<?xml version="1.0" encoding="utf-8" standalone="no"?>
<device schemaVersion="1.1" xmlns:xs="http://www.w3.org/2001/XMLSchema-instance" noNamespaceSchemaLocation="CMSIS-SVD.xsd">
  <vendor>Puya</vendor>
  <vendorID>Puya</vendorID>
  <name>PY32T090xx</name>
  <series>PY32T0</series>
  <version>1.0.0</version>
  <description>Arm 32-bit Cortex-M0+ Microcontroller based device, CPU clock up to 48 MHz.</description>
  <cpu>
    <name>CM0+</name>
    <revision>r0p1</revision>
    <endian>little</endian>
    <mpuPresent>false</mpuPresent>
    <fpuPresent>false</fpuPresent>
    <nvicPrioBits>4</nvicPrioBits>
    <vendorSystickConfig>false</vendorSystickConfig>
  </cpu>
  <addressUnitBits>8</addressUnitBits>
  <width>32</width>
  <size>32</size>
  <access>read-write</access>
  <resetValue>0x0</resetValue>
  <resetMask>0xFFFFFFFF</resetMask>
  <peripherals>
    <peripheral>
      <name>ADC</name>
      <description>Analog to Digital Converter</description>
      <baseAddress>0x40012400</baseAddress>
      <addressBlock>
        <offset>0x0</offset>
        <size>0x400</size>
        <usage>registers</usage>
      </addressBlock>
      <interrupt>
        <name>ADC_COMP</name>
        <description>ADC and COMP Interrupt through EXTI Lines 17 and 18</description>
        <value>12</value>
      </interrupt>
      <registers>
        <register>
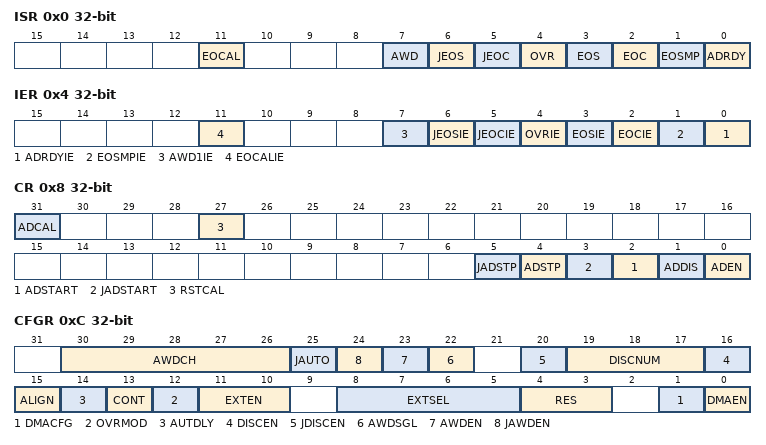
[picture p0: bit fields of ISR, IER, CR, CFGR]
          <name>ISR</name>
          <addressOffset>0x0</addressOffset>
          <fields>
            <field>
              <name>ADRDY</name>
              <bitRange>[0:0]</bitRange>
            </field>
            <field>
              <name>EOSMP</name>
              <bitRange>[1:1]</bitRange>
            </field>
            <field>
              <name>EOC</name>
              <bitRange>[2:2]</bitRange>
            </field>
            <field>
              <name>EOS</name>
              <bitRange>[3:3]</bitRange>
            </field>
            <field>
              <name>OVR</name>
              <bitRange>[4:4]</bitRange>
            </field>
            <field>
              <name>JEOC</name>
              <bitRange>[5:5]</bitRange>
            </field>
            <field>
              <name>JEOS</name>
              <bitRange>[6:6]</bitRange>
            </field>
            <field>
              <name>AWD</name>
              <bitRange>[7:7]</bitRange>
            </field>
             <field>
              <name>EOCAL</name>
              <bitRange>[11:11]</bitRange>
            </field>           
          </fields>
        </register>
        <register>
          <name>IER</name>
          <addressOffset>0x4</addressOffset>
          <fields>
            <field>
              <name>ADRDYIE</name>
              <bitRange>[0:0]</bitRange>
            </field>
            <field>
              <name>EOSMPIE</name>
              <bitRange>[1:1]</bitRange>
            </field>
            <field>
              <name>EOCIE</name>
              <bitRange>[2:2]</bitRange>
            </field>
            <field>
              <name>EOSIE</name>
              <bitRange>[3:3]</bitRange>
            </field>
            <field>
              <name>OVRIE</name>
              <bitRange>[4:4]</bitRange>
            </field>
            <field>
              <name>JEOCIE</name>
              <bitRange>[5:5]</bitRange>
            </field>
            <field>
              <name>JEOSIE</name>
              <bitRange>[6:6]</bitRange>
            </field>
            <field>
              <name>AWD1IE</name>
              <bitRange>[7:7]</bitRange>
            </field>
            <field>
              <name>EOCALIE</name>
              <bitRange>[11:11]</bitRange>
            </field>
          </fields>
        </register>
        <register>
          <name>CR</name>
          <addressOffset>0x8</addressOffset>
          <fields>
            <field>
              <name>ADEN</name>
              <bitRange>[0:0]</bitRange>
            </field>
            <field>
              <name>ADDIS</name>
              <bitRange>[1:1]</bitRange>
            </field>
            <field>
              <name>ADSTART</name>
              <bitRange>[2:2]</bitRange>
            </field>
            <field>
              <name>JADSTART</name>
              <bitRange>[3:3]</bitRange>
            </field>
            <field>
              <name>ADSTP</name>
              <bitRange>[4:4]</bitRange>
            </field>
            <field>
              <name>JADSTP</name>
              <bitRange>[5:5]</bitRange>
            </field>
            <field>
              <name>RSTCAL</name>
              <bitRange>[27:27]</bitRange>
            </field>
            <field>
              <name>ADCAL</name>
              <bitRange>[31:31]</bitRange>
            </field>
          </fields>
        </register>
        <register>
          <name>CFGR</name>
          <addressOffset>0xC</addressOffset>
          <fields>
            <field>
              <name>DMAEN</name>
              <bitRange>[0:0]</bitRange>
            </field>
            <field>
              <name>DMACFG</name>
              <bitRange>[1:1]</bitRange>
            </field>
            <field>
              <name>RES</name>
              <bitRange>[4:3]</bitRange>
              <enumeratedValues>
                <enumeratedValue>
                  <name>0</name>
                  <value>1</value>
                </enumeratedValue>
                <enumeratedValue>
                  <name>1</name>
                  <value>2</value>
                </enumeratedValue>
              </enumeratedValues>
            </field>
            <field>
              <name>EXTSEL</name>
              <bitRange>[8:5]</bitRange>
              <enumeratedValues>
                <enumeratedValue>
                  <name>0</name>
                  <value>1</value>
                </enumeratedValue>
                <enumeratedValue>
                  <name>1</name>
                  <value>2</value>
                </enumeratedValue>
                <enumeratedValue>
                  <name>2</name>
                  <value>4</value>
                </enumeratedValue>
                <enumeratedValue>
                  <name>3</name>
                  <value>8</value>
                </enumeratedValue>
              </enumeratedValues>
            </field>
            <field>
              <name>EXTEN</name>
              <bitRange>[11:10]</bitRange>
              <enumeratedValues>
                <enumeratedValue>
                  <name>0</name>
                  <value>1</value>
                </enumeratedValue>
                <enumeratedValue>
                  <name>1</name>
                  <value>2</value>
                </enumeratedValue>
              </enumeratedValues>
            </field>
            <field>
              <name>OVRMOD</name>
              <bitRange>[12:12]</bitRange>
            </field>
            <field>
              <name>CONT</name>
              <bitRange>[13:13]</bitRange>
            </field>
            <field>
              <name>AUTDLY</name>
              <bitRange>[14:14]</bitRange>
            </field>
            <field>
              <name>ALIGN</name>
              <bitRange>[15:15]</bitRange>
            </field>
            <field>
              <name>DISCEN</name>
              <bitRange>[16:16]</bitRange>
            </field>
            <field>
              <name>DISCNUM</name>
              <bitRange>[19:17]</bitRange>
              <enumeratedValues>
                <enumeratedValue>
                  <name>0</name>
                  <value>1</value>
                </enumeratedValue>
                <enumeratedValue>
                  <name>1</name>
                  <value>2</value>
                </enumeratedValue>
                <enumeratedValue>
                  <name>2</name>
                  <value>4</value>
                </enumeratedValue>
              </enumeratedValues>
            </field>
            <field>
              <name>JDISCEN</name>
              <bitRange>[20:20]</bitRange>
            </field>
            <field>
              <name>AWDSGL</name>
              <bitRange>[22:22]</bitRange>
            </field>
            <field>
              <name>AWDEN</name>
              <bitRange>[23:23]</bitRange>
            </field>
            <field>
              <name>JAWDEN</name>
              <bitRange>[24:24]</bitRange>
            </field>
            <field>
              <name>JAUTO</name>
              <bitRange>[25:25]</bitRange>
            </field>
            <field>
              <name>AWDCH</name>
              <bitRange>[30:26]</bitRange>
            </field>
          </fields>
        </register>
        <register>
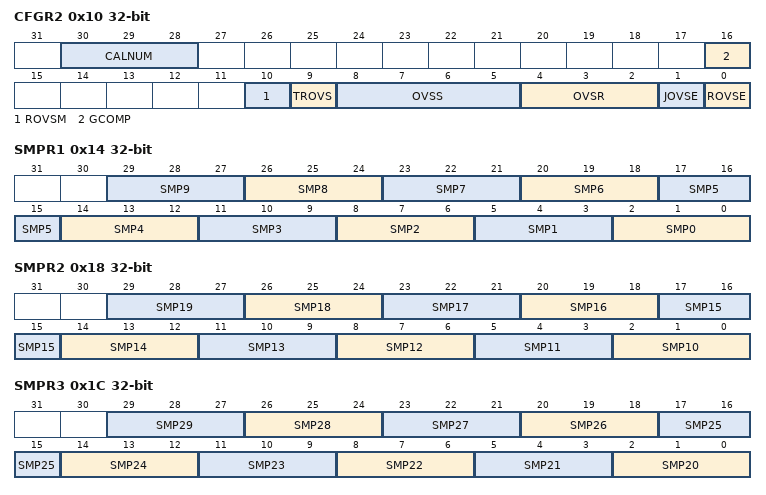
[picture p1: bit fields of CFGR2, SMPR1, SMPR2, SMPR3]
          <name>CFGR2</name>
          <addressOffset>0x10</addressOffset>
          <fields>
            <field>
              <name>ROVSE</name>
              <bitRange>[0:0]</bitRange>
            </field>
            <field>
              <name>JOVSE</name>
              <bitRange>[1:1]</bitRange>
            </field>
            <field>
              <name>OVSR</name>
              <bitRange>[4:2]</bitRange>
              <enumeratedValues>
                <enumeratedValue>
                  <name>0</name>
                  <value>1</value>
                </enumeratedValue>
                <enumeratedValue>
                  <name>1</name>
                  <value>2</value>
                </enumeratedValue>
                <enumeratedValue>
                  <name>2</name>
                  <value>4</value>
                </enumeratedValue>
              </enumeratedValues>
            </field>
            <field>
              <name>OVSS</name>
              <bitRange>[8:5]</bitRange>
              <enumeratedValues>
                <enumeratedValue>
                  <name>0</name>
                  <value>1</value>
                </enumeratedValue>
                <enumeratedValue>
                  <name>1</name>
                  <value>2</value>
                </enumeratedValue>
                <enumeratedValue>
                  <name>2</name>
                  <value>4</value>
                </enumeratedValue>
                <enumeratedValue>
                  <name>3</name>
                  <value>8</value>
                </enumeratedValue>
              </enumeratedValues>
            </field>
            <field>
              <name>TROVS</name>
              <bitRange>[9:9]</bitRange>
            </field>
            <field>
              <name>ROVSM</name>
              <bitRange>[10:10]</bitRange>
            </field>
            <field>
              <name>GCOMP</name>
              <bitRange>[16:16]</bitRange>
            </field>
            <field>
              <name>CALNUM</name>
              <bitRange>[30:28]</bitRange>
              <enumeratedValues>
                <enumeratedValue>
                  <name>0</name>
                  <value>1</value>
                </enumeratedValue>
                <enumeratedValue>
                  <name>1</name>
                  <value>2</value>
                </enumeratedValue>
                <enumeratedValue>
                  <name>2</name>
                  <value>4</value>
                </enumeratedValue>
              </enumeratedValues>
            </field>
          </fields>
        </register>
        <register>
          <name>SMPR1</name>
          <description>desc SMPR1</description>
          <addressOffset>0x14</addressOffset>
          <fields>
            <field>
              <name>SMP0</name>
              <bitRange>[2:0]</bitRange>
              <enumeratedValues>
                <enumeratedValue>
                  <name>0</name>
                  <value>1</value>
                </enumeratedValue>
                <enumeratedValue>
                  <name>1</name>
                  <value>2</value>
                </enumeratedValue>
                <enumeratedValue>
                  <name>2</name>
                  <value>4</value>
                </enumeratedValue>
              </enumeratedValues>
            </field>
            <field>
              <name>SMP1</name>
              <bitRange>[5:3]</bitRange>
              <enumeratedValues>
                <enumeratedValue>
                  <name>0</name>
                  <value>1</value>
                </enumeratedValue>
                <enumeratedValue>
                  <name>1</name>
                  <value>2</value>
                </enumeratedValue>
                <enumeratedValue>
                  <name>2</name>
                  <value>4</value>
                </enumeratedValue>
              </enumeratedValues>
            </field>
            <field>
              <name>SMP2</name>
              <bitRange>[8:6]</bitRange>
              <enumeratedValues>
                <enumeratedValue>
                  <name>0</name>
                  <value>1</value>
                </enumeratedValue>
                <enumeratedValue>
                  <name>1</name>
                  <value>2</value>
                </enumeratedValue>
                <enumeratedValue>
                  <name>2</name>
                  <value>4</value>
                </enumeratedValue>
              </enumeratedValues>
            </field>
            <field>
              <name>SMP3</name>
              <bitRange>[11:9]</bitRange>
              <enumeratedValues>
                <enumeratedValue>
                  <name>0</name>
                  <value>1</value>
                </enumeratedValue>
                <enumeratedValue>
                  <name>1</name>
                  <value>2</value>
                </enumeratedValue>
                <enumeratedValue>
                  <name>2</name>
                  <value>4</value>
                </enumeratedValue>
              </enumeratedValues>
            </field>
            <field>
              <name>SMP4</name>
              <bitRange>[14:12]</bitRange>
              <enumeratedValues>
                <enumeratedValue>
                  <name>0</name>
                  <value>1</value>
                </enumeratedValue>
                <enumeratedValue>
                  <name>1</name>
                  <value>2</value>
                </enumeratedValue>
                <enumeratedValue>
                  <name>2</name>
                  <value>4</value>
                </enumeratedValue>
              </enumeratedValues>
            </field>
            <field>
              <name>SMP5</name>
              <bitRange>[17:15]</bitRange>
              <enumeratedValues>
                <enumeratedValue>
                  <name>0</name>
                  <value>1</value>
                </enumeratedValue>
                <enumeratedValue>
                  <name>1</name>
                  <value>2</value>
                </enumeratedValue>
                <enumeratedValue>
                  <name>2</name>
                  <value>4</value>
                </enumeratedValue>
              </enumeratedValues>
            </field>
            <field>
              <name>SMP6</name>
              <bitRange>[20:18]</bitRange>
              <enumeratedValues>
                <enumeratedValue>
                  <name>0</name>
                  <value>1</value>
                </enumeratedValue>
                <enumeratedValue>
                  <name>1</name>
                  <value>2</value>
                </enumeratedValue>
                <enumeratedValue>
                  <name>2</name>
                  <value>4</value>
                </enumeratedValue>
              </enumeratedValues>
            </field>
            <field>
              <name>SMP7</name>
              <bitRange>[23:21]</bitRange>
              <enumeratedValues>
                <enumeratedValue>
                  <name>0</name>
                  <value>1</value>
                </enumeratedValue>
                <enumeratedValue>
                  <name>1</name>
                  <value>2</value>
                </enumeratedValue>
                <enumeratedValue>
                  <name>2</name>
                  <value>4</value>
                </enumeratedValue>
              </enumeratedValues>
            </field>
            <field>
              <name>SMP8</name>
              <bitRange>[26:24]</bitRange>
              <enumeratedValues>
                <enumeratedValue>
                  <name>0</name>
                  <value>1</value>
                </enumeratedValue>
                <enumeratedValue>
                  <name>1</name>
                  <value>2</value>
                </enumeratedValue>
                <enumeratedValue>
                  <name>2</name>
                  <value>4</value>
                </enumeratedValue>
              </enumeratedValues>
            </field>
            <field>
              <name>SMP9</name>
              <bitRange>[29:27]</bitRange>
              <enumeratedValues>
                <enumeratedValue>
                  <name>0</name>
                  <value>1</value>
                </enumeratedValue>
                <enumeratedValue>
                  <name>1</name>
                  <value>2</value>
                </enumeratedValue>
                <enumeratedValue>
                  <name>2</name>
                  <value>4</value>
                </enumeratedValue>
              </enumeratedValues>
            </field>
          </fields>
        </register>
        <register>
          <name>SMPR2</name>
          <description>desc SMPR2</description>
          <addressOffset>0x18</addressOffset>
          <fields>
            <field>
              <name>SMP10</name>
              <bitRange>[2:0]</bitRange>
              <enumeratedValues>
                <enumeratedValue>
                  <name>0</name>
                  <value>1</value>
                </enumeratedValue>
                <enumeratedValue>
                  <name>1</name>
                  <value>2</value>
                </enumeratedValue>
                <enumeratedValue>
                  <name>2</name>
                  <value>4</value>
                </enumeratedValue>
              </enumeratedValues>
            </field>
            <field>
              <name>SMP11</name>
              <bitRange>[5:3]</bitRange>
              <enumeratedValues>
                <enumeratedValue>
                  <name>0</name>
                  <value>1</value>
                </enumeratedValue>
                <enumeratedValue>
                  <name>1</name>
                  <value>2</value>
                </enumeratedValue>
                <enumeratedValue>
                  <name>2</name>
                  <value>4</value>
                </enumeratedValue>
              </enumeratedValues>
            </field>
            <field>
              <name>SMP12</name>
              <bitRange>[8:6]</bitRange>
              <enumeratedValues>
                <enumeratedValue>
                  <name>0</name>
                  <value>1</value>
                </enumeratedValue>
                <enumeratedValue>
                  <name>1</name>
                  <value>2</value>
                </enumeratedValue>
                <enumeratedValue>
                  <name>2</name>
                  <value>4</value>
                </enumeratedValue>
              </enumeratedValues>
            </field>
            <field>
              <name>SMP13</name>
              <bitRange>[11:9]</bitRange>
              <enumeratedValues>
                <enumeratedValue>
                  <name>0</name>
                  <value>1</value>
                </enumeratedValue>
                <enumeratedValue>
                  <name>1</name>
                  <value>2</value>
                </enumeratedValue>
                <enumeratedValue>
                  <name>2</name>
                  <value>4</value>
                </enumeratedValue>
              </enumeratedValues>
            </field>
            <field>
              <name>SMP14</name>
              <bitRange>[14:12]</bitRange>
              <enumeratedValues>
                <enumeratedValue>
                  <name>0</name>
                  <value>1</value>
                </enumeratedValue>
                <enumeratedValue>
                  <name>1</name>
                  <value>2</value>
                </enumeratedValue>
                <enumeratedValue>
                  <name>2</name>
                  <value>4</value>
                </enumeratedValue>
              </enumeratedValues>
            </field>
            <field>
              <name>SMP15</name>
              <bitRange>[17:15]</bitRange>
              <enumeratedValues>
                <enumeratedValue>
                  <name>0</name>
                  <value>1</value>
                </enumeratedValue>
                <enumeratedValue>
                  <name>1</name>
                  <value>2</value>
                </enumeratedValue>
                <enumeratedValue>
                  <name>2</name>
                  <value>4</value>
                </enumeratedValue>
              </enumeratedValues>
            </field>
            <field>
              <name>SMP16</name>
              <bitRange>[20:18]</bitRange>
              <enumeratedValues>
                <enumeratedValue>
                  <name>0</name>
                  <value>1</value>
                </enumeratedValue>
                <enumeratedValue>
                  <name>1</name>
                  <value>2</value>
                </enumeratedValue>
                <enumeratedValue>
                  <name>2</name>
                  <value>4</value>
                </enumeratedValue>
              </enumeratedValues>
            </field>
            <field>
              <name>SMP17</name>
              <bitRange>[23:21]</bitRange>
              <enumeratedValues>
                <enumeratedValue>
                  <name>0</name>
                  <value>1</value>
                </enumeratedValue>
                <enumeratedValue>
                  <name>1</name>
                  <value>2</value>
                </enumeratedValue>
                <enumeratedValue>
                  <name>2</name>
                  <value>4</value>
                </enumeratedValue>
              </enumeratedValues>
            </field>
            <field>
              <name>SMP18</name>
              <bitRange>[26:24]</bitRange>
              <enumeratedValues>
                <enumeratedValue>
                  <name>0</name>
                  <value>1</value>
                </enumeratedValue>
                <enumeratedValue>
                  <name>1</name>
                  <value>2</value>
                </enumeratedValue>
                <enumeratedValue>
                  <name>2</name>
                  <value>4</value>
                </enumeratedValue>
              </enumeratedValues>
            </field>
            <field>
              <name>SMP19</name>
              <bitRange>[29:27]</bitRange>
              <enumeratedValues>
                <enumeratedValue>
                  <name>0</name>
                  <value>1</value>
                </enumeratedValue>
                <enumeratedValue>
                  <name>1</name>
                  <value>2</value>
                </enumeratedValue>
                <enumeratedValue>
                  <name>2</name>
                  <value>4</value>
                </enumeratedValue>
              </enumeratedValues>
            </field>
          </fields>
        </register>
        <register>
          <name>SMPR3</name>
          <description>desc SMPR2</description>
          <addressOffset>0x1C</addressOffset>
          <fields>
            <field>
              <name>SMP20</name>
              <bitRange>[2:0]</bitRange>
              <enumeratedValues>
                <enumeratedValue>
                  <name>0</name>
                  <value>1</value>
                </enumeratedValue>
                <enumeratedValue>
                  <name>1</name>
                  <value>2</value>
                </enumeratedValue>
                <enumeratedValue>
                  <name>2</name>
                  <value>4</value>
                </enumeratedValue>
              </enumeratedValues>
            </field>
            <field>
              <name>SMP21</name>
              <bitRange>[5:3]</bitRange>
              <enumeratedValues>
                <enumeratedValue>
                  <name>0</name>
                  <value>1</value>
                </enumeratedValue>
                <enumeratedValue>
                  <name>1</name>
                  <value>2</value>
                </enumeratedValue>
                <enumeratedValue>
                  <name>2</name>
                  <value>4</value>
                </enumeratedValue>
              </enumeratedValues>
            </field>
            <field>
              <name>SMP22</name>
              <bitRange>[8:6]</bitRange>
              <enumeratedValues>
                <enumeratedValue>
                  <name>0</name>
                  <value>1</value>
                </enumeratedValue>
                <enumeratedValue>
                  <name>1</name>
                  <value>2</value>
                </enumeratedValue>
                <enumeratedValue>
                  <name>2</name>
                  <value>4</value>
                </enumeratedValue>
              </enumeratedValues>
            </field>
            <field>
              <name>SMP23</name>
              <bitRange>[11:9]</bitRange>
              <enumeratedValues>
                <enumeratedValue>
                  <name>0</name>
                  <value>1</value>
                </enumeratedValue>
                <enumeratedValue>
                  <name>1</name>
                  <value>2</value>
                </enumeratedValue>
                <enumeratedValue>
                  <name>2</name>
                  <value>4</value>
                </enumeratedValue>
              </enumeratedValues>
            </field>
            <field>
              <name>SMP24</name>
              <bitRange>[14:12]</bitRange>
              <enumeratedValues>
                <enumeratedValue>
                  <name>0</name>
                  <value>1</value>
                </enumeratedValue>
                <enumeratedValue>
                  <name>1</name>
                  <value>2</value>
                </enumeratedValue>
                <enumeratedValue>
                  <name>2</name>
                  <value>4</value>
                </enumeratedValue>
              </enumeratedValues>
            </field>
            <field>
              <name>SMP25</name>
              <bitRange>[17:15]</bitRange>
              <enumeratedValues>
                <enumeratedValue>
                  <name>0</name>
                  <value>1</value>
                </enumeratedValue>
                <enumeratedValue>
                  <name>1</name>
                  <value>2</value>
                </enumeratedValue>
                <enumeratedValue>
                  <name>2</name>
                  <value>4</value>
                </enumeratedValue>
              </enumeratedValues>
            </field>
            <field>
              <name>SMP26</name>
              <bitRange>[20:18]</bitRange>
              <enumeratedValues>
                <enumeratedValue>
                  <name>0</name>
                  <value>1</value>
                </enumeratedValue>
                <enumeratedValue>
                  <name>1</name>
                  <value>2</value>
                </enumeratedValue>
                <enumeratedValue>
                  <name>2</name>
                  <value>4</value>
                </enumeratedValue>
              </enumeratedValues>
            </field>
            <field>
              <name>SMP27</name>
              <bitRange>[23:21]</bitRange>
              <enumeratedValues>
                <enumeratedValue>
                  <name>0</name>
                  <value>1</value>
                </enumeratedValue>
                <enumeratedValue>
                  <name>1</name>
                  <value>2</value>
                </enumeratedValue>
                <enumeratedValue>
                  <name>2</name>
                  <value>4</value>
                </enumeratedValue>
              </enumeratedValues>
            </field>
            <field>
              <name>SMP28</name>
              <bitRange>[26:24]</bitRange>
              <enumeratedValues>
                <enumeratedValue>
                  <name>0</name>
                  <value>1</value>
                </enumeratedValue>
                <enumeratedValue>
                  <name>1</name>
                  <value>2</value>
                </enumeratedValue>
                <enumeratedValue>
                  <name>2</name>
                  <value>4</value>
                </enumeratedValue>
              </enumeratedValues>
            </field>
            <field>
              <name>SMP29</name>
              <bitRange>[29:27]</bitRange>
              <enumeratedValues>
                <enumeratedValue>
                  <name>0</name>
                  <value>1</value>
                </enumeratedValue>
                <enumeratedValue>
                  <name>1</name>
                  <value>2</value>
                </enumeratedValue>
                <enumeratedValue>
                  <name>2</name>
                  <value>4</value>
                </enumeratedValue>
              </enumeratedValues>
            </field>
          </fields>
        </register>
        <register>
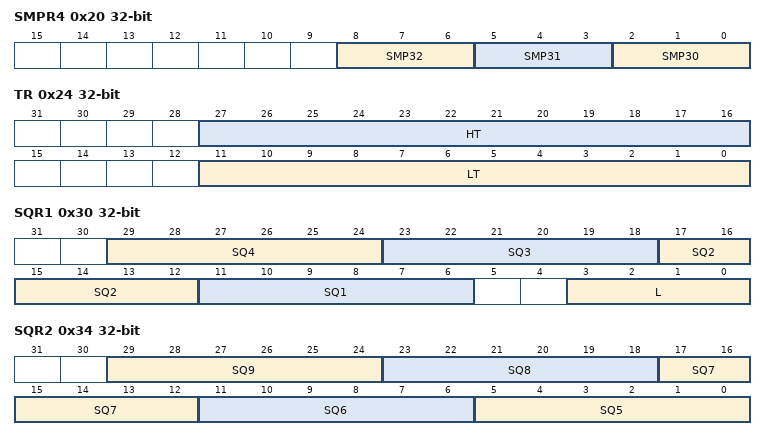
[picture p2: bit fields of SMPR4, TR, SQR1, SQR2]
          <name>SMPR4</name>
          <addressOffset>0x20</addressOffset>
          <fields>
            <field>
              <name>SMP30</name>
              <bitRange>[2:0]</bitRange>
              <enumeratedValues>
                <enumeratedValue>
                  <name>0</name>
                  <value>1</value>
                </enumeratedValue>
                <enumeratedValue>
                  <name>1</name>
                  <value>2</value>
                </enumeratedValue>
                <enumeratedValue>
                  <name>2</name>
                  <value>4</value>
                </enumeratedValue>
              </enumeratedValues>
            </field>
            <field>
              <name>SMP31</name>
              <bitRange>[5:3]</bitRange>
              <enumeratedValues>
                <enumeratedValue>
                  <name>0</name>
                  <value>1</value>
                </enumeratedValue>
                <enumeratedValue>
                  <name>1</name>
                  <value>2</value>
                </enumeratedValue>
                <enumeratedValue>
                  <name>2</name>
                  <value>4</value>
                </enumeratedValue>
              </enumeratedValues>
            </field>
            <field>
              <name>SMP32</name>
              <bitRange>[8:6]</bitRange>
            </field>
          </fields>
        </register>
        <register>
          <name>TR</name>
          <addressOffset>0x24</addressOffset>
          <fields>
            <field>
              <name>LT</name>
              <bitRange>[11:0]</bitRange>
            </field>
            <field>
              <name>HT</name>
              <bitRange>[27:16]</bitRange>
            </field>
          </fields>
        </register>
        <register>
          <name>SQR1</name>
          <description>desc SQR1</description>
          <addressOffset>0x30</addressOffset>
          <fields>
            <field>
              <name>L</name>
              <bitRange>[3:0]</bitRange>
              <enumeratedValues>
                <enumeratedValue>
                  <name>0</name>
                  <value>1</value>
                </enumeratedValue>
                <enumeratedValue>
                  <name>1</name>
                  <value>2</value>
                </enumeratedValue>
                <enumeratedValue>
                  <name>2</name>
                  <value>4</value>
                </enumeratedValue>
                <enumeratedValue>
                  <name>3</name>
                  <value>8</value>
                </enumeratedValue>
              </enumeratedValues>
            </field>
            <field>
              <name>SQ1</name>
              <bitRange>[11:6]</bitRange>
              <enumeratedValues>
                <enumeratedValue>
                  <name>0</name>
                  <value>1</value>
                </enumeratedValue>
                <enumeratedValue>
                  <name>1</name>
                  <value>2</value>
                </enumeratedValue>
                <enumeratedValue>
                  <name>2</name>
                  <value>4</value>
                </enumeratedValue>
                <enumeratedValue>
                  <name>3</name>
                  <value>8</value>
                </enumeratedValue>
                <enumeratedValue>
                  <name>4</name>
                  <value>16</value>
                </enumeratedValue>
                <enumeratedValue>
                  <name>5</name>
                  <value>32</value>
                </enumeratedValue>
              </enumeratedValues>
            </field>
            <field>
              <name>SQ2</name>
              <bitRange>[17:12]</bitRange>
              <enumeratedValues>
                <enumeratedValue>
                  <name>0</name>
                  <value>1</value>
                </enumeratedValue>
                <enumeratedValue>
                  <name>1</name>
                  <value>2</value>
                </enumeratedValue>
                <enumeratedValue>
                  <name>2</name>
                  <value>4</value>
                </enumeratedValue>
                <enumeratedValue>
                  <name>3</name>
                  <value>8</value>
                </enumeratedValue>
                <enumeratedValue>
                  <name>4</name>
                  <value>16</value>
                </enumeratedValue>
                <enumeratedValue>
                  <name>5</name>
                  <value>32</value>
                </enumeratedValue>
              </enumeratedValues>
            </field>
            <field>
              <name>SQ3</name>
              <bitRange>[23:18]</bitRange>
              <enumeratedValues>
                <enumeratedValue>
                  <name>0</name>
                  <value>1</value>
                </enumeratedValue>
                <enumeratedValue>
                  <name>1</name>
                  <value>2</value>
                </enumeratedValue>
                <enumeratedValue>
                  <name>2</name>
                  <value>4</value>
                </enumeratedValue>
                <enumeratedValue>
                  <name>3</name>
                  <value>8</value>
                </enumeratedValue>
                <enumeratedValue>
                  <name>4</name>
                  <value>16</value>
                </enumeratedValue>
                <enumeratedValue>
                  <name>5</name>
                  <value>32</value>
                </enumeratedValue>
              </enumeratedValues>
            </field>
            <field>
              <name>SQ4</name>
              <bitRange>[29:24]</bitRange>
              <enumeratedValues>
                <enumeratedValue>
                  <name>0</name>
                  <value>1</value>
                </enumeratedValue>
                <enumeratedValue>
                  <name>1</name>
                  <value>2</value>
                </enumeratedValue>
                <enumeratedValue>
                  <name>2</name>
                  <value>4</value>
                </enumeratedValue>
                <enumeratedValue>
                  <name>3</name>
                  <value>8</value>
                </enumeratedValue>
                <enumeratedValue>
                  <name>4</name>
                  <value>16</value>
                </enumeratedValue>
                <enumeratedValue>
                  <name>5</name>
                  <value>32</value>
                </enumeratedValue>
              </enumeratedValues>
            </field>
          </fields>
        </register>
        <register>
          <name>SQR2</name>
          <description>desc SQR2</description>
          <addressOffset>0x34</addressOffset>
          <fields>
            <field>
              <name>SQ5</name>
              <bitRange>[5:0]</bitRange>
              <enumeratedValues>
                <enumeratedValue>
                  <name>0</name>
                  <value>1</value>
                </enumeratedValue>
                <enumeratedValue>
                  <name>1</name>
                  <value>2</value>
                </enumeratedValue>
                <enumeratedValue>
                  <name>2</name>
                  <value>4</value>
                </enumeratedValue>
                <enumeratedValue>
                  <name>3</name>
                  <value>8</value>
                </enumeratedValue>
                <enumeratedValue>
                  <name>4</name>
                  <value>16</value>
                </enumeratedValue>
                <enumeratedValue>
                  <name>5</name>
                  <value>32</value>
                </enumeratedValue>
              </enumeratedValues>
            </field>
            <field>
              <name>SQ6</name>
              <bitRange>[11:6]</bitRange>
              <enumeratedValues>
                <enumeratedValue>
                  <name>0</name>
                  <value>1</value>
                </enumeratedValue>
                <enumeratedValue>
                  <name>1</name>
                  <value>2</value>
                </enumeratedValue>
                <enumeratedValue>
                  <name>2</name>
                  <value>4</value>
                </enumeratedValue>
                <enumeratedValue>
                  <name>3</name>
                  <value>8</value>
                </enumeratedValue>
                <enumeratedValue>
                  <name>4</name>
                  <value>16</value>
                </enumeratedValue>
                <enumeratedValue>
                  <name>5</name>
                  <value>32</value>
                </enumeratedValue>
              </enumeratedValues>
            </field>
            <field>
              <name>SQ7</name>
              <bitRange>[17:12]</bitRange>
              <enumeratedValues>
                <enumeratedValue>
                  <name>0</name>
                  <value>1</value>
                </enumeratedValue>
                <enumeratedValue>
                  <name>1</name>
                  <value>2</value>
                </enumeratedValue>
                <enumeratedValue>
                  <name>2</name>
                  <value>4</value>
                </enumeratedValue>
                <enumeratedValue>
                  <name>3</name>
                  <value>8</value>
                </enumeratedValue>
                <enumeratedValue>
                  <name>4</name>
                  <value>16</value>
                </enumeratedValue>
                <enumeratedValue>
                  <name>5</name>
                  <value>32</value>
                </enumeratedValue>
              </enumeratedValues>
            </field>
            <field>
              <name>SQ8</name>
              <bitRange>[23:18]</bitRange>
              <enumeratedValues>
                <enumeratedValue>
                  <name>0</name>
                  <value>1</value>
                </enumeratedValue>
                <enumeratedValue>
                  <name>1</name>
                  <value>2</value>
                </enumeratedValue>
                <enumeratedValue>
                  <name>2</name>
                  <value>4</value>
                </enumeratedValue>
                <enumeratedValue>
                  <name>3</name>
                  <value>8</value>
                </enumeratedValue>
                <enumeratedValue>
                  <name>4</name>
                  <value>16</value>
                </enumeratedValue>
                <enumeratedValue>
                  <name>5</name>
                  <value>32</value>
                </enumeratedValue>
              </enumeratedValues>
            </field>
            <field>
              <name>SQ9</name>
              <bitRange>[29:24]</bitRange>
              <enumeratedValues>
                <enumeratedValue>
                  <name>0</name>
                  <value>1</value>
                </enumeratedValue>
                <enumeratedValue>
                  <name>1</name>
                  <value>2</value>
                </enumeratedValue>
                <enumeratedValue>
                  <name>2</name>
                  <value>4</value>
                </enumeratedValue>
                <enumeratedValue>
                  <name>3</name>
                  <value>8</value>
                </enumeratedValue>
                <enumeratedValue>
                  <name>4</name>
                  <value>16</value>
                </enumeratedValue>
                <enumeratedValue>
                  <name>5</name>
                  <value>32</value>
                </enumeratedValue>
              </enumeratedValues>
            </field>
          </fields>
        </register>
        <register>
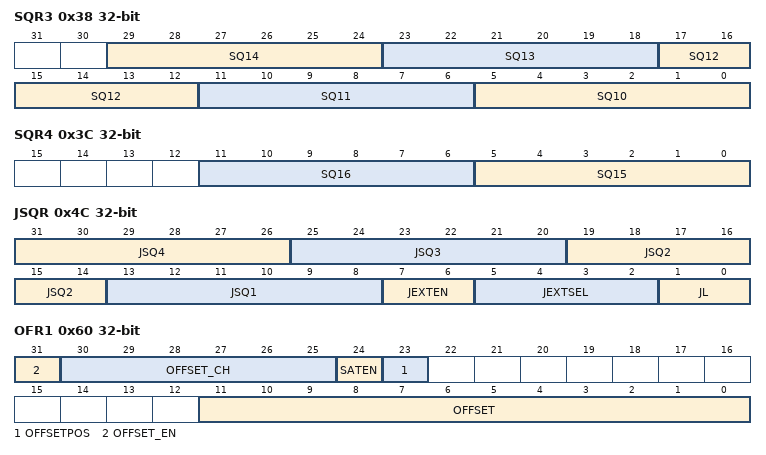
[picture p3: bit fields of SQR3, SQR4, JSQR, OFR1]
          <name>SQR3</name>
          <description>desc SQR3</description>
          <addressOffset>0x38</addressOffset>
          <fields>
            <field>
              <name>SQ10</name>
              <bitRange>[5:0]</bitRange>
              <enumeratedValues>
                <enumeratedValue>
                  <name>0</name>
                  <value>1</value>
                </enumeratedValue>
                <enumeratedValue>
                  <name>1</name>
                  <value>2</value>
                </enumeratedValue>
                <enumeratedValue>
                  <name>2</name>
                  <value>4</value>
                </enumeratedValue>
                <enumeratedValue>
                  <name>3</name>
                  <value>8</value>
                </enumeratedValue>
                <enumeratedValue>
                  <name>4</name>
                  <value>16</value>
                </enumeratedValue>
                <enumeratedValue>
                  <name>5</name>
                  <value>32</value>
                </enumeratedValue>
              </enumeratedValues>
            </field>
            <field>
              <name>SQ11</name>
              <bitRange>[11:6]</bitRange>
              <enumeratedValues>
                <enumeratedValue>
                  <name>0</name>
                  <value>1</value>
                </enumeratedValue>
                <enumeratedValue>
                  <name>1</name>
                  <value>2</value>
                </enumeratedValue>
                <enumeratedValue>
                  <name>2</name>
                  <value>4</value>
                </enumeratedValue>
                <enumeratedValue>
                  <name>3</name>
                  <value>8</value>
                </enumeratedValue>
                <enumeratedValue>
                  <name>4</name>
                  <value>16</value>
                </enumeratedValue>
                <enumeratedValue>
                  <name>5</name>
                  <value>32</value>
                </enumeratedValue>
              </enumeratedValues>
            </field>
            <field>
              <name>SQ12</name>
              <bitRange>[17:12]</bitRange>
              <enumeratedValues>
                <enumeratedValue>
                  <name>0</name>
                  <value>1</value>
                </enumeratedValue>
                <enumeratedValue>
                  <name>1</name>
                  <value>2</value>
                </enumeratedValue>
                <enumeratedValue>
                  <name>2</name>
                  <value>4</value>
                </enumeratedValue>
                <enumeratedValue>
                  <name>3</name>
                  <value>8</value>
                </enumeratedValue>
                <enumeratedValue>
                  <name>4</name>
                  <value>16</value>
                </enumeratedValue>
                <enumeratedValue>
                  <name>5</name>
                  <value>32</value>
                </enumeratedValue>
              </enumeratedValues>
            </field>
            <field>
              <name>SQ13</name>
              <bitRange>[23:18]</bitRange>
              <enumeratedValues>
                <enumeratedValue>
                  <name>0</name>
                  <value>1</value>
                </enumeratedValue>
                <enumeratedValue>
                  <name>1</name>
                  <value>2</value>
                </enumeratedValue>
                <enumeratedValue>
                  <name>2</name>
                  <value>4</value>
                </enumeratedValue>
                <enumeratedValue>
                  <name>3</name>
                  <value>8</value>
                </enumeratedValue>
                <enumeratedValue>
                  <name>4</name>
                  <value>16</value>
                </enumeratedValue>
                <enumeratedValue>
                  <name>5</name>
                  <value>32</value>
                </enumeratedValue>
              </enumeratedValues>
            </field>
            <field>
              <name>SQ14</name>
              <bitRange>[29:24]</bitRange>
              <enumeratedValues>
                <enumeratedValue>
                  <name>0</name>
                  <value>1</value>
                </enumeratedValue>
                <enumeratedValue>
                  <name>1</name>
                  <value>2</value>
                </enumeratedValue>
                <enumeratedValue>
                  <name>2</name>
                  <value>4</value>
                </enumeratedValue>
                <enumeratedValue>
                  <name>3</name>
                  <value>8</value>
                </enumeratedValue>
                <enumeratedValue>
                  <name>4</name>
                  <value>16</value>
                </enumeratedValue>
                <enumeratedValue>
                  <name>5</name>
                  <value>32</value>
                </enumeratedValue>
              </enumeratedValues>
            </field>
          </fields>
        </register>
        <register>
          <name>SQR4</name>
          <addressOffset>0x3C</addressOffset>
          <fields>
            <field>
              <name>SQ15</name>
              <bitRange>[5:0]</bitRange>
              <enumeratedValues>
                <enumeratedValue>
                  <name>0</name>
                  <value>1</value>
                </enumeratedValue>
                <enumeratedValue>
                  <name>1</name>
                  <value>2</value>
                </enumeratedValue>
                <enumeratedValue>
                  <name>2</name>
                  <value>4</value>
                </enumeratedValue>
                <enumeratedValue>
                  <name>3</name>
                  <value>8</value>
                </enumeratedValue>
                <enumeratedValue>
                  <name>4</name>
                  <value>16</value>
                </enumeratedValue>
                <enumeratedValue>
                  <name>5</name>
                  <value>32</value>
                </enumeratedValue>
              </enumeratedValues>
            </field>
            <field>
              <name>SQ16</name>
              <bitRange>[11:6]</bitRange>
              <enumeratedValues>
                <enumeratedValue>
                  <name>0</name>
                  <value>1</value>
                </enumeratedValue>
                <enumeratedValue>
                  <name>1</name>
                  <value>2</value>
                </enumeratedValue>
                <enumeratedValue>
                  <name>2</name>
                  <value>4</value>
                </enumeratedValue>
                <enumeratedValue>
                  <name>3</name>
                  <value>8</value>
                </enumeratedValue>
                <enumeratedValue>
                  <name>4</name>
                  <value>16</value>
                </enumeratedValue>
                <enumeratedValue>
                  <name>5</name>
                  <value>32</value>
                </enumeratedValue>
              </enumeratedValues>
            </field>
          </fields>
        </register>
        <register>
          <name>DR</name>
          <description>desc DR</description>
          <addressOffset>0x40</addressOffset>
          <fields>
            <field>
              <name>RDATA</name>
              <bitRange>[15:0]</bitRange>
              <access>read-only</access>
            </field>
          </fields>
        </register>
        <register>
          <name>JSQR</name>
          <description>desc JSQR</description>
          <addressOffset>0x4C</addressOffset>
          <fields>
            <field>
              <name>JL</name>
              <bitRange>[1:0]</bitRange>
              <enumeratedValues>
                <enumeratedValue>
                  <name>0</name>
                  <value>1</value>
                </enumeratedValue>
                <enumeratedValue>
                  <name>1</name>
                  <value>2</value>
                </enumeratedValue>
              </enumeratedValues>
            </field>
            <field>
              <name>JEXTSEL</name>
              <bitRange>[5:2]</bitRange>
              <enumeratedValues>
                <enumeratedValue>
                  <name>0</name>
                  <value>1</value>
                </enumeratedValue>
                <enumeratedValue>
                  <name>1</name>
                  <value>2</value>
                </enumeratedValue>
                <enumeratedValue>
                  <name>2</name>
                  <value>4</value>
                </enumeratedValue>
                <enumeratedValue>
                  <name>3</name>
                  <value>8</value>
                </enumeratedValue>
              </enumeratedValues>
            </field>
            <field>
              <name>JEXTEN</name>
              <bitRange>[7:6]</bitRange>
              <enumeratedValues>
                <enumeratedValue>
                  <name>0</name>
                  <value>1</value>
                </enumeratedValue>
                <enumeratedValue>
                  <name>1</name>
                  <value>2</value>
                </enumeratedValue>
              </enumeratedValues>
            </field>
            <field>
              <name>JSQ1</name>
              <bitRange>[13:8]</bitRange>
              <enumeratedValues>
                <enumeratedValue>
                  <name>0</name>
                  <value>1</value>
                </enumeratedValue>
                <enumeratedValue>
                  <name>1</name>
                  <value>2</value>
                </enumeratedValue>
                <enumeratedValue>
                  <name>2</name>
                  <value>4</value>
                </enumeratedValue>
                <enumeratedValue>
                  <name>3</name>
                  <value>8</value>
                </enumeratedValue>
                <enumeratedValue>
                  <name>4</name>
                  <value>16</value>
                </enumeratedValue>
                <enumeratedValue>
                  <name>5</name>
                  <value>32</value>
                </enumeratedValue>
              </enumeratedValues>
            </field>
            <field>
              <name>JSQ2</name>
              <bitRange>[19:14]</bitRange>
              <enumeratedValues>
                <enumeratedValue>
                  <name>0</name>
                  <value>1</value>
                </enumeratedValue>
                <enumeratedValue>
                  <name>1</name>
                  <value>2</value>
                </enumeratedValue>
                <enumeratedValue>
                  <name>2</name>
                  <value>4</value>
                </enumeratedValue>
                <enumeratedValue>
                  <name>3</name>
                  <value>8</value>
                </enumeratedValue>
                <enumeratedValue>
                  <name>4</name>
                  <value>16</value>
                </enumeratedValue>
                <enumeratedValue>
                  <name>5</name>
                  <value>32</value>
                </enumeratedValue>
              </enumeratedValues>
            </field>
            <field>
              <name>JSQ3</name>
              <bitRange>[25:20]</bitRange>
              <enumeratedValues>
                <enumeratedValue>
                  <name>0</name>
                  <value>1</value>
                </enumeratedValue>
                <enumeratedValue>
                  <name>1</name>
                  <value>2</value>
                </enumeratedValue>
                <enumeratedValue>
                  <name>2</name>
                  <value>4</value>
                </enumeratedValue>
                <enumeratedValue>
                  <name>3</name>
                  <value>8</value>
                </enumeratedValue>
                <enumeratedValue>
                  <name>4</name>
                  <value>16</value>
                </enumeratedValue>
                <enumeratedValue>
                  <name>5</name>
                  <value>32</value>
                </enumeratedValue>
              </enumeratedValues>
            </field>
            <field>
              <name>JSQ4</name>
              <bitRange>[31:26]</bitRange>
              <enumeratedValues>
                <enumeratedValue>
                  <name>0</name>
                  <value>1</value>
                </enumeratedValue>
                <enumeratedValue>
                  <name>1</name>
                  <value>2</value>
                </enumeratedValue>
                <enumeratedValue>
                  <name>2</name>
                  <value>4</value>
                </enumeratedValue>
                <enumeratedValue>
                  <name>3</name>
                  <value>8</value>
                </enumeratedValue>
                <enumeratedValue>
                  <name>4</name>
                  <value>16</value>
                </enumeratedValue>
                <enumeratedValue>
                  <name>5</name>
                  <value>32</value>
                </enumeratedValue>
              </enumeratedValues>
            </field>
          </fields>
        </register>
        <register>
          <name>OFR1</name>
          <addressOffset>0x60</addressOffset>
          <fields>
            <field>
              <name>OFFSET</name>
              <bitRange>[11:0]</bitRange>
            </field>
            <field>
              <name>OFFSETPOS</name>
              <bitRange>[23:23]</bitRange>
            </field>
            <field>
              <name>SATEN</name>
              <bitRange>[24:24]</bitRange>
            </field>
            <field>
              <name>OFFSET_CH</name>
              <bitRange>[30:25]</bitRange>
            </field>
            <field>
              <name>OFFSET_EN</name>
              <bitRange>[31:31]</bitRange>
            </field>
          </fields>
        </register>
        <register>
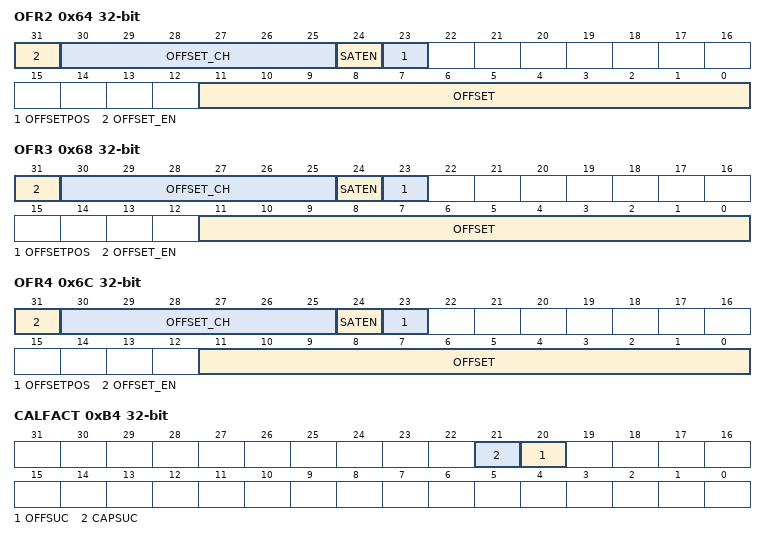
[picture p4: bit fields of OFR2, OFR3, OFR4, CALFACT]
          <name>OFR2</name>
          <addressOffset>0x64</addressOffset>
          <fields>
            <field>
              <name>OFFSET</name>
              <bitRange>[11:0]</bitRange>
            </field>
            <field>
              <name>OFFSETPOS</name>
              <bitRange>[23:23]</bitRange>
            </field>
            <field>
              <name>SATEN</name>
              <bitRange>[24:24]</bitRange>
            </field>
            <field>
              <name>OFFSET_CH</name>
              <bitRange>[30:25]</bitRange>
            </field>
            <field>
              <name>OFFSET_EN</name>
              <bitRange>[31:31]</bitRange>
            </field>
          </fields>
        </register>
        <register>
          <name>OFR3</name>
          <addressOffset>0x68</addressOffset>
          <fields>
            <field>
              <name>OFFSET</name>
              <bitRange>[11:0]</bitRange>
            </field>
            <field>
              <name>OFFSETPOS</name>
              <bitRange>[23:23]</bitRange>
            </field>
            <field>
              <name>SATEN</name>
              <bitRange>[24:24]</bitRange>
            </field>
            <field>
              <name>OFFSET_CH</name>
              <bitRange>[30:25]</bitRange>
            </field>
            <field>
              <name>OFFSET_EN</name>
              <bitRange>[31:31]</bitRange>
            </field>
          </fields>
        </register>
        <register>
          <name>OFR4</name>
          <addressOffset>0x6C</addressOffset>
          <fields>
            <field>
              <name>OFFSET</name>
              <bitRange>[11:0]</bitRange>
            </field>
            <field>
              <name>OFFSETPOS</name>
              <bitRange>[23:23]</bitRange>
            </field>
            <field>
              <name>SATEN</name>
              <bitRange>[24:24]</bitRange>
            </field>
            <field>
              <name>OFFSET_CH</name>
              <bitRange>[30:25]</bitRange>
            </field>
            <field>
              <name>OFFSET_EN</name>
              <bitRange>[31:31]</bitRange>
            </field>
          </fields>
        </register>
        <register>
          <name>JDR1</name>
          <description>desc JDR1</description>
          <addressOffset>0x80</addressOffset>
          <fields>
            <field>
              <name>JDATA</name>
              <bitRange>[15:0]</bitRange>
              <access>read-only</access>
            </field>
          </fields>
        </register>
        <register>
          <name>JDR2</name>
          <description>desc JDR2</description>
          <addressOffset>0x84</addressOffset>
          <fields>
            <field>
              <name>JDATA</name>
              <bitRange>[15:0]</bitRange>
              <access>read-only</access>
            </field>
          </fields>
        </register>
        <register>
          <name>JDR3</name>
          <description>desc JDR3</description>
          <addressOffset>0x88</addressOffset>
          <fields>
            <field>
              <name>JDATA</name>
              <bitRange>[15:0]</bitRange>
              <access>read-only</access>
            </field>
          </fields>
        </register>
        <register>
          <name>JDR4</name>
          <description>desc JDR4</description>
          <addressOffset>0x8C</addressOffset>
          <fields>
            <field>
              <name>JDATA</name>
              <bitRange>[15:0]</bitRange>
              <access>read-only</access>
            </field>
          </fields>
        </register>
        <register>
          <name>CALFACT</name>
          <addressOffset>0xB4</addressOffset>
          <fields>
            <field>
              <name>OFFSUC</name>
              <bitRange>[20:20]</bitRange>
            </field>
            <field>
              <name>CAPSUC</name>
              <bitRange>[21:21]</bitRange>
            </field>
          </fields>
        </register>
        <register>
          <name>GCOMP</name>
          <addressOffset>0xC0</addressOffset>
          <fields>
            <field>
              <name>GCOMPCOEFF</name>
              <bitRange>[13:0]</bitRange>
            </field>
          </fields>
        </register>
        <register>
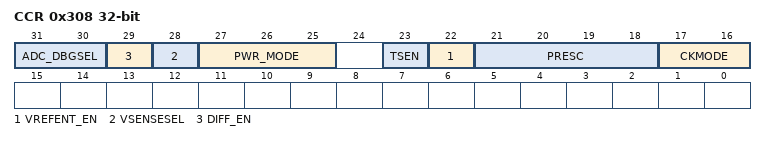
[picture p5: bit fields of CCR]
          <name>CCR</name>
          <addressOffset>0x308</addressOffset>
          <fields>
            <field>
              <name>CKMODE</name>
              <bitRange>[17:16]</bitRange>
              <enumeratedValues>
                <enumeratedValue>
                  <name>0</name>
                  <value>1</value>
                </enumeratedValue>
                <enumeratedValue>
                  <name>1</name>
                  <value>2</value>
                </enumeratedValue>
              </enumeratedValues>
            </field>
            <field>
              <name>PRESC</name>
              <bitRange>[21:18]</bitRange>
              <enumeratedValues>
                <enumeratedValue>
                  <name>0</name>
                  <value>1</value>
                </enumeratedValue>
                <enumeratedValue>
                  <name>1</name>
                  <value>2</value>
                </enumeratedValue>
                <enumeratedValue>
                  <name>2</name>
                  <value>4</value>
                </enumeratedValue>
                <enumeratedValue>
                  <name>3</name>
                  <value>8</value>
                </enumeratedValue>
              </enumeratedValues>
            </field>
            <field>
              <name>VREFENT_EN</name>
              <bitRange>[22:22]</bitRange>
            </field>
            <field>
              <name>TSEN</name>
              <bitRange>[23:23]</bitRange>
            </field>
            <field>
              <name>PWR_MODE</name>
              <bitRange>[27:25]</bitRange>
              <enumeratedValues>
                <enumeratedValue>
                  <name>0</name>
                  <value>1</value>
                </enumeratedValue>
                <enumeratedValue>
                  <name>1</name>
                  <value>2</value>
                </enumeratedValue>
                <enumeratedValue>
                  <name>2</name>
                  <value>4</value>
                </enumeratedValue>
              </enumeratedValues>
            </field>
            <field>
              <name>VSENSESEL</name>
              <bitRange>[28:28]</bitRange>
            </field>
            <field>
              <name>DIFF_EN</name>
              <bitRange>[29:29]</bitRange>
            </field>
            <field>
              <name>ADC_DBGSEL</name>
              <bitRange>[31:30]</bitRange>
            </field>
          </fields>
        </register>
      </registers>
    </peripheral>
    <peripheral>
      <name>BKP_TAMP</name>
      <baseAddress>0x4000B000</baseAddress>
      <addressBlock>
        <offset>0x0</offset>
        <size>0x180</size>
        <usage>registers</usage>
      </addressBlock>
      <registers>
        <register>
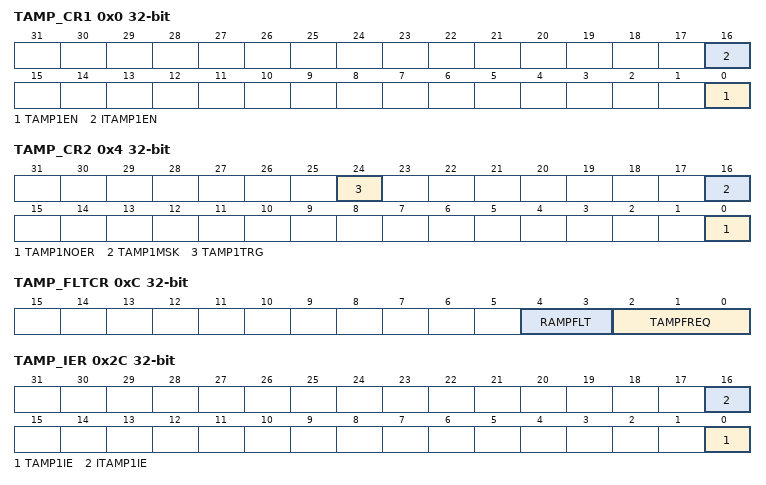
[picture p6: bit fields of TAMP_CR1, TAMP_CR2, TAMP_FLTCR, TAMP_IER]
          <name>TAMP_CR1</name>
          <addressOffset>0x0</addressOffset>
          <fields>
            <field>
              <name>TAMP1EN</name>
              <description>TAMP enable</description>
              <bitRange>[0:0]</bitRange>
            </field>
            <field>
              <name>ITAMP1EN</name>
              <description>TAMPER pin interrupt enable</description>
              <bitRange>[16:16]</bitRange>
            </field>
          </fields>
        </register>
        <register>
          <name>TAMP_CR2</name>
          <addressOffset>0x4</addressOffset>
          <fields>
            <field>
              <name>TAMP1NOER</name>
              <description>TAMP not erase enable</description>
              <bitRange>[0:0]</bitRange>
            </field>
            <field>
              <name>TAMP1MSK</name>
              <description>TAMP enable</description>
              <bitRange>[16:16]</bitRange>
            </field>
            <field>
              <name>TAMP1TRG</name>
              <description>TAMPER pin interrupt enable</description>
              <bitRange>[24:24]</bitRange>
            </field>
          </fields>
        </register>
        <register>
          <name>TAMP_FLTCR</name>
          <addressOffset>0xC</addressOffset>
          <fields>
            <field>
              <name>TAMPFREQ</name>
              <bitRange>[2:0]</bitRange>
            </field>
            <field>
              <name>RAMPFLT</name>
              <bitRange>[4:3]</bitRange>
            </field>
          </fields>
        </register>
        <register>
          <name>TAMP_IER</name>
          <addressOffset>0x2C</addressOffset>
          <fields>
            <field>
              <name>TAMP1IE</name>
              <bitRange>[0:0]</bitRange>
            </field>
            <field>
              <name>ITAMP1IE</name>
              <bitRange>[16:16]</bitRange>
            </field>
          </fields>
        </register>
        <register>
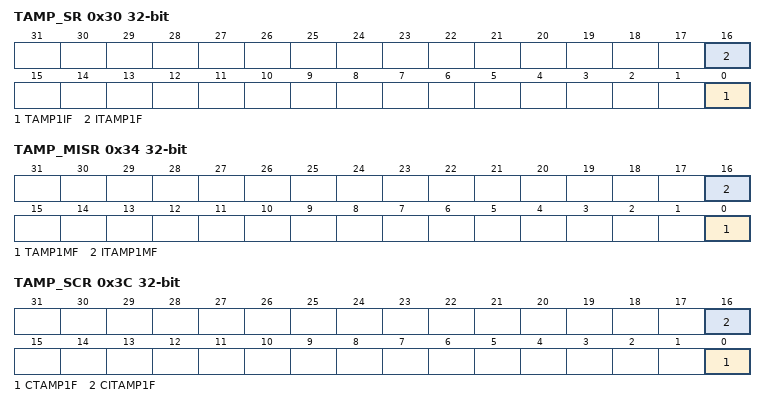
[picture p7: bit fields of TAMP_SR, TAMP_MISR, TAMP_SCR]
          <name>TAMP_SR</name>
          <addressOffset>0x30</addressOffset>
          <fields>
            <field>
              <name>TAMP1IF</name>
              <bitRange>[0:0]</bitRange>
              <access>read-only</access>
            </field>
            <field>
              <name>ITAMP1F</name>
              <bitRange>[16:16]</bitRange>
              <access>read-only</access>
            </field>
          </fields>
        </register>
        <register>
          <name>TAMP_MISR</name>
          <addressOffset>0x34</addressOffset>
          <fields>
            <field>
              <name>TAMP1MF</name>
              <bitRange>[0:0]</bitRange>
              <access>read-only</access>
            </field>
            <field>
              <name>ITAMP1MF</name>
              <bitRange>[16:16]</bitRange>
              <access>read-only</access>
            </field>
          </fields>
        </register>
        <register>
          <name>TAMP_SCR</name>
          <addressOffset>0x3C</addressOffset>
          <fields>
            <field>
              <name>CTAMP1F</name>
              <bitRange>[0:0]</bitRange>
              <access>write-only</access>
            </field>
            <field>
              <name>CITAMP1F</name>
              <bitRange>[16:16]</bitRange>
              <access>write-only</access>
            </field>
          </fields>
        </register>
        <register>
          <name>TAMP_BKP0R</name>
          <addressOffset>0x100</addressOffset>
          <fields>
            <field>
              <name>BKP</name>
              <description>bakeup data word0</description>
              <bitRange>[31:0]</bitRange>
            </field>
          </fields>
        </register>
        <register>
          <name>TAMP_BKP1R</name>
          <addressOffset>0x104</addressOffset>
          <fields>
            <field>
              <name>BKP</name>
              <description>bakeup data word1</description>
              <bitRange>[31:0]</bitRange>
            </field>
          </fields>
        </register>
        <register>
          <name>TAMP_BKP2R</name>
          <addressOffset>0x108</addressOffset>
          <fields>
            <field>
              <name>BKP</name>
              <description>bakeup data word2</description>
              <bitRange>[31:0]</bitRange>
            </field>
          </fields>
        </register>
        <register>
          <name>TAMP_BKP3R</name>
          <addressOffset>0x10C</addressOffset>
          <fields>
            <field>
              <name>BKP</name>
              <description>bakeup data word3</description>
              <bitRange>[31:0]</bitRange>
            </field>
          </fields>
        </register>
        <register>
          <name>TAMP_BKP4R</name>
          <addressOffset>0x110</addressOffset>
          <fields>
            <field>
              <name>BKP</name>
              <description>bakeup data word4</description>
              <bitRange>[31:0]</bitRange>
            </field>
          </fields>
        </register>
        <register>
          <name>TAMP_BKP5R</name>
          <addressOffset>0x114</addressOffset>
          <fields>
            <field>
              <name>BKP</name>
              <description>bakeup data word5</description>
              <bitRange>[31:0]</bitRange>
            </field>
          </fields>
        </register>
        <register>
          <name>TAMP_BKP6R</name>
          <addressOffset>0x118</addressOffset>
          <fields>
            <field>
              <name>BKP</name>
              <description>bakeup data word6</description>
              <bitRange>[31:0]</bitRange>
            </field>
          </fields>
        </register>
        <register>
          <name>TAMP_BKP7R</name>
          <addressOffset>0x11C</addressOffset>
          <fields>
            <field>
              <name>BKP</name>
              <description>bakeup data word7</description>
              <bitRange>[31:0]</bitRange>
            </field>
          </fields>
        </register>
      </registers>
    </peripheral>
    <peripheral>
      <name>COMP1</name>
      <description>Comparator 1</description>
      <groupName>COMP</groupName>
      <baseAddress>0x40010200</baseAddress>
      <addressBlock>
        <offset>0x0</offset>
        <size>0x08</size>
        <usage>registers</usage>
      </addressBlock>
      <interrupt>
        <name>ADC_COMP</name>
        <description>ADC and COMP Interrupt through EXTI Lines 17 and 18</description>
        <value>12</value>
      </interrupt>
      <registers>
        <register>
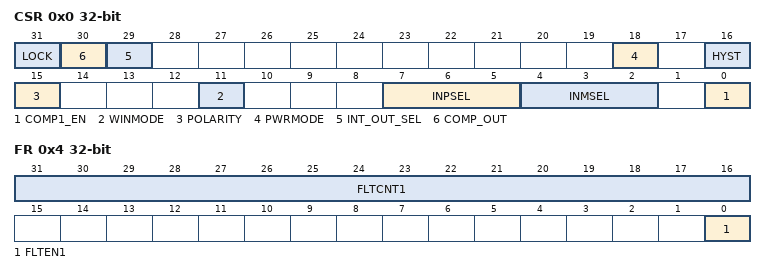
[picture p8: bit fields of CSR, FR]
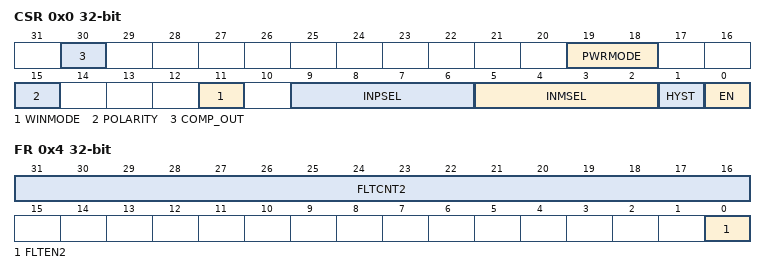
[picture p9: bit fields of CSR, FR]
          <name>CSR</name>
          <displayName>CSR</displayName>
          <description>COMP control and status register</description>
          <addressOffset>0x0</addressOffset>
          <fields>
            <field>
              <name>COMP1_EN</name>
              <description>COMP enable bit</description>
              <bitRange>[0:0]</bitRange>
            </field>
            <field>
              <name>INMSEL</name>
              <description>Comparator signal selector for inverting input INM</description>
              <bitRange>[4:2]</bitRange>
              <enumeratedValues>
                <enumeratedValue>
                  <name>0</name>
                  <value>1</value>
                </enumeratedValue>
                <enumeratedValue>
                  <name>1</name>
                  <value>2</value>
                </enumeratedValue>
                <enumeratedValue>
                  <name>2</name>
                  <value>4</value>
                </enumeratedValue>
              </enumeratedValues>
            </field>
            <field>
              <name>INPSEL</name>
              <description>Comparator signal selector for non-inverting input</description>
              <bitRange>[7:5]</bitRange>
              <enumeratedValues>
                <enumeratedValue>
                  <name>0</name>
                  <value>1</value>
                </enumeratedValue>
                <enumeratedValue>
                  <name>1</name>
                  <value>2</value>
                </enumeratedValue>
                <enumeratedValue>
                  <name>2</name>
                  <value>4</value>
                </enumeratedValue>
              </enumeratedValues>
            </field>
            <field>
              <name>WINMODE</name>
              <description>Comparator non-inverting input selector for window mode</description>
              <bitRange>[11:11]</bitRange>
            </field>
            <field>
              <name>POLARITY</name>
              <description>Comparator polarity selector</description>
              <bitRange>[15:15]</bitRange>
            </field>
            <field>
              <name>HYST</name>
              <description>Comparator hysteresis enable selector</description>
              <bitRange>[16:16]</bitRange>
            </field>
            <field>
              <name>PWRMODE</name>
              <description>Comparator power mode selector</description>
              <bitRange>[18:18]</bitRange>
            </field>
            <field>
              <name>INT_OUT_SEL</name>
              <description>Comparator internal digital output control</description>
              <bitRange>[29:29]</bitRange>
            </field>
            <field>
              <name>COMP_OUT</name>
              <description>Comparator output status</description>
              <bitRange>[30:30]</bitRange>
            </field>
            <field>
              <name>LOCK</name>
              <description>Comparator CSR register lock</description>
              <bitRange>[31:31]</bitRange>
            </field>
          </fields>
        </register>
        <register>
          <name>FR</name>
          <displayName>FR</displayName>
          <description>Comparator Filter register</description>
          <addressOffset>0x4</addressOffset>
          <fields>
            <field>
              <name>FLTEN1</name>
              <description>Filter enable bit</description>
              <bitRange>[0:0]</bitRange>
            </field>
            <field>
              <name>FLTCNT1</name>
              <description>Comparator filter and counter</description>
              <bitRange>[31:16]</bitRange>
            </field>
          </fields>
        </register>
      </registers>
    </peripheral>
    <peripheral>
      <name>COMP2</name>
      <description>Comparator2</description>
      <groupName>COMP</groupName>
      <baseAddress>0x40010210</baseAddress>
      <addressBlock>
        <offset>0x0</offset>
        <size>0x10</size>
        <usage>registers</usage>
      </addressBlock>
      <interrupt>
        <name>ADC_COMP</name>
        <description>ADC and COMP Interrupt through EXTI Lines 17 and 18</description>
        <value>12</value>
      </interrupt>
      <registers>
        <register>
          <name>CSR</name>
          <displayName>CSR</displayName>
          <description>COMP control and status register</description>
          <addressOffset>0x0</addressOffset>
          <fields>
            <field>
              <name>EN</name>
              <description>COMP enable bit</description>
              <bitRange>[0:0]</bitRange>
            </field>
            <field>
              <name>HYST</name>
              <description>Comparator hysteresis enable selector</description>
              <bitRange>[1:1]</bitRange>
            </field>
            <field>
              <name>INMSEL</name>
              <description>Comparator signal selector for inverting input INM</description>
              <bitRange>[5:2]</bitRange>
            </field>
            <field>
              <name>INPSEL</name>
              <description>Comparator signal selector for non-inverting input</description>
              <bitRange>[9:6]</bitRange>
            </field>
            <field>
              <name>WINMODE</name>
              <description>Comparator non-inverting input selector for window mode</description>
              <bitRange>[11:11]</bitRange>
            </field>
            <field>
              <name>POLARITY</name>
              <description>Comparator polarity selector</description>
              <bitRange>[15:15]</bitRange>
            </field>
            <field>
              <name>PWRMODE</name>
              <description>Comparator power mode selector</description>
              <bitRange>[19:18]</bitRange>
            </field>
            <field>
              <name>COMP_OUT</name>
              <description>Comparator output status</description>
              <bitRange>[30:30]</bitRange>
            </field>
          </fields>
        </register>
        <register>
          <name>FR</name>
          <displayName>FR</displayName>
          <description>Comparator Filter register</description>
          <addressOffset>0x4</addressOffset>
          <fields>
            <field>
              <name>FLTEN2</name>
              <description>Filter enable bit</description>
              <bitRange>[0:0]</bitRange>
            </field>
            <field>
              <name>FLTCNT2</name>
              <description>Comparator filter and counter</description>
              <bitRange>[31:16]</bitRange>
            </field>
          </fields>
        </register>
      </registers>
    </peripheral>
    <peripheral>
      <name>COMP_COMMON</name>
      <description>Comparator</description>
      <groupName>COMP</groupName>
      <baseAddress>0x40010208</baseAddress>
      <addressBlock>
        <offset>0x00</offset>
        <size>0x04</size>
        <usage>registers</usage>
      </addressBlock>
      <interrupt>
        <name>ADC_COMP</name>
        <description>ADC and COMP Interrupt through EXTI Lines 17 and 18</description>
        <value>12</value>
      </interrupt>
      <registers>
        <register>
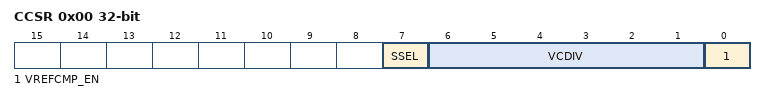
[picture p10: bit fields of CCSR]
          <name>CCSR</name>
          <displayName>CCSR</displayName>
          <description>COMP control and status register</description>
          <addressOffset>0x00</addressOffset>
          <fields>
            <field>
              <name>VREFCMP_EN</name>
              <description>VREFCMP enable bit</description>
              <bitRange>[0:0]</bitRange>
            </field>
            <field>
              <name>VCDIV</name>
              <description>COMP1,COMP2 voltage divider selection</description>
              <bitRange>[6:1]</bitRange>
              <enumeratedValues>
                <enumeratedValue>
                  <name>0</name>
                  <value>1</value>
                </enumeratedValue>
                <enumeratedValue>
                  <name>1</name>
                  <value>2</value>
                </enumeratedValue>
                <enumeratedValue>
                  <name>2</name>
                  <value>4</value>
                </enumeratedValue>
                <enumeratedValue>
                  <name>3</name>
                  <value>8</value>
                </enumeratedValue>
                <enumeratedValue>
                  <name>4</name>
                  <value>16</value>
                </enumeratedValue>
                <enumeratedValue>
                  <name>5</name>
                  <value>32</value>
                </enumeratedValue>
              </enumeratedValues>
            </field>
            <field>
              <name>SSEL</name>
              <description>VREFCMP Voltage Source Selection</description>
              <bitRange>[7:7]</bitRange>
            </field>
          </fields>
        </register>
      </registers>
    </peripheral>
    <peripheral>
      <name>CRC</name>
      <description>CRC calculation unit</description>
      <baseAddress>0x40023000</baseAddress>
      <addressBlock>
        <offset>0x0</offset>
        <size>0x400</size>
        <usage>registers</usage>
      </addressBlock>
      <registers>
        <register>
          <name>DR</name>
          <description>Data register</description>
          <addressOffset>0x0</addressOffset>
          <fields>
            <field>
              <name>DR</name>
              <description>CRC data</description>
              <bitRange>[31:0]</bitRange>
            </field>
          </fields>
        </register>
        <register>
          <name>IDR</name>
          <description>Independent Data register</description>
          <addressOffset>0x4</addressOffset>
          <fields>
            <field>
              <name>IDR</name>
              <description>CRC independent data</description>
              <bitRange>[31:0]</bitRange>
            </field>
          </fields>
        </register>
        <register>
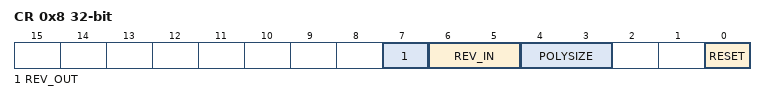
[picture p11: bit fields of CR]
          <name>CR</name>
          <description>Control register</description>
          <addressOffset>0x8</addressOffset>
          <fields>
            <field>
              <name>RESET</name>
              <description>CRC software reset</description>
              <bitRange>[0:0]</bitRange>
              <access>write-only</access>
            </field>
            <field>
              <name>POLYSIZE</name>
              <description>Polynomial size</description>
              <bitRange>[4:3]</bitRange>
              <enumeratedValues>
                <enumeratedValue>
                  <name>0</name>
                  <value>1</value>
                </enumeratedValue>
                <enumeratedValue>
                  <name>1</name>
                  <value>2</value>
                </enumeratedValue>
              </enumeratedValues>
            </field>
            <field>
              <name>REV_IN</name>
              <description>Reverse input data</description>
              <bitRange>[6:5]</bitRange>
              <enumeratedValues>
                <enumeratedValue>
                  <name>0</name>
                  <value>1</value>
                </enumeratedValue>
                <enumeratedValue>
                  <name>1</name>
                  <value>2</value>
                </enumeratedValue>
              </enumeratedValues>
            </field>
            <field>
              <name>REV_OUT</name>
              <description>Reverse output data</description>
              <bitRange>[7:7]</bitRange>
            </field>
          </fields>
        </register>
        <register>
          <name>INIT</name>
          <addressOffset>0x10</addressOffset>
          <fields>
            <field>
              <name>INIT</name>
              <description>initial value</description>
              <bitRange>[31:0]</bitRange>
            </field>
          </fields>
        </register>
        <register>
          <name>POL</name>
          <addressOffset>0x14</addressOffset>
          <fields>
            <field>
              <name>POL</name>
              <description>polynomial</description>
              <bitRange>[31:0]</bitRange>
            </field>
          </fields>
        </register>
      </registers>
    </peripheral>
    <peripheral>
      <name>DAC</name>
      <description>desc DAC</description>
      <baseAddress>0x40007400</baseAddress>
      <addressBlock>
        <offset>0x0</offset>
        <size>0x400</size>
        <usage>registers</usage>
      </addressBlock>
      <interrupt>
        <name>TIM6_LPTIM1_DAC</name>
        <description>TIM6, LPTIM1, DAC global Interrupts</description>
        <value>17</value>
      </interrupt>
      <registers>
        <register>
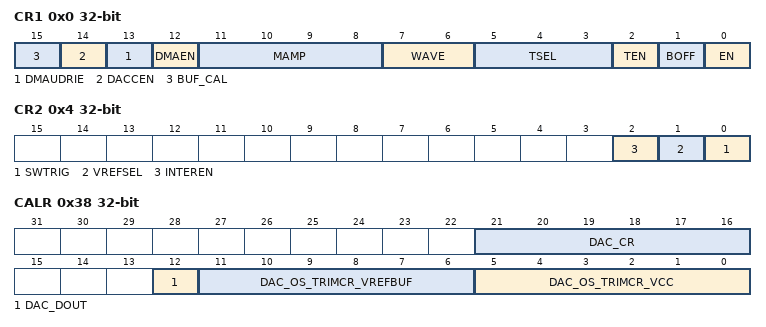
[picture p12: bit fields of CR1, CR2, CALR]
          <name>CR1</name>
          <addressOffset>0x0</addressOffset>
          <fields>
            <field>
              <name>EN</name>
              <bitRange>[0:0]</bitRange>
            </field>
            <field>
              <name>BOFF</name>
              <bitRange>[1:1]</bitRange>
            </field>
            <field>
              <name>TEN</name>
              <bitRange>[2:2]</bitRange>
            </field>
            <field>
              <name>TSEL</name>
              <bitRange>[5:3]</bitRange>
              <enumeratedValues>
                <enumeratedValue>
                  <name>0</name>
                  <value>1</value>
                </enumeratedValue>
                <enumeratedValue>
                  <name>1</name>
                  <value>2</value>
                </enumeratedValue>
                <enumeratedValue>
                  <name>2</name>
                  <value>4</value>
                </enumeratedValue>
              </enumeratedValues>
            </field>
            <field>
              <name>WAVE</name>
              <bitRange>[7:6]</bitRange>
              <enumeratedValues>
                <enumeratedValue>
                  <name>0</name>
                  <value>1</value>
                </enumeratedValue>
                <enumeratedValue>
                  <name>1</name>
                  <value>2</value>
                </enumeratedValue>
              </enumeratedValues>
            </field>
            <field>
              <name>MAMP</name>
              <bitRange>[11:8]</bitRange>
              <enumeratedValues>
                <enumeratedValue>
                  <name>0</name>
                  <value>1</value>
                </enumeratedValue>
                <enumeratedValue>
                  <name>1</name>
                  <value>2</value>
                </enumeratedValue>
                <enumeratedValue>
                  <name>2</name>
                  <value>4</value>
                </enumeratedValue>
                <enumeratedValue>
                  <name>3</name>
                  <value>8</value>
                </enumeratedValue>
              </enumeratedValues>
            </field>
            <field>
              <name>DMAEN</name>
              <bitRange>[12:12]</bitRange>
            </field>
            <field>
              <name>DMAUDRIE</name>
              <bitRange>[13:13]</bitRange>
            </field>
            <field>
              <name>DACCEN</name>
              <bitRange>[14:14]</bitRange>
            </field>
            <field>
              <name>BUF_CAL</name>
              <bitRange>[15:15]</bitRange>
            </field>
          </fields>
        </register>
        <register>
          <name>CR2</name>
          <addressOffset>0x4</addressOffset>
          <fields>
            <field>
              <name>SWTRIG</name>
              <bitRange>[0:0]</bitRange>
              <access>write-only</access>
            </field>
            <field>
              <name>VREFSEL</name>
              <bitRange>[1:1]</bitRange>
            </field>
            <field>
              <name>INTEREN</name>
              <bitRange>[2:2]</bitRange>
            </field>
          </fields>
        </register>
        <register>
          <name>DHR12R</name>
          <addressOffset>0x8</addressOffset>
          <fields>
            <field>
              <name>DACDHR</name>
              <bitRange>[11:0]</bitRange>
            </field>
          </fields>
        </register>
        <register>
          <name>DHR12L</name>
          <addressOffset>0xC</addressOffset>
          <fields>
            <field>
              <name>DACDHR</name>
              <bitRange>[15:4]</bitRange>
            </field>
          </fields>
        </register>
        <register>
          <name>DHR8R</name>
          <addressOffset>0x10</addressOffset>
          <fields>
            <field>
              <name>DACDHR</name>
              <bitRange>[7:0]</bitRange>
            </field>
          </fields>
        </register>
        <register>
          <name>DOR</name>
          <addressOffset>0x2C</addressOffset>
          <fields>
            <field>
              <name>DACDOR</name>
              <bitRange>[11:0]</bitRange>
            </field>
          </fields>
        </register>
        <register>
          <name>SR</name>
          <description>desc SR</description>
          <addressOffset>0x34</addressOffset>
          <fields>
            <field>
              <name>DMAUDR</name>
              <bitRange>[13:13]</bitRange>
            </field>
          </fields>
        </register>
        <register>
          <name>CALR</name>
          <addressOffset>0x38</addressOffset>
          <fields>
            <field>
              <name>DAC_OS_TRIMCR_VCC</name>
              <bitRange>[5:0]</bitRange>
              <enumeratedValues>
                <enumeratedValue>
                  <name>0</name>
                  <value>1</value>
                </enumeratedValue>
                <enumeratedValue>
                  <name>1</name>
                  <value>2</value>
                </enumeratedValue>
                <enumeratedValue>
                  <name>2</name>
                  <value>4</value>
                </enumeratedValue>
                <enumeratedValue>
                  <name>3</name>
                  <value>8</value>
                </enumeratedValue>
                <enumeratedValue>
                  <name>4</name>
                  <value>16</value>
                </enumeratedValue>
                <enumeratedValue>
                  <name>5</name>
                  <value>32</value>
                </enumeratedValue>
              </enumeratedValues>
            </field>
            <field>
              <name>DAC_OS_TRIMCR_VREFBUF</name>
              <bitRange>[11:6]</bitRange>
              <enumeratedValues>
                <enumeratedValue>
                  <name>0</name>
                  <value>1</value>
                </enumeratedValue>
                <enumeratedValue>
                  <name>1</name>
                  <value>2</value>
                </enumeratedValue>
                <enumeratedValue>
                  <name>2</name>
                  <value>4</value>
                </enumeratedValue>
                <enumeratedValue>
                  <name>3</name>
                  <value>8</value>
                </enumeratedValue>
                <enumeratedValue>
                  <name>4</name>
                  <value>16</value>
                </enumeratedValue>
                <enumeratedValue>
                  <name>5</name>
                  <value>32</value>
                </enumeratedValue>
              </enumeratedValues>
            </field>
            <field>
              <name>DAC_DOUT</name>
              <bitRange>[12:12]</bitRange>
              <access>read-only</access>
            </field>
            <field>
              <name>DAC_CR</name>
              <bitRange>[21:16]</bitRange>
              <access>read-only</access>
            </field>
          </fields>
        </register>
      </registers>
    </peripheral>
    <peripheral>
      <name>DBG</name>
      <baseAddress>0x40015800</baseAddress>
      <addressBlock>
        <offset>0x0</offset>
        <size>0x10</size>
        <usage>registers</usage>
      </addressBlock>
      <registers>
        <register>
          <name>IDCODE</name>
          <addressOffset>0x0</addressOffset>
          <fields>
            <field>
              <name>REV_ID</name>
              <bitRange>[31:0]</bitRange>
              <access>read-only</access>
            </field>
          </fields>
        </register>
        <register>
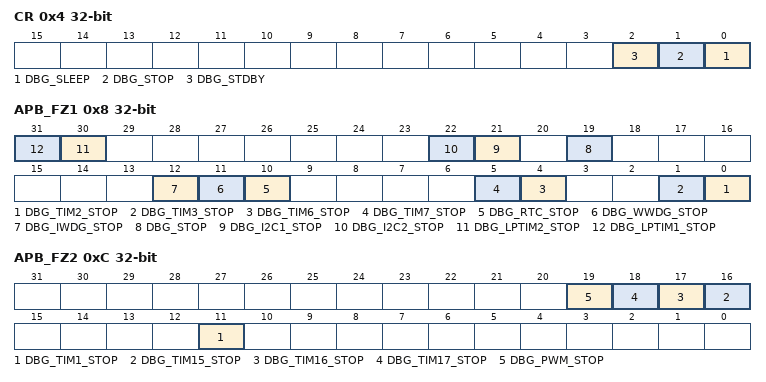
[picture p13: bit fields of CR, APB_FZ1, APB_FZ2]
          <name>CR</name>
          <addressOffset>0x4</addressOffset>
          <fields>
            <field>
              <name>DBG_SLEEP</name>
              <bitRange>[0:0]</bitRange>
            </field>
            <field>
              <name>DBG_STOP</name>
              <bitRange>[1:1]</bitRange>
            </field>
            <field>
              <name>DBG_STDBY</name>
              <bitRange>[2:2]</bitRange>
            </field>
          </fields>
        </register>
        <register>
          <name>APB_FZ1</name>
          <addressOffset>0x8</addressOffset>
          <fields>
            <field>
              <name>DBG_TIM2_STOP</name>
              <bitRange>[0:0]</bitRange>
            </field>
            <field>
              <name>DBG_TIM3_STOP</name>
              <bitRange>[1:1]</bitRange>
            </field>
            <field>
              <name>DBG_TIM6_STOP</name>
              <bitRange>[4:4]</bitRange>
            </field>
            <field>
              <name>DBG_TIM7_STOP</name>
              <bitRange>[5:5]</bitRange>
            </field>
            <field>
              <name>DBG_RTC_STOP</name>
              <bitRange>[10:10]</bitRange>
            </field>
            <field>
              <name>DBG_WWDG_STOP</name>
              <bitRange>[11:11]</bitRange>
            </field>
            <field>
              <name>DBG_IWDG_STOP</name>
              <bitRange>[12:12]</bitRange>
            </field>
            <field>
              <name>DBG_STOP</name>
              <bitRange>[19:19]</bitRange>
            </field>
            <field>
              <name>DBG_I2C1_STOP</name>
              <bitRange>[21:21]</bitRange>
            </field>
            <field>
              <name>DBG_I2C2_STOP</name>
              <bitRange>[22:22]</bitRange>
            </field>
            <field>
              <name>DBG_LPTIM2_STOP</name>
              <bitRange>[30:30]</bitRange>
            </field>
            <field>
              <name>DBG_LPTIM1_STOP</name>
              <bitRange>[31:31]</bitRange>
            </field>
          </fields>
        </register>
        <register>
          <name>APB_FZ2</name>
          <addressOffset>0xC</addressOffset>
          <fields>
            <field>
              <name>DBG_TIM1_STOP</name>
              <bitRange>[11:11]</bitRange>
            </field>
            <field>
              <name>DBG_TIM15_STOP</name>
              <bitRange>[16:16]</bitRange>
            </field>
            <field>
              <name>DBG_TIM16_STOP</name>
              <bitRange>[17:17]</bitRange>
            </field>
            <field>
              <name>DBG_TIM17_STOP</name>
              <bitRange>[18:18]</bitRange>
            </field>
            <field>
              <name>DBG_PWM_STOP</name>
              <bitRange>[19:19]</bitRange>
            </field>
          </fields>
        </register>
      </registers>
    </peripheral>
    <peripheral>
      <name>DMA</name>
      <description>Direct memory access</description>
      <baseAddress>0x40020000</baseAddress>
      <addressBlock>
        <offset>0x0</offset>
        <size>0x400</size>
        <usage>registers</usage>
      </addressBlock>
      <interrupt>
        <name>DMA1_Channel1</name>
        <description>DMA1 Channel 1 Interrupt</description>
        <value>9</value>
      </interrupt>
      <interrupt>
        <name>DMA1_Channel2_3</name>
        <description>DMA1 Channel 2 and Channel 3 Interrupt</description>
        <value>10</value>
      </interrupt>
      <interrupt>
        <name>DMA1_Channel4_5_6_7</name>
        <description>DMA1 Channel 4, 5, 6, 7 Interrupts</description>
        <value>11</value>
      </interrupt>
      <registers>
        <register>
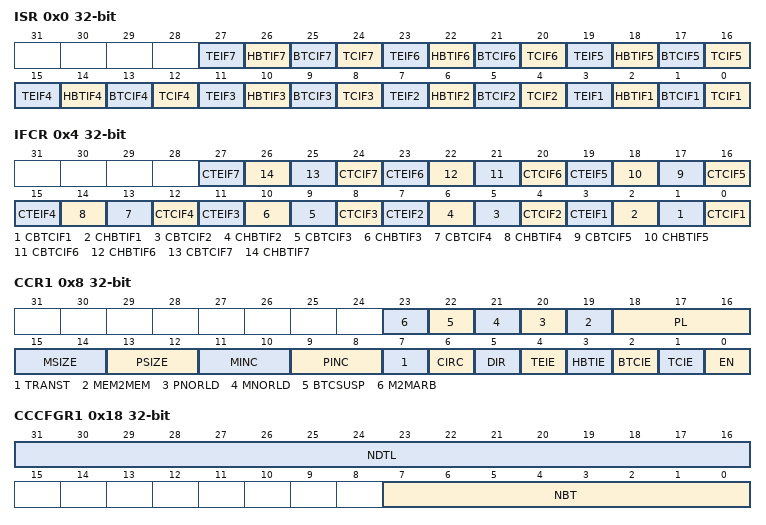
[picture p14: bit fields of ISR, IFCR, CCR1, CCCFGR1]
          <name>ISR</name>
          <description>desc ISR</description>
          <addressOffset>0x0</addressOffset>
          <fields>
            <field>
              <name>TCIF1</name>
              <description>Transfer Complete Flag for Channel 1</description>
              <bitRange>[0:0]</bitRange>
              <access>read-only</access>
            </field>
            <field>
              <name>BTCIF1</name>
              <description>Block Transfer Complete Flag for Channel 1</description>
              <bitRange>[1:1]</bitRange>
              <access>read-only</access>
            </field>
            <field>
              <name>HBTIF1</name>
              <description>Half Block Transfer Complete Flag for Channel 1</description>
              <bitRange>[2:2]</bitRange>
              <access>read-only</access>
            </field>
            <field>
              <name>TEIF1</name>
              <description>Transfer Error Flag for Channel 1</description>
              <bitRange>[3:3]</bitRange>
              <access>read-only</access>
            </field>
            <field>
              <name>TCIF2</name>
              <description>Transfer Complete Flag for Channel 2</description>
              <bitRange>[4:4]</bitRange>
              <access>read-only</access>
            </field>
            <field>
              <name>BTCIF2</name>
              <description>Block Transfer Complete Flag for Channel 2</description>
              <bitRange>[5:5]</bitRange>
              <access>read-only</access>
            </field>
            <field>
              <name>HBTIF2</name>
              <description>Half Block Transfer Complete Flag for Channel 2</description>
              <bitRange>[6:6]</bitRange>
              <access>read-only</access>
            </field>
            <field>
              <name>TEIF2</name>
              <description>Transfer Error Flag for Channel 2</description>
              <bitRange>[7:7]</bitRange>
              <access>read-only</access>
            </field>
            <field>
              <name>TCIF3</name>
              <description>Transfer Complete Flag for Channel 3</description>
              <bitRange>[8:8]</bitRange>
              <access>read-only</access>
            </field>
            <field>
              <name>BTCIF3</name>
              <description>Block Transfer Complete Flag for Channel 3</description>
              <bitRange>[9:9]</bitRange>
              <access>read-only</access>
            </field>
            <field>
              <name>HBTIF3</name>
              <description>Half Block Transfer Complete Flag for Channel 3</description>
              <bitRange>[10:10]</bitRange>
              <access>read-only</access>
            </field>
            <field>
              <name>TEIF3</name>
              <description>Transfer Error Flag for Channel 3</description>
              <bitRange>[11:11]</bitRange>
              <access>read-only</access>
            </field>
            <field>
              <name>TCIF4</name>
              <description>Transfer Complete Flag for Channel 4</description>
              <bitRange>[12:12]</bitRange>
              <access>read-only</access>
            </field>
            <field>
              <name>BTCIF4</name>
              <description>Block Transfer Complete Flag for Channel 4</description>
              <bitRange>[13:13]</bitRange>
              <access>read-only</access>
            </field>
            <field>
              <name>HBTIF4</name>
              <description>Half Block Transfer Complete Flag for Channel 4</description>
              <bitRange>[14:14]</bitRange>
              <access>read-only</access>
            </field>
            <field>
              <name>TEIF4</name>
              <description>Transfer Error Flag for Channel 4</description>
              <bitRange>[15:15]</bitRange>
              <access>read-only</access>
            </field>
            <field>
              <name>TCIF5</name>
              <description>Transfer Complete Flag for Channel 5</description>
              <bitRange>[16:16]</bitRange>
              <access>read-only</access>
            </field>
            <field>
              <name>BTCIF5</name>
              <description>Block Transfer Complete Flag for Channel 5</description>
              <bitRange>[17:17]</bitRange>
              <access>read-only</access>
            </field>
            <field>
              <name>HBTIF5</name>
              <description>Half Block Transfer Complete Flag for Channel 5</description>
              <bitRange>[18:18]</bitRange>
              <access>read-only</access>
            </field>
            <field>
              <name>TEIF5</name>
              <description>Transfer Error Flag for Channel 5</description>
              <bitRange>[19:19]</bitRange>
              <access>read-only</access>
            </field>
            <field>
              <name>TCIF6</name>
              <description>Transfer Complete Flag for Channel 6</description>
              <bitRange>[20:20]</bitRange>
              <access>read-only</access>
            </field>
            <field>
              <name>BTCIF6</name>
              <description>Block Transfer Complete Flag for Channel 6</description>
              <bitRange>[21:21]</bitRange>
              <access>read-only</access>
            </field>
            <field>
              <name>HBTIF6</name>
              <description>Half Block Transfer Complete Flag for Channel 6</description>
              <bitRange>[22:22]</bitRange>
              <access>read-only</access>
            </field>
            <field>
              <name>TEIF6</name>
              <description>Transfer Error Flag for Channel 6</description>
              <bitRange>[23:23]</bitRange>
              <access>read-only</access>
            </field>
            <field>
              <name>TCIF7</name>
              <description>Transfer Complete Flag for Channel 7</description>
              <bitRange>[24:24]</bitRange>
              <access>read-only</access>
            </field>
            <field>
              <name>BTCIF7</name>
              <description>Block Transfer Complete Flag for Channel 7</description>
              <bitRange>[25:25]</bitRange>
              <access>read-only</access>
            </field>
            <field>
              <name>HBTIF7</name>
              <description>Half Block Transfer Complete Flag for Channel 7</description>
              <bitRange>[26:26]</bitRange>
              <access>read-only</access>
            </field>
            <field>
              <name>TEIF7</name>
              <description>Transfer Error Flag for Channel 7</description>
              <bitRange>[27:27]</bitRange>
              <access>read-only</access>
            </field>
          </fields>
        </register>
        <register>
          <name>IFCR</name>
          <description>desc IFCR</description>
          <addressOffset>0x4</addressOffset>
          <fields>
            <field>
              <name>CTCIF1</name>
              <description>Transfer Complete Flag Clear for Channel 1</description>
              <bitRange>[0:0]</bitRange>
              <access>write-only</access>
            </field>
            <field>
              <name>CBTCIF1</name>
              <description>Block Transfer Complete Flag Clear for Channel 1</description>
              <bitRange>[1:1]</bitRange>
              <access>write-only</access>
            </field>
            <field>
              <name>CHBTIF1</name>
              <description>Half Block Transfer Complete Flag Clear for Channel 1</description>
              <bitRange>[2:2]</bitRange>
              <access>write-only</access>
            </field>
            <field>
              <name>CTEIF1</name>
              <description>Transfer Error Flag Clear for Channel 1</description>
              <bitRange>[3:3]</bitRange>
              <access>write-only</access>
            </field>
            <field>
              <name>CTCIF2</name>
              <description>Transfer Complete Flag Clear for Channel 2</description>
              <bitRange>[4:4]</bitRange>
              <access>write-only</access>
            </field>
            <field>
              <name>CBTCIF2</name>
              <description>Block Transfer Complete Flag Clear for Channel 2</description>
              <bitRange>[5:5]</bitRange>
              <access>write-only</access>
            </field>
            <field>
              <name>CHBTIF2</name>
              <description>Half Block Transfer Complete Flag Clear for Channel 2</description>
              <bitRange>[6:6]</bitRange>
              <access>write-only</access>
            </field>
            <field>
              <name>CTEIF2</name>
              <description>Transfer Error Flag Clear for Channel 2</description>
              <bitRange>[7:7]</bitRange>
              <access>write-only</access>
            </field>
            <field>
              <name>CTCIF3</name>
              <description>Transfer Complete Flag Clear for Channel 3</description>
              <bitRange>[8:8]</bitRange>
              <access>write-only</access>
            </field>
            <field>
              <name>CBTCIF3</name>
              <description>Block Transfer Complete Flag Clear for Channel 3</description>
              <bitRange>[9:9]</bitRange>
              <access>write-only</access>
            </field>
            <field>
              <name>CHBTIF3</name>
              <description>Half Block Transfer Complete Flag Clear for Channel 3</description>
              <bitRange>[10:10]</bitRange>
              <access>write-only</access>
            </field>
            <field>
              <name>CTEIF3</name>
              <description>Transfer Error Flag Clear for Channel 3</description>
              <bitRange>[11:11]</bitRange>
              <access>write-only</access>
            </field>
            <field>
              <name>CTCIF4</name>
              <description>Transfer Complete Flag Clear for Channel 4</description>
              <bitRange>[12:12]</bitRange>
              <access>write-only</access>
            </field>
            <field>
              <name>CBTCIF4</name>
              <description>Block Transfer Complete Flag Clear for Channel 4</description>
              <bitRange>[13:13]</bitRange>
              <access>write-only</access>
            </field>
            <field>
              <name>CHBTIF4</name>
              <description>Half Block Transfer Complete Flag Clear for Channel 4</description>
              <bitRange>[14:14]</bitRange>
              <access>write-only</access>
            </field>
            <field>
              <name>CTEIF4</name>
              <description>Transfer Error Flag Clear for Channel 4</description>
              <bitRange>[15:15]</bitRange>
              <access>write-only</access>
            </field>
            <field>
              <name>CTCIF5</name>
              <description>Transfer Complete Flag Clear for Channel 5</description>
              <bitRange>[16:16]</bitRange>
              <access>write-only</access>
            </field>
            <field>
              <name>CBTCIF5</name>
              <description>Block Transfer Complete Flag Clear for Channel 5</description>
              <bitRange>[17:17]</bitRange>
              <access>write-only</access>
            </field>
            <field>
              <name>CHBTIF5</name>
              <description>Half Block Transfer Complete Flag Clear for Channel 5</description>
              <bitRange>[18:18]</bitRange>
              <access>write-only</access>
            </field>
            <field>
              <name>CTEIF5</name>
              <description>Transfer Error Flag Clear for Channel 5</description>
              <bitRange>[19:19]</bitRange>
              <access>write-only</access>
            </field>
            <field>
              <name>CTCIF6</name>
              <description>Transfer Complete Flag Clear for Channel 6</description>
              <bitRange>[20:20]</bitRange>
              <access>write-only</access>
            </field>
            <field>
              <name>CBTCIF6</name>
              <description>Block Transfer Complete Flag Clear for Channel 6</description>
              <bitRange>[21:21]</bitRange>
              <access>write-only</access>
            </field>
            <field>
              <name>CHBTIF6</name>
              <description>Half Block Transfer Complete Flag Clear for Channel 6</description>
              <bitRange>[22:22]</bitRange>
              <access>write-only</access>
            </field>
            <field>
              <name>CTEIF6</name>
              <description>Transfer Error Flag Clear for Channel 6</description>
              <bitRange>[23:23]</bitRange>
              <access>write-only</access>
            </field>
            <field>
              <name>CTCIF7</name>
              <description>Transfer Complete Flag Clear for Channel 7</description>
              <bitRange>[24:24]</bitRange>
              <access>write-only</access>
            </field>
            <field>
              <name>CBTCIF7</name>
              <description>Block Transfer Complete Flag Clear for Channel 7</description>
              <bitRange>[25:25]</bitRange>
              <access>write-only</access>
            </field>
            <field>
              <name>CHBTIF7</name>
              <description>Half Block Transfer Complete Flag Clear for Channel 7</description>
              <bitRange>[26:26]</bitRange>
              <access>write-only</access>
            </field>
            <field>
              <name>CTEIF7</name>
              <description>Transfer Error Flag Clear for Channel 7</description>
              <bitRange>[27:27]</bitRange>
              <access>write-only</access>
            </field>
          </fields>
        </register>
        <register>
          <name>CCR1</name>
          <description>desc CCR1</description>
          <addressOffset>0x8</addressOffset>
          <fields>
            <field>
              <name>EN</name>
              <description>Channel Enable</description>
              <bitRange>[0:0]</bitRange>
            </field>
            <field>
              <name>TCIE</name>
              <description>Transfer Complete Interrupt Enable</description>
              <bitRange>[1:1]</bitRange>
            </field>
            <field>
              <name>BTCIE</name>
              <description>Block Transfer Complete Interrupt Enable</description>
              <bitRange>[2:2]</bitRange>
            </field>
            <field>
              <name>HBTIE</name>
              <description>Half Block Transfer Complete Interrupt Enable</description>
              <bitRange>[3:3]</bitRange>
            </field>
            <field>
              <name>TEIE</name>
              <description>Transfer Error Interrupt Enable</description>
              <bitRange>[4:4]</bitRange>
            </field>
            <field>
              <name>DIR</name>
              <description>Data Transfer Direction</description>
              <bitRange>[5:5]</bitRange>
            </field>
            <field>
              <name>CIRC</name>
              <description>Circular Mode</description>
              <bitRange>[6:6]</bitRange>
            </field>
            <field>
              <name>TRANST</name>
              <description>Transfer Type</description>
              <bitRange>[7:7]</bitRange>
            </field>
            <field>
              <name>PINC</name>
              <description>Peripheral Increment Mode</description>
              <bitRange>[9:8]</bitRange>
            </field>
            <field>
              <name>MINC</name>
              <description>Memory Increment Mode</description>
              <bitRange>[11:10]</bitRange>
            </field>
            <field>
              <name>PSIZE</name>
              <description>Peripheral Size</description>
              <bitRange>[13:12]</bitRange>
            </field>
            <field>
              <name>MSIZE</name>
              <description>Memory Size</description>
              <bitRange>[15:14]</bitRange>
            </field>
            <field>
              <name>PL</name>
              <description>Priority Level</description>
              <bitRange>[18:16]</bitRange>
            </field>
            <field>
              <name>MEM2MEM</name>
              <description>Memory-to-memory Mode</description>
              <bitRange>[19:19]</bitRange>
            </field>
            <field>
              <name>PNORLD</name>
              <description>Peripheral No Reload</description>
              <bitRange>[20:20]</bitRange>
            </field>
            <field>
              <name>MNORLD</name>
              <description>Memory No Reload</description>
              <bitRange>[21:21]</bitRange>
            </field>
            <field>
              <name>BTCSUSP</name>
              <description>Suspend in Block Transfer Complete Interrupt</description>
              <bitRange>[22:22]</bitRange>
            </field>
            <field>
              <name>M2MARB</name>
              <description>Memory-to-memory Mode Arbitration</description>
              <bitRange>[23:23]</bitRange>
            </field>
          </fields>
        </register>
        <register>
          <name>CNDTR1</name>
          <description>desc CNDTR1</description>
          <addressOffset>0xC</addressOffset>
          <fields>
            <field>
              <name>NDT</name>
              <description>Number of Data to Transfer</description>
              <bitRange>[15:0]</bitRange>
            </field>
          </fields>
        </register>
        <register>
          <name>CPAR1</name>
          <description>desc CPAR1</description>
          <addressOffset>0x10</addressOffset>
          <fields>
            <field>
              <name>PA</name>
              <description>Peripheral Address</description>
              <bitRange>[31:0]</bitRange>
            </field>
          </fields>
        </register>
        <register>
          <name>CMAR1</name>
          <description>desc CMAR1</description>
          <addressOffset>0x14</addressOffset>
          <fields>
            <field>
              <name>MA</name>
              <description>Memory Address</description>
              <bitRange>[31:0]</bitRange>
            </field>
          </fields>
        </register>
        <register>
          <name>CCCFGR1</name>
          <addressOffset>0x18</addressOffset>
          <fields>
            <field>
              <name>NBT</name>
              <description>Number of Block to Loop Transfer</description>
              <bitRange>[7:0]</bitRange>
            </field>
            <field>
              <name>NDTL</name>
              <description>Number of Data to Transfer Last Loop</description>
              <bitRange>[31:16]</bitRange>
            </field>
          </fields>
        </register>
        <register>
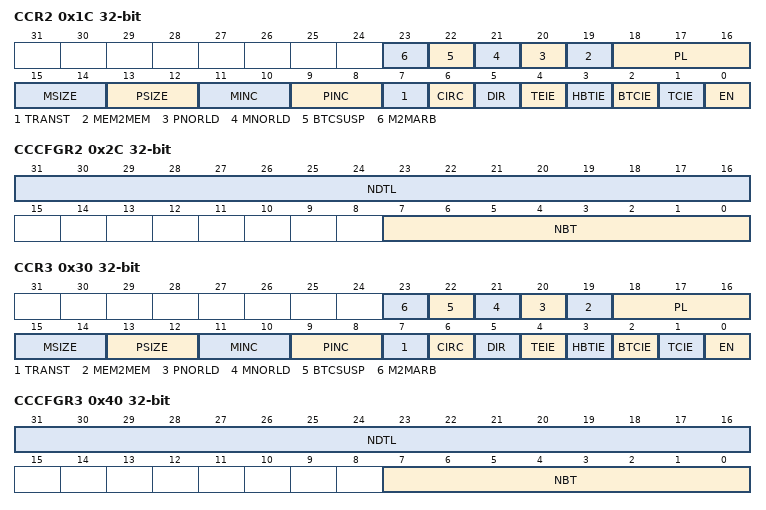
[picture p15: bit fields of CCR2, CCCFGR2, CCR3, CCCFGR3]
          <name>CCR2</name>
          <description>desc CCR2</description>
          <addressOffset>0x1C</addressOffset>
          <fields>
            <field>
              <name>EN</name>
              <description>Channel Enable</description>
              <bitRange>[0:0]</bitRange>
            </field>
            <field>
              <name>TCIE</name>
              <description>Transfer Complete Interrupt Enable</description>
              <bitRange>[1:1]</bitRange>
            </field>
            <field>
              <name>BTCIE</name>
              <description>Block Transfer Complete Interrupt Enable</description>
              <bitRange>[2:2]</bitRange>
            </field>
            <field>
              <name>HBTIE</name>
              <description>Half Block Transfer Complete Interrupt Enable</description>
              <bitRange>[3:3]</bitRange>
            </field>
            <field>
              <name>TEIE</name>
              <description>Transfer Error Interrupt Enable</description>
              <bitRange>[4:4]</bitRange>
            </field>
            <field>
              <name>DIR</name>
              <description>Data Transfer Direction</description>
              <bitRange>[5:5]</bitRange>
            </field>
            <field>
              <name>CIRC</name>
              <description>Circular Mode</description>
              <bitRange>[6:6]</bitRange>
            </field>
            <field>
              <name>TRANST</name>
              <description>Transfer Type</description>
              <bitRange>[7:7]</bitRange>
            </field>
            <field>
              <name>PINC</name>
              <description>Peripheral Increment Mode</description>
              <bitRange>[9:8]</bitRange>
            </field>
            <field>
              <name>MINC</name>
              <description>Memory Increment Mode</description>
              <bitRange>[11:10]</bitRange>
            </field>
            <field>
              <name>PSIZE</name>
              <description>Peripheral Size</description>
              <bitRange>[13:12]</bitRange>
            </field>
            <field>
              <name>MSIZE</name>
              <description>Memory Size</description>
              <bitRange>[15:14]</bitRange>
            </field>
            <field>
              <name>PL</name>
              <description>Priority Level</description>
              <bitRange>[18:16]</bitRange>
            </field>
            <field>
              <name>MEM2MEM</name>
              <description>Memory-to-memory Mode</description>
              <bitRange>[19:19]</bitRange>
            </field>
            <field>
              <name>PNORLD</name>
              <description>Peripheral No Reload</description>
              <bitRange>[20:20]</bitRange>
            </field>
            <field>
              <name>MNORLD</name>
              <description>Memory No Reload</description>
              <bitRange>[21:21]</bitRange>
            </field>
            <field>
              <name>BTCSUSP</name>
              <description>Suspend in Block Transfer Complete Interrupt</description>
              <bitRange>[22:22]</bitRange>
            </field>
            <field>
              <name>M2MARB</name>
              <description>Memory-to-memory Mode Arbitration</description>
              <bitRange>[23:23]</bitRange>
            </field>
          </fields>
        </register>
        <register>
          <name>CNDTR2</name>
          <description>desc CNDTR2</description>
          <addressOffset>0x20</addressOffset>
          <fields>
            <field>
              <name>NDT</name>
              <description>Number of Data to Transfer</description>
              <bitRange>[15:0]</bitRange>
            </field>
          </fields>
        </register>
        <register>
          <name>CPAR2</name>
          <description>desc CPAR2</description>
          <addressOffset>0x24</addressOffset>
          <fields>
            <field>
              <name>PA</name>
              <description>Peripheral Address</description>
              <bitRange>[31:0]</bitRange>
            </field>
          </fields>
        </register>
        <register>
          <name>CMAR2</name>
          <description>desc CMAR2</description>
          <addressOffset>0x28</addressOffset>
          <fields>
            <field>
              <name>MA</name>
              <description>Memory Address</description>
              <bitRange>[31:0]</bitRange>
            </field>
          </fields>
        </register>
        <register>
          <name>CCCFGR2</name>
          <addressOffset>0x2C</addressOffset>
          <fields>
            <field>
              <name>NBT</name>
              <description>Number of Block to Loop Transfer</description>
              <bitRange>[7:0]</bitRange>
            </field>
            <field>
              <name>NDTL</name>
              <description>Number of Data to Transfer Last Loop</description>
              <bitRange>[31:16]</bitRange>
            </field>
          </fields>
        </register>
        <register>
          <name>CCR3</name>
          <description>desc CCR3</description>
          <addressOffset>0x30</addressOffset>
          <fields>
            <field>
              <name>EN</name>
              <description>Channel Enable</description>
              <bitRange>[0:0]</bitRange>
            </field>
            <field>
              <name>TCIE</name>
              <description>Transfer Complete Interrupt Enable</description>
              <bitRange>[1:1]</bitRange>
            </field>
            <field>
              <name>BTCIE</name>
              <description>Block Transfer Complete Interrupt Enable</description>
              <bitRange>[2:2]</bitRange>
            </field>
            <field>
              <name>HBTIE</name>
              <description>Half Block Transfer Complete Interrupt Enable</description>
              <bitRange>[3:3]</bitRange>
            </field>
            <field>
              <name>TEIE</name>
              <description>Transfer Error Interrupt Enable</description>
              <bitRange>[4:4]</bitRange>
            </field>
            <field>
              <name>DIR</name>
              <description>Data Transfer Direction</description>
              <bitRange>[5:5]</bitRange>
            </field>
            <field>
              <name>CIRC</name>
              <description>Circular Mode</description>
              <bitRange>[6:6]</bitRange>
            </field>
            <field>
              <name>TRANST</name>
              <description>Transfer Type</description>
              <bitRange>[7:7]</bitRange>
            </field>
            <field>
              <name>PINC</name>
              <description>Peripheral Increment Mode</description>
              <bitRange>[9:8]</bitRange>
            </field>
            <field>
              <name>MINC</name>
              <description>Memory Increment Mode</description>
              <bitRange>[11:10]</bitRange>
            </field>
            <field>
              <name>PSIZE</name>
              <description>Peripheral Size</description>
              <bitRange>[13:12]</bitRange>
            </field>
            <field>
              <name>MSIZE</name>
              <description>Memory Size</description>
              <bitRange>[15:14]</bitRange>
            </field>
            <field>
              <name>PL</name>
              <description>Priority Level</description>
              <bitRange>[18:16]</bitRange>
            </field>
            <field>
              <name>MEM2MEM</name>
              <description>Memory-to-memory Mode</description>
              <bitRange>[19:19]</bitRange>
            </field>
            <field>
              <name>PNORLD</name>
              <description>Peripheral No Reload</description>
              <bitRange>[20:20]</bitRange>
            </field>
            <field>
              <name>MNORLD</name>
              <description>Memory No Reload</description>
              <bitRange>[21:21]</bitRange>
            </field>
            <field>
              <name>BTCSUSP</name>
              <description>Suspend in Block Transfer Complete Interrupt</description>
              <bitRange>[22:22]</bitRange>
            </field>
            <field>
              <name>M2MARB</name>
              <description>Memory-to-memory Mode Arbitration</description>
              <bitRange>[23:23]</bitRange>
            </field>
          </fields>
        </register>
        <register>
          <name>CNDTR3</name>
          <description>desc CNDTR3</description>
          <addressOffset>0x34</addressOffset>
          <fields>
            <field>
              <name>NDT</name>
              <description>Number of Data to Transfer</description>
              <bitRange>[15:0]</bitRange>
            </field>
          </fields>
        </register>
        <register>
          <name>CPAR3</name>
          <description>desc CPAR3</description>
          <addressOffset>0x38</addressOffset>
          <fields>
            <field>
              <name>PA</name>
              <description>Peripheral Address</description>
              <bitRange>[31:0]</bitRange>
            </field>
          </fields>
        </register>
        <register>
          <name>CMAR3</name>
          <description>desc CMAR3</description>
          <addressOffset>0x3C</addressOffset>
          <fields>
            <field>
              <name>MA</name>
              <description>Memory Address</description>
              <bitRange>[31:0]</bitRange>
            </field>
          </fields>
        </register>
        <register>
          <name>CCCFGR3</name>
          <addressOffset>0x40</addressOffset>
          <fields>
            <field>
              <name>NBT</name>
              <description>Number of Block to Loop Transfer</description>
              <bitRange>[7:0]</bitRange>
            </field>
            <field>
              <name>NDTL</name>
              <description>Number of Data to Transfer Last Loop</description>
              <bitRange>[31:16]</bitRange>
            </field>
          </fields>
        </register>
        <register>
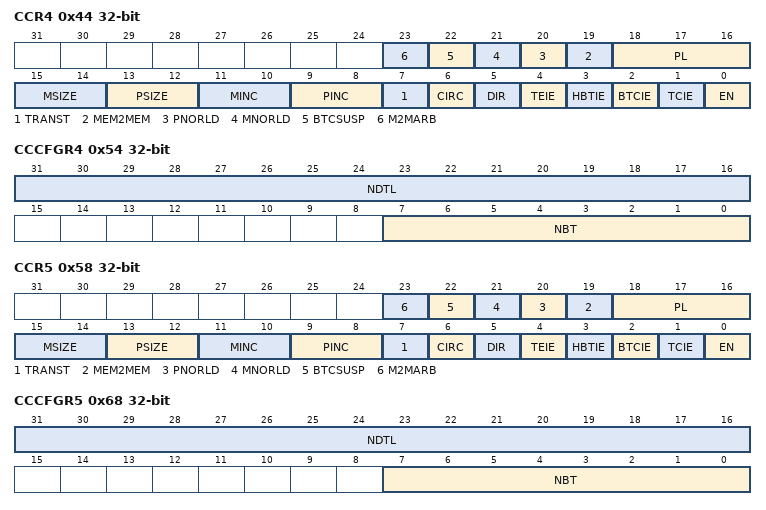
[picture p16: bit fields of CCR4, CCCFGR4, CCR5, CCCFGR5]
          <name>CCR4</name>
          <addressOffset>0x44</addressOffset>
          <fields>
            <field>
              <name>EN</name>
              <description>Channel Enable</description>
              <bitRange>[0:0]</bitRange>
            </field>
            <field>
              <name>TCIE</name>
              <description>Transfer Complete Interrupt Enable</description>
              <bitRange>[1:1]</bitRange>
            </field>
            <field>
              <name>BTCIE</name>
              <description>Block Transfer Complete Interrupt Enable</description>
              <bitRange>[2:2]</bitRange>
            </field>
            <field>
              <name>HBTIE</name>
              <description>Half Block Transfer Complete Interrupt Enable</description>
              <bitRange>[3:3]</bitRange>
            </field>
            <field>
              <name>TEIE</name>
              <description>Transfer Error Interrupt Enable</description>
              <bitRange>[4:4]</bitRange>
            </field>
            <field>
              <name>DIR</name>
              <description>Data Transfer Direction</description>
              <bitRange>[5:5]</bitRange>
            </field>
            <field>
              <name>CIRC</name>
              <description>Circular Mode</description>
              <bitRange>[6:6]</bitRange>
            </field>
            <field>
              <name>TRANST</name>
              <description>Transfer Type</description>
              <bitRange>[7:7]</bitRange>
            </field>
            <field>
              <name>PINC</name>
              <description>Peripheral Increment Mode</description>
              <bitRange>[9:8]</bitRange>
            </field>
            <field>
              <name>MINC</name>
              <description>Memory Increment Mode</description>
              <bitRange>[11:10]</bitRange>
            </field>
            <field>
              <name>PSIZE</name>
              <description>Peripheral Size</description>
              <bitRange>[13:12]</bitRange>
            </field>
            <field>
              <name>MSIZE</name>
              <description>Memory Size</description>
              <bitRange>[15:14]</bitRange>
            </field>
            <field>
              <name>PL</name>
              <description>Priority Level</description>
              <bitRange>[18:16]</bitRange>
            </field>
            <field>
              <name>MEM2MEM</name>
              <description>Memory-to-memory Mode</description>
              <bitRange>[19:19]</bitRange>
            </field>
            <field>
              <name>PNORLD</name>
              <description>Peripheral No Reload</description>
              <bitRange>[20:20]</bitRange>
            </field>
            <field>
              <name>MNORLD</name>
              <description>Memory No Reload</description>
              <bitRange>[21:21]</bitRange>
            </field>
            <field>
              <name>BTCSUSP</name>
              <description>Suspend in Block Transfer Complete Interrupt</description>
              <bitRange>[22:22]</bitRange>
            </field>
            <field>
              <name>M2MARB</name>
              <description>Memory-to-memory Mode Arbitration</description>
              <bitRange>[23:23]</bitRange>
            </field>
          </fields>
        </register>
        <register>
          <name>CNDTR4</name>
          <addressOffset>0x48</addressOffset>
          <fields>
            <field>
              <name>NDT</name>
              <description>Number of Data to Transfer</description>
              <bitRange>[15:0]</bitRange>
            </field>
          </fields>
        </register>
        <register>
          <name>CPAR4</name>
          <addressOffset>0x4C</addressOffset>
          <fields>
            <field>
              <name>PA</name>
              <description>Peripheral Address</description>
              <bitRange>[31:0]</bitRange>
            </field>
          </fields>
        </register>
        <register>
          <name>CMAR4</name>
          <addressOffset>0x50</addressOffset>
          <fields>
            <field>
              <name>MA</name>
              <description>Memory Address</description>
              <bitRange>[31:0]</bitRange>
            </field>
          </fields>
        </register>
        <register>
          <name>CCCFGR4</name>
          <addressOffset>0x54</addressOffset>
          <fields>
            <field>
              <name>NBT</name>
              <description>Number of Block to Loop Transfer</description>
              <bitRange>[7:0]</bitRange>
            </field>
            <field>
              <name>NDTL</name>
              <description>Number of Data to Transfer Last Loop</description>
              <bitRange>[31:16]</bitRange>
            </field>
          </fields>
        </register>
        <register>
          <name>CCR5</name>
          <addressOffset>0x58</addressOffset>
          <fields>
            <field>
              <name>EN</name>
              <description>Channel Enable</description>
              <bitRange>[0:0]</bitRange>
            </field>
            <field>
              <name>TCIE</name>
              <description>Transfer Complete Interrupt Enable</description>
              <bitRange>[1:1]</bitRange>
            </field>
            <field>
              <name>BTCIE</name>
              <description>Block Transfer Complete Interrupt Enable</description>
              <bitRange>[2:2]</bitRange>
            </field>
            <field>
              <name>HBTIE</name>
              <description>Half Block Transfer Complete Interrupt Enable</description>
              <bitRange>[3:3]</bitRange>
            </field>
            <field>
              <name>TEIE</name>
              <description>Transfer Error Interrupt Enable</description>
              <bitRange>[4:4]</bitRange>
            </field>
            <field>
              <name>DIR</name>
              <description>Data Transfer Direction</description>
              <bitRange>[5:5]</bitRange>
            </field>
            <field>
              <name>CIRC</name>
              <description>Circular Mode</description>
              <bitRange>[6:6]</bitRange>
            </field>
            <field>
              <name>TRANST</name>
              <description>Transfer Type</description>
              <bitRange>[7:7]</bitRange>
            </field>
            <field>
              <name>PINC</name>
              <description>Peripheral Increment Mode</description>
              <bitRange>[9:8]</bitRange>
            </field>
            <field>
              <name>MINC</name>
              <description>Memory Increment Mode</description>
              <bitRange>[11:10]</bitRange>
            </field>
            <field>
              <name>PSIZE</name>
              <description>Peripheral Size</description>
              <bitRange>[13:12]</bitRange>
            </field>
            <field>
              <name>MSIZE</name>
              <description>Memory Size</description>
              <bitRange>[15:14]</bitRange>
            </field>
            <field>
              <name>PL</name>
              <description>Priority Level</description>
              <bitRange>[18:16]</bitRange>
            </field>
            <field>
              <name>MEM2MEM</name>
              <description>Memory-to-memory Mode</description>
              <bitRange>[19:19]</bitRange>
            </field>
            <field>
              <name>PNORLD</name>
              <description>Peripheral No Reload</description>
              <bitRange>[20:20]</bitRange>
            </field>
            <field>
              <name>MNORLD</name>
              <description>Memory No Reload</description>
              <bitRange>[21:21]</bitRange>
            </field>
            <field>
              <name>BTCSUSP</name>
              <description>Suspend in Block Transfer Complete Interrupt</description>
              <bitRange>[22:22]</bitRange>
            </field>
            <field>
              <name>M2MARB</name>
              <description>Memory-to-memory Mode Arbitration</description>
              <bitRange>[23:23]</bitRange>
            </field>
          </fields>
        </register>
        <register>
          <name>CNDTR5</name>
          <addressOffset>0x5C</addressOffset>
          <fields>
            <field>
              <name>NDT</name>
              <description>Number of Data to Transfer</description>
              <bitRange>[15:0]</bitRange>
            </field>
          </fields>
        </register>
        <register>
          <name>CPAR5</name>
          <addressOffset>0x60</addressOffset>
          <fields>
            <field>
              <name>PA</name>
              <description>Peripheral Address</description>
              <bitRange>[31:0]</bitRange>
            </field>
          </fields>
        </register>
        <register>
          <name>CMAR5</name>
          <addressOffset>0x64</addressOffset>
          <fields>
            <field>
              <name>MA</name>
              <description>Memory Address</description>
              <bitRange>[31:0]</bitRange>
            </field>
          </fields>
        </register>
        <register>
          <name>CCCFGR5</name>
          <addressOffset>0x68</addressOffset>
          <fields>
            <field>
              <name>NBT</name>
              <description>Number of Block to Loop Transfer</description>
              <bitRange>[7:0]</bitRange>
            </field>
            <field>
              <name>NDTL</name>
              <description>Number of Data to Transfer Last Loop</description>
              <bitRange>[31:16]</bitRange>
            </field>
          </fields>
        </register>
        <register>
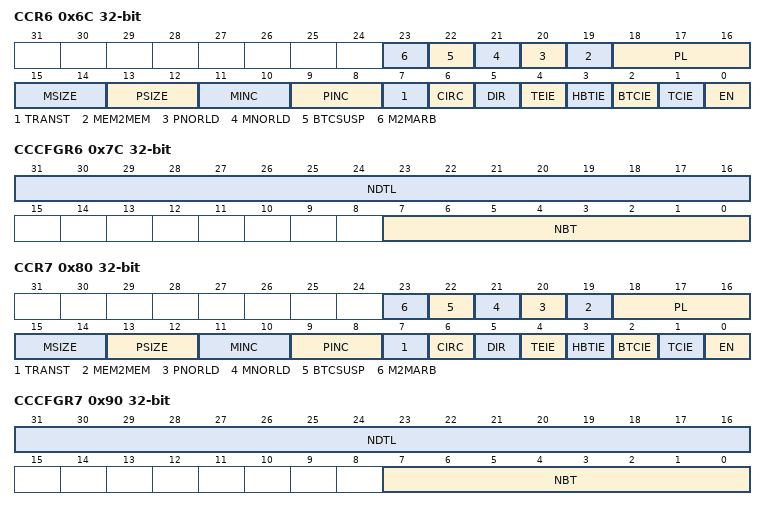
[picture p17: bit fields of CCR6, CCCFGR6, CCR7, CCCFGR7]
          <name>CCR6</name>
          <addressOffset>0x6C</addressOffset>
          <fields>
            <field>
              <name>EN</name>
              <description>Channel Enable</description>
              <bitRange>[0:0]</bitRange>
            </field>
            <field>
              <name>TCIE</name>
              <description>Transfer Complete Interrupt Enable</description>
              <bitRange>[1:1]</bitRange>
            </field>
            <field>
              <name>BTCIE</name>
              <description>Block Transfer Complete Interrupt Enable</description>
              <bitRange>[2:2]</bitRange>
            </field>
            <field>
              <name>HBTIE</name>
              <description>Half Block Transfer Complete Interrupt Enable</description>
              <bitRange>[3:3]</bitRange>
            </field>
            <field>
              <name>TEIE</name>
              <description>Transfer Error Interrupt Enable</description>
              <bitRange>[4:4]</bitRange>
            </field>
            <field>
              <name>DIR</name>
              <description>Data Transfer Direction</description>
              <bitRange>[5:5]</bitRange>
            </field>
            <field>
              <name>CIRC</name>
              <description>Circular Mode</description>
              <bitRange>[6:6]</bitRange>
            </field>
            <field>
              <name>TRANST</name>
              <description>Transfer Type</description>
              <bitRange>[7:7]</bitRange>
            </field>
            <field>
              <name>PINC</name>
              <description>Peripheral Increment Mode</description>
              <bitRange>[9:8]</bitRange>
            </field>
            <field>
              <name>MINC</name>
              <description>Memory Increment Mode</description>
              <bitRange>[11:10]</bitRange>
            </field>
            <field>
              <name>PSIZE</name>
              <description>Peripheral Size</description>
              <bitRange>[13:12]</bitRange>
            </field>
            <field>
              <name>MSIZE</name>
              <description>Memory Size</description>
              <bitRange>[15:14]</bitRange>
            </field>
            <field>
              <name>PL</name>
              <description>Priority Level</description>
              <bitRange>[18:16]</bitRange>
            </field>
            <field>
              <name>MEM2MEM</name>
              <description>Memory-to-memory Mode</description>
              <bitRange>[19:19]</bitRange>
            </field>
            <field>
              <name>PNORLD</name>
              <description>Peripheral No Reload</description>
              <bitRange>[20:20]</bitRange>
            </field>
            <field>
              <name>MNORLD</name>
              <description>Memory No Reload</description>
              <bitRange>[21:21]</bitRange>
            </field>
            <field>
              <name>BTCSUSP</name>
              <description>Suspend in Block Transfer Complete Interrupt</description>
              <bitRange>[22:22]</bitRange>
            </field>
            <field>
              <name>M2MARB</name>
              <description>Memory-to-memory Mode Arbitration</description>
              <bitRange>[23:23]</bitRange>
            </field>
          </fields>
        </register>
        <register>
          <name>CNDTR6</name>
          <addressOffset>0x70</addressOffset>
          <fields>
            <field>
              <name>NDT</name>
              <description>Number of Data to Transfer</description>
              <bitRange>[15:0]</bitRange>
            </field>
          </fields>
        </register>
        <register>
          <name>CPAR6</name>
          <addressOffset>0x74</addressOffset>
          <fields>
            <field>
              <name>PA</name>
              <description>Peripheral Address</description>
              <bitRange>[31:0]</bitRange>
            </field>
          </fields>
        </register>
        <register>
          <name>CMAR6</name>
          <addressOffset>0x78</addressOffset>
          <fields>
            <field>
              <name>MA</name>
              <description>Memory Address</description>
              <bitRange>[31:0]</bitRange>
            </field>
          </fields>
        </register>
        <register>
          <name>CCCFGR6</name>
          <addressOffset>0x7C</addressOffset>
          <fields>
            <field>
              <name>NBT</name>
              <description>Number of Block to Loop Transfer</description>
              <bitRange>[7:0]</bitRange>
            </field>
            <field>
              <name>NDTL</name>
              <description>Number of Data to Transfer Last Loop</description>
              <bitRange>[31:16]</bitRange>
            </field>
          </fields>
        </register>
        <register>
          <name>CCR7</name>
          <addressOffset>0x80</addressOffset>
          <fields>
            <field>
              <name>EN</name>
              <description>Channel Enable</description>
              <bitRange>[0:0]</bitRange>
            </field>
            <field>
              <name>TCIE</name>
              <description>Transfer Complete Interrupt Enable</description>
              <bitRange>[1:1]</bitRange>
            </field>
            <field>
              <name>BTCIE</name>
              <description>Block Transfer Complete Interrupt Enable</description>
              <bitRange>[2:2]</bitRange>
            </field>
            <field>
              <name>HBTIE</name>
              <description>Half Block Transfer Complete Interrupt Enable</description>
              <bitRange>[3:3]</bitRange>
            </field>
            <field>
              <name>TEIE</name>
              <description>Transfer Error Interrupt Enable</description>
              <bitRange>[4:4]</bitRange>
            </field>
            <field>
              <name>DIR</name>
              <description>Data Transfer Direction</description>
              <bitRange>[5:5]</bitRange>
            </field>
            <field>
              <name>CIRC</name>
              <description>Circular Mode</description>
              <bitRange>[6:6]</bitRange>
            </field>
            <field>
              <name>TRANST</name>
              <description>Transfer Type</description>
              <bitRange>[7:7]</bitRange>
            </field>
            <field>
              <name>PINC</name>
              <description>Peripheral Increment Mode</description>
              <bitRange>[9:8]</bitRange>
            </field>
            <field>
              <name>MINC</name>
              <description>Memory Increment Mode</description>
              <bitRange>[11:10]</bitRange>
            </field>
            <field>
              <name>PSIZE</name>
              <description>Peripheral Size</description>
              <bitRange>[13:12]</bitRange>
            </field>
            <field>
              <name>MSIZE</name>
              <description>Memory Size</description>
              <bitRange>[15:14]</bitRange>
            </field>
            <field>
              <name>PL</name>
              <description>Priority Level</description>
              <bitRange>[18:16]</bitRange>
            </field>
            <field>
              <name>MEM2MEM</name>
              <description>Memory-to-memory Mode</description>
              <bitRange>[19:19]</bitRange>
            </field>
            <field>
              <name>PNORLD</name>
              <description>Peripheral No Reload</description>
              <bitRange>[20:20]</bitRange>
            </field>
            <field>
              <name>MNORLD</name>
              <description>Memory No Reload</description>
              <bitRange>[21:21]</bitRange>
            </field>
            <field>
              <name>BTCSUSP</name>
              <description>Suspend in Block Transfer Complete Interrupt</description>
              <bitRange>[22:22]</bitRange>
            </field>
            <field>
              <name>M2MARB</name>
              <description>Memory-to-memory Mode Arbitration</description>
              <bitRange>[23:23]</bitRange>
            </field>
          </fields>
        </register>
        <register>
          <name>CNDTR7</name>
          <addressOffset>0x84</addressOffset>
          <fields>
            <field>
              <name>NDT</name>
              <description>Number of Data to Transfer</description>
              <bitRange>[15:0]</bitRange>
            </field>
          </fields>
        </register>
        <register>
          <name>CPAR7</name>
          <addressOffset>0x88</addressOffset>
          <fields>
            <field>
              <name>PA</name>
              <description>Peripheral Address</description>
              <bitRange>[31:0]</bitRange>
            </field>
          </fields>
        </register>
        <register>
          <name>CMAR7</name>
          <addressOffset>0x8C</addressOffset>
          <fields>
            <field>
              <name>MA</name>
              <description>Memory Address</description>
              <bitRange>[31:0]</bitRange>
            </field>
          </fields>
        </register>
        <register>
          <name>CCCFGR7</name>
          <addressOffset>0x90</addressOffset>
          <fields>
            <field>
              <name>NBT</name>
              <description>Number of Block to Loop Transfer</description>
              <bitRange>[7:0]</bitRange>
            </field>
            <field>
              <name>NDTL</name>
              <description>Number of Data to Transfer Last Loop</description>
              <bitRange>[31:16]</bitRange>
            </field>
          </fields>
        </register>
      </registers>
    </peripheral>
    <peripheral>
      <name>EXTI</name>
      <description>External interrupt/event controller</description>
      <baseAddress>0x40010400</baseAddress>
      <addressBlock>
        <offset>0x0</offset>
        <size>0x400</size>
        <usage>registers</usage>
      </addressBlock>
      <interrupt>
        <name>PVD</name>
        <description>PVD Interrupt through EXTI Lines 16</description>
        <value>1</value>
      </interrupt>
      <interrupt>
        <name>EXTI0_1</name>
        <description>EXTI Line 0 and 1 Interrupt</description>
        <value>5</value>
      </interrupt>
      <interrupt>
        <name>EXTI2_3</name>
        <description>EXTI Line 2 and 3 Interrupt</description>
        <value>6</value>
      </interrupt>
      <interrupt>
        <name>EXTI4_15</name>
        <description>EXTI Line 4 to 15 Interrupt</description>
        <value>7</value>
      </interrupt>
      <registers>
        <register>
          <name>RTSR</name>
          <description>EXTI rising trigger selection register</description>
          <addressOffset>0x0</addressOffset>
          <fields>
            <field>
              <name>RT0</name>
              <bitRange>[0:0]</bitRange>
            </field>
            <field>
              <name>RT1</name>
              <bitRange>[1:1]</bitRange>
            </field>
            <field>
              <name>RT2</name>
              <bitRange>[2:2]</bitRange>
            </field>
            <field>
              <name>RT3</name>
              <bitRange>[3:3]</bitRange>
            </field>
            <field>
              <name>RT4</name>
              <bitRange>[4:4]</bitRange>
            </field>
            <field>
              <name>RT5</name>
              <bitRange>[5:5]</bitRange>
            </field>
            <field>
              <name>RT6</name>
              <bitRange>[6:6]</bitRange>
            </field>
            <field>
              <name>RT7</name>
              <bitRange>[7:7]</bitRange>
            </field>
            <field>
              <name>RT8</name>
              <bitRange>[8:8]</bitRange>
            </field>
            <field>
              <name>RT9</name>
              <bitRange>[9:9]</bitRange>
            </field>
            <field>
              <name>RT10</name>
              <bitRange>[10:10]</bitRange>
            </field>
            <field>
              <name>RT11</name>
              <bitRange>[11:11]</bitRange>
            </field>
            <field>
              <name>RT12</name>
              <bitRange>[12:12]</bitRange>
            </field>
            <field>
              <name>RT13</name>
              <bitRange>[13:13]</bitRange>
            </field>
            <field>
              <name>RT14</name>
              <bitRange>[14:14]</bitRange>
            </field>
            <field>
              <name>RT15</name>
              <bitRange>[15:15]</bitRange>
            </field>
            <field>
              <name>RT16</name>
              <bitRange>[16:16]</bitRange>
            </field>
            <field>
              <name>RT17</name>
              <bitRange>[17:17]</bitRange>
            </field>
            <field>
              <name>RT18</name>
              <bitRange>[18:18]</bitRange>
            </field>
            <field>
              <name>RT19</name>
              <bitRange>[19:19]</bitRange>
            </field>
          </fields>
        </register>
        <register>
          <name>FTSR</name>
          <description>EXTI falling trigger selection register</description>
          <addressOffset>0x4</addressOffset>
          <fields>
            <field>
              <name>FT0</name>
              <bitRange>[0:0]</bitRange>
            </field>
            <field>
              <name>FT1</name>
              <bitRange>[1:1]</bitRange>
            </field>
            <field>
              <name>FT2</name>
              <bitRange>[2:2]</bitRange>
            </field>
            <field>
              <name>FT3</name>
              <bitRange>[3:3]</bitRange>
            </field>
            <field>
              <name>FT4</name>
              <bitRange>[4:4]</bitRange>
            </field>
            <field>
              <name>FT5</name>
              <bitRange>[5:5]</bitRange>
            </field>
            <field>
              <name>FT6</name>
              <bitRange>[6:6]</bitRange>
            </field>
            <field>
              <name>FT7</name>
              <bitRange>[7:7]</bitRange>
            </field>
            <field>
              <name>FT8</name>
              <bitRange>[8:8]</bitRange>
            </field>
            <field>
              <name>FT9</name>
              <bitRange>[9:9]</bitRange>
            </field>
            <field>
              <name>FT10</name>
              <bitRange>[10:10]</bitRange>
            </field>
            <field>
              <name>FT11</name>
              <bitRange>[11:11]</bitRange>
            </field>
            <field>
              <name>FT12</name>
              <bitRange>[12:12]</bitRange>
            </field>
            <field>
              <name>FT13</name>
              <bitRange>[13:13]</bitRange>
            </field>
            <field>
              <name>FT14</name>
              <bitRange>[14:14]</bitRange>
            </field>
            <field>
              <name>FT15</name>
              <bitRange>[15:15]</bitRange>
            </field>
            <field>
              <name>FT16</name>
              <bitRange>[16:16]</bitRange>
            </field>
            <field>
              <name>FT17</name>
              <bitRange>[17:17]</bitRange>
            </field>
            <field>
              <name>FT18</name>
              <bitRange>[18:18]</bitRange>
            </field>
            <field>
              <name>FT19</name>
              <bitRange>[19:19]</bitRange>
            </field>
          </fields>
        </register>
        <register>
          <name>SWIER</name>
          <description>EXTI software interrupt event register</description>
          <addressOffset>0x8</addressOffset>
          <fields>
            <field>
              <name>SWIE0</name>
              <bitRange>[0:0]</bitRange>
            </field>
            <field>
              <name>SWIE1</name>
              <bitRange>[1:1]</bitRange>
            </field>
            <field>
              <name>SWIE2</name>
              <bitRange>[2:2]</bitRange>
            </field>
            <field>
              <name>SWIE3</name>
              <bitRange>[3:3]</bitRange>
            </field>
            <field>
              <name>SWIE4</name>
              <bitRange>[4:4]</bitRange>
            </field>
            <field>
              <name>SWIE5</name>
              <bitRange>[5:5]</bitRange>
            </field>
            <field>
              <name>SWIE6</name>
              <bitRange>[6:6]</bitRange>
            </field>
            <field>
              <name>SWIE7</name>
              <bitRange>[7:7]</bitRange>
            </field>
            <field>
              <name>SWIE8</name>
              <bitRange>[8:8]</bitRange>
            </field>
            <field>
              <name>SWIE9</name>
              <bitRange>[9:9]</bitRange>
            </field>
            <field>
              <name>SWIE10</name>
              <bitRange>[10:10]</bitRange>
            </field>
            <field>
              <name>SWIE11</name>
              <bitRange>[11:11]</bitRange>
            </field>
            <field>
              <name>SWIE12</name>
              <bitRange>[12:12]</bitRange>
            </field>
            <field>
              <name>SWIE13</name>
              <bitRange>[13:13]</bitRange>
            </field>
            <field>
              <name>SWIE14</name>
              <bitRange>[14:14]</bitRange>
            </field>
            <field>
              <name>SWIE15</name>
              <bitRange>[15:15]</bitRange>
            </field>
            <field>
              <name>SWIE16</name>
              <bitRange>[16:16]</bitRange>
            </field>
            <field>
              <name>SWIE17</name>
              <bitRange>[17:17]</bitRange>
            </field>
            <field>
              <name>SWIE18</name>
              <bitRange>[18:18]</bitRange>
            </field>
            <field>
              <name>SWIE19</name>
              <bitRange>[19:19]</bitRange>
            </field>
          </fields>
        </register>
        <register>
          <name>PR</name>
          <description>EXTI pending register</description>
          <addressOffset>0xC</addressOffset>
          <fields>
            <field>
              <name>PR0</name>
              <bitRange>[0:0]</bitRange>
            </field>
            <field>
              <name>PR1</name>
              <bitRange>[1:1]</bitRange>
            </field>
            <field>
              <name>PR2</name>
              <bitRange>[2:2]</bitRange>
            </field>
            <field>
              <name>PR3</name>
              <bitRange>[3:3]</bitRange>
            </field>
            <field>
              <name>PR4</name>
              <bitRange>[4:4]</bitRange>
            </field>
            <field>
              <name>PR5</name>
              <bitRange>[5:5]</bitRange>
            </field>
            <field>
              <name>PR6</name>
              <bitRange>[6:6]</bitRange>
            </field>
            <field>
              <name>PR7</name>
              <bitRange>[7:7]</bitRange>
            </field>
            <field>
              <name>PR8</name>
              <bitRange>[8:8]</bitRange>
            </field>
            <field>
              <name>PR9</name>
              <bitRange>[9:9]</bitRange>
            </field>
            <field>
              <name>PR10</name>
              <bitRange>[10:10]</bitRange>
            </field>
            <field>
              <name>PR11</name>
              <bitRange>[11:11]</bitRange>
            </field>
            <field>
              <name>PR12</name>
              <bitRange>[12:12]</bitRange>
            </field>
            <field>
              <name>PR13</name>
              <bitRange>[13:13]</bitRange>
            </field>
            <field>
              <name>PR14</name>
              <bitRange>[14:14]</bitRange>
            </field>
            <field>
              <name>PR15</name>
              <bitRange>[15:15]</bitRange>
            </field>
            <field>
              <name>PR16</name>
              <bitRange>[16:16]</bitRange>
            </field>
            <field>
              <name>PR17</name>
              <bitRange>[17:17]</bitRange>
            </field>
            <field>
              <name>PR18</name>
              <bitRange>[18:18]</bitRange>
            </field>
            <field>
              <name>PR19</name>
              <bitRange>[19:19]</bitRange>
            </field>
          </fields>
        </register>
        <register>
          <name>IOSEL1</name>
          <addressOffset>0x10</addressOffset>
          <fields>
            <field>
              <name>EXTI0SEL</name>
              <bitRange>[1:0]</bitRange>
              <enumeratedValues>
                <enumeratedValue>
                  <name>0</name>
                  <value>1</value>
                </enumeratedValue>
                <enumeratedValue>
                  <name>1</name>
                  <value>2</value>
                </enumeratedValue>
              </enumeratedValues>
            </field>
            <field>
              <name>EXTI1SEL</name>
              <bitRange>[5:4]</bitRange>
              <enumeratedValues>
                <enumeratedValue>
                  <name>0</name>
                  <value>1</value>
                </enumeratedValue>
                <enumeratedValue>
                  <name>1</name>
                  <value>2</value>
                </enumeratedValue>
              </enumeratedValues>
            </field>
            <field>
              <name>EXTI2SEL</name>
              <bitRange>[9:8]</bitRange>
              <enumeratedValues>
                <enumeratedValue>
                  <name>0</name>
                  <value>1</value>
                </enumeratedValue>
                <enumeratedValue>
                  <name>1</name>
                  <value>2</value>
                </enumeratedValue>
              </enumeratedValues>
            </field>
            <field>
              <name>EXTI3SEL</name>
              <bitRange>[13:12]</bitRange>
              <enumeratedValues>
                <enumeratedValue>
                  <name>0</name>
                  <value>1</value>
                </enumeratedValue>
                <enumeratedValue>
                  <name>1</name>
                  <value>2</value>
                </enumeratedValue>
              </enumeratedValues>
            </field>
            <field>
              <name>EXTI4SEL</name>
              <bitRange>[17:16]</bitRange>
              <enumeratedValues>
                <enumeratedValue>
                  <name>0</name>
                  <value>1</value>
                </enumeratedValue>
                <enumeratedValue>
                  <name>1</name>
                  <value>2</value>
                </enumeratedValue>
              </enumeratedValues>
            </field>
            <field>
              <name>EXTI5SEL</name>
              <bitRange>[21:20]</bitRange>
              <enumeratedValues>
                <enumeratedValue>
                  <name>0</name>
                  <value>1</value>
                </enumeratedValue>
                <enumeratedValue>
                  <name>1</name>
                  <value>2</value>
                </enumeratedValue>
              </enumeratedValues>
            </field>
            <field>
              <name>EXTI6SEL</name>
              <bitRange>[25:24]</bitRange>
              <enumeratedValues>
                <enumeratedValue>
                  <name>0</name>
                  <value>1</value>
                </enumeratedValue>
                <enumeratedValue>
                  <name>1</name>
                  <value>2</value>
                </enumeratedValue>
              </enumeratedValues>
            </field>
            <field>
              <name>EXTI7SEL</name>
              <bitRange>[29:28]</bitRange>
              <enumeratedValues>
                <enumeratedValue>
                  <name>0</name>
                  <value>1</value>
                </enumeratedValue>
                <enumeratedValue>
                  <name>1</name>
                  <value>2</value>
                </enumeratedValue>
              </enumeratedValues>
            </field>
          </fields>
        </register>
        <register>
          <name>IOSEL2</name>
          <addressOffset>0x14</addressOffset>
          <fields>
            <field>
              <name>EXTI8SEL</name>
              <bitRange>[1:0]</bitRange>
              <enumeratedValues>
                <enumeratedValue>
                  <name>0</name>
                  <value>1</value>
                </enumeratedValue>
                <enumeratedValue>
                  <name>1</name>
                  <value>2</value>
                </enumeratedValue>
              </enumeratedValues>
            </field>
            <field>
              <name>EXTI9SEL</name>
              <bitRange>[5:4]</bitRange>
              <enumeratedValues>
                <enumeratedValue>
                  <name>0</name>
                  <value>1</value>
                </enumeratedValue>
                <enumeratedValue>
                  <name>1</name>
                  <value>2</value>
                </enumeratedValue>
              </enumeratedValues>
            </field>
            <field>
              <name>EXTI10SEL</name>
              <bitRange>[9:8]</bitRange>
              <enumeratedValues>
                <enumeratedValue>
                  <name>0</name>
                  <value>1</value>
                </enumeratedValue>
                <enumeratedValue>
                  <name>1</name>
                  <value>2</value>
                </enumeratedValue>
              </enumeratedValues>
            </field>
            <field>
              <name>EXTI11SEL</name>
              <bitRange>[13:12]</bitRange>
              <enumeratedValues>
                <enumeratedValue>
                  <name>0</name>
                  <value>1</value>
                </enumeratedValue>
                <enumeratedValue>
                  <name>1</name>
                  <value>2</value>
                </enumeratedValue>
              </enumeratedValues>
            </field>
            <field>
              <name>EXTI12SEL</name>
              <bitRange>[17:16]</bitRange>
              <enumeratedValues>
                <enumeratedValue>
                  <name>0</name>
                  <value>1</value>
                </enumeratedValue>
                <enumeratedValue>
                  <name>1</name>
                  <value>2</value>
                </enumeratedValue>
              </enumeratedValues>
            </field>
            <field>
              <name>EXTI13SEL</name>
              <bitRange>[21:20]</bitRange>
              <enumeratedValues>
                <enumeratedValue>
                  <name>0</name>
                  <value>1</value>
                </enumeratedValue>
                <enumeratedValue>
                  <name>1</name>
                  <value>2</value>
                </enumeratedValue>
              </enumeratedValues>
            </field>
            <field>
              <name>EXTI14SEL</name>
              <bitRange>[25:24]</bitRange>
              <enumeratedValues>
                <enumeratedValue>
                  <name>0</name>
                  <value>1</value>
                </enumeratedValue>
                <enumeratedValue>
                  <name>1</name>
                  <value>2</value>
                </enumeratedValue>
              </enumeratedValues>
            </field>
            <field>
              <name>EXTI15SEL</name>
              <bitRange>[29:28]</bitRange>
              <enumeratedValues>
                <enumeratedValue>
                  <name>0</name>
                  <value>1</value>
                </enumeratedValue>
                <enumeratedValue>
                  <name>1</name>
                  <value>2</value>
                </enumeratedValue>
              </enumeratedValues>
            </field>
          </fields>
        </register>
        <register>
          <name>IMR</name>
          <description>EXTI CPU wakeup with interrupt mask register</description>
          <addressOffset>0x18</addressOffset>
          <fields>
            <field>
              <name>IM0</name>
              <bitRange>[0:0]</bitRange>
            </field>
            <field>
              <name>IM1</name>
              <bitRange>[1:1]</bitRange>
            </field>
            <field>
              <name>IM2</name>
              <bitRange>[2:2]</bitRange>
            </field>
            <field>
              <name>IM3</name>
              <bitRange>[3:3]</bitRange>
            </field>
            <field>
              <name>IM4</name>
              <bitRange>[4:4]</bitRange>
            </field>
            <field>
              <name>IM5</name>
              <bitRange>[5:5]</bitRange>
            </field>
            <field>
              <name>IM6</name>
              <bitRange>[6:6]</bitRange>
            </field>
            <field>
              <name>IM7</name>
              <bitRange>[7:7]</bitRange>
            </field>
            <field>
              <name>IM8</name>
              <bitRange>[8:8]</bitRange>
            </field>
            <field>
              <name>IM9</name>
              <bitRange>[9:9]</bitRange>
            </field>
            <field>
              <name>IM10</name>
              <bitRange>[10:10]</bitRange>
            </field>
            <field>
              <name>IM11</name>
              <bitRange>[11:11]</bitRange>
            </field>
            <field>
              <name>IM12</name>
              <bitRange>[12:12]</bitRange>
            </field>
            <field>
              <name>IM13</name>
              <bitRange>[13:13]</bitRange>
            </field>
            <field>
              <name>IM14</name>
              <bitRange>[14:14]</bitRange>
            </field>
            <field>
              <name>IM15</name>
              <bitRange>[15:15]</bitRange>
            </field>
            <field>
              <name>IM16</name>
              <bitRange>[16:16]</bitRange>
            </field>
            <field>
              <name>IM17</name>
              <bitRange>[17:17]</bitRange>
            </field>
            <field>
              <name>IM18</name>
              <bitRange>[18:18]</bitRange>
            </field>
            <field>
              <name>IM19</name>
              <bitRange>[19:19]</bitRange>
            </field>
            <field>
              <name>IM20</name>
              <bitRange>[20:20]</bitRange>
            </field>
            <field>
              <name>IM21</name>
              <bitRange>[21:21]</bitRange>
            </field>
            <field>
              <name>IM22</name>
              <bitRange>[22:22]</bitRange>
            </field>
            <field>
              <name>IM23</name>
              <bitRange>[23:23]</bitRange>
            </field>
            <field>
              <name>IM24</name>
              <bitRange>[24:24]</bitRange>
            </field>
            <field>
              <name>IM25</name>
              <bitRange>[25:25]</bitRange>
            </field>
            <field>
              <name>IM26</name>
              <bitRange>[26:26]</bitRange>
            </field>
            <field>
              <name>IM27</name>
              <bitRange>[27:27]</bitRange>
            </field>
            <field>
              <name>IM28</name>
              <bitRange>[28:28]</bitRange>
            </field>
            <field>
              <name>IM29</name>
              <bitRange>[29:29]</bitRange>
            </field>
          </fields>
        </register>
        <register>
          <name>EMR</name>
          <description>EXTI CPU wakeup with event mask register</description>
          <addressOffset>0x1C</addressOffset>
          <fields>
            <field>
              <name>EM0</name>
              <bitRange>[0:0]</bitRange>
            </field>
            <field>
              <name>EM1</name>
              <bitRange>[1:1]</bitRange>
            </field>
            <field>
              <name>EM2</name>
              <bitRange>[2:2]</bitRange>
            </field>
            <field>
              <name>EM3</name>
              <bitRange>[3:3]</bitRange>
            </field>
            <field>
              <name>EM4</name>
              <bitRange>[4:4]</bitRange>
            </field>
            <field>
              <name>EM5</name>
              <bitRange>[5:5]</bitRange>
            </field>
            <field>
              <name>EM6</name>
              <bitRange>[6:6]</bitRange>
            </field>
            <field>
              <name>EM7</name>
              <bitRange>[7:7]</bitRange>
            </field>
            <field>
              <name>EM8</name>
              <bitRange>[8:8]</bitRange>
            </field>
            <field>
              <name>EM9</name>
              <bitRange>[9:9]</bitRange>
            </field>
            <field>
              <name>EM10</name>
              <bitRange>[10:10]</bitRange>
            </field>
            <field>
              <name>EM11</name>
              <bitRange>[11:11]</bitRange>
            </field>
            <field>
              <name>EM12</name>
              <bitRange>[12:12]</bitRange>
            </field>
            <field>
              <name>EM13</name>
              <bitRange>[13:13]</bitRange>
            </field>
            <field>
              <name>EM14</name>
              <bitRange>[14:14]</bitRange>
            </field>
            <field>
              <name>EM15</name>
              <bitRange>[15:15]</bitRange>
            </field>
            <field>
              <name>EM16</name>
              <bitRange>[16:16]</bitRange>
            </field>
            <field>
              <name>EM17</name>
              <bitRange>[17:17]</bitRange>
            </field>
            <field>
              <name>EM18</name>
              <bitRange>[18:18]</bitRange>
            </field>
            <field>
              <name>EM19</name>
              <bitRange>[19:19]</bitRange>
            </field>
            <field>
              <name>EM20</name>
              <bitRange>[20:20]</bitRange>
            </field>
            <field>
              <name>EM21</name>
              <bitRange>[21:21]</bitRange>
            </field>
            <field>
              <name>EM22</name>
              <bitRange>[22:22]</bitRange>
            </field>
            <field>
              <name>EM23</name>
              <bitRange>[23:23]</bitRange>
            </field>
            <field>
              <name>EM24</name>
              <bitRange>[24:24]</bitRange>
            </field>
            <field>
              <name>EM25</name>
              <bitRange>[25:25]</bitRange>
            </field>
            <field>
              <name>EM26</name>
              <bitRange>[26:26]</bitRange>
            </field>
            <field>
              <name>EM27</name>
              <bitRange>[27:27]</bitRange>
            </field>
            <field>
              <name>EM28</name>
              <bitRange>[28:28]</bitRange>
            </field>
            <field>
              <name>EM29</name>
              <bitRange>[29:29]</bitRange>
            </field>
          </fields>
        </register>
      </registers>
    </peripheral>
    <peripheral>
      <name>FLASH</name>
      <description>desc FLASH</description>
      <baseAddress>0x40022000</baseAddress>
      <addressBlock>
        <offset>0x0</offset>
        <size>0x400</size>
        <usage>registers</usage>
      </addressBlock>
      <interrupt>
        <name>FLASH</name>
        <description>FLASH global Interrupt</description>
        <value>3</value>
      </interrupt>
      <registers>
        <register>
          <name>ACR</name>
          <description>desc ACR</description>
          <addressOffset>0x0</addressOffset>
          <fields>
            <field>
              <name>LATENCY</name>
              <description>Latency</description>
              <bitRange>[1:0]</bitRange>
              <enumeratedValues>
                <enumeratedValue>
                  <name>0</name>
                  <value>1</value>
                </enumeratedValue>
                <enumeratedValue>
                  <name>1</name>
                  <value>2</value>
                </enumeratedValue>
              </enumeratedValues>
            </field>
            <field>
              <name>PRFTEN</name>
              <description>Prefect enable</description>
              <bitRange>[8:8]</bitRange>
            </field>
            <field>
              <name>ICEN</name>
              <description>Instruction cache enable</description>
              <bitRange>[9:9]</bitRange>
            </field>
            <field>
              <name>DCEN</name>
              <description>Data cache enable</description>
              <bitRange>[10:10]</bitRange>
            </field>
          </fields>
        </register>
        <register>
          <name>KEYR</name>
          <description>desc KEYR</description>
          <addressOffset>0x8</addressOffset>
          <fields>
            <field>
              <name>KEY</name>
              <description>Flash CR key</description>
              <bitRange>[31:0]</bitRange>
              <access>write-only</access>
            </field>
          </fields>
        </register>
        <register>
          <name>OPTKEYR</name>
          <description>desc OPTKEYR</description>
          <addressOffset>0xC</addressOffset>
          <fields>
            <field>
              <name>OPTKEY</name>
              <description>Flash Option key</description>
              <bitRange>[31:0]</bitRange>
              <access>write-only</access>
            </field>
          </fields>
        </register>
        <register>
          <name>SR</name>
          <description>desc SR</description>
          <addressOffset>0x10</addressOffset>
          <fields>
            <field>
              <name>EOP</name>
              <description>End of operation</description>
              <bitRange>[0:0]</bitRange>
            </field>
            <field>
              <name>WRPERR</name>
              <description>Write protection error</description>
              <bitRange>[4:4]</bitRange>
            </field>
            <field>
              <name>RDERR0</name>
              <description>Bank0 pcrop read error</description>
              <bitRange>[11:11]</bitRange>
            </field>
            <field>
              <name>RDERR1</name>
              <description>Bank1 pcrop read error</description>
              <bitRange>[12:12]</bitRange>
            </field>
            <field>
              <name>USRLOCK</name>
              <description>Userdata Lock</description>
              <bitRange>[13:13]</bitRange>
              <access>read-only</access>
            </field>
            <field>
              <name>OPTVERR</name>
              <description>Option and trimming bits loading validity error</description>
              <bitRange>[15:15]</bitRange>
            </field>
            <field>
              <name>BSY0</name>
              <description>Bank0 Busy</description>
              <bitRange>[16:16]</bitRange>
              <access>read-only</access>
            </field>
            <field>
              <name>BSY1</name>
              <description>Bank1 Busy</description>
              <bitRange>[17:17]</bitRange>
              <access>read-only</access>
            </field>
          </fields>
        </register>
        <register>
          <name>CR</name>
          <description>desc CR</description>
          <addressOffset>0x14</addressOffset>
          <fields>
            <field>
              <name>PG</name>
              <description>Page Program</description>
              <bitRange>[0:0]</bitRange>
            </field>
            <field>
              <name>PER</name>
              <description>Page Erase</description>
              <bitRange>[1:1]</bitRange>
            </field>
            <field>
              <name>MER0</name>
              <description>Bank 0 Mass Erase</description>
              <bitRange>[2:2]</bitRange>
            </field>
            <field>
              <name>MER1</name>
              <description>Bank 1 Mass Erase</description>
              <bitRange>[3:3]</bitRange>
            </field>
            <field>
              <name>UPG</name>
              <description>Userdata Program</description>
              <bitRange>[4:4]</bitRange>
            </field>
            <field>
              <name>UPER</name>
              <description>Userdata Page Erase</description>
              <bitRange>[5:5]</bitRange>
            </field>
            <field>
              <name>SER</name>
              <description>Sector Erase</description>
              <bitRange>[11:11]</bitRange>
            </field>
            <field>
              <name>OPTSTRT</name>
              <description>Option bytes Programming Start</description>
              <bitRange>[17:17]</bitRange>
            </field>
            <field>
              <name>UPGSTRT</name>
              <description>Userdata Programming Start</description>
              <bitRange>[18:18]</bitRange>
            </field>
            <field>
              <name>PGSTRT</name>
              <description>Programming Start</description>
              <bitRange>[19:19]</bitRange>
            </field>
            <field>
              <name>RDERR0IE</name>
              <description>Bank0 pcrop read error interrupt enable</description>
              <bitRange>[22:22]</bitRange>
            </field>
            <field>
              <name>RDERR1IE</name>
              <description>Bank1 pcrop read error interrupt enable</description>
              <bitRange>[23:23]</bitRange>
            </field>
            <field>
              <name>EOPIE</name>
              <description>End of operation interrupt enable</description>
              <bitRange>[24:24]</bitRange>
            </field>
            <field>
              <name>ERRIE</name>
              <description>Error interrupt enable</description>
              <bitRange>[25:25]</bitRange>
            </field>
            <field>
              <name>OBL_LAUNCH</name>
              <description>Force the option bytes loading</description>
              <bitRange>[27:27]</bitRange>
            </field>
            <field>
              <name>OPTLOCK</name>
              <description>Option Lock</description>
              <bitRange>[30:30]</bitRange>
            </field>
            <field>
              <name>LOCK</name>
              <description>Lock</description>
              <bitRange>[31:31]</bitRange>
            </field>
          </fields>
        </register>
        <register>
          <name>ECCR</name>
          <addressOffset>0x18</addressOffset>
          <fields>
            <field>
              <name>ADDR_ECC</name>
              <description>ECC fail address</description>
              <bitRange>[16:0]</bitRange>
              <access>read-only</access>
            </field>
            <field>
              <name>BK_ECC</name>
              <description>ECC fail bank</description>
              <bitRange>[21:21]</bitRange>
              <access>read-only</access>
            </field>
            <field>
              <name>SYSF_ECC</name>
              <description>System Flash ECC fail</description>
              <bitRange>[22:22]</bitRange>
              <access>read-only</access>
            </field>
            <field>
              <name>ECCCIE</name>
              <description>ECC correction interrupt enable</description>
              <bitRange>[24:24]</bitRange>
            </field>
            <field>
              <name>ECCC</name>
              <description>ECC correction</description>
              <bitRange>[30:30]</bitRange>
            </field>
            <field>
              <name>ECCD</name>
              <description>ECC detection</description>
              <bitRange>[31:31]</bitRange>
            </field>
          </fields>
        </register>
        <register>
          <name>OPTR</name>
          <description>desc OPTR</description>
          <addressOffset>0x20</addressOffset>
          <fields>
            <field>
              <name>RDP</name>
              <description>Read Protection</description>
              <bitRange>[7:0]</bitRange>
            </field>
            <field>
              <name>NRST_STANDBY</name>
              <description>nrst standby</description>
              <bitRange>[8:8]</bitRange>
            </field>
            <field>
              <name>NRST_STOP</name>
              <description>nrst stop</description>
              <bitRange>[9:9]</bitRange>
            </field>
            <field>
              <name>IWDG_STDBY</name>
              <description>IWDG Standy Count Control</description>
              <bitRange>[10:10]</bitRange>
            </field>
            <field>
              <name>IWDG_STOP</name>
              <description>IWDG Stop Count Control</description>
              <bitRange>[11:11]</bitRange>
            </field>
            <field>
              <name>IWDG_SW</name>
              <description>IWDG Software Enable</description>
              <bitRange>[12:12]</bitRange>
            </field>
            <field>
              <name>WWDG_SW</name>
              <description>WWDG Software Enable</description>
              <bitRange>[13:13]</bitRange>
            </field>
            <field>
              <name>NRST_MODE</name>
              <description>nrst mode</description>
              <bitRange>[14:14]</bitRange>
            </field>
            <field>
              <name>NBOOT1</name>
              <description>nboot1</description>
              <bitRange>[15:15]</bitRange>
            </field>
            <field>
              <name>BOR_EN</name>
              <description>BOR enable</description>
              <bitRange>[16:16]</bitRange>
            </field>
            <field>
              <name>BOR_LEV</name>
              <description>BOR Level</description>
              <bitRange>[19:17]</bitRange>
              <enumeratedValues>
                <enumeratedValue>
                  <name>0</name>
                  <value>1</value>
                </enumeratedValue>
                <enumeratedValue>
                  <name>1</name>
                  <value>2</value>
                </enumeratedValue>
                <enumeratedValue>
                  <name>2</name>
                  <value>4</value>
                </enumeratedValue>
              </enumeratedValues>
            </field>
            <field>
              <name>SRAM_PE</name>
              <description>sram parity enable</description>
              <bitRange>[20:20]</bitRange>
            </field>
            <field>
              <name>SWD_MODE</name>
              <description>SWD mode</description>
              <bitRange>[22:21]</bitRange>
              <enumeratedValues>
                <enumeratedValue>
                  <name>0</name>
                  <value>1</value>
                </enumeratedValue>
                <enumeratedValue>
                  <name>1</name>
                  <value>2</value>
                </enumeratedValue>
              </enumeratedValues>
            </field>
            <field>
              <name>BFB</name>
              <description>Boot Flash Bank</description>
              <bitRange>[23:23]</bitRange>
            </field>
            <field>
              <name>BOOT_LOCK</name>
              <description>Boot Lock</description>
              <bitRange>[24:24]</bitRange>
            </field>
            <field>
              <name>ECC_EN</name>
              <description>ECC enable</description>
              <bitRange>[25:25]</bitRange>
            </field>
          </fields>
        </register>
        <register>
          <name>WRPR</name>
          <description>desc WRPR</description>
          <addressOffset>0x28</addressOffset>
          <fields>
            <field>
              <name>BK0_WRPX</name>
              <description>Bank0 Sector Write Protection</description>
              <bitRange>[15:0]</bitRange>
            </field>
            <field>
              <name>BK1_WRPX</name>
              <description>Bank1 Sector Write Protection</description>
              <bitRange>[31:16]</bitRange>
            </field>
          </fields>
        </register>
        <register>
          <name>PCROPR0</name>
          <addressOffset>0x30</addressOffset>
          <fields>
            <field>
              <name>PCROP0SR</name>
              <description>Bank0 pcrop start address</description>
              <bitRange>[8:0]</bitRange>
            </field>
            <field>
              <name>PCROP0ER</name>
              <description>Bank0 pcrop end address</description>
              <bitRange>[24:16]</bitRange>
            </field>
          </fields>
        </register>
        <register>
          <name>PCROPR1</name>
          <addressOffset>0x34</addressOffset>
          <fields>
            <field>
              <name>PCROP1SR</name>
              <description>Bank1 pcrop start address</description>
              <bitRange>[8:0]</bitRange>
            </field>
            <field>
              <name>PCROP1ER</name>
              <description>Bank1 pcrop end address</description>
              <bitRange>[24:16]</bitRange>
            </field>
          </fields>
        </register>
        <register>
          <name>LPCR</name>
          <addressOffset>0x90</addressOffset>
          <fields>
            <field>
              <name>SLEEP_EN</name>
              <description>Sleep enable</description>
              <bitRange>[0:0]</bitRange>
            </field>
            <field>
              <name>SLEEP_TIME</name>
              <description>Sleep time</description>
              <bitRange>[15:8]</bitRange>
            </field>
            <field>
              <name>LPRUN_ENTERT</name>
              <description>Low power run mode enter time</description>
              <bitRange>[18:16]</bitRange>
              <enumeratedValues>
                <enumeratedValue>
                  <name>0</name>
                  <value>1</value>
                </enumeratedValue>
                <enumeratedValue>
                  <name>1</name>
                  <value>2</value>
                </enumeratedValue>
                <enumeratedValue>
                  <name>2</name>
                  <value>4</value>
                </enumeratedValue>
              </enumeratedValues>
            </field>
            <field>
              <name>LPRUN_EXITT</name>
              <description>Low power run mode exit time</description>
              <bitRange>[22:20]</bitRange>
              <enumeratedValues>
                <enumeratedValue>
                  <name>0</name>
                  <value>1</value>
                </enumeratedValue>
                <enumeratedValue>
                  <name>1</name>
                  <value>2</value>
                </enumeratedValue>
                <enumeratedValue>
                  <name>2</name>
                  <value>4</value>
                </enumeratedValue>
              </enumeratedValues>
            </field>
          </fields>
        </register>
        <register>
          <name>TS0</name>
          <description>desc TS0</description>
          <addressOffset>0x100</addressOffset>
          <fields>
            <field>
              <name>TS0</name>
              <description>TS0</description>
              <bitRange>[8:0]</bitRange>
            </field>
          </fields>
        </register>
        <register>
          <name>TS1</name>
          <description>desc TS1</description>
          <addressOffset>0x104</addressOffset>
          <fields>
            <field>
              <name>TS1</name>
              <description>TS1</description>
              <bitRange>[10:0]</bitRange>
            </field>
          </fields>
        </register>
        <register>
          <name>TS2P</name>
          <description>desc TS2P</description>
          <addressOffset>0x108</addressOffset>
          <fields>
            <field>
              <name>TS2P</name>
              <description>TS2P</description>
              <bitRange>[8:0]</bitRange>
            </field>
          </fields>
        </register>
        <register>
          <name>TPS3</name>
          <description>desc TPS3</description>
          <addressOffset>0x10C</addressOffset>
          <fields>
            <field>
              <name>TPS3</name>
              <description>TPS3</description>
              <bitRange>[12:0]</bitRange>
            </field>
          </fields>
        </register>
        <register>
          <name>TS3</name>
          <description>desc TS3</description>
          <addressOffset>0x110</addressOffset>
          <fields>
            <field>
              <name>TS3</name>
              <description>TS3</description>
              <bitRange>[8:0]</bitRange>
            </field>
          </fields>
        </register>
        <register>
          <name>PERTPE</name>
          <description>desc PERTPE</description>
          <addressOffset>0x114</addressOffset>
          <fields>
            <field>
              <name>PERTPE</name>
              <description>PERTPE</description>
              <bitRange>[17:0]</bitRange>
            </field>
          </fields>
        </register>
        <register>
          <name>SMERTPE</name>
          <description>desc SMERTPE</description>
          <addressOffset>0x118</addressOffset>
          <fields>
            <field>
              <name>SMERTPE</name>
              <description>SMERTPE</description>
              <bitRange>[17:0]</bitRange>
            </field>
          </fields>
        </register>
        <register>
          <name>PRGTPE</name>
          <description>desc PRGTPE</description>
          <addressOffset>0x11C</addressOffset>
          <fields>
            <field>
              <name>PRGTPE</name>
              <description>PRGTPE</description>
              <bitRange>[15:0]</bitRange>
            </field>
          </fields>
        </register>
        <register>
          <name>PRETPE</name>
          <description>desc PRETPE</description>
          <addressOffset>0x120</addressOffset>
          <fields>
            <field>
              <name>PRETPE</name>
              <description>PRETPE</description>
              <bitRange>[13:0]</bitRange>
            </field>
          </fields>
        </register>
        <register>
          <name>TACLK2PW</name>
          <addressOffset>0x124</addressOffset>
          <fields>
            <field>
              <name>TACLK2PW</name>
              <description>TACLK2PW</description>
              <bitRange>[7:0]</bitRange>
            </field>
          </fields>
        </register>
      </registers>
    </peripheral>
    <peripheral>
      <name>GPIOA</name>
      <groupName>GPIO</groupName>
      <description>General-purpose I/Os</description>
      <baseAddress>0x50000000</baseAddress>
      <addressBlock>
        <offset>0x0</offset>
        <size>0x400</size>
        <usage>registers</usage>
      </addressBlock>
      <registers>
        <register>
          <name>MODER</name>
          <description>GPIO port mode register</description>
          <addressOffset>0x0</addressOffset>
          <fields>
            <field>
              <name>MODER0</name>
              <description>GPIOA0 MODE</description>
              <bitRange>[1:0]</bitRange>
            </field>
            <field>
              <name>MODER1</name>
              <description>GPIOA1 MODE</description>
              <bitRange>[3:2]</bitRange>
            </field>
            <field>
              <name>MODER2</name>
              <description>GPIOA2 MODE</description>
              <bitRange>[5:4]</bitRange>
            </field>
            <field>
              <name>MODER3</name>
              <description>GPIOA3 MODE</description>
              <bitRange>[7:6]</bitRange>
            </field>
            <field>
              <name>MODER4</name>
              <description>GPIOA4 MODE</description>
              <bitRange>[9:8]</bitRange>
            </field>
            <field>
              <name>MODER5</name>
              <description>GPIOA5 MODE</description>
              <bitRange>[11:10]</bitRange>
            </field>
            <field>
              <name>MODER6</name>
              <description>GPIOA6 MODE</description>
              <bitRange>[13:12]</bitRange>
            </field>
            <field>
              <name>MODER7</name>
              <description>GPIOA7 MODE</description>
              <bitRange>[15:14]</bitRange>
            </field>
            <field>
              <name>MODER8</name>
              <description>GPIOA8 MODE</description>
              <bitRange>[17:16]</bitRange>
            </field>
            <field>
              <name>MODER9</name>
              <description>GPIOA9 MODE</description>
              <bitRange>[19:18]</bitRange>
            </field>
            <field>
              <name>MODER10</name>
              <description>GPIOA10 MODE</description>
              <bitRange>[21:20]</bitRange>
            </field>
            <field>
              <name>MODER11</name>
              <description>GPIOA11 MODE</description>
              <bitRange>[23:22]</bitRange>
            </field>
            <field>
              <name>MODER12</name>
              <description>GPIOA12 MODE</description>
              <bitRange>[25:24]</bitRange>
            </field>
            <field>
              <name>MODER13</name>
              <description>GPIOA13 MODE</description>
              <bitRange>[27:26]</bitRange>
            </field>
            <field>
              <name>MODER14</name>
              <description>GPIOA14 MODE</description>
              <bitRange>[29:28]</bitRange>
            </field>
            <field>
              <name>MODER15</name>
              <description>GPIOA15 MODE</description>
              <bitRange>[31:30]</bitRange>
            </field>
          </fields>
        </register>
        <register>
          <name>OTYPER</name>
          <description>GPIO port output type register</description>
          <addressOffset>0x4</addressOffset>
          <fields>
            <field>
              <name>OT0</name>
              <description>GPIOA0 Output type</description>
              <bitRange>[0:0]</bitRange>
            </field>
            <field>
              <name>OT1</name>
              <description>GPIOA1 Output type</description>
              <bitRange>[1:1]</bitRange>
            </field>
            <field>
              <name>OT2</name>
              <description>GPIOA2 Output type</description>
              <bitRange>[2:2]</bitRange>
            </field>
            <field>
              <name>OT3</name>
              <description>GPIOA3 Output type</description>
              <bitRange>[3:3]</bitRange>
            </field>
            <field>
              <name>OT4</name>
              <description>GPIOA4 Output type</description>
              <bitRange>[4:4]</bitRange>
            </field>
            <field>
              <name>OT5</name>
              <description>GPIOA5 Output type</description>
              <bitRange>[5:5]</bitRange>
            </field>
            <field>
              <name>OT6</name>
              <description>GPIOA6 Output type</description>
              <bitRange>[6:6]</bitRange>
            </field>
            <field>
              <name>OT7</name>
              <description>GPIOA7 Output type</description>
              <bitRange>[7:7]</bitRange>
            </field>
            <field>
              <name>OT8</name>
              <description>GPIOA8 Output type</description>
              <bitRange>[8:8]</bitRange>
            </field>
            <field>
              <name>OT9</name>
              <description>GPIOA9 Output type</description>
              <bitRange>[9:9]</bitRange>
            </field>
            <field>
              <name>OT10</name>
              <description>GPIOA10 Output type</description>
              <bitRange>[10:10]</bitRange>
            </field>
            <field>
              <name>OT11</name>
              <description>GPIOA11 Output type</description>
              <bitRange>[11:11]</bitRange>
            </field>
            <field>
              <name>OT12</name>
              <description>GPIOA12 Output type</description>
              <bitRange>[12:12]</bitRange>
            </field>
            <field>
              <name>OT13</name>
              <description>GPIOA13 Output type</description>
              <bitRange>[13:13]</bitRange>
            </field>
            <field>
              <name>OT14</name>
              <description>GPIOA14 Output type</description>
              <bitRange>[14:14]</bitRange>
            </field>
            <field>
              <name>OT15</name>
              <description>GPIOA15 Output type</description>
              <bitRange>[15:15]</bitRange>
            </field>
          </fields>
        </register>
        <register>
          <name>OSPDDER</name>
          <addressOffset>0x8</addressOffset>
          <fields>
            <field>
              <name>OSPEED0</name>
              <description>GPIOA0 output speed</description>
              <bitRange>[1:0]</bitRange>
            </field>
            <field>
              <name>OSPEED1</name>
              <description>GPIOA1 output speed</description>
              <bitRange>[3:2]</bitRange>
            </field>
            <field>
              <name>OSPEED2</name>
              <description>GPIOA2 output speed</description>
              <bitRange>[5:4]</bitRange>
            </field>
            <field>
              <name>OSPEED3</name>
              <description>GPIOA3 output speed</description>
              <bitRange>[7:6]</bitRange>
            </field>
            <field>
              <name>OSPEED4</name>
              <description>GPIOA4 output speed</description>
              <bitRange>[9:8]</bitRange>
            </field>
            <field>
              <name>OSPEED5</name>
              <description>GPIOA5 output speed</description>
              <bitRange>[11:10]</bitRange>
            </field>
            <field>
              <name>OSPEED6</name>
              <description>GPIOA6 output speed</description>
              <bitRange>[13:12]</bitRange>
            </field>
            <field>
              <name>OSPEED7</name>
              <description>GPIOA7 output speed</description>
              <bitRange>[15:14]</bitRange>
            </field>
            <field>
              <name>OSPEED8</name>
              <description>GPIOA8 output speed</description>
              <bitRange>[17:16]</bitRange>
            </field>
            <field>
              <name>OSPEED9</name>
              <description>GPIOA9 output speed</description>
              <bitRange>[19:18]</bitRange>
            </field>
            <field>
              <name>OSPEED10</name>
              <description>GPIOA10 output speed</description>
              <bitRange>[21:20]</bitRange>
            </field>
            <field>
              <name>OSPEED11</name>
              <description>GPIOA11 output speed</description>
              <bitRange>[23:22]</bitRange>
            </field>
            <field>
              <name>OSPEED12</name>
              <description>GPIOA12 output speed</description>
              <bitRange>[25:24]</bitRange>
            </field>
            <field>
              <name>OSPEED13</name>
              <description>GPIOA13 output speed</description>
              <bitRange>[27:26]</bitRange>
            </field>
            <field>
              <name>OSPEED14</name>
              <description>GPIOA14 output speed</description>
              <bitRange>[29:28]</bitRange>
            </field>
            <field>
              <name>OSPEED15</name>
              <description>GPIOA15 output speed</description>
              <bitRange>[31:30]</bitRange>
            </field>
          </fields>
        </register>
        <register>
          <name>PUPDR</name>
          <description>GPIO port pull-up/pull-down register</description>
          <addressOffset>0xC</addressOffset>
          <fields>
            <field>
              <name>PUPD0</name>
              <description>GPIOA0 pull up/pull down</description>
              <bitRange>[1:0]</bitRange>
              <enumeratedValues>
                <enumeratedValue>
                  <name>0</name>
                  <value>1</value>
                </enumeratedValue>
                <enumeratedValue>
                  <name>1</name>
                  <value>2</value>
                </enumeratedValue>
              </enumeratedValues>
            </field>
            <field>
              <name>PUPD1</name>
              <description>GPIOA1 pull up/pull down</description>
              <bitRange>[3:2]</bitRange>
              <enumeratedValues>
                <enumeratedValue>
                  <name>0</name>
                  <value>1</value>
                </enumeratedValue>
                <enumeratedValue>
                  <name>1</name>
                  <value>2</value>
                </enumeratedValue>
              </enumeratedValues>
            </field>
            <field>
              <name>PUPD2</name>
              <description>GPIOA2 pull up/pull down</description>
              <bitRange>[5:4]</bitRange>
              <enumeratedValues>
                <enumeratedValue>
                  <name>0</name>
                  <value>1</value>
                </enumeratedValue>
                <enumeratedValue>
                  <name>1</name>
                  <value>2</value>
                </enumeratedValue>
              </enumeratedValues>
            </field>
            <field>
              <name>PUPD3</name>
              <description>GPIOA3 pull up/pull down</description>
              <bitRange>[7:6]</bitRange>
              <enumeratedValues>
                <enumeratedValue>
                  <name>0</name>
                  <value>1</value>
                </enumeratedValue>
                <enumeratedValue>
                  <name>1</name>
                  <value>2</value>
                </enumeratedValue>
              </enumeratedValues>
            </field>
            <field>
              <name>PUPD4</name>
              <description>GPIOA4 pull up/pull down</description>
              <bitRange>[9:8]</bitRange>
              <enumeratedValues>
                <enumeratedValue>
                  <name>0</name>
                  <value>1</value>
                </enumeratedValue>
                <enumeratedValue>
                  <name>1</name>
                  <value>2</value>
                </enumeratedValue>
              </enumeratedValues>
            </field>
            <field>
              <name>PUPD5</name>
              <description>GPIOA5 pull up/pull down</description>
              <bitRange>[11:10]</bitRange>
              <enumeratedValues>
                <enumeratedValue>
                  <name>0</name>
                  <value>1</value>
                </enumeratedValue>
                <enumeratedValue>
                  <name>1</name>
                  <value>2</value>
                </enumeratedValue>
              </enumeratedValues>
            </field>
            <field>
              <name>PUPD6</name>
              <description>GPIOA6 pull up/pull down</description>
              <bitRange>[13:12]</bitRange>
              <enumeratedValues>
                <enumeratedValue>
                  <name>0</name>
                  <value>1</value>
                </enumeratedValue>
                <enumeratedValue>
                  <name>1</name>
                  <value>2</value>
                </enumeratedValue>
              </enumeratedValues>
            </field>
            <field>
              <name>PUPD7</name>
              <description>GPIOA7 pull up/pull down</description>
              <bitRange>[15:14]</bitRange>
              <enumeratedValues>
                <enumeratedValue>
                  <name>0</name>
                  <value>1</value>
                </enumeratedValue>
                <enumeratedValue>
                  <name>1</name>
                  <value>2</value>
                </enumeratedValue>
              </enumeratedValues>
            </field>
            <field>
              <name>PUPD8</name>
              <description>GPIOA8 pull up/pull down</description>
              <bitRange>[17:16]</bitRange>
              <enumeratedValues>
                <enumeratedValue>
                  <name>0</name>
                  <value>1</value>
                </enumeratedValue>
                <enumeratedValue>
                  <name>1</name>
                  <value>2</value>
                </enumeratedValue>
              </enumeratedValues>
            </field>
            <field>
              <name>PUPD9</name>
              <description>GPIOA9 pull up/pull down</description>
              <bitRange>[19:18]</bitRange>
              <enumeratedValues>
                <enumeratedValue>
                  <name>0</name>
                  <value>1</value>
                </enumeratedValue>
                <enumeratedValue>
                  <name>1</name>
                  <value>2</value>
                </enumeratedValue>
              </enumeratedValues>
            </field>
            <field>
              <name>PUPD10</name>
              <description>GPIOA10 pull up/pull down</description>
              <bitRange>[21:20]</bitRange>
              <enumeratedValues>
                <enumeratedValue>
                  <name>0</name>
                  <value>1</value>
                </enumeratedValue>
                <enumeratedValue>
                  <name>1</name>
                  <value>2</value>
                </enumeratedValue>
              </enumeratedValues>
            </field>
            <field>
              <name>PUPD11</name>
              <description>GPIOA11 pull up/pull down</description>
              <bitRange>[23:22]</bitRange>
              <enumeratedValues>
                <enumeratedValue>
                  <name>0</name>
                  <value>1</value>
                </enumeratedValue>
                <enumeratedValue>
                  <name>1</name>
                  <value>2</value>
                </enumeratedValue>
              </enumeratedValues>
            </field>
            <field>
              <name>PUPD12</name>
              <description>GPIOA12 pull up/pull down</description>
              <bitRange>[25:24]</bitRange>
              <enumeratedValues>
                <enumeratedValue>
                  <name>0</name>
                  <value>1</value>
                </enumeratedValue>
                <enumeratedValue>
                  <name>1</name>
                  <value>2</value>
                </enumeratedValue>
              </enumeratedValues>
            </field>
            <field>
              <name>PUPD13</name>
              <description>GPIOA13 pull up/pull down</description>
              <bitRange>[27:26]</bitRange>
              <enumeratedValues>
                <enumeratedValue>
                  <name>0</name>
                  <value>1</value>
                </enumeratedValue>
                <enumeratedValue>
                  <name>1</name>
                  <value>2</value>
                </enumeratedValue>
              </enumeratedValues>
            </field>
            <field>
              <name>PUPD14</name>
              <description>GPIOA14 pull up/pull down</description>
              <bitRange>[29:28]</bitRange>
              <enumeratedValues>
                <enumeratedValue>
                  <name>0</name>
                  <value>1</value>
                </enumeratedValue>
                <enumeratedValue>
                  <name>1</name>
                  <value>2</value>
                </enumeratedValue>
              </enumeratedValues>
            </field>
            <field>
              <name>PUPD15</name>
              <description>GPIOA15 pull up/pull down</description>
              <bitRange>[31:30]</bitRange>
              <enumeratedValues>
                <enumeratedValue>
                  <name>0</name>
                  <value>1</value>
                </enumeratedValue>
                <enumeratedValue>
                  <name>1</name>
                  <value>2</value>
                </enumeratedValue>
              </enumeratedValues>
            </field>
          </fields>
        </register>
        <register>
          <name>IDR</name>
          <description>GPIO port input data register</description>
          <addressOffset>0x10</addressOffset>
          <fields>
            <field>
              <name>ID0</name>
              <description>GPIOA0 input data</description>
              <bitRange>[0:0]</bitRange>
              <access>read-only</access>
            </field>
            <field>
              <name>ID1</name>
              <description>GPIOA1 input data</description>
              <bitRange>[1:1]</bitRange>
              <access>read-only</access>
            </field>
            <field>
              <name>ID2</name>
              <description>GPIOA2 input data</description>
              <bitRange>[2:2]</bitRange>
              <access>read-only</access>
            </field>
            <field>
              <name>ID3</name>
              <description>GPIOA3 input data</description>
              <bitRange>[3:3]</bitRange>
              <access>read-only</access>
            </field>
            <field>
              <name>ID4</name>
              <description>GPIOA4 input data</description>
              <bitRange>[4:4]</bitRange>
              <access>read-only</access>
            </field>
            <field>
              <name>ID5</name>
              <description>GPIOA5 input data</description>
              <bitRange>[5:5]</bitRange>
              <access>read-only</access>
            </field>
            <field>
              <name>ID6</name>
              <description>GPIOA6 input data</description>
              <bitRange>[6:6]</bitRange>
              <access>read-only</access>
            </field>
            <field>
              <name>ID7</name>
              <description>GPIOA7 input data</description>
              <bitRange>[7:7]</bitRange>
              <access>read-only</access>
            </field>
            <field>
              <name>ID8</name>
              <description>GPIOA8 input data</description>
              <bitRange>[8:8]</bitRange>
              <access>read-only</access>
            </field>
            <field>
              <name>ID9</name>
              <description>GPIOA9 input data</description>
              <bitRange>[9:9]</bitRange>
              <access>read-only</access>
            </field>
            <field>
              <name>ID10</name>
              <description>GPIOA10 input data</description>
              <bitRange>[10:10]</bitRange>
              <access>read-only</access>
            </field>
            <field>
              <name>ID11</name>
              <description>GPIOA11 input data</description>
              <bitRange>[11:11]</bitRange>
              <access>read-only</access>
            </field>
            <field>
              <name>ID12</name>
              <description>GPIOA12 input data</description>
              <bitRange>[12:12]</bitRange>
              <access>read-only</access>
            </field>
            <field>
              <name>ID13</name>
              <description>GPIOA13 input data</description>
              <bitRange>[13:13]</bitRange>
              <access>read-only</access>
            </field>
            <field>
              <name>ID14</name>
              <description>GPIOA14 input data</description>
              <bitRange>[14:14]</bitRange>
              <access>read-only</access>
            </field>
            <field>
              <name>ID15</name>
              <description>GPIOA15 input data</description>
              <bitRange>[15:15]</bitRange>
              <access>read-only</access>
            </field>
          </fields>
        </register>
        <register>
          <name>ODR</name>
          <description>GPIO port output data register</description>
          <addressOffset>0x14</addressOffset>
          <fields>
            <field>
              <name>OD0</name>
              <description>GPIOA0 output data</description>
              <bitRange>[0:0]</bitRange>
            </field>
            <field>
              <name>OD1</name>
              <description>GPIOA1 output data</description>
              <bitRange>[1:1]</bitRange>
            </field>
            <field>
              <name>OD2</name>
              <description>GPIOA2 output data</description>
              <bitRange>[2:2]</bitRange>
            </field>
            <field>
              <name>OD3</name>
              <description>GPIOA3 output data</description>
              <bitRange>[3:3]</bitRange>
            </field>
            <field>
              <name>OD4</name>
              <description>GPIOA4 output data</description>
              <bitRange>[4:4]</bitRange>
            </field>
            <field>
              <name>OD5</name>
              <description>GPIOA5 output data</description>
              <bitRange>[5:5]</bitRange>
            </field>
            <field>
              <name>OD6</name>
              <description>GPIOA6 output data</description>
              <bitRange>[6:6]</bitRange>
            </field>
            <field>
              <name>OD7</name>
              <description>GPIOA7 output data</description>
              <bitRange>[7:7]</bitRange>
            </field>
            <field>
              <name>OD8</name>
              <description>GPIOA8 output data</description>
              <bitRange>[8:8]</bitRange>
            </field>
            <field>
              <name>OD9</name>
              <description>GPIOA9 output data</description>
              <bitRange>[9:9]</bitRange>
            </field>
            <field>
              <name>OD10</name>
              <description>GPIOA10 output data</description>
              <bitRange>[10:10]</bitRange>
            </field>
            <field>
              <name>OD11</name>
              <description>GPIOA11 output data</description>
              <bitRange>[11:11]</bitRange>
            </field>
            <field>
              <name>OD12</name>
              <description>GPIOA12 output data</description>
              <bitRange>[12:12]</bitRange>
            </field>
            <field>
              <name>OD13</name>
              <description>GPIOA13 output data</description>
              <bitRange>[13:13]</bitRange>
            </field>
            <field>
              <name>OD14</name>
              <description>GPIOA14 output data</description>
              <bitRange>[14:14]</bitRange>
            </field>
            <field>
              <name>OD15</name>
              <description>GPIOA15 output data</description>
              <bitRange>[15:15]</bitRange>
            </field>
          </fields>
        </register>
        <register>
          <name>BSRR</name>
          <description>GPIO port bit set/reset register</description>
          <addressOffset>0x18</addressOffset>
          <fields>
            <field>
              <name>BS0</name>
              <description>GPIOA0 output set</description>
              <bitRange>[0:0]</bitRange>
              <access>write-only</access>
            </field>
            <field>
              <name>BS1</name>
              <description>GPIOA1 output set</description>
              <bitRange>[1:1]</bitRange>
              <access>write-only</access>
            </field>
            <field>
              <name>BS2</name>
              <description>GPIOA2 output set</description>
              <bitRange>[2:2]</bitRange>
              <access>write-only</access>
            </field>
            <field>
              <name>BS3</name>
              <description>GPIOA3 output set</description>
              <bitRange>[3:3]</bitRange>
              <access>write-only</access>
            </field>
            <field>
              <name>BS4</name>
              <description>GPIOA4 output set</description>
              <bitRange>[4:4]</bitRange>
              <access>write-only</access>
            </field>
            <field>
              <name>BS5</name>
              <description>GPIOA5 output set</description>
              <bitRange>[5:5]</bitRange>
              <access>write-only</access>
            </field>
            <field>
              <name>BS6</name>
              <description>GPIOA6 output set</description>
              <bitRange>[6:6]</bitRange>
              <access>write-only</access>
            </field>
            <field>
              <name>BS7</name>
              <description>GPIOA7 output set</description>
              <bitRange>[7:7]</bitRange>
              <access>write-only</access>
            </field>
            <field>
              <name>BS8</name>
              <description>GPIOA8 output set</description>
              <bitRange>[8:8]</bitRange>
              <access>write-only</access>
            </field>
            <field>
              <name>BS9</name>
              <description>GPIOA9 output set</description>
              <bitRange>[9:9]</bitRange>
              <access>write-only</access>
            </field>
            <field>
              <name>BS10</name>
              <description>GPIOA10 output set</description>
              <bitRange>[10:10]</bitRange>
              <access>write-only</access>
            </field>
            <field>
              <name>BS11</name>
              <description>GPIOA11 output set</description>
              <bitRange>[11:11]</bitRange>
              <access>write-only</access>
            </field>
            <field>
              <name>BS12</name>
              <description>GPIOA12 output set</description>
              <bitRange>[12:12]</bitRange>
              <access>write-only</access>
            </field>
            <field>
              <name>BS13</name>
              <description>GPIOA13 output set</description>
              <bitRange>[13:13]</bitRange>
              <access>write-only</access>
            </field>
            <field>
              <name>BS14</name>
              <description>GPIOA14 output set</description>
              <bitRange>[14:14]</bitRange>
              <access>write-only</access>
            </field>
            <field>
              <name>BS15</name>
              <description>GPIOA15 output set</description>
              <bitRange>[15:15]</bitRange>
              <access>write-only</access>
            </field>
            <field>
              <name>BR0</name>
              <description>GPIOA0 outut reset</description>
              <bitRange>[16:16]</bitRange>
              <access>write-only</access>
            </field>
            <field>
              <name>BR1</name>
              <description>GPIOA1 outut reset</description>
              <bitRange>[17:17]</bitRange>
              <access>write-only</access>
            </field>
            <field>
              <name>BR2</name>
              <description>GPIOA2 outut reset</description>
              <bitRange>[18:18]</bitRange>
              <access>write-only</access>
            </field>
            <field>
              <name>BR3</name>
              <description>GPIOA3 outut reset</description>
              <bitRange>[19:19]</bitRange>
              <access>write-only</access>
            </field>
            <field>
              <name>BR4</name>
              <description>GPIOA4 outut reset</description>
              <bitRange>[20:20]</bitRange>
              <access>write-only</access>
            </field>
            <field>
              <name>BR5</name>
              <description>GPIOA5 outut reset</description>
              <bitRange>[21:21]</bitRange>
              <access>write-only</access>
            </field>
            <field>
              <name>BR6</name>
              <description>GPIOA6 outut reset</description>
              <bitRange>[22:22]</bitRange>
              <access>write-only</access>
            </field>
            <field>
              <name>BR7</name>
              <description>GPIOA7 outut reset</description>
              <bitRange>[23:23]</bitRange>
              <access>write-only</access>
            </field>
            <field>
              <name>BR8</name>
              <description>GPIOA8 outut reset</description>
              <bitRange>[24:24]</bitRange>
              <access>write-only</access>
            </field>
            <field>
              <name>BR9</name>
              <description>GPIOA9 outut reset</description>
              <bitRange>[25:25]</bitRange>
              <access>write-only</access>
            </field>
            <field>
              <name>BR10</name>
              <description>GPIOA10 outut reset</description>
              <bitRange>[26:26]</bitRange>
              <access>write-only</access>
            </field>
            <field>
              <name>BR11</name>
              <description>GPIOA11 outut reset</description>
              <bitRange>[27:27]</bitRange>
              <access>write-only</access>
            </field>
            <field>
              <name>BR12</name>
              <description>GPIOA12 outut reset</description>
              <bitRange>[28:28]</bitRange>
              <access>write-only</access>
            </field>
            <field>
              <name>BR13</name>
              <description>GPIOA13 outut reset</description>
              <bitRange>[29:29]</bitRange>
              <access>write-only</access>
            </field>
            <field>
              <name>BR14</name>
              <description>GPIOA14 outut reset</description>
              <bitRange>[30:30]</bitRange>
              <access>write-only</access>
            </field>
            <field>
              <name>BR15</name>
              <description>GPIOA15 outut reset</description>
              <bitRange>[31:31]</bitRange>
              <access>write-only</access>
            </field>
          </fields>
        </register>
        <register>
          <name>LCKR</name>
          <description>GPIO port configuration lock register</description>
          <addressOffset>0x1C</addressOffset>
          <fields>
            <field>
              <name>LCK0</name>
              <description>GPIOA lock(bit0)</description>
              <bitRange>[0:0]</bitRange>
            </field>
            <field>
              <name>LCK1</name>
              <description>GPIOA lock(bit1)</description>
              <bitRange>[1:1]</bitRange>
            </field>
            <field>
              <name>LCK2</name>
              <description>GPIOA lock(bit2)</description>
              <bitRange>[2:2]</bitRange>
            </field>
            <field>
              <name>LCK3</name>
              <description>GPIOA lock(bit3)</description>
              <bitRange>[3:3]</bitRange>
            </field>
            <field>
              <name>LCK4</name>
              <description>GPIOA lock(bit4)</description>
              <bitRange>[4:4]</bitRange>
            </field>
            <field>
              <name>LCK5</name>
              <description>GPIOA lock(bit5)</description>
              <bitRange>[5:5]</bitRange>
            </field>
            <field>
              <name>LCK6</name>
              <description>GPIOA lock(bit6)</description>
              <bitRange>[6:6]</bitRange>
            </field>
            <field>
              <name>LCK7</name>
              <description>GPIOA lock(bit7)</description>
              <bitRange>[7:7]</bitRange>
            </field>
            <field>
              <name>LCK8</name>
              <description>GPIOA lock(bit8)</description>
              <bitRange>[8:8]</bitRange>
            </field>
            <field>
              <name>LCK9</name>
              <description>GPIOA lock(bit9)</description>
              <bitRange>[9:9]</bitRange>
            </field>
            <field>
              <name>LCK10</name>
              <description>GPIOA lock(bit10)</description>
              <bitRange>[10:10]</bitRange>
            </field>
            <field>
              <name>LCK11</name>
              <description>GPIOA lock(bit11)</description>
              <bitRange>[11:11]</bitRange>
            </field>
            <field>
              <name>LCK12</name>
              <description>GPIOA lock(bit12)</description>
              <bitRange>[12:12]</bitRange>
            </field>
            <field>
              <name>LCK13</name>
              <description>GPIOA lock(bit13)</description>
              <bitRange>[13:13]</bitRange>
            </field>
            <field>
              <name>LCK14</name>
              <description>GPIOA lock(bit14)</description>
              <bitRange>[14:14]</bitRange>
            </field>
            <field>
              <name>LCK15</name>
              <description>GPIOA lock(bit15)</description>
              <bitRange>[15:15]</bitRange>
            </field>
            <field>
              <name>LCKK</name>
              <description>GPIOA lock key</description>
              <bitRange>[16:16]</bitRange>
            </field>
          </fields>
        </register>
        <register>
          <name>AFRL</name>
          <description>GPIO alternate function low register</description>
          <addressOffset>0x20</addressOffset>
          <fields>
            <field>
              <name>AFSEL0</name>
              <description>GPIOA0 AF select</description>
              <bitRange>[3:0]</bitRange>
              <enumeratedValues>
                <enumeratedValue>
                  <name>0</name>
                  <value>1</value>
                </enumeratedValue>
                <enumeratedValue>
                  <name>1</name>
                  <value>2</value>
                </enumeratedValue>
                <enumeratedValue>
                  <name>2</name>
                  <value>4</value>
                </enumeratedValue>
                <enumeratedValue>
                  <name>3</name>
                  <value>8</value>
                </enumeratedValue>
              </enumeratedValues>
            </field>
            <field>
              <name>AFSEL1</name>
              <description>GPIOA1 AF select</description>
              <bitRange>[7:4]</bitRange>
              <enumeratedValues>
                <enumeratedValue>
                  <name>0</name>
                  <value>1</value>
                </enumeratedValue>
                <enumeratedValue>
                  <name>1</name>
                  <value>2</value>
                </enumeratedValue>
                <enumeratedValue>
                  <name>2</name>
                  <value>4</value>
                </enumeratedValue>
                <enumeratedValue>
                  <name>3</name>
                  <value>8</value>
                </enumeratedValue>
              </enumeratedValues>
            </field>
            <field>
              <name>AFSEL2</name>
              <description>GPIOA2 AF select</description>
              <bitRange>[11:8]</bitRange>
              <enumeratedValues>
                <enumeratedValue>
                  <name>0</name>
                  <value>1</value>
                </enumeratedValue>
                <enumeratedValue>
                  <name>1</name>
                  <value>2</value>
                </enumeratedValue>
                <enumeratedValue>
                  <name>2</name>
                  <value>4</value>
                </enumeratedValue>
                <enumeratedValue>
                  <name>3</name>
                  <value>8</value>
                </enumeratedValue>
              </enumeratedValues>
            </field>
            <field>
              <name>AFSEL3</name>
              <description>GPIOA3 AF select</description>
              <bitRange>[15:12]</bitRange>
              <enumeratedValues>
                <enumeratedValue>
                  <name>0</name>
                  <value>1</value>
                </enumeratedValue>
                <enumeratedValue>
                  <name>1</name>
                  <value>2</value>
                </enumeratedValue>
                <enumeratedValue>
                  <name>2</name>
                  <value>4</value>
                </enumeratedValue>
                <enumeratedValue>
                  <name>3</name>
                  <value>8</value>
                </enumeratedValue>
              </enumeratedValues>
            </field>
            <field>
              <name>AFSEL4</name>
              <description>GPIOA4 AF select</description>
              <bitRange>[19:16]</bitRange>
              <enumeratedValues>
                <enumeratedValue>
                  <name>0</name>
                  <value>1</value>
                </enumeratedValue>
                <enumeratedValue>
                  <name>1</name>
                  <value>2</value>
                </enumeratedValue>
                <enumeratedValue>
                  <name>2</name>
                  <value>4</value>
                </enumeratedValue>
                <enumeratedValue>
                  <name>3</name>
                  <value>8</value>
                </enumeratedValue>
              </enumeratedValues>
            </field>
            <field>
              <name>AFSEL5</name>
              <description>GPIOA5 AF select</description>
              <bitRange>[23:20]</bitRange>
              <enumeratedValues>
                <enumeratedValue>
                  <name>0</name>
                  <value>1</value>
                </enumeratedValue>
                <enumeratedValue>
                  <name>1</name>
                  <value>2</value>
                </enumeratedValue>
                <enumeratedValue>
                  <name>2</name>
                  <value>4</value>
                </enumeratedValue>
                <enumeratedValue>
                  <name>3</name>
                  <value>8</value>
                </enumeratedValue>
              </enumeratedValues>
            </field>
            <field>
              <name>AFSEL6</name>
              <description>GPIOA6 AF select</description>
              <bitRange>[27:24]</bitRange>
              <enumeratedValues>
                <enumeratedValue>
                  <name>0</name>
                  <value>1</value>
                </enumeratedValue>
                <enumeratedValue>
                  <name>1</name>
                  <value>2</value>
                </enumeratedValue>
                <enumeratedValue>
                  <name>2</name>
                  <value>4</value>
                </enumeratedValue>
                <enumeratedValue>
                  <name>3</name>
                  <value>8</value>
                </enumeratedValue>
              </enumeratedValues>
            </field>
            <field>
              <name>AFSEL7</name>
              <description>GPIOA7 AF select</description>
              <bitRange>[31:28]</bitRange>
              <enumeratedValues>
                <enumeratedValue>
                  <name>0</name>
                  <value>1</value>
                </enumeratedValue>
                <enumeratedValue>
                  <name>1</name>
                  <value>2</value>
                </enumeratedValue>
                <enumeratedValue>
                  <name>2</name>
                  <value>4</value>
                </enumeratedValue>
                <enumeratedValue>
                  <name>3</name>
                  <value>8</value>
                </enumeratedValue>
              </enumeratedValues>
            </field>
          </fields>
        </register>
        <register>
          <name>AFRH</name>
          <description>GPIO alternate function high register</description>
          <addressOffset>0x24</addressOffset>
          <fields>
            <field>
              <name>AFSEL8</name>
              <description>GPIOA8 AF select</description>
              <bitRange>[3:0]</bitRange>
              <enumeratedValues>
                <enumeratedValue>
                  <name>0</name>
                  <value>1</value>
                </enumeratedValue>
                <enumeratedValue>
                  <name>1</name>
                  <value>2</value>
                </enumeratedValue>
                <enumeratedValue>
                  <name>2</name>
                  <value>4</value>
                </enumeratedValue>
                <enumeratedValue>
                  <name>3</name>
                  <value>8</value>
                </enumeratedValue>
              </enumeratedValues>
            </field>
            <field>
              <name>AFSEL9</name>
              <description>GPIOA9 AF select</description>
              <bitRange>[7:4]</bitRange>
              <enumeratedValues>
                <enumeratedValue>
                  <name>0</name>
                  <value>1</value>
                </enumeratedValue>
                <enumeratedValue>
                  <name>1</name>
                  <value>2</value>
                </enumeratedValue>
                <enumeratedValue>
                  <name>2</name>
                  <value>4</value>
                </enumeratedValue>
                <enumeratedValue>
                  <name>3</name>
                  <value>8</value>
                </enumeratedValue>
              </enumeratedValues>
            </field>
            <field>
              <name>AFSEL10</name>
              <description>GPIOA10 AF select</description>
              <bitRange>[11:8]</bitRange>
              <enumeratedValues>
                <enumeratedValue>
                  <name>0</name>
                  <value>1</value>
                </enumeratedValue>
                <enumeratedValue>
                  <name>1</name>
                  <value>2</value>
                </enumeratedValue>
                <enumeratedValue>
                  <name>2</name>
                  <value>4</value>
                </enumeratedValue>
                <enumeratedValue>
                  <name>3</name>
                  <value>8</value>
                </enumeratedValue>
              </enumeratedValues>
            </field>
            <field>
              <name>AFSEL11</name>
              <description>GPIOA11 AF select</description>
              <bitRange>[15:12]</bitRange>
              <enumeratedValues>
                <enumeratedValue>
                  <name>0</name>
                  <value>1</value>
                </enumeratedValue>
                <enumeratedValue>
                  <name>1</name>
                  <value>2</value>
                </enumeratedValue>
                <enumeratedValue>
                  <name>2</name>
                  <value>4</value>
                </enumeratedValue>
                <enumeratedValue>
                  <name>3</name>
                  <value>8</value>
                </enumeratedValue>
              </enumeratedValues>
            </field>
            <field>
              <name>AFSEL12</name>
              <description>GPIOA12 AF select</description>
              <bitRange>[19:16]</bitRange>
              <enumeratedValues>
                <enumeratedValue>
                  <name>0</name>
                  <value>1</value>
                </enumeratedValue>
                <enumeratedValue>
                  <name>1</name>
                  <value>2</value>
                </enumeratedValue>
                <enumeratedValue>
                  <name>2</name>
                  <value>4</value>
                </enumeratedValue>
                <enumeratedValue>
                  <name>3</name>
                  <value>8</value>
                </enumeratedValue>
              </enumeratedValues>
            </field>
            <field>
              <name>AFSEL13</name>
              <description>GPIOA13 AF select</description>
              <bitRange>[23:20]</bitRange>
              <enumeratedValues>
                <enumeratedValue>
                  <name>0</name>
                  <value>1</value>
                </enumeratedValue>
                <enumeratedValue>
                  <name>1</name>
                  <value>2</value>
                </enumeratedValue>
                <enumeratedValue>
                  <name>2</name>
                  <value>4</value>
                </enumeratedValue>
                <enumeratedValue>
                  <name>3</name>
                  <value>8</value>
                </enumeratedValue>
              </enumeratedValues>
            </field>
            <field>
              <name>AFSEL14</name>
              <description>GPIOA14 AF select</description>
              <bitRange>[27:24]</bitRange>
              <enumeratedValues>
                <enumeratedValue>
                  <name>0</name>
                  <value>1</value>
                </enumeratedValue>
                <enumeratedValue>
                  <name>1</name>
                  <value>2</value>
                </enumeratedValue>
                <enumeratedValue>
                  <name>2</name>
                  <value>4</value>
                </enumeratedValue>
                <enumeratedValue>
                  <name>3</name>
                  <value>8</value>
                </enumeratedValue>
              </enumeratedValues>
            </field>
            <field>
              <name>AFSEL15</name>
              <description>GPIOA15 AF select</description>
              <bitRange>[31:28]</bitRange>
              <enumeratedValues>
                <enumeratedValue>
                  <name>0</name>
                  <value>1</value>
                </enumeratedValue>
                <enumeratedValue>
                  <name>1</name>
                  <value>2</value>
                </enumeratedValue>
                <enumeratedValue>
                  <name>2</name>
                  <value>4</value>
                </enumeratedValue>
                <enumeratedValue>
                  <name>3</name>
                  <value>8</value>
                </enumeratedValue>
              </enumeratedValues>
            </field>
          </fields>
        </register>
        <register>
          <name>BRR</name>
          <description>port bit reset register</description>
          <addressOffset>0x28</addressOffset>
          <fields>
            <field>
              <name>BR0</name>
              <description>GPIOA 0 output pin reset</description>
              <bitRange>[0:0]</bitRange>
              <access>write-only</access>
            </field>
            <field>
              <name>BR1</name>
              <description>GPIOA 1 output pin reset</description>
              <bitRange>[1:1]</bitRange>
              <access>write-only</access>
            </field>
            <field>
              <name>BR2</name>
              <description>GPIOA 2 output pin reset</description>
              <bitRange>[2:2]</bitRange>
              <access>write-only</access>
            </field>
            <field>
              <name>BR3</name>
              <description>GPIOA 3 output pin reset</description>
              <bitRange>[3:3]</bitRange>
              <access>write-only</access>
            </field>
            <field>
              <name>BR4</name>
              <description>GPIOA 4 output pin reset</description>
              <bitRange>[4:4]</bitRange>
              <access>write-only</access>
            </field>
            <field>
              <name>BR5</name>
              <description>GPIOA 5 output pin reset</description>
              <bitRange>[5:5]</bitRange>
              <access>write-only</access>
            </field>
            <field>
              <name>BR6</name>
              <description>GPIOA 6 output pin reset</description>
              <bitRange>[6:6]</bitRange>
              <access>write-only</access>
            </field>
            <field>
              <name>BR7</name>
              <description>GPIOA 7 output pin reset</description>
              <bitRange>[7:7]</bitRange>
              <access>write-only</access>
            </field>
            <field>
              <name>BR8</name>
              <description>GPIOA 8 output pin reset</description>
              <bitRange>[8:8]</bitRange>
              <access>write-only</access>
            </field>
            <field>
              <name>BR9</name>
              <description>GPIOA 9 output pin reset</description>
              <bitRange>[9:9]</bitRange>
              <access>write-only</access>
            </field>
            <field>
              <name>BR10</name>
              <description>GPIOA 10 output pin reset</description>
              <bitRange>[10:10]</bitRange>
              <access>write-only</access>
            </field>
            <field>
              <name>BR11</name>
              <description>GPIOA 11 output pin reset</description>
              <bitRange>[11:11]</bitRange>
              <access>write-only</access>
            </field>
            <field>
              <name>BR12</name>
              <description>GPIOA 12 output pin reset</description>
              <bitRange>[12:12]</bitRange>
              <access>write-only</access>
            </field>
            <field>
              <name>BR13</name>
              <description>GPIOA 13 output pin reset</description>
              <bitRange>[13:13]</bitRange>
              <access>write-only</access>
            </field>
            <field>
              <name>BR14</name>
              <description>GPIOA 14 output pin reset</description>
              <bitRange>[14:14]</bitRange>
              <access>write-only</access>
            </field>
            <field>
              <name>BR15</name>
              <description>GPIOA 15 output pin reset</description>
              <bitRange>[15:15]</bitRange>
              <access>write-only</access>
            </field>
          </fields>
        </register>
      </registers>
    </peripheral>
    <peripheral>
      <name>GPIOB</name>
      <groupName>GPIO</groupName>
      <description>General-purpose I/Os</description>
      <baseAddress>0x50000400</baseAddress>
      <addressBlock>
        <offset>0x0</offset>
        <size>0x30</size>
        <usage>registers</usage>
      </addressBlock>
      <registers>
        <register>
          <name>MODER</name>
          <addressOffset>0x0</addressOffset>
          <fields>
            <field>
              <name>MODER0</name>
              <description>GPIOB0 MODE</description>
              <bitRange>[1:0]</bitRange>
            </field>
            <field>
              <name>MODER1</name>
              <description>GPIOB1 MODE</description>
              <bitRange>[3:2]</bitRange>
            </field>
            <field>
              <name>MODER2</name>
              <description>GPIOB2 MODE</description>
              <bitRange>[5:4]</bitRange>
            </field>
            <field>
              <name>MODER3</name>
              <description>GPIOB3 MODE</description>
              <bitRange>[7:6]</bitRange>
            </field>
            <field>
              <name>MODER4</name>
              <description>GPIOB4 MODE</description>
              <bitRange>[9:8]</bitRange>
            </field>
            <field>
              <name>MODER5</name>
              <description>GPIOB5 MODE</description>
              <bitRange>[11:10]</bitRange>
            </field>
            <field>
              <name>MODER6</name>
              <description>GPIOB6 MODE</description>
              <bitRange>[13:12]</bitRange>
            </field>
            <field>
              <name>MODER7</name>
              <description>GPIOB7 MODE</description>
              <bitRange>[15:14]</bitRange>
            </field>
            <field>
              <name>MODER8</name>
              <description>GPIOB8 MODE</description>
              <bitRange>[17:16]</bitRange>
            </field>
            <field>
              <name>MODER9</name>
              <description>GPIOB9 MODE</description>
              <bitRange>[19:18]</bitRange>
            </field>
            <field>
              <name>MODER10</name>
              <description>GPIOB10 MODE</description>
              <bitRange>[21:20]</bitRange>
            </field>
            <field>
              <name>MODER11</name>
              <description>GPIOB11 MODE</description>
              <bitRange>[23:22]</bitRange>
            </field>
            <field>
              <name>MODER12</name>
              <description>GPIOB12 MODE</description>
              <bitRange>[25:24]</bitRange>
            </field>
            <field>
              <name>MODER13</name>
              <description>GPIOB13 MODE</description>
              <bitRange>[27:26]</bitRange>
            </field>
            <field>
              <name>MODER14</name>
              <description>GPIOB14 MODE</description>
              <bitRange>[29:28]</bitRange>
            </field>
            <field>
              <name>MODER15</name>
              <description>GPIOB15 MODE</description>
              <bitRange>[31:30]</bitRange>
            </field>
          </fields>
        </register>
        <register>
          <name>OTYPER</name>
          <addressOffset>0x4</addressOffset>
          <fields>
            <field>
              <name>OT0</name>
              <description>GPIOB0 Output type</description>
              <bitRange>[0:0]</bitRange>
            </field>
            <field>
              <name>OT1</name>
              <description>GPIOB1 Output type</description>
              <bitRange>[1:1]</bitRange>
            </field>
            <field>
              <name>OT2</name>
              <description>GPIOB2 Output type</description>
              <bitRange>[2:2]</bitRange>
            </field>
            <field>
              <name>OT3</name>
              <description>GPIOB3 Output type</description>
              <bitRange>[3:3]</bitRange>
            </field>
            <field>
              <name>OT4</name>
              <description>GPIOB4 Output type</description>
              <bitRange>[4:4]</bitRange>
            </field>
            <field>
              <name>OT5</name>
              <description>GPIOB5 Output type</description>
              <bitRange>[5:5]</bitRange>
            </field>
            <field>
              <name>OT6</name>
              <description>GPIOB6 Output type</description>
              <bitRange>[6:6]</bitRange>
            </field>
            <field>
              <name>OT7</name>
              <description>GPIOB7 Output type</description>
              <bitRange>[7:7]</bitRange>
            </field>
            <field>
              <name>OT8</name>
              <description>GPIOB8 Output type</description>
              <bitRange>[8:8]</bitRange>
            </field>
            <field>
              <name>OT9</name>
              <description>GPIOB9 Output type</description>
              <bitRange>[9:9]</bitRange>
            </field>
            <field>
              <name>OT10</name>
              <description>GPIOB10 Output type</description>
              <bitRange>[10:10]</bitRange>
            </field>
            <field>
              <name>OT11</name>
              <description>GPIOB11 Output type</description>
              <bitRange>[11:11]</bitRange>
            </field>
            <field>
              <name>OT12</name>
              <description>GPIOB12 Output type</description>
              <bitRange>[12:12]</bitRange>
            </field>
            <field>
              <name>OT13</name>
              <description>GPIOB13 Output type</description>
              <bitRange>[13:13]</bitRange>
            </field>
            <field>
              <name>OT14</name>
              <description>GPIOB14 Output type</description>
              <bitRange>[14:14]</bitRange>
            </field>
            <field>
              <name>OT15</name>
              <description>GPIOB15 Output type</description>
              <bitRange>[15:15]</bitRange>
            </field>
          </fields>
        </register>
        <register>
          <name>OSPDDER</name>
          <addressOffset>0x8</addressOffset>
          <fields>
            <field>
              <name>OSPEED0</name>
              <description>GPIOB0 output speed</description>
              <bitRange>[1:0]</bitRange>
            </field>
            <field>
              <name>OSPEED1</name>
              <description>GPIOB1 output speed</description>
              <bitRange>[3:2]</bitRange>
            </field>
            <field>
              <name>OSPEED2</name>
              <description>GPIOB2 output speed</description>
              <bitRange>[5:4]</bitRange>
            </field>
            <field>
              <name>OSPEED3</name>
              <description>GPIOB3 output speed</description>
              <bitRange>[7:6]</bitRange>
            </field>
            <field>
              <name>OSPEED4</name>
              <description>GPIOB4 output speed</description>
              <bitRange>[9:8]</bitRange>
            </field>
            <field>
              <name>OSPEED5</name>
              <description>GPIOB5 output speed</description>
              <bitRange>[11:10]</bitRange>
            </field>
            <field>
              <name>OSPEED6</name>
              <description>GPIOB6 output speed</description>
              <bitRange>[13:12]</bitRange>
            </field>
            <field>
              <name>OSPEED7</name>
              <description>GPIOB7 output speed</description>
              <bitRange>[15:14]</bitRange>
            </field>
            <field>
              <name>OSPEED8</name>
              <description>GPIOB8 output speed</description>
              <bitRange>[17:16]</bitRange>
            </field>
            <field>
              <name>OSPEED9</name>
              <description>GPIOB9 output speed</description>
              <bitRange>[19:18]</bitRange>
            </field>
            <field>
              <name>OSPEED10</name>
              <description>GPIOB10 output speed</description>
              <bitRange>[21:20]</bitRange>
            </field>
            <field>
              <name>OSPEED11</name>
              <description>GPIOB11 output speed</description>
              <bitRange>[23:22]</bitRange>
            </field>
            <field>
              <name>OSPEED12</name>
              <description>GPIOB12 output speed</description>
              <bitRange>[25:24]</bitRange>
            </field>
            <field>
              <name>OSPEED13</name>
              <description>GPIOB13 output speed</description>
              <bitRange>[27:26]</bitRange>
            </field>
            <field>
              <name>OSPEED14</name>
              <description>GPIOB14 output speed</description>
              <bitRange>[29:28]</bitRange>
            </field>
            <field>
              <name>OSPEED15</name>
              <description>GPIOB15 output speed</description>
              <bitRange>[31:30]</bitRange>
            </field>
          </fields>
        </register>
        <register>
          <name>PUPDR</name>
          <addressOffset>0xC</addressOffset>
          <fields>
            <field>
              <name>PUPD0</name>
              <description>GPIOB0 pull up/pull down</description>
              <bitRange>[1:0]</bitRange>
              <enumeratedValues>
                <enumeratedValue>
                  <name>0</name>
                  <value>1</value>
                </enumeratedValue>
                <enumeratedValue>
                  <name>1</name>
                  <value>2</value>
                </enumeratedValue>
              </enumeratedValues>
            </field>
            <field>
              <name>PUPD1</name>
              <description>GPIOB1 pull up/pull down</description>
              <bitRange>[3:2]</bitRange>
              <enumeratedValues>
                <enumeratedValue>
                  <name>0</name>
                  <value>1</value>
                </enumeratedValue>
                <enumeratedValue>
                  <name>1</name>
                  <value>2</value>
                </enumeratedValue>
              </enumeratedValues>
            </field>
            <field>
              <name>PUPD2</name>
              <description>GPIOB2 pull up/pull down</description>
              <bitRange>[5:4]</bitRange>
              <enumeratedValues>
                <enumeratedValue>
                  <name>0</name>
                  <value>1</value>
                </enumeratedValue>
                <enumeratedValue>
                  <name>1</name>
                  <value>2</value>
                </enumeratedValue>
              </enumeratedValues>
            </field>
            <field>
              <name>PUPD3</name>
              <description>GPIOB3 pull up/pull down</description>
              <bitRange>[7:6]</bitRange>
              <enumeratedValues>
                <enumeratedValue>
                  <name>0</name>
                  <value>1</value>
                </enumeratedValue>
                <enumeratedValue>
                  <name>1</name>
                  <value>2</value>
                </enumeratedValue>
              </enumeratedValues>
            </field>
            <field>
              <name>PUPD4</name>
              <description>GPIOB4 pull up/pull down</description>
              <bitRange>[9:8]</bitRange>
              <enumeratedValues>
                <enumeratedValue>
                  <name>0</name>
                  <value>1</value>
                </enumeratedValue>
                <enumeratedValue>
                  <name>1</name>
                  <value>2</value>
                </enumeratedValue>
              </enumeratedValues>
            </field>
            <field>
              <name>PUPD5</name>
              <description>GPIOB5 pull up/pull down</description>
              <bitRange>[11:10]</bitRange>
              <enumeratedValues>
                <enumeratedValue>
                  <name>0</name>
                  <value>1</value>
                </enumeratedValue>
                <enumeratedValue>
                  <name>1</name>
                  <value>2</value>
                </enumeratedValue>
              </enumeratedValues>
            </field>
            <field>
              <name>PUPD6</name>
              <description>GPIOB6 pull up/pull down</description>
              <bitRange>[13:12]</bitRange>
              <enumeratedValues>
                <enumeratedValue>
                  <name>0</name>
                  <value>1</value>
                </enumeratedValue>
                <enumeratedValue>
                  <name>1</name>
                  <value>2</value>
                </enumeratedValue>
              </enumeratedValues>
            </field>
            <field>
              <name>PUPD7</name>
              <description>GPIOB7 pull up/pull down</description>
              <bitRange>[15:14]</bitRange>
              <enumeratedValues>
                <enumeratedValue>
                  <name>0</name>
                  <value>1</value>
                </enumeratedValue>
                <enumeratedValue>
                  <name>1</name>
                  <value>2</value>
                </enumeratedValue>
              </enumeratedValues>
            </field>
            <field>
              <name>PUPD8</name>
              <description>GPIOB8 pull up/pull down</description>
              <bitRange>[17:16]</bitRange>
              <enumeratedValues>
                <enumeratedValue>
                  <name>0</name>
                  <value>1</value>
                </enumeratedValue>
                <enumeratedValue>
                  <name>1</name>
                  <value>2</value>
                </enumeratedValue>
              </enumeratedValues>
            </field>
            <field>
              <name>PUPD9</name>
              <description>GPIOB9 pull up/pull down</description>
              <bitRange>[19:18]</bitRange>
              <enumeratedValues>
                <enumeratedValue>
                  <name>0</name>
                  <value>1</value>
                </enumeratedValue>
                <enumeratedValue>
                  <name>1</name>
                  <value>2</value>
                </enumeratedValue>
              </enumeratedValues>
            </field>
            <field>
              <name>PUPD10</name>
              <description>GPIOB10 pull up/pull down</description>
              <bitRange>[21:20]</bitRange>
              <enumeratedValues>
                <enumeratedValue>
                  <name>0</name>
                  <value>1</value>
                </enumeratedValue>
                <enumeratedValue>
                  <name>1</name>
                  <value>2</value>
                </enumeratedValue>
              </enumeratedValues>
            </field>
            <field>
              <name>PUPD11</name>
              <description>GPIOB11 pull up/pull down</description>
              <bitRange>[23:22]</bitRange>
              <enumeratedValues>
                <enumeratedValue>
                  <name>0</name>
                  <value>1</value>
                </enumeratedValue>
                <enumeratedValue>
                  <name>1</name>
                  <value>2</value>
                </enumeratedValue>
              </enumeratedValues>
            </field>
            <field>
              <name>PUPD12</name>
              <description>GPIOB12 pull up/pull down</description>
              <bitRange>[25:24]</bitRange>
              <enumeratedValues>
                <enumeratedValue>
                  <name>0</name>
                  <value>1</value>
                </enumeratedValue>
                <enumeratedValue>
                  <name>1</name>
                  <value>2</value>
                </enumeratedValue>
              </enumeratedValues>
            </field>
            <field>
              <name>PUPD13</name>
              <description>GPIOB13 pull up/pull down</description>
              <bitRange>[27:26]</bitRange>
              <enumeratedValues>
                <enumeratedValue>
                  <name>0</name>
                  <value>1</value>
                </enumeratedValue>
                <enumeratedValue>
                  <name>1</name>
                  <value>2</value>
                </enumeratedValue>
              </enumeratedValues>
            </field>
            <field>
              <name>PUPD14</name>
              <description>GPIOB14 pull up/pull down</description>
              <bitRange>[29:28]</bitRange>
              <enumeratedValues>
                <enumeratedValue>
                  <name>0</name>
                  <value>1</value>
                </enumeratedValue>
                <enumeratedValue>
                  <name>1</name>
                  <value>2</value>
                </enumeratedValue>
              </enumeratedValues>
            </field>
            <field>
              <name>PUPD15</name>
              <description>GPIOB15 pull up/pull down</description>
              <bitRange>[31:30]</bitRange>
              <enumeratedValues>
                <enumeratedValue>
                  <name>0</name>
                  <value>1</value>
                </enumeratedValue>
                <enumeratedValue>
                  <name>1</name>
                  <value>2</value>
                </enumeratedValue>
              </enumeratedValues>
            </field>
          </fields>
        </register>
        <register>
          <name>IDR</name>
          <addressOffset>0x10</addressOffset>
          <fields>
            <field>
              <name>ID0</name>
              <description>GPIOB0 input data</description>
              <bitRange>[0:0]</bitRange>
              <access>read-only</access>
            </field>
            <field>
              <name>ID1</name>
              <description>GPIOB1 input data</description>
              <bitRange>[1:1]</bitRange>
              <access>read-only</access>
            </field>
            <field>
              <name>ID2</name>
              <description>GPIOB2 input data</description>
              <bitRange>[2:2]</bitRange>
              <access>read-only</access>
            </field>
            <field>
              <name>ID3</name>
              <description>GPIOB3 input data</description>
              <bitRange>[3:3]</bitRange>
              <access>read-only</access>
            </field>
            <field>
              <name>ID4</name>
              <description>GPIOB4 input data</description>
              <bitRange>[4:4]</bitRange>
              <access>read-only</access>
            </field>
            <field>
              <name>ID5</name>
              <description>GPIOB5 input data</description>
              <bitRange>[5:5]</bitRange>
              <access>read-only</access>
            </field>
            <field>
              <name>ID6</name>
              <description>GPIOB6 input data</description>
              <bitRange>[6:6]</bitRange>
              <access>read-only</access>
            </field>
            <field>
              <name>ID7</name>
              <description>GPIOB7 input data</description>
              <bitRange>[7:7]</bitRange>
              <access>read-only</access>
            </field>
            <field>
              <name>ID8</name>
              <description>GPIOB8 input data</description>
              <bitRange>[8:8]</bitRange>
              <access>read-only</access>
            </field>
            <field>
              <name>ID9</name>
              <description>GPIOB9 input data</description>
              <bitRange>[9:9]</bitRange>
              <access>read-only</access>
            </field>
            <field>
              <name>ID10</name>
              <description>GPIOB10 input data</description>
              <bitRange>[10:10]</bitRange>
              <access>read-only</access>
            </field>
            <field>
              <name>ID11</name>
              <description>GPIOB11 input data</description>
              <bitRange>[11:11]</bitRange>
              <access>read-only</access>
            </field>
            <field>
              <name>ID12</name>
              <description>GPIOB12 input data</description>
              <bitRange>[12:12]</bitRange>
              <access>read-only</access>
            </field>
            <field>
              <name>ID13</name>
              <description>GPIOB13 input data</description>
              <bitRange>[13:13]</bitRange>
              <access>read-only</access>
            </field>
            <field>
              <name>ID14</name>
              <description>GPIOB14 input data</description>
              <bitRange>[14:14]</bitRange>
              <access>read-only</access>
            </field>
            <field>
              <name>ID15</name>
              <description>GPIOB15 input data</description>
              <bitRange>[15:15]</bitRange>
              <access>read-only</access>
            </field>
          </fields>
        </register>
        <register>
          <name>ODR</name>
          <addressOffset>0x14</addressOffset>
          <fields>
            <field>
              <name>OD0</name>
              <description>GPIOB0 output data</description>
              <bitRange>[0:0]</bitRange>
            </field>
            <field>
              <name>OD1</name>
              <description>GPIOB1 output data</description>
              <bitRange>[1:1]</bitRange>
            </field>
            <field>
              <name>OD2</name>
              <description>GPIOB2 output data</description>
              <bitRange>[2:2]</bitRange>
            </field>
            <field>
              <name>OD3</name>
              <description>GPIOB3 output data</description>
              <bitRange>[3:3]</bitRange>
            </field>
            <field>
              <name>OD4</name>
              <description>GPIOB4 output data</description>
              <bitRange>[4:4]</bitRange>
            </field>
            <field>
              <name>OD5</name>
              <description>GPIOB5 output data</description>
              <bitRange>[5:5]</bitRange>
            </field>
            <field>
              <name>OD6</name>
              <description>GPIOB6 output data</description>
              <bitRange>[6:6]</bitRange>
            </field>
            <field>
              <name>OD7</name>
              <description>GPIOB7 output data</description>
              <bitRange>[7:7]</bitRange>
            </field>
            <field>
              <name>OD8</name>
              <description>GPIOB8 output data</description>
              <bitRange>[8:8]</bitRange>
            </field>
            <field>
              <name>OD9</name>
              <description>GPIOB9 output data</description>
              <bitRange>[9:9]</bitRange>
            </field>
            <field>
              <name>OD10</name>
              <description>GPIOB10 output data</description>
              <bitRange>[10:10]</bitRange>
            </field>
            <field>
              <name>OD11</name>
              <description>GPIOB11 output data</description>
              <bitRange>[11:11]</bitRange>
            </field>
            <field>
              <name>OD12</name>
              <description>GPIOB12 output data</description>
              <bitRange>[12:12]</bitRange>
            </field>
            <field>
              <name>OD13</name>
              <description>GPIOB13 output data</description>
              <bitRange>[13:13]</bitRange>
            </field>
            <field>
              <name>OD14</name>
              <description>GPIOB14 output data</description>
              <bitRange>[14:14]</bitRange>
            </field>
            <field>
              <name>OD15</name>
              <description>GPIOB15 output data</description>
              <bitRange>[15:15]</bitRange>
            </field>
          </fields>
        </register>
        <register>
          <name>BSRR</name>
          <addressOffset>0x18</addressOffset>
          <fields>
            <field>
              <name>BS0</name>
              <description>GPIOB0 output set</description>
              <bitRange>[0:0]</bitRange>
              <access>write-only</access>
            </field>
            <field>
              <name>BS1</name>
              <description>GPIOB1 output set</description>
              <bitRange>[1:1]</bitRange>
              <access>write-only</access>
            </field>
            <field>
              <name>BS2</name>
              <description>GPIOB2 output set</description>
              <bitRange>[2:2]</bitRange>
              <access>write-only</access>
            </field>
            <field>
              <name>BS3</name>
              <description>GPIOB3 output set</description>
              <bitRange>[3:3]</bitRange>
              <access>write-only</access>
            </field>
            <field>
              <name>BS4</name>
              <description>GPIOB4 output set</description>
              <bitRange>[4:4]</bitRange>
              <access>write-only</access>
            </field>
            <field>
              <name>BS5</name>
              <description>GPIOB5 output set</description>
              <bitRange>[5:5]</bitRange>
              <access>write-only</access>
            </field>
            <field>
              <name>BS6</name>
              <description>GPIOB6 output set</description>
              <bitRange>[6:6]</bitRange>
              <access>write-only</access>
            </field>
            <field>
              <name>BS7</name>
              <description>GPIOB7 output set</description>
              <bitRange>[7:7]</bitRange>
              <access>write-only</access>
            </field>
            <field>
              <name>BS8</name>
              <description>GPIOB8 output set</description>
              <bitRange>[8:8]</bitRange>
              <access>write-only</access>
            </field>
            <field>
              <name>BS9</name>
              <description>GPIOB9 output set</description>
              <bitRange>[9:9]</bitRange>
              <access>write-only</access>
            </field>
            <field>
              <name>BS10</name>
              <description>GPIOB10 output set</description>
              <bitRange>[10:10]</bitRange>
              <access>write-only</access>
            </field>
            <field>
              <name>BS11</name>
              <description>GPIOB11 output set</description>
              <bitRange>[11:11]</bitRange>
              <access>write-only</access>
            </field>
            <field>
              <name>BS12</name>
              <description>GPIOB12 output set</description>
              <bitRange>[12:12]</bitRange>
              <access>write-only</access>
            </field>
            <field>
              <name>BS13</name>
              <description>GPIOB13 output set</description>
              <bitRange>[13:13]</bitRange>
              <access>write-only</access>
            </field>
            <field>
              <name>BS14</name>
              <description>GPIOB14 output set</description>
              <bitRange>[14:14]</bitRange>
              <access>write-only</access>
            </field>
            <field>
              <name>BS15</name>
              <description>GPIOB15 output set</description>
              <bitRange>[15:15]</bitRange>
              <access>write-only</access>
            </field>
            <field>
              <name>BR0</name>
              <description>GPIOB0 outut reset</description>
              <bitRange>[16:16]</bitRange>
              <access>write-only</access>
            </field>
            <field>
              <name>BR1</name>
              <description>GPIOB1 outut reset</description>
              <bitRange>[17:17]</bitRange>
              <access>write-only</access>
            </field>
            <field>
              <name>BR2</name>
              <description>GPIOB2 outut reset</description>
              <bitRange>[18:18]</bitRange>
              <access>write-only</access>
            </field>
            <field>
              <name>BR3</name>
              <description>GPIOB3 outut reset</description>
              <bitRange>[19:19]</bitRange>
              <access>write-only</access>
            </field>
            <field>
              <name>BR4</name>
              <description>GPIOB4 outut reset</description>
              <bitRange>[20:20]</bitRange>
              <access>write-only</access>
            </field>
            <field>
              <name>BR5</name>
              <description>GPIOB5 outut reset</description>
              <bitRange>[21:21]</bitRange>
              <access>write-only</access>
            </field>
            <field>
              <name>BR6</name>
              <description>GPIOB6 outut reset</description>
              <bitRange>[22:22]</bitRange>
              <access>write-only</access>
            </field>
            <field>
              <name>BR7</name>
              <description>GPIOB7 outut reset</description>
              <bitRange>[23:23]</bitRange>
              <access>write-only</access>
            </field>
            <field>
              <name>BR8</name>
              <description>GPIOB8 outut reset</description>
              <bitRange>[24:24]</bitRange>
              <access>write-only</access>
            </field>
            <field>
              <name>BR9</name>
              <description>GPIOB9 outut reset</description>
              <bitRange>[25:25]</bitRange>
              <access>write-only</access>
            </field>
            <field>
              <name>BR10</name>
              <description>GPIOB10 outut reset</description>
              <bitRange>[26:26]</bitRange>
              <access>write-only</access>
            </field>
            <field>
              <name>BR11</name>
              <description>GPIOB11 outut reset</description>
              <bitRange>[27:27]</bitRange>
              <access>write-only</access>
            </field>
            <field>
              <name>BR12</name>
              <description>GPIOB12 outut reset</description>
              <bitRange>[28:28]</bitRange>
              <access>write-only</access>
            </field>
            <field>
              <name>BR13</name>
              <description>GPIOB13 outut reset</description>
              <bitRange>[29:29]</bitRange>
              <access>write-only</access>
            </field>
            <field>
              <name>BR14</name>
              <description>GPIOB14 outut reset</description>
              <bitRange>[30:30]</bitRange>
              <access>write-only</access>
            </field>
            <field>
              <name>BR15</name>
              <description>GPIOB15 outut reset</description>
              <bitRange>[31:31]</bitRange>
              <access>write-only</access>
            </field>
          </fields>
        </register>
        <register>
          <name>LCKR</name>
          <addressOffset>0x1C</addressOffset>
          <fields>
            <field>
              <name>LCK0</name>
              <description>GPIOB lock(bit0)</description>
              <bitRange>[0:0]</bitRange>
            </field>
            <field>
              <name>LCK1</name>
              <description>GPIOB lock(bit1)</description>
              <bitRange>[1:1]</bitRange>
            </field>
            <field>
              <name>LCK2</name>
              <description>GPIOB lock(bit2)</description>
              <bitRange>[2:2]</bitRange>
            </field>
            <field>
              <name>LCK3</name>
              <description>GPIOB lock(bit3)</description>
              <bitRange>[3:3]</bitRange>
            </field>
            <field>
              <name>LCK4</name>
              <description>GPIOB lock(bit4)</description>
              <bitRange>[4:4]</bitRange>
            </field>
            <field>
              <name>LCK5</name>
              <description>GPIOB lock(bit5)</description>
              <bitRange>[5:5]</bitRange>
            </field>
            <field>
              <name>LCK6</name>
              <description>GPIOB lock(bit6)</description>
              <bitRange>[6:6]</bitRange>
            </field>
            <field>
              <name>LCK7</name>
              <description>GPIOB lock(bit7)</description>
              <bitRange>[7:7]</bitRange>
            </field>
            <field>
              <name>LCK8</name>
              <description>GPIOB lock(bit8)</description>
              <bitRange>[8:8]</bitRange>
            </field>
            <field>
              <name>LCK9</name>
              <description>GPIOB lock(bit9)</description>
              <bitRange>[9:9]</bitRange>
            </field>
            <field>
              <name>LCK10</name>
              <description>GPIOB lock(bit10)</description>
              <bitRange>[10:10]</bitRange>
            </field>
            <field>
              <name>LCK11</name>
              <description>GPIOB lock(bit11)</description>
              <bitRange>[11:11]</bitRange>
            </field>
            <field>
              <name>LCK12</name>
              <description>GPIOB lock(bit12)</description>
              <bitRange>[12:12]</bitRange>
            </field>
            <field>
              <name>LCK13</name>
              <description>GPIOB lock(bit13)</description>
              <bitRange>[13:13]</bitRange>
            </field>
            <field>
              <name>LCK14</name>
              <description>GPIOB lock(bit14)</description>
              <bitRange>[14:14]</bitRange>
            </field>
            <field>
              <name>LCK15</name>
              <description>GPIOB lock(bit15)</description>
              <bitRange>[15:15]</bitRange>
            </field>
            <field>
              <name>LCKK</name>
              <description>GPIOB lock key</description>
              <bitRange>[16:16]</bitRange>
            </field>
          </fields>
        </register>
        <register>
          <name>AFRL</name>
          <addressOffset>0x20</addressOffset>
          <fields>
            <field>
              <name>AFSEL0</name>
              <description>GPIOB0 AF select</description>
              <bitRange>[3:0]</bitRange>
              <enumeratedValues>
                <enumeratedValue>
                  <name>0</name>
                  <value>1</value>
                </enumeratedValue>
                <enumeratedValue>
                  <name>1</name>
                  <value>2</value>
                </enumeratedValue>
                <enumeratedValue>
                  <name>2</name>
                  <value>4</value>
                </enumeratedValue>
                <enumeratedValue>
                  <name>3</name>
                  <value>8</value>
                </enumeratedValue>
              </enumeratedValues>
            </field>
            <field>
              <name>AFSEL1</name>
              <description>GPIOB1 AF select</description>
              <bitRange>[7:4]</bitRange>
              <enumeratedValues>
                <enumeratedValue>
                  <name>0</name>
                  <value>1</value>
                </enumeratedValue>
                <enumeratedValue>
                  <name>1</name>
                  <value>2</value>
                </enumeratedValue>
                <enumeratedValue>
                  <name>2</name>
                  <value>4</value>
                </enumeratedValue>
                <enumeratedValue>
                  <name>3</name>
                  <value>8</value>
                </enumeratedValue>
              </enumeratedValues>
            </field>
            <field>
              <name>AFSEL2</name>
              <description>GPIOB2 AF select</description>
              <bitRange>[11:8]</bitRange>
              <enumeratedValues>
                <enumeratedValue>
                  <name>0</name>
                  <value>1</value>
                </enumeratedValue>
                <enumeratedValue>
                  <name>1</name>
                  <value>2</value>
                </enumeratedValue>
                <enumeratedValue>
                  <name>2</name>
                  <value>4</value>
                </enumeratedValue>
                <enumeratedValue>
                  <name>3</name>
                  <value>8</value>
                </enumeratedValue>
              </enumeratedValues>
            </field>
            <field>
              <name>AFSEL3</name>
              <description>GPIOB3 AF select</description>
              <bitRange>[15:12]</bitRange>
              <enumeratedValues>
                <enumeratedValue>
                  <name>0</name>
                  <value>1</value>
                </enumeratedValue>
                <enumeratedValue>
                  <name>1</name>
                  <value>2</value>
                </enumeratedValue>
                <enumeratedValue>
                  <name>2</name>
                  <value>4</value>
                </enumeratedValue>
                <enumeratedValue>
                  <name>3</name>
                  <value>8</value>
                </enumeratedValue>
              </enumeratedValues>
            </field>
            <field>
              <name>AFSEL4</name>
              <description>GPIOB4 AF select</description>
              <bitRange>[19:16]</bitRange>
              <enumeratedValues>
                <enumeratedValue>
                  <name>0</name>
                  <value>1</value>
                </enumeratedValue>
                <enumeratedValue>
                  <name>1</name>
                  <value>2</value>
                </enumeratedValue>
                <enumeratedValue>
                  <name>2</name>
                  <value>4</value>
                </enumeratedValue>
                <enumeratedValue>
                  <name>3</name>
                  <value>8</value>
                </enumeratedValue>
              </enumeratedValues>
            </field>
            <field>
              <name>AFSEL5</name>
              <description>GPIOB5 AF select</description>
              <bitRange>[23:20]</bitRange>
              <enumeratedValues>
                <enumeratedValue>
                  <name>0</name>
                  <value>1</value>
                </enumeratedValue>
                <enumeratedValue>
                  <name>1</name>
                  <value>2</value>
                </enumeratedValue>
                <enumeratedValue>
                  <name>2</name>
                  <value>4</value>
                </enumeratedValue>
                <enumeratedValue>
                  <name>3</name>
                  <value>8</value>
                </enumeratedValue>
              </enumeratedValues>
            </field>
            <field>
              <name>AFSEL6</name>
              <description>GPIOB6 AF select</description>
              <bitRange>[27:24]</bitRange>
              <enumeratedValues>
                <enumeratedValue>
                  <name>0</name>
                  <value>1</value>
                </enumeratedValue>
                <enumeratedValue>
                  <name>1</name>
                  <value>2</value>
                </enumeratedValue>
                <enumeratedValue>
                  <name>2</name>
                  <value>4</value>
                </enumeratedValue>
                <enumeratedValue>
                  <name>3</name>
                  <value>8</value>
                </enumeratedValue>
              </enumeratedValues>
            </field>
            <field>
              <name>AFSEL7</name>
              <description>GPIOB7 AF select</description>
              <bitRange>[31:28]</bitRange>
              <enumeratedValues>
                <enumeratedValue>
                  <name>0</name>
                  <value>1</value>
                </enumeratedValue>
                <enumeratedValue>
                  <name>1</name>
                  <value>2</value>
                </enumeratedValue>
                <enumeratedValue>
                  <name>2</name>
                  <value>4</value>
                </enumeratedValue>
                <enumeratedValue>
                  <name>3</name>
                  <value>8</value>
                </enumeratedValue>
              </enumeratedValues>
            </field>
          </fields>
        </register>
        <register>
          <name>AFRH</name>
          <addressOffset>0x24</addressOffset>
          <fields>
            <field>
              <name>AFSEL8</name>
              <description>GPIOB8 AF select</description>
              <bitRange>[3:0]</bitRange>
              <enumeratedValues>
                <enumeratedValue>
                  <name>0</name>
                  <value>1</value>
                </enumeratedValue>
                <enumeratedValue>
                  <name>1</name>
                  <value>2</value>
                </enumeratedValue>
                <enumeratedValue>
                  <name>2</name>
                  <value>4</value>
                </enumeratedValue>
                <enumeratedValue>
                  <name>3</name>
                  <value>8</value>
                </enumeratedValue>
              </enumeratedValues>
            </field>
            <field>
              <name>AFSEL9</name>
              <description>GPIOB9 AF select</description>
              <bitRange>[7:4]</bitRange>
              <enumeratedValues>
                <enumeratedValue>
                  <name>0</name>
                  <value>1</value>
                </enumeratedValue>
                <enumeratedValue>
                  <name>1</name>
                  <value>2</value>
                </enumeratedValue>
                <enumeratedValue>
                  <name>2</name>
                  <value>4</value>
                </enumeratedValue>
                <enumeratedValue>
                  <name>3</name>
                  <value>8</value>
                </enumeratedValue>
              </enumeratedValues>
            </field>
            <field>
              <name>AFSEL10</name>
              <description>GPIOB10 AF select</description>
              <bitRange>[11:8]</bitRange>
              <enumeratedValues>
                <enumeratedValue>
                  <name>0</name>
                  <value>1</value>
                </enumeratedValue>
                <enumeratedValue>
                  <name>1</name>
                  <value>2</value>
                </enumeratedValue>
                <enumeratedValue>
                  <name>2</name>
                  <value>4</value>
                </enumeratedValue>
                <enumeratedValue>
                  <name>3</name>
                  <value>8</value>
                </enumeratedValue>
              </enumeratedValues>
            </field>
            <field>
              <name>AFSEL11</name>
              <description>GPIOB11 AF select</description>
              <bitRange>[15:12]</bitRange>
              <enumeratedValues>
                <enumeratedValue>
                  <name>0</name>
                  <value>1</value>
                </enumeratedValue>
                <enumeratedValue>
                  <name>1</name>
                  <value>2</value>
                </enumeratedValue>
                <enumeratedValue>
                  <name>2</name>
                  <value>4</value>
                </enumeratedValue>
                <enumeratedValue>
                  <name>3</name>
                  <value>8</value>
                </enumeratedValue>
              </enumeratedValues>
            </field>
            <field>
              <name>AFSEL12</name>
              <description>GPIOB12 AF select</description>
              <bitRange>[19:16]</bitRange>
              <enumeratedValues>
                <enumeratedValue>
                  <name>0</name>
                  <value>1</value>
                </enumeratedValue>
                <enumeratedValue>
                  <name>1</name>
                  <value>2</value>
                </enumeratedValue>
                <enumeratedValue>
                  <name>2</name>
                  <value>4</value>
                </enumeratedValue>
                <enumeratedValue>
                  <name>3</name>
                  <value>8</value>
                </enumeratedValue>
              </enumeratedValues>
            </field>
            <field>
              <name>AFSEL13</name>
              <description>GPIOB13 AF select</description>
              <bitRange>[23:20]</bitRange>
              <enumeratedValues>
                <enumeratedValue>
                  <name>0</name>
                  <value>1</value>
                </enumeratedValue>
                <enumeratedValue>
                  <name>1</name>
                  <value>2</value>
                </enumeratedValue>
                <enumeratedValue>
                  <name>2</name>
                  <value>4</value>
                </enumeratedValue>
                <enumeratedValue>
                  <name>3</name>
                  <value>8</value>
                </enumeratedValue>
              </enumeratedValues>
            </field>
            <field>
              <name>AFSEL14</name>
              <description>GPIOB14 AF select</description>
              <bitRange>[27:24]</bitRange>
              <enumeratedValues>
                <enumeratedValue>
                  <name>0</name>
                  <value>1</value>
                </enumeratedValue>
                <enumeratedValue>
                  <name>1</name>
                  <value>2</value>
                </enumeratedValue>
                <enumeratedValue>
                  <name>2</name>
                  <value>4</value>
                </enumeratedValue>
                <enumeratedValue>
                  <name>3</name>
                  <value>8</value>
                </enumeratedValue>
              </enumeratedValues>
            </field>
            <field>
              <name>AFSEL15</name>
              <description>GPIOB15 AF select</description>
              <bitRange>[31:28]</bitRange>
              <enumeratedValues>
                <enumeratedValue>
                  <name>0</name>
                  <value>1</value>
                </enumeratedValue>
                <enumeratedValue>
                  <name>1</name>
                  <value>2</value>
                </enumeratedValue>
                <enumeratedValue>
                  <name>2</name>
                  <value>4</value>
                </enumeratedValue>
                <enumeratedValue>
                  <name>3</name>
                  <value>8</value>
                </enumeratedValue>
              </enumeratedValues>
            </field>
          </fields>
        </register>
        <register>
          <name>BRR</name>
          <addressOffset>0x28</addressOffset>
          <fields>
            <field>
              <name>BR0</name>
              <description>GPIOB 0 output pin reset</description>
              <bitRange>[0:0]</bitRange>
              <access>write-only</access>
            </field>
            <field>
              <name>BR1</name>
              <description>GPIOB 1 output pin reset</description>
              <bitRange>[1:1]</bitRange>
              <access>write-only</access>
            </field>
            <field>
              <name>BR2</name>
              <description>GPIOB 2 output pin reset</description>
              <bitRange>[2:2]</bitRange>
              <access>write-only</access>
            </field>
            <field>
              <name>BR3</name>
              <description>GPIOB 3 output pin reset</description>
              <bitRange>[3:3]</bitRange>
              <access>write-only</access>
            </field>
            <field>
              <name>BR4</name>
              <description>GPIOB 4 output pin reset</description>
              <bitRange>[4:4]</bitRange>
              <access>write-only</access>
            </field>
            <field>
              <name>BR5</name>
              <description>GPIOB 5 output pin reset</description>
              <bitRange>[5:5]</bitRange>
              <access>write-only</access>
            </field>
            <field>
              <name>BR6</name>
              <description>GPIOB 6 output pin reset</description>
              <bitRange>[6:6]</bitRange>
              <access>write-only</access>
            </field>
            <field>
              <name>BR7</name>
              <description>GPIOB 7 output pin reset</description>
              <bitRange>[7:7]</bitRange>
              <access>write-only</access>
            </field>
            <field>
              <name>BR8</name>
              <description>GPIOB 8 output pin reset</description>
              <bitRange>[8:8]</bitRange>
              <access>write-only</access>
            </field>
            <field>
              <name>BR9</name>
              <description>GPIOB 9 output pin reset</description>
              <bitRange>[9:9]</bitRange>
              <access>write-only</access>
            </field>
            <field>
              <name>BR10</name>
              <description>GPIOB 10 output pin reset</description>
              <bitRange>[10:10]</bitRange>
              <access>write-only</access>
            </field>
            <field>
              <name>BR11</name>
              <description>GPIOB 11 output pin reset</description>
              <bitRange>[11:11]</bitRange>
              <access>write-only</access>
            </field>
            <field>
              <name>BR12</name>
              <description>GPIOB 12 output pin reset</description>
              <bitRange>[12:12]</bitRange>
              <access>write-only</access>
            </field>
            <field>
              <name>BR13</name>
              <description>GPIOB 13 output pin reset</description>
              <bitRange>[13:13]</bitRange>
              <access>write-only</access>
            </field>
            <field>
              <name>BR14</name>
              <description>GPIOB 14 output pin reset</description>
              <bitRange>[14:14]</bitRange>
              <access>write-only</access>
            </field>
            <field>
              <name>BR15</name>
              <description>GPIOB 15 output pin reset</description>
              <bitRange>[15:15]</bitRange>
              <access>write-only</access>
            </field>
          </fields>
        </register>
      </registers>
    </peripheral>
    <peripheral>
      <name>GPIOC</name>
      <groupName>GPIO</groupName>
      <description>General-purpose I/Os</description>
      <baseAddress>0x50000800</baseAddress>
      <addressBlock>
        <offset>0x0</offset>
        <size>0x30</size>
        <usage>registers</usage>
      </addressBlock>
      <registers>
        <register>
          <name>MODER</name>
          <addressOffset>0x0</addressOffset>
          <fields>
            <field>
              <name>MODER0</name>
              <description>GPIOC0 MODE</description>
              <bitRange>[1:0]</bitRange>
            </field>
            <field>
              <name>MODER1</name>
              <description>GPIOC1 MODE</description>
              <bitRange>[3:2]</bitRange>
            </field>
            <field>
              <name>MODER2</name>
              <description>GPIOC2 MODE</description>
              <bitRange>[5:4]</bitRange>
            </field>
            <field>
              <name>MODER3</name>
              <description>GPIOC3 MODE</description>
              <bitRange>[7:6]</bitRange>
            </field>
            <field>
              <name>MODER4</name>
              <description>GPIOC4 MODE</description>
              <bitRange>[9:8]</bitRange>
            </field>
            <field>
              <name>MODER5</name>
              <description>GPIOC5 MODE</description>
              <bitRange>[11:10]</bitRange>
            </field>
            <field>
              <name>MODER6</name>
              <description>GPIOC6 MODE</description>
              <bitRange>[13:12]</bitRange>
            </field>
            <field>
              <name>MODER7</name>
              <description>GPIOC7 MODE</description>
              <bitRange>[15:14]</bitRange>
            </field>
            <field>
              <name>MODER8</name>
              <description>GPIOC8 MODE</description>
              <bitRange>[17:16]</bitRange>
            </field>
            <field>
              <name>MODER9</name>
              <description>GPIOC9 MODE</description>
              <bitRange>[19:18]</bitRange>
            </field>
            <field>
              <name>MODER10</name>
              <description>GPIOC10 MODE</description>
              <bitRange>[21:20]</bitRange>
            </field>
            <field>
              <name>MODER11</name>
              <description>GPIOC11 MODE</description>
              <bitRange>[23:22]</bitRange>
            </field>
            <field>
              <name>MODER12</name>
              <description>GPIOC12 MODE</description>
              <bitRange>[25:24]</bitRange>
            </field>
            <field>
              <name>MODER13</name>
              <description>GPIOC13 MODE</description>
              <bitRange>[27:26]</bitRange>
            </field>
            <field>
              <name>MODER14</name>
              <description>GPIOC14 MODE</description>
              <bitRange>[29:28]</bitRange>
            </field>
            <field>
              <name>MODER15</name>
              <description>GPIOC15 MODE</description>
              <bitRange>[31:30]</bitRange>
            </field>
          </fields>
        </register>
        <register>
          <name>OTYPER</name>
          <addressOffset>0x4</addressOffset>
          <fields>
            <field>
              <name>OT0</name>
              <description>GPIOC0 Output type</description>
              <bitRange>[0:0]</bitRange>
            </field>
            <field>
              <name>OT1</name>
              <description>GPIOC1 Output type</description>
              <bitRange>[1:1]</bitRange>
            </field>
            <field>
              <name>OT2</name>
              <description>GPIOC2 Output type</description>
              <bitRange>[2:2]</bitRange>
            </field>
            <field>
              <name>OT3</name>
              <description>GPIOC3 Output type</description>
              <bitRange>[3:3]</bitRange>
            </field>
            <field>
              <name>OT4</name>
              <description>GPIOC4 Output type</description>
              <bitRange>[4:4]</bitRange>
            </field>
            <field>
              <name>OT5</name>
              <description>GPIOC5 Output type</description>
              <bitRange>[5:5]</bitRange>
            </field>
            <field>
              <name>OT6</name>
              <description>GPIOC6 Output type</description>
              <bitRange>[6:6]</bitRange>
            </field>
            <field>
              <name>OT7</name>
              <description>GPIOC7 Output type</description>
              <bitRange>[7:7]</bitRange>
            </field>
            <field>
              <name>OT8</name>
              <description>GPIOC8 Output type</description>
              <bitRange>[8:8]</bitRange>
            </field>
            <field>
              <name>OT9</name>
              <description>GPIOC9 Output type</description>
              <bitRange>[9:9]</bitRange>
            </field>
            <field>
              <name>OT10</name>
              <description>GPIOC10 Output type</description>
              <bitRange>[10:10]</bitRange>
            </field>
            <field>
              <name>OT11</name>
              <description>GPIOC11 Output type</description>
              <bitRange>[11:11]</bitRange>
            </field>
            <field>
              <name>OT12</name>
              <description>GPIOC12 Output type</description>
              <bitRange>[12:12]</bitRange>
            </field>
            <field>
              <name>OT13</name>
              <description>GPIOC13 Output type</description>
              <bitRange>[13:13]</bitRange>
            </field>
            <field>
              <name>OT14</name>
              <description>GPIOC14 Output type</description>
              <bitRange>[14:14]</bitRange>
            </field>
            <field>
              <name>OT15</name>
              <description>GPIOC15 Output type</description>
              <bitRange>[15:15]</bitRange>
            </field>
          </fields>
        </register>
        <register>
          <name>OSPDDER</name>
          <addressOffset>0x8</addressOffset>
          <fields>
            <field>
              <name>OSPEED0</name>
              <description>GPIOC0 output speed</description>
              <bitRange>[1:0]</bitRange>
            </field>
            <field>
              <name>OSPEED1</name>
              <description>GPIOC1 output speed</description>
              <bitRange>[3:2]</bitRange>
            </field>
            <field>
              <name>OSPEED2</name>
              <description>GPIOC2 output speed</description>
              <bitRange>[5:4]</bitRange>
            </field>
            <field>
              <name>OSPEED3</name>
              <description>GPIOC3 output speed</description>
              <bitRange>[7:6]</bitRange>
            </field>
            <field>
              <name>OSPEED4</name>
              <description>GPIOC4 output speed</description>
              <bitRange>[9:8]</bitRange>
            </field>
            <field>
              <name>OSPEED5</name>
              <description>GPIOC5 output speed</description>
              <bitRange>[11:10]</bitRange>
            </field>
            <field>
              <name>OSPEED6</name>
              <description>GPIOC6 output speed</description>
              <bitRange>[13:12]</bitRange>
            </field>
            <field>
              <name>OSPEED7</name>
              <description>GPIOC7 output speed</description>
              <bitRange>[15:14]</bitRange>
            </field>
            <field>
              <name>OSPEED8</name>
              <description>GPIOC8 output speed</description>
              <bitRange>[17:16]</bitRange>
            </field>
            <field>
              <name>OSPEED9</name>
              <description>GPIOC9 output speed</description>
              <bitRange>[19:18]</bitRange>
            </field>
            <field>
              <name>OSPEED10</name>
              <description>GPIOC10 output speed</description>
              <bitRange>[21:20]</bitRange>
            </field>
            <field>
              <name>OSPEED11</name>
              <description>GPIOC11 output speed</description>
              <bitRange>[23:22]</bitRange>
            </field>
            <field>
              <name>OSPEED12</name>
              <description>GPIOC12 output speed</description>
              <bitRange>[25:24]</bitRange>
            </field>
            <field>
              <name>OSPEED13</name>
              <description>GPIOC13 output speed</description>
              <bitRange>[27:26]</bitRange>
            </field>
            <field>
              <name>OSPEED14</name>
              <description>GPIOC14 output speed</description>
              <bitRange>[29:28]</bitRange>
            </field>
            <field>
              <name>OSPEED15</name>
              <description>GPIOC15 output speed</description>
              <bitRange>[31:30]</bitRange>
            </field>
          </fields>
        </register>
        <register>
          <name>PUPDR</name>
          <addressOffset>0xC</addressOffset>
          <fields>
            <field>
              <name>PUPD0</name>
              <description>GPIOC0 pull up/pull down</description>
              <bitRange>[1:0]</bitRange>
              <enumeratedValues>
                <enumeratedValue>
                  <name>0</name>
                  <value>1</value>
                </enumeratedValue>
                <enumeratedValue>
                  <name>1</name>
                  <value>2</value>
                </enumeratedValue>
              </enumeratedValues>
            </field>
            <field>
              <name>PUPD1</name>
              <description>GPIOC1 pull up/pull down</description>
              <bitRange>[3:2]</bitRange>
              <enumeratedValues>
                <enumeratedValue>
                  <name>0</name>
                  <value>1</value>
                </enumeratedValue>
                <enumeratedValue>
                  <name>1</name>
                  <value>2</value>
                </enumeratedValue>
              </enumeratedValues>
            </field>
            <field>
              <name>PUPD2</name>
              <description>GPIOC2 pull up/pull down</description>
              <bitRange>[5:4]</bitRange>
              <enumeratedValues>
                <enumeratedValue>
                  <name>0</name>
                  <value>1</value>
                </enumeratedValue>
                <enumeratedValue>
                  <name>1</name>
                  <value>2</value>
                </enumeratedValue>
              </enumeratedValues>
            </field>
            <field>
              <name>PUPD3</name>
              <description>GPIOC3 pull up/pull down</description>
              <bitRange>[7:6]</bitRange>
              <enumeratedValues>
                <enumeratedValue>
                  <name>0</name>
                  <value>1</value>
                </enumeratedValue>
                <enumeratedValue>
                  <name>1</name>
                  <value>2</value>
                </enumeratedValue>
              </enumeratedValues>
            </field>
            <field>
              <name>PUPD4</name>
              <description>GPIOC4 pull up/pull down</description>
              <bitRange>[9:8]</bitRange>
              <enumeratedValues>
                <enumeratedValue>
                  <name>0</name>
                  <value>1</value>
                </enumeratedValue>
                <enumeratedValue>
                  <name>1</name>
                  <value>2</value>
                </enumeratedValue>
              </enumeratedValues>
            </field>
            <field>
              <name>PUPD5</name>
              <description>GPIOC5 pull up/pull down</description>
              <bitRange>[11:10]</bitRange>
              <enumeratedValues>
                <enumeratedValue>
                  <name>0</name>
                  <value>1</value>
                </enumeratedValue>
                <enumeratedValue>
                  <name>1</name>
                  <value>2</value>
                </enumeratedValue>
              </enumeratedValues>
            </field>
            <field>
              <name>PUPD6</name>
              <description>GPIOC6 pull up/pull down</description>
              <bitRange>[13:12]</bitRange>
              <enumeratedValues>
                <enumeratedValue>
                  <name>0</name>
                  <value>1</value>
                </enumeratedValue>
                <enumeratedValue>
                  <name>1</name>
                  <value>2</value>
                </enumeratedValue>
              </enumeratedValues>
            </field>
            <field>
              <name>PUPD7</name>
              <description>GPIOC7 pull up/pull down</description>
              <bitRange>[15:14]</bitRange>
              <enumeratedValues>
                <enumeratedValue>
                  <name>0</name>
                  <value>1</value>
                </enumeratedValue>
                <enumeratedValue>
                  <name>1</name>
                  <value>2</value>
                </enumeratedValue>
              </enumeratedValues>
            </field>
            <field>
              <name>PUPD8</name>
              <description>GPIOC8 pull up/pull down</description>
              <bitRange>[17:16]</bitRange>
              <enumeratedValues>
                <enumeratedValue>
                  <name>0</name>
                  <value>1</value>
                </enumeratedValue>
                <enumeratedValue>
                  <name>1</name>
                  <value>2</value>
                </enumeratedValue>
              </enumeratedValues>
            </field>
            <field>
              <name>PUPD9</name>
              <description>GPIOC9 pull up/pull down</description>
              <bitRange>[19:18]</bitRange>
              <enumeratedValues>
                <enumeratedValue>
                  <name>0</name>
                  <value>1</value>
                </enumeratedValue>
                <enumeratedValue>
                  <name>1</name>
                  <value>2</value>
                </enumeratedValue>
              </enumeratedValues>
            </field>
            <field>
              <name>PUPD10</name>
              <description>GPIOC10 pull up/pull down</description>
              <bitRange>[21:20]</bitRange>
              <enumeratedValues>
                <enumeratedValue>
                  <name>0</name>
                  <value>1</value>
                </enumeratedValue>
                <enumeratedValue>
                  <name>1</name>
                  <value>2</value>
                </enumeratedValue>
              </enumeratedValues>
            </field>
            <field>
              <name>PUPD11</name>
              <description>GPIOC11 pull up/pull down</description>
              <bitRange>[23:22]</bitRange>
              <enumeratedValues>
                <enumeratedValue>
                  <name>0</name>
                  <value>1</value>
                </enumeratedValue>
                <enumeratedValue>
                  <name>1</name>
                  <value>2</value>
                </enumeratedValue>
              </enumeratedValues>
            </field>
            <field>
              <name>PUPD12</name>
              <description>GPIOC12 pull up/pull down</description>
              <bitRange>[25:24]</bitRange>
              <enumeratedValues>
                <enumeratedValue>
                  <name>0</name>
                  <value>1</value>
                </enumeratedValue>
                <enumeratedValue>
                  <name>1</name>
                  <value>2</value>
                </enumeratedValue>
              </enumeratedValues>
            </field>
            <field>
              <name>PUPD13</name>
              <description>GPIOC13 pull up/pull down</description>
              <bitRange>[27:26]</bitRange>
              <enumeratedValues>
                <enumeratedValue>
                  <name>0</name>
                  <value>1</value>
                </enumeratedValue>
                <enumeratedValue>
                  <name>1</name>
                  <value>2</value>
                </enumeratedValue>
              </enumeratedValues>
            </field>
            <field>
              <name>PUPD14</name>
              <description>GPIOC14 pull up/pull down</description>
              <bitRange>[29:28]</bitRange>
              <enumeratedValues>
                <enumeratedValue>
                  <name>0</name>
                  <value>1</value>
                </enumeratedValue>
                <enumeratedValue>
                  <name>1</name>
                  <value>2</value>
                </enumeratedValue>
              </enumeratedValues>
            </field>
            <field>
              <name>PUPD15</name>
              <description>GPIOC15 pull up/pull down</description>
              <bitRange>[31:30]</bitRange>
              <enumeratedValues>
                <enumeratedValue>
                  <name>0</name>
                  <value>1</value>
                </enumeratedValue>
                <enumeratedValue>
                  <name>1</name>
                  <value>2</value>
                </enumeratedValue>
              </enumeratedValues>
            </field>
          </fields>
        </register>
        <register>
          <name>IDR</name>
          <addressOffset>0x10</addressOffset>
          <fields>
            <field>
              <name>ID0</name>
              <description>GPIOC0 input data</description>
              <bitRange>[0:0]</bitRange>
              <access>read-only</access>
            </field>
            <field>
              <name>ID1</name>
              <description>GPIOC1 input data</description>
              <bitRange>[1:1]</bitRange>
              <access>read-only</access>
            </field>
            <field>
              <name>ID2</name>
              <description>GPIOC2 input data</description>
              <bitRange>[2:2]</bitRange>
              <access>read-only</access>
            </field>
            <field>
              <name>ID3</name>
              <description>GPIOC3 input data</description>
              <bitRange>[3:3]</bitRange>
              <access>read-only</access>
            </field>
            <field>
              <name>ID4</name>
              <description>GPIOC4 input data</description>
              <bitRange>[4:4]</bitRange>
              <access>read-only</access>
            </field>
            <field>
              <name>ID5</name>
              <description>GPIOC5 input data</description>
              <bitRange>[5:5]</bitRange>
              <access>read-only</access>
            </field>
            <field>
              <name>ID6</name>
              <description>GPIOC6 input data</description>
              <bitRange>[6:6]</bitRange>
              <access>read-only</access>
            </field>
            <field>
              <name>ID7</name>
              <description>GPIOC7 input data</description>
              <bitRange>[7:7]</bitRange>
              <access>read-only</access>
            </field>
            <field>
              <name>ID8</name>
              <description>GPIOC8 input data</description>
              <bitRange>[8:8]</bitRange>
              <access>read-only</access>
            </field>
            <field>
              <name>ID9</name>
              <description>GPIOC9 input data</description>
              <bitRange>[9:9]</bitRange>
              <access>read-only</access>
            </field>
            <field>
              <name>ID10</name>
              <description>GPIOC10 input data</description>
              <bitRange>[10:10]</bitRange>
              <access>read-only</access>
            </field>
            <field>
              <name>ID11</name>
              <description>GPIOC11 input data</description>
              <bitRange>[11:11]</bitRange>
              <access>read-only</access>
            </field>
            <field>
              <name>ID12</name>
              <description>GPIOC12 input data</description>
              <bitRange>[12:12]</bitRange>
              <access>read-only</access>
            </field>
            <field>
              <name>ID13</name>
              <description>GPIOC13 input data</description>
              <bitRange>[13:13]</bitRange>
              <access>read-only</access>
            </field>
            <field>
              <name>ID14</name>
              <description>GPIOC14 input data</description>
              <bitRange>[14:14]</bitRange>
              <access>read-only</access>
            </field>
            <field>
              <name>ID15</name>
              <description>GPIOC15 input data</description>
              <bitRange>[15:15]</bitRange>
              <access>read-only</access>
            </field>
          </fields>
        </register>
        <register>
          <name>ODR</name>
          <addressOffset>0x14</addressOffset>
          <fields>
            <field>
              <name>OD0</name>
              <description>GPIOC0 output data</description>
              <bitRange>[0:0]</bitRange>
            </field>
            <field>
              <name>OD1</name>
              <description>GPIOC1 output data</description>
              <bitRange>[1:1]</bitRange>
            </field>
            <field>
              <name>OD2</name>
              <description>GPIOC2 output data</description>
              <bitRange>[2:2]</bitRange>
            </field>
            <field>
              <name>OD3</name>
              <description>GPIOC3 output data</description>
              <bitRange>[3:3]</bitRange>
            </field>
            <field>
              <name>OD4</name>
              <description>GPIOC4 output data</description>
              <bitRange>[4:4]</bitRange>
            </field>
            <field>
              <name>OD5</name>
              <description>GPIOC5 output data</description>
              <bitRange>[5:5]</bitRange>
            </field>
            <field>
              <name>OD6</name>
              <description>GPIOC6 output data</description>
              <bitRange>[6:6]</bitRange>
            </field>
            <field>
              <name>OD7</name>
              <description>GPIOC7 output data</description>
              <bitRange>[7:7]</bitRange>
            </field>
            <field>
              <name>OD8</name>
              <description>GPIOC8 output data</description>
              <bitRange>[8:8]</bitRange>
            </field>
            <field>
              <name>OD9</name>
              <description>GPIOC9 output data</description>
              <bitRange>[9:9]</bitRange>
            </field>
            <field>
              <name>OD10</name>
              <description>GPIOC10 output data</description>
              <bitRange>[10:10]</bitRange>
            </field>
            <field>
              <name>OD11</name>
              <description>GPIOC11 output data</description>
              <bitRange>[11:11]</bitRange>
            </field>
            <field>
              <name>OD12</name>
              <description>GPIOC12 output data</description>
              <bitRange>[12:12]</bitRange>
            </field>
            <field>
              <name>OD13</name>
              <description>GPIOC13 output data</description>
              <bitRange>[13:13]</bitRange>
            </field>
            <field>
              <name>OD14</name>
              <description>GPIOC14 output data</description>
              <bitRange>[14:14]</bitRange>
            </field>
            <field>
              <name>OD15</name>
              <description>GPIOC15 output data</description>
              <bitRange>[15:15]</bitRange>
            </field>
          </fields>
        </register>
        <register>
          <name>BSRR</name>
          <addressOffset>0x18</addressOffset>
          <fields>
            <field>
              <name>BS0</name>
              <description>GPIOC0 output set</description>
              <bitRange>[0:0]</bitRange>
              <access>write-only</access>
            </field>
            <field>
              <name>BS1</name>
              <description>GPIOC1 output set</description>
              <bitRange>[1:1]</bitRange>
              <access>write-only</access>
            </field>
            <field>
              <name>BS2</name>
              <description>GPIOC2 output set</description>
              <bitRange>[2:2]</bitRange>
              <access>write-only</access>
            </field>
            <field>
              <name>BS3</name>
              <description>GPIOC3 output set</description>
              <bitRange>[3:3]</bitRange>
              <access>write-only</access>
            </field>
            <field>
              <name>BS4</name>
              <description>GPIOC4 output set</description>
              <bitRange>[4:4]</bitRange>
              <access>write-only</access>
            </field>
            <field>
              <name>BS5</name>
              <description>GPIOC5 output set</description>
              <bitRange>[5:5]</bitRange>
              <access>write-only</access>
            </field>
            <field>
              <name>BS6</name>
              <description>GPIOC6 output set</description>
              <bitRange>[6:6]</bitRange>
              <access>write-only</access>
            </field>
            <field>
              <name>BS7</name>
              <description>GPIOC7 output set</description>
              <bitRange>[7:7]</bitRange>
              <access>write-only</access>
            </field>
            <field>
              <name>BS8</name>
              <description>GPIOC8 output set</description>
              <bitRange>[8:8]</bitRange>
              <access>write-only</access>
            </field>
            <field>
              <name>BS9</name>
              <description>GPIOC9 output set</description>
              <bitRange>[9:9]</bitRange>
              <access>write-only</access>
            </field>
            <field>
              <name>BS10</name>
              <description>GPIOC10 output set</description>
              <bitRange>[10:10]</bitRange>
              <access>write-only</access>
            </field>
            <field>
              <name>BS11</name>
              <description>GPIOC11 output set</description>
              <bitRange>[11:11]</bitRange>
              <access>write-only</access>
            </field>
            <field>
              <name>BS12</name>
              <description>GPIOC12 output set</description>
              <bitRange>[12:12]</bitRange>
              <access>write-only</access>
            </field>
            <field>
              <name>BS13</name>
              <description>GPIOC13 output set</description>
              <bitRange>[13:13]</bitRange>
              <access>write-only</access>
            </field>
            <field>
              <name>BS14</name>
              <description>GPIOC14 output set</description>
              <bitRange>[14:14]</bitRange>
              <access>write-only</access>
            </field>
            <field>
              <name>BS15</name>
              <description>GPIOC15 output set</description>
              <bitRange>[15:15]</bitRange>
              <access>write-only</access>
            </field>
            <field>
              <name>BR0</name>
              <description>GPIOC0 outut reset</description>
              <bitRange>[16:16]</bitRange>
              <access>write-only</access>
            </field>
            <field>
              <name>BR1</name>
              <description>GPIOC1 outut reset</description>
              <bitRange>[17:17]</bitRange>
              <access>write-only</access>
            </field>
            <field>
              <name>BR2</name>
              <description>GPIOC2 outut reset</description>
              <bitRange>[18:18]</bitRange>
              <access>write-only</access>
            </field>
            <field>
              <name>BR3</name>
              <description>GPIOC3 outut reset</description>
              <bitRange>[19:19]</bitRange>
              <access>write-only</access>
            </field>
            <field>
              <name>BR4</name>
              <description>GPIOC4 outut reset</description>
              <bitRange>[20:20]</bitRange>
              <access>write-only</access>
            </field>
            <field>
              <name>BR5</name>
              <description>GPIOC5 outut reset</description>
              <bitRange>[21:21]</bitRange>
              <access>write-only</access>
            </field>
            <field>
              <name>BR6</name>
              <description>GPIOC6 outut reset</description>
              <bitRange>[22:22]</bitRange>
              <access>write-only</access>
            </field>
            <field>
              <name>BR7</name>
              <description>GPIOC7 outut reset</description>
              <bitRange>[23:23]</bitRange>
              <access>write-only</access>
            </field>
            <field>
              <name>BR8</name>
              <description>GPIOC8 outut reset</description>
              <bitRange>[24:24]</bitRange>
              <access>write-only</access>
            </field>
            <field>
              <name>BR9</name>
              <description>GPIOC9 outut reset</description>
              <bitRange>[25:25]</bitRange>
              <access>write-only</access>
            </field>
            <field>
              <name>BR10</name>
              <description>GPIOC10 outut reset</description>
              <bitRange>[26:26]</bitRange>
              <access>write-only</access>
            </field>
            <field>
              <name>BR11</name>
              <description>GPIOC11 outut reset</description>
              <bitRange>[27:27]</bitRange>
              <access>write-only</access>
            </field>
            <field>
              <name>BR12</name>
              <description>GPIOC12 outut reset</description>
              <bitRange>[28:28]</bitRange>
              <access>write-only</access>
            </field>
            <field>
              <name>BR13</name>
              <description>GPIOC13 outut reset</description>
              <bitRange>[29:29]</bitRange>
              <access>write-only</access>
            </field>
            <field>
              <name>BR14</name>
              <description>GPIOC14 outut reset</description>
              <bitRange>[30:30]</bitRange>
              <access>write-only</access>
            </field>
            <field>
              <name>BR15</name>
              <description>GPIOC15 outut reset</description>
              <bitRange>[31:31]</bitRange>
              <access>write-only</access>
            </field>
          </fields>
        </register>
        <register>
          <name>LCKR</name>
          <addressOffset>0x1C</addressOffset>
          <fields>
            <field>
              <name>LCK0</name>
              <description>GPIOC lock(bit0)</description>
              <bitRange>[0:0]</bitRange>
            </field>
            <field>
              <name>LCK1</name>
              <description>GPIOC lock(bit1)</description>
              <bitRange>[1:1]</bitRange>
            </field>
            <field>
              <name>LCK2</name>
              <description>GPIOC lock(bit2)</description>
              <bitRange>[2:2]</bitRange>
            </field>
            <field>
              <name>LCK3</name>
              <description>GPIOC lock(bit3)</description>
              <bitRange>[3:3]</bitRange>
            </field>
            <field>
              <name>LCK4</name>
              <description>GPIOC lock(bit4)</description>
              <bitRange>[4:4]</bitRange>
            </field>
            <field>
              <name>LCK5</name>
              <description>GPIOC lock(bit5)</description>
              <bitRange>[5:5]</bitRange>
            </field>
            <field>
              <name>LCK6</name>
              <description>GPIOC lock(bit6)</description>
              <bitRange>[6:6]</bitRange>
            </field>
            <field>
              <name>LCK7</name>
              <description>GPIOC lock(bit7)</description>
              <bitRange>[7:7]</bitRange>
            </field>
            <field>
              <name>LCK8</name>
              <description>GPIOC lock(bit8)</description>
              <bitRange>[8:8]</bitRange>
            </field>
            <field>
              <name>LCK9</name>
              <description>GPIOC lock(bit9)</description>
              <bitRange>[9:9]</bitRange>
            </field>
            <field>
              <name>LCK10</name>
              <description>GPIOC lock(bit10)</description>
              <bitRange>[10:10]</bitRange>
            </field>
            <field>
              <name>LCK11</name>
              <description>GPIOC lock(bit11)</description>
              <bitRange>[11:11]</bitRange>
            </field>
            <field>
              <name>LCK12</name>
              <description>GPIOC lock(bit12)</description>
              <bitRange>[12:12]</bitRange>
            </field>
            <field>
              <name>LCK13</name>
              <description>GPIOC lock(bit13)</description>
              <bitRange>[13:13]</bitRange>
            </field>
            <field>
              <name>LCK14</name>
              <description>GPIOC lock(bit14)</description>
              <bitRange>[14:14]</bitRange>
            </field>
            <field>
              <name>LCK15</name>
              <description>GPIOC lock(bit15)</description>
              <bitRange>[15:15]</bitRange>
            </field>
            <field>
              <name>LCKK</name>
              <description>GPIOC lock key</description>
              <bitRange>[16:16]</bitRange>
            </field>
          </fields>
        </register>
        <register>
          <name>AFRL</name>
          <addressOffset>0x20</addressOffset>
          <fields>
            <field>
              <name>AFSEL0</name>
              <description>GPIOC0 AF select</description>
              <bitRange>[3:0]</bitRange>
              <enumeratedValues>
                <enumeratedValue>
                  <name>0</name>
                  <value>1</value>
                </enumeratedValue>
                <enumeratedValue>
                  <name>1</name>
                  <value>2</value>
                </enumeratedValue>
                <enumeratedValue>
                  <name>2</name>
                  <value>4</value>
                </enumeratedValue>
                <enumeratedValue>
                  <name>3</name>
                  <value>8</value>
                </enumeratedValue>
              </enumeratedValues>
            </field>
            <field>
              <name>AFSEL1</name>
              <description>GPIOC1 AF select</description>
              <bitRange>[7:4]</bitRange>
              <enumeratedValues>
                <enumeratedValue>
                  <name>0</name>
                  <value>1</value>
                </enumeratedValue>
                <enumeratedValue>
                  <name>1</name>
                  <value>2</value>
                </enumeratedValue>
                <enumeratedValue>
                  <name>2</name>
                  <value>4</value>
                </enumeratedValue>
                <enumeratedValue>
                  <name>3</name>
                  <value>8</value>
                </enumeratedValue>
              </enumeratedValues>
            </field>
            <field>
              <name>AFSEL2</name>
              <description>GPIOC2 AF select</description>
              <bitRange>[11:8]</bitRange>
              <enumeratedValues>
                <enumeratedValue>
                  <name>0</name>
                  <value>1</value>
                </enumeratedValue>
                <enumeratedValue>
                  <name>1</name>
                  <value>2</value>
                </enumeratedValue>
                <enumeratedValue>
                  <name>2</name>
                  <value>4</value>
                </enumeratedValue>
                <enumeratedValue>
                  <name>3</name>
                  <value>8</value>
                </enumeratedValue>
              </enumeratedValues>
            </field>
            <field>
              <name>AFSEL3</name>
              <description>GPIOC3 AF select</description>
              <bitRange>[15:12]</bitRange>
              <enumeratedValues>
                <enumeratedValue>
                  <name>0</name>
                  <value>1</value>
                </enumeratedValue>
                <enumeratedValue>
                  <name>1</name>
                  <value>2</value>
                </enumeratedValue>
                <enumeratedValue>
                  <name>2</name>
                  <value>4</value>
                </enumeratedValue>
                <enumeratedValue>
                  <name>3</name>
                  <value>8</value>
                </enumeratedValue>
              </enumeratedValues>
            </field>
            <field>
              <name>AFSEL4</name>
              <description>GPIOC4 AF select</description>
              <bitRange>[19:16]</bitRange>
              <enumeratedValues>
                <enumeratedValue>
                  <name>0</name>
                  <value>1</value>
                </enumeratedValue>
                <enumeratedValue>
                  <name>1</name>
                  <value>2</value>
                </enumeratedValue>
                <enumeratedValue>
                  <name>2</name>
                  <value>4</value>
                </enumeratedValue>
                <enumeratedValue>
                  <name>3</name>
                  <value>8</value>
                </enumeratedValue>
              </enumeratedValues>
            </field>
            <field>
              <name>AFSEL5</name>
              <description>GPIOC5 AF select</description>
              <bitRange>[23:20]</bitRange>
              <enumeratedValues>
                <enumeratedValue>
                  <name>0</name>
                  <value>1</value>
                </enumeratedValue>
                <enumeratedValue>
                  <name>1</name>
                  <value>2</value>
                </enumeratedValue>
                <enumeratedValue>
                  <name>2</name>
                  <value>4</value>
                </enumeratedValue>
                <enumeratedValue>
                  <name>3</name>
                  <value>8</value>
                </enumeratedValue>
              </enumeratedValues>
            </field>
            <field>
              <name>AFSEL6</name>
              <description>GPIOC6 AF select</description>
              <bitRange>[27:24]</bitRange>
              <enumeratedValues>
                <enumeratedValue>
                  <name>0</name>
                  <value>1</value>
                </enumeratedValue>
                <enumeratedValue>
                  <name>1</name>
                  <value>2</value>
                </enumeratedValue>
                <enumeratedValue>
                  <name>2</name>
                  <value>4</value>
                </enumeratedValue>
                <enumeratedValue>
                  <name>3</name>
                  <value>8</value>
                </enumeratedValue>
              </enumeratedValues>
            </field>
            <field>
              <name>AFSEL7</name>
              <description>GPIOC7 AF select</description>
              <bitRange>[31:28]</bitRange>
              <enumeratedValues>
                <enumeratedValue>
                  <name>0</name>
                  <value>1</value>
                </enumeratedValue>
                <enumeratedValue>
                  <name>1</name>
                  <value>2</value>
                </enumeratedValue>
                <enumeratedValue>
                  <name>2</name>
                  <value>4</value>
                </enumeratedValue>
                <enumeratedValue>
                  <name>3</name>
                  <value>8</value>
                </enumeratedValue>
              </enumeratedValues>
            </field>
          </fields>
        </register>
        <register>
          <name>AFRH</name>
          <addressOffset>0x24</addressOffset>
          <fields>
            <field>
              <name>AFSEL8</name>
              <description>GPIOC8 AF select</description>
              <bitRange>[3:0]</bitRange>
              <enumeratedValues>
                <enumeratedValue>
                  <name>0</name>
                  <value>1</value>
                </enumeratedValue>
                <enumeratedValue>
                  <name>1</name>
                  <value>2</value>
                </enumeratedValue>
                <enumeratedValue>
                  <name>2</name>
                  <value>4</value>
                </enumeratedValue>
                <enumeratedValue>
                  <name>3</name>
                  <value>8</value>
                </enumeratedValue>
              </enumeratedValues>
            </field>
            <field>
              <name>AFSEL9</name>
              <description>GPIOC9 AF select</description>
              <bitRange>[7:4]</bitRange>
              <enumeratedValues>
                <enumeratedValue>
                  <name>0</name>
                  <value>1</value>
                </enumeratedValue>
                <enumeratedValue>
                  <name>1</name>
                  <value>2</value>
                </enumeratedValue>
                <enumeratedValue>
                  <name>2</name>
                  <value>4</value>
                </enumeratedValue>
                <enumeratedValue>
                  <name>3</name>
                  <value>8</value>
                </enumeratedValue>
              </enumeratedValues>
            </field>
            <field>
              <name>AFSEL10</name>
              <description>GPIOC10 AF select</description>
              <bitRange>[11:8]</bitRange>
              <enumeratedValues>
                <enumeratedValue>
                  <name>0</name>
                  <value>1</value>
                </enumeratedValue>
                <enumeratedValue>
                  <name>1</name>
                  <value>2</value>
                </enumeratedValue>
                <enumeratedValue>
                  <name>2</name>
                  <value>4</value>
                </enumeratedValue>
                <enumeratedValue>
                  <name>3</name>
                  <value>8</value>
                </enumeratedValue>
              </enumeratedValues>
            </field>
            <field>
              <name>AFSEL11</name>
              <description>GPIOC11 AF select</description>
              <bitRange>[15:12]</bitRange>
              <enumeratedValues>
                <enumeratedValue>
                  <name>0</name>
                  <value>1</value>
                </enumeratedValue>
                <enumeratedValue>
                  <name>1</name>
                  <value>2</value>
                </enumeratedValue>
                <enumeratedValue>
                  <name>2</name>
                  <value>4</value>
                </enumeratedValue>
                <enumeratedValue>
                  <name>3</name>
                  <value>8</value>
                </enumeratedValue>
              </enumeratedValues>
            </field>
            <field>
              <name>AFSEL12</name>
              <description>GPIOC12 AF select</description>
              <bitRange>[19:16]</bitRange>
              <enumeratedValues>
                <enumeratedValue>
                  <name>0</name>
                  <value>1</value>
                </enumeratedValue>
                <enumeratedValue>
                  <name>1</name>
                  <value>2</value>
                </enumeratedValue>
                <enumeratedValue>
                  <name>2</name>
                  <value>4</value>
                </enumeratedValue>
                <enumeratedValue>
                  <name>3</name>
                  <value>8</value>
                </enumeratedValue>
              </enumeratedValues>
            </field>
            <field>
              <name>AFSEL13</name>
              <description>GPIOC13 AF select</description>
              <bitRange>[23:20]</bitRange>
              <enumeratedValues>
                <enumeratedValue>
                  <name>0</name>
                  <value>1</value>
                </enumeratedValue>
                <enumeratedValue>
                  <name>1</name>
                  <value>2</value>
                </enumeratedValue>
                <enumeratedValue>
                  <name>2</name>
                  <value>4</value>
                </enumeratedValue>
                <enumeratedValue>
                  <name>3</name>
                  <value>8</value>
                </enumeratedValue>
              </enumeratedValues>
            </field>
            <field>
              <name>AFSEL14</name>
              <description>GPIOC14 AF select</description>
              <bitRange>[27:24]</bitRange>
              <enumeratedValues>
                <enumeratedValue>
                  <name>0</name>
                  <value>1</value>
                </enumeratedValue>
                <enumeratedValue>
                  <name>1</name>
                  <value>2</value>
                </enumeratedValue>
                <enumeratedValue>
                  <name>2</name>
                  <value>4</value>
                </enumeratedValue>
                <enumeratedValue>
                  <name>3</name>
                  <value>8</value>
                </enumeratedValue>
              </enumeratedValues>
            </field>
            <field>
              <name>AFSEL15</name>
              <description>GPIOC15 AF select</description>
              <bitRange>[31:28]</bitRange>
              <enumeratedValues>
                <enumeratedValue>
                  <name>0</name>
                  <value>1</value>
                </enumeratedValue>
                <enumeratedValue>
                  <name>1</name>
                  <value>2</value>
                </enumeratedValue>
                <enumeratedValue>
                  <name>2</name>
                  <value>4</value>
                </enumeratedValue>
                <enumeratedValue>
                  <name>3</name>
                  <value>8</value>
                </enumeratedValue>
              </enumeratedValues>
            </field>
          </fields>
        </register>
        <register>
          <name>BRR</name>
          <addressOffset>0x28</addressOffset>
          <fields>
            <field>
              <name>BR0</name>
              <description>GPIOC 0 output pin reset</description>
              <bitRange>[0:0]</bitRange>
              <access>write-only</access>
            </field>
            <field>
              <name>BR1</name>
              <description>GPIOC 1 output pin reset</description>
              <bitRange>[1:1]</bitRange>
              <access>write-only</access>
            </field>
            <field>
              <name>BR2</name>
              <description>GPIOC 2 output pin reset</description>
              <bitRange>[2:2]</bitRange>
              <access>write-only</access>
            </field>
            <field>
              <name>BR3</name>
              <description>GPIOC 3 output pin reset</description>
              <bitRange>[3:3]</bitRange>
              <access>write-only</access>
            </field>
            <field>
              <name>BR4</name>
              <description>GPIOC 4 output pin reset</description>
              <bitRange>[4:4]</bitRange>
              <access>write-only</access>
            </field>
            <field>
              <name>BR5</name>
              <description>GPIOC 5 output pin reset</description>
              <bitRange>[5:5]</bitRange>
              <access>write-only</access>
            </field>
            <field>
              <name>BR6</name>
              <description>GPIOC 6 output pin reset</description>
              <bitRange>[6:6]</bitRange>
              <access>write-only</access>
            </field>
            <field>
              <name>BR7</name>
              <description>GPIOC 7 output pin reset</description>
              <bitRange>[7:7]</bitRange>
              <access>write-only</access>
            </field>
            <field>
              <name>BR8</name>
              <description>GPIOC 8 output pin reset</description>
              <bitRange>[8:8]</bitRange>
              <access>write-only</access>
            </field>
            <field>
              <name>BR9</name>
              <description>GPIOC 9 output pin reset</description>
              <bitRange>[9:9]</bitRange>
              <access>write-only</access>
            </field>
            <field>
              <name>BR10</name>
              <description>GPIOC 10 output pin reset</description>
              <bitRange>[10:10]</bitRange>
              <access>write-only</access>
            </field>
            <field>
              <name>BR11</name>
              <description>GPIOC 11 output pin reset</description>
              <bitRange>[11:11]</bitRange>
              <access>write-only</access>
            </field>
            <field>
              <name>BR12</name>
              <description>GPIOC 12 output pin reset</description>
              <bitRange>[12:12]</bitRange>
              <access>write-only</access>
            </field>
            <field>
              <name>BR13</name>
              <description>GPIOC 13 output pin reset</description>
              <bitRange>[13:13]</bitRange>
              <access>write-only</access>
            </field>
            <field>
              <name>BR14</name>
              <description>GPIOC 14 output pin reset</description>
              <bitRange>[14:14]</bitRange>
              <access>write-only</access>
            </field>
            <field>
              <name>BR15</name>
              <description>GPIOC 15 output pin reset</description>
              <bitRange>[15:15]</bitRange>
              <access>write-only</access>
            </field>
          </fields>
        </register>
      </registers>
    </peripheral>
    <peripheral>
      <name>GPIOD</name>
      <groupName>GPIO</groupName>
      <baseAddress>0x50000C00</baseAddress>
      <addressBlock>
        <offset>0x0</offset>
        <size>0x30</size>
        <usage>registers</usage>
      </addressBlock>
      <registers>
        <register>
          <name>MODER</name>
          <addressOffset>0x0</addressOffset>
          <fields>
            <field>
              <name>MODER0</name>
              <description>GPIOD0 MODE</description>
              <bitRange>[1:0]</bitRange>
            </field>
            <field>
              <name>MODER1</name>
              <description>GPIOD1 MODE</description>
              <bitRange>[3:2]</bitRange>
            </field>
            <field>
              <name>MODER2</name>
              <description>GPIOD2 MODE</description>
              <bitRange>[5:4]</bitRange>
            </field>
            <field>
              <name>MODER3</name>
              <description>GPIOD3 MODE</description>
              <bitRange>[7:6]</bitRange>
            </field>
            <field>
              <name>MODER4</name>
              <description>GPIOD4 MODE</description>
              <bitRange>[9:8]</bitRange>
            </field>
            <field>
              <name>MODER5</name>
              <description>GPIOD5 MODE</description>
              <bitRange>[11:10]</bitRange>
            </field>
            <field>
              <name>MODER6</name>
              <description>GPIOD6 MODE</description>
              <bitRange>[13:12]</bitRange>
            </field>
            <field>
              <name>MODER7</name>
              <description>GPIOD7 MODE</description>
              <bitRange>[15:14]</bitRange>
            </field>
            <field>
              <name>MODER8</name>
              <description>GPIOD8 MODE</description>
              <bitRange>[17:16]</bitRange>
            </field>
            <field>
              <name>MODER9</name>
              <description>GPIOD9 MODE</description>
              <bitRange>[19:18]</bitRange>
            </field>
            <field>
              <name>MODER10</name>
              <description>GPIOD10 MODE</description>
              <bitRange>[21:20]</bitRange>
            </field>
            <field>
              <name>MODER11</name>
              <description>GPIOD11 MODE</description>
              <bitRange>[23:22]</bitRange>
            </field>
            <field>
              <name>MODER12</name>
              <description>GPIOD12 MODE</description>
              <bitRange>[25:24]</bitRange>
            </field>
            <field>
              <name>MODER13</name>
              <description>GPIOD13 MODE</description>
              <bitRange>[27:26]</bitRange>
            </field>
            <field>
              <name>MODER14</name>
              <description>GPIOD14 MODE</description>
              <bitRange>[29:28]</bitRange>
            </field>
            <field>
              <name>MODER15</name>
              <description>GPIOD15 MODE</description>
              <bitRange>[31:30]</bitRange>
            </field>
          </fields>
        </register>
        <register>
          <name>OTYPER</name>
          <addressOffset>0x4</addressOffset>
          <fields>
            <field>
              <name>OT0</name>
              <description>GPIOD0 Output type</description>
              <bitRange>[0:0]</bitRange>
            </field>
            <field>
              <name>OT1</name>
              <description>GPIOD1 Output type</description>
              <bitRange>[1:1]</bitRange>
            </field>
            <field>
              <name>OT2</name>
              <description>GPIOD2 Output type</description>
              <bitRange>[2:2]</bitRange>
            </field>
            <field>
              <name>OT3</name>
              <description>GPIOD3 Output type</description>
              <bitRange>[3:3]</bitRange>
            </field>
            <field>
              <name>OT4</name>
              <description>GPIOD4 Output type</description>
              <bitRange>[4:4]</bitRange>
            </field>
            <field>
              <name>OT5</name>
              <description>GPIOD5 Output type</description>
              <bitRange>[5:5]</bitRange>
            </field>
            <field>
              <name>OT6</name>
              <description>GPIOD6 Output type</description>
              <bitRange>[6:6]</bitRange>
            </field>
            <field>
              <name>OT7</name>
              <description>GPIOD7 Output type</description>
              <bitRange>[7:7]</bitRange>
            </field>
            <field>
              <name>OT8</name>
              <description>GPIOD8 Output type</description>
              <bitRange>[8:8]</bitRange>
            </field>
            <field>
              <name>OT9</name>
              <description>GPIOD9 Output type</description>
              <bitRange>[9:9]</bitRange>
            </field>
            <field>
              <name>OT10</name>
              <description>GPIOD10 Output type</description>
              <bitRange>[10:10]</bitRange>
            </field>
            <field>
              <name>OT11</name>
              <description>GPIOD11 Output type</description>
              <bitRange>[11:11]</bitRange>
            </field>
            <field>
              <name>OT12</name>
              <description>GPIOD12 Output type</description>
              <bitRange>[12:12]</bitRange>
            </field>
            <field>
              <name>OT13</name>
              <description>GPIOD13 Output type</description>
              <bitRange>[13:13]</bitRange>
            </field>
            <field>
              <name>OT14</name>
              <description>GPIOD14 Output type</description>
              <bitRange>[14:14]</bitRange>
            </field>
            <field>
              <name>OT15</name>
              <description>GPIOD15 Output type</description>
              <bitRange>[15:15]</bitRange>
            </field>
          </fields>
        </register>
        <register>
          <name>OSPDDER</name>
          <addressOffset>0x8</addressOffset>
          <fields>
            <field>
              <name>OSPEED0</name>
              <description>GPIOD0 output speed</description>
              <bitRange>[1:0]</bitRange>
            </field>
            <field>
              <name>OSPEED1</name>
              <description>GPIOD1 output speed</description>
              <bitRange>[3:2]</bitRange>
            </field>
            <field>
              <name>OSPEED2</name>
              <description>GPIOD2 output speed</description>
              <bitRange>[5:4]</bitRange>
            </field>
            <field>
              <name>OSPEED3</name>
              <description>GPIOD3 output speed</description>
              <bitRange>[7:6]</bitRange>
            </field>
            <field>
              <name>OSPEED4</name>
              <description>GPIOD4 output speed</description>
              <bitRange>[9:8]</bitRange>
            </field>
            <field>
              <name>OSPEED5</name>
              <description>GPIOD5 output speed</description>
              <bitRange>[11:10]</bitRange>
            </field>
            <field>
              <name>OSPEED6</name>
              <description>GPIOD6 output speed</description>
              <bitRange>[13:12]</bitRange>
            </field>
            <field>
              <name>OSPEED7</name>
              <description>GPIOD7 output speed</description>
              <bitRange>[15:14]</bitRange>
            </field>
            <field>
              <name>OSPEED8</name>
              <description>GPIOD8 output speed</description>
              <bitRange>[17:16]</bitRange>
            </field>
            <field>
              <name>OSPEED9</name>
              <description>GPIOD9 output speed</description>
              <bitRange>[19:18]</bitRange>
            </field>
            <field>
              <name>OSPEED10</name>
              <description>GPIOD10 output speed</description>
              <bitRange>[21:20]</bitRange>
            </field>
            <field>
              <name>OSPEED11</name>
              <description>GPIOD11 output speed</description>
              <bitRange>[23:22]</bitRange>
            </field>
            <field>
              <name>OSPEED12</name>
              <description>GPIOD12 output speed</description>
              <bitRange>[25:24]</bitRange>
            </field>
            <field>
              <name>OSPEED13</name>
              <description>GPIOD13 output speed</description>
              <bitRange>[27:26]</bitRange>
            </field>
            <field>
              <name>OSPEED14</name>
              <description>GPIOD14 output speed</description>
              <bitRange>[29:28]</bitRange>
            </field>
            <field>
              <name>OSPEED15</name>
              <description>GPIOD15 output speed</description>
              <bitRange>[31:30]</bitRange>
            </field>
          </fields>
        </register>
        <register>
          <name>PUPDR</name>
          <addressOffset>0xC</addressOffset>
          <fields>
            <field>
              <name>PUPD0</name>
              <description>GPIOD0 pull up/pull down</description>
              <bitRange>[1:0]</bitRange>
              <enumeratedValues>
                <enumeratedValue>
                  <name>0</name>
                  <value>1</value>
                </enumeratedValue>
                <enumeratedValue>
                  <name>1</name>
                  <value>2</value>
                </enumeratedValue>
              </enumeratedValues>
            </field>
            <field>
              <name>PUPD1</name>
              <description>GPIOD1 pull up/pull down</description>
              <bitRange>[3:2]</bitRange>
              <enumeratedValues>
                <enumeratedValue>
                  <name>0</name>
                  <value>1</value>
                </enumeratedValue>
                <enumeratedValue>
                  <name>1</name>
                  <value>2</value>
                </enumeratedValue>
              </enumeratedValues>
            </field>
            <field>
              <name>PUPD2</name>
              <description>GPIOD2 pull up/pull down</description>
              <bitRange>[5:4]</bitRange>
              <enumeratedValues>
                <enumeratedValue>
                  <name>0</name>
                  <value>1</value>
                </enumeratedValue>
                <enumeratedValue>
                  <name>1</name>
                  <value>2</value>
                </enumeratedValue>
              </enumeratedValues>
            </field>
            <field>
              <name>PUPD3</name>
              <description>GPIOD3 pull up/pull down</description>
              <bitRange>[7:6]</bitRange>
              <enumeratedValues>
                <enumeratedValue>
                  <name>0</name>
                  <value>1</value>
                </enumeratedValue>
                <enumeratedValue>
                  <name>1</name>
                  <value>2</value>
                </enumeratedValue>
              </enumeratedValues>
            </field>
            <field>
              <name>PUPD4</name>
              <description>GPIOD4 pull up/pull down</description>
              <bitRange>[9:8]</bitRange>
              <enumeratedValues>
                <enumeratedValue>
                  <name>0</name>
                  <value>1</value>
                </enumeratedValue>
                <enumeratedValue>
                  <name>1</name>
                  <value>2</value>
                </enumeratedValue>
              </enumeratedValues>
            </field>
            <field>
              <name>PUPD5</name>
              <description>GPIOD5 pull up/pull down</description>
              <bitRange>[11:10]</bitRange>
              <enumeratedValues>
                <enumeratedValue>
                  <name>0</name>
                  <value>1</value>
                </enumeratedValue>
                <enumeratedValue>
                  <name>1</name>
                  <value>2</value>
                </enumeratedValue>
              </enumeratedValues>
            </field>
            <field>
              <name>PUPD6</name>
              <description>GPIOD6 pull up/pull down</description>
              <bitRange>[13:12]</bitRange>
              <enumeratedValues>
                <enumeratedValue>
                  <name>0</name>
                  <value>1</value>
                </enumeratedValue>
                <enumeratedValue>
                  <name>1</name>
                  <value>2</value>
                </enumeratedValue>
              </enumeratedValues>
            </field>
            <field>
              <name>PUPD7</name>
              <description>GPIOD7 pull up/pull down</description>
              <bitRange>[15:14]</bitRange>
              <enumeratedValues>
                <enumeratedValue>
                  <name>0</name>
                  <value>1</value>
                </enumeratedValue>
                <enumeratedValue>
                  <name>1</name>
                  <value>2</value>
                </enumeratedValue>
              </enumeratedValues>
            </field>
            <field>
              <name>PUPD8</name>
              <description>GPIOD8 pull up/pull down</description>
              <bitRange>[17:16]</bitRange>
              <enumeratedValues>
                <enumeratedValue>
                  <name>0</name>
                  <value>1</value>
                </enumeratedValue>
                <enumeratedValue>
                  <name>1</name>
                  <value>2</value>
                </enumeratedValue>
              </enumeratedValues>
            </field>
            <field>
              <name>PUPD9</name>
              <description>GPIOD9 pull up/pull down</description>
              <bitRange>[19:18]</bitRange>
              <enumeratedValues>
                <enumeratedValue>
                  <name>0</name>
                  <value>1</value>
                </enumeratedValue>
                <enumeratedValue>
                  <name>1</name>
                  <value>2</value>
                </enumeratedValue>
              </enumeratedValues>
            </field>
            <field>
              <name>PUPD10</name>
              <description>GPIOD10 pull up/pull down</description>
              <bitRange>[21:20]</bitRange>
              <enumeratedValues>
                <enumeratedValue>
                  <name>0</name>
                  <value>1</value>
                </enumeratedValue>
                <enumeratedValue>
                  <name>1</name>
                  <value>2</value>
                </enumeratedValue>
              </enumeratedValues>
            </field>
            <field>
              <name>PUPD11</name>
              <description>GPIOD11 pull up/pull down</description>
              <bitRange>[23:22]</bitRange>
              <enumeratedValues>
                <enumeratedValue>
                  <name>0</name>
                  <value>1</value>
                </enumeratedValue>
                <enumeratedValue>
                  <name>1</name>
                  <value>2</value>
                </enumeratedValue>
              </enumeratedValues>
            </field>
            <field>
              <name>PUPD12</name>
              <description>GPIOD12 pull up/pull down</description>
              <bitRange>[25:24]</bitRange>
              <enumeratedValues>
                <enumeratedValue>
                  <name>0</name>
                  <value>1</value>
                </enumeratedValue>
                <enumeratedValue>
                  <name>1</name>
                  <value>2</value>
                </enumeratedValue>
              </enumeratedValues>
            </field>
            <field>
              <name>PUPD13</name>
              <description>GPIOD13 pull up/pull down</description>
              <bitRange>[27:26]</bitRange>
              <enumeratedValues>
                <enumeratedValue>
                  <name>0</name>
                  <value>1</value>
                </enumeratedValue>
                <enumeratedValue>
                  <name>1</name>
                  <value>2</value>
                </enumeratedValue>
              </enumeratedValues>
            </field>
            <field>
              <name>PUPD14</name>
              <description>GPIOD14 pull up/pull down</description>
              <bitRange>[29:28]</bitRange>
              <enumeratedValues>
                <enumeratedValue>
                  <name>0</name>
                  <value>1</value>
                </enumeratedValue>
                <enumeratedValue>
                  <name>1</name>
                  <value>2</value>
                </enumeratedValue>
              </enumeratedValues>
            </field>
            <field>
              <name>PUPD15</name>
              <description>GPIOD15 pull up/pull down</description>
              <bitRange>[31:30]</bitRange>
              <enumeratedValues>
                <enumeratedValue>
                  <name>0</name>
                  <value>1</value>
                </enumeratedValue>
                <enumeratedValue>
                  <name>1</name>
                  <value>2</value>
                </enumeratedValue>
              </enumeratedValues>
            </field>
          </fields>
        </register>
        <register>
          <name>IDR</name>
          <addressOffset>0x10</addressOffset>
          <fields>
            <field>
              <name>ID0</name>
              <description>GPIOD0 input data</description>
              <bitRange>[0:0]</bitRange>
              <access>read-only</access>
            </field>
            <field>
              <name>ID1</name>
              <description>GPIOD1 input data</description>
              <bitRange>[1:1]</bitRange>
              <access>read-only</access>
            </field>
            <field>
              <name>ID2</name>
              <description>GPIOD2 input data</description>
              <bitRange>[2:2]</bitRange>
              <access>read-only</access>
            </field>
            <field>
              <name>ID3</name>
              <description>GPIOD3 input data</description>
              <bitRange>[3:3]</bitRange>
              <access>read-only</access>
            </field>
            <field>
              <name>ID4</name>
              <description>GPIOD4 input data</description>
              <bitRange>[4:4]</bitRange>
              <access>read-only</access>
            </field>
            <field>
              <name>ID5</name>
              <description>GPIOD5 input data</description>
              <bitRange>[5:5]</bitRange>
              <access>read-only</access>
            </field>
            <field>
              <name>ID6</name>
              <description>GPIOD6 input data</description>
              <bitRange>[6:6]</bitRange>
              <access>read-only</access>
            </field>
            <field>
              <name>ID7</name>
              <description>GPIOD7 input data</description>
              <bitRange>[7:7]</bitRange>
              <access>read-only</access>
            </field>
            <field>
              <name>ID8</name>
              <description>GPIOD8 input data</description>
              <bitRange>[8:8]</bitRange>
              <access>read-only</access>
            </field>
            <field>
              <name>ID9</name>
              <description>GPIOD9 input data</description>
              <bitRange>[9:9]</bitRange>
              <access>read-only</access>
            </field>
            <field>
              <name>ID10</name>
              <description>GPIOD10 input data</description>
              <bitRange>[10:10]</bitRange>
              <access>read-only</access>
            </field>
            <field>
              <name>ID11</name>
              <description>GPIOD11 input data</description>
              <bitRange>[11:11]</bitRange>
              <access>read-only</access>
            </field>
            <field>
              <name>ID12</name>
              <description>GPIOD12 input data</description>
              <bitRange>[12:12]</bitRange>
              <access>read-only</access>
            </field>
            <field>
              <name>ID13</name>
              <description>GPIOD13 input data</description>
              <bitRange>[13:13]</bitRange>
              <access>read-only</access>
            </field>
            <field>
              <name>ID14</name>
              <description>GPIOD14 input data</description>
              <bitRange>[14:14]</bitRange>
              <access>read-only</access>
            </field>
            <field>
              <name>ID15</name>
              <description>GPIOD15 input data</description>
              <bitRange>[15:15]</bitRange>
              <access>read-only</access>
            </field>
          </fields>
        </register>
        <register>
          <name>ODR</name>
          <addressOffset>0x14</addressOffset>
          <fields>
            <field>
              <name>OD0</name>
              <description>GPIOD0 output data</description>
              <bitRange>[0:0]</bitRange>
            </field>
            <field>
              <name>OD1</name>
              <description>GPIOD1 output data</description>
              <bitRange>[1:1]</bitRange>
            </field>
            <field>
              <name>OD2</name>
              <description>GPIOD2 output data</description>
              <bitRange>[2:2]</bitRange>
            </field>
            <field>
              <name>OD3</name>
              <description>GPIOD3 output data</description>
              <bitRange>[3:3]</bitRange>
            </field>
            <field>
              <name>OD4</name>
              <description>GPIOD4 output data</description>
              <bitRange>[4:4]</bitRange>
            </field>
            <field>
              <name>OD5</name>
              <description>GPIOD5 output data</description>
              <bitRange>[5:5]</bitRange>
            </field>
            <field>
              <name>OD6</name>
              <description>GPIOD6 output data</description>
              <bitRange>[6:6]</bitRange>
            </field>
            <field>
              <name>OD7</name>
              <description>GPIOD7 output data</description>
              <bitRange>[7:7]</bitRange>
            </field>
            <field>
              <name>OD8</name>
              <description>GPIOD8 output data</description>
              <bitRange>[8:8]</bitRange>
            </field>
            <field>
              <name>OD9</name>
              <description>GPIOD9 output data</description>
              <bitRange>[9:9]</bitRange>
            </field>
            <field>
              <name>OD10</name>
              <description>GPIOD10 output data</description>
              <bitRange>[10:10]</bitRange>
            </field>
            <field>
              <name>OD11</name>
              <description>GPIOD11 output data</description>
              <bitRange>[11:11]</bitRange>
            </field>
            <field>
              <name>OD12</name>
              <description>GPIOD12 output data</description>
              <bitRange>[12:12]</bitRange>
            </field>
            <field>
              <name>OD13</name>
              <description>GPIOD13 output data</description>
              <bitRange>[13:13]</bitRange>
            </field>
            <field>
              <name>OD14</name>
              <description>GPIOD14 output data</description>
              <bitRange>[14:14]</bitRange>
            </field>
            <field>
              <name>OD15</name>
              <description>GPIOD15 output data</description>
              <bitRange>[15:15]</bitRange>
            </field>
          </fields>
        </register>
        <register>
          <name>BSRR</name>
          <addressOffset>0x18</addressOffset>
          <fields>
            <field>
              <name>BS0</name>
              <description>GPIOD0 output set</description>
              <bitRange>[0:0]</bitRange>
              <access>write-only</access>
            </field>
            <field>
              <name>BS1</name>
              <description>GPIOD1 output set</description>
              <bitRange>[1:1]</bitRange>
              <access>write-only</access>
            </field>
            <field>
              <name>BS2</name>
              <description>GPIOD2 output set</description>
              <bitRange>[2:2]</bitRange>
              <access>write-only</access>
            </field>
            <field>
              <name>BS3</name>
              <description>GPIOD3 output set</description>
              <bitRange>[3:3]</bitRange>
              <access>write-only</access>
            </field>
            <field>
              <name>BS4</name>
              <description>GPIOD4 output set</description>
              <bitRange>[4:4]</bitRange>
              <access>write-only</access>
            </field>
            <field>
              <name>BS5</name>
              <description>GPIOD5 output set</description>
              <bitRange>[5:5]</bitRange>
              <access>write-only</access>
            </field>
            <field>
              <name>BS6</name>
              <description>GPIOD6 output set</description>
              <bitRange>[6:6]</bitRange>
              <access>write-only</access>
            </field>
            <field>
              <name>BS7</name>
              <description>GPIOD7 output set</description>
              <bitRange>[7:7]</bitRange>
              <access>write-only</access>
            </field>
            <field>
              <name>BS8</name>
              <description>GPIOD8 output set</description>
              <bitRange>[8:8]</bitRange>
              <access>write-only</access>
            </field>
            <field>
              <name>BS9</name>
              <description>GPIOD9 output set</description>
              <bitRange>[9:9]</bitRange>
              <access>write-only</access>
            </field>
            <field>
              <name>BS10</name>
              <description>GPIOD10 output set</description>
              <bitRange>[10:10]</bitRange>
              <access>write-only</access>
            </field>
            <field>
              <name>BS11</name>
              <description>GPIOD11 output set</description>
              <bitRange>[11:11]</bitRange>
              <access>write-only</access>
            </field>
            <field>
              <name>BS12</name>
              <description>GPIOD12 output set</description>
              <bitRange>[12:12]</bitRange>
              <access>write-only</access>
            </field>
            <field>
              <name>BS13</name>
              <description>GPIOD13 output set</description>
              <bitRange>[13:13]</bitRange>
              <access>write-only</access>
            </field>
            <field>
              <name>BS14</name>
              <description>GPIOD14 output set</description>
              <bitRange>[14:14]</bitRange>
              <access>write-only</access>
            </field>
            <field>
              <name>BS15</name>
              <description>GPIOD15 output set</description>
              <bitRange>[15:15]</bitRange>
              <access>write-only</access>
            </field>
            <field>
              <name>BR0</name>
              <description>GPIOD0 outut reset</description>
              <bitRange>[16:16]</bitRange>
              <access>write-only</access>
            </field>
            <field>
              <name>BR1</name>
              <description>GPIOD1 outut reset</description>
              <bitRange>[17:17]</bitRange>
              <access>write-only</access>
            </field>
            <field>
              <name>BR2</name>
              <description>GPIOD2 outut reset</description>
              <bitRange>[18:18]</bitRange>
              <access>write-only</access>
            </field>
            <field>
              <name>BR3</name>
              <description>GPIOD3 outut reset</description>
              <bitRange>[19:19]</bitRange>
              <access>write-only</access>
            </field>
            <field>
              <name>BR4</name>
              <description>GPIOD4 outut reset</description>
              <bitRange>[20:20]</bitRange>
              <access>write-only</access>
            </field>
            <field>
              <name>BR5</name>
              <description>GPIOD5 outut reset</description>
              <bitRange>[21:21]</bitRange>
              <access>write-only</access>
            </field>
            <field>
              <name>BR6</name>
              <description>GPIOD6 outut reset</description>
              <bitRange>[22:22]</bitRange>
              <access>write-only</access>
            </field>
            <field>
              <name>BR7</name>
              <description>GPIOD7 outut reset</description>
              <bitRange>[23:23]</bitRange>
              <access>write-only</access>
            </field>
            <field>
              <name>BR8</name>
              <description>GPIOD8 outut reset</description>
              <bitRange>[24:24]</bitRange>
              <access>write-only</access>
            </field>
            <field>
              <name>BR9</name>
              <description>GPIOD9 outut reset</description>
              <bitRange>[25:25]</bitRange>
              <access>write-only</access>
            </field>
            <field>
              <name>BR10</name>
              <description>GPIOD10 outut reset</description>
              <bitRange>[26:26]</bitRange>
              <access>write-only</access>
            </field>
            <field>
              <name>BR11</name>
              <description>GPIOD11 outut reset</description>
              <bitRange>[27:27]</bitRange>
              <access>write-only</access>
            </field>
            <field>
              <name>BR12</name>
              <description>GPIOD12 outut reset</description>
              <bitRange>[28:28]</bitRange>
              <access>write-only</access>
            </field>
            <field>
              <name>BR13</name>
              <description>GPIOD13 outut reset</description>
              <bitRange>[29:29]</bitRange>
              <access>write-only</access>
            </field>
            <field>
              <name>BR14</name>
              <description>GPIOD14 outut reset</description>
              <bitRange>[30:30]</bitRange>
              <access>write-only</access>
            </field>
            <field>
              <name>BR15</name>
              <description>GPIOD15 outut reset</description>
              <bitRange>[31:31]</bitRange>
              <access>write-only</access>
            </field>
          </fields>
        </register>
        <register>
          <name>LCKR</name>
          <addressOffset>0x1C</addressOffset>
          <fields>
            <field>
              <name>LCK0</name>
              <description>GPIOD lock(bit0)</description>
              <bitRange>[0:0]</bitRange>
            </field>
            <field>
              <name>LCK1</name>
              <description>GPIOD lock(bit1)</description>
              <bitRange>[1:1]</bitRange>
            </field>
            <field>
              <name>LCK2</name>
              <description>GPIOD lock(bit2)</description>
              <bitRange>[2:2]</bitRange>
            </field>
            <field>
              <name>LCK3</name>
              <description>GPIOD lock(bit3)</description>
              <bitRange>[3:3]</bitRange>
            </field>
            <field>
              <name>LCK4</name>
              <description>GPIOD lock(bit4)</description>
              <bitRange>[4:4]</bitRange>
            </field>
            <field>
              <name>LCK5</name>
              <description>GPIOD lock(bit5)</description>
              <bitRange>[5:5]</bitRange>
            </field>
            <field>
              <name>LCK6</name>
              <description>GPIOD lock(bit6)</description>
              <bitRange>[6:6]</bitRange>
            </field>
            <field>
              <name>LCK7</name>
              <description>GPIOD lock(bit7)</description>
              <bitRange>[7:7]</bitRange>
            </field>
            <field>
              <name>LCK8</name>
              <description>GPIOD lock(bit8)</description>
              <bitRange>[8:8]</bitRange>
            </field>
            <field>
              <name>LCK9</name>
              <description>GPIOD lock(bit9)</description>
              <bitRange>[9:9]</bitRange>
            </field>
            <field>
              <name>LCK10</name>
              <description>GPIOD lock(bit10)</description>
              <bitRange>[10:10]</bitRange>
            </field>
            <field>
              <name>LCK11</name>
              <description>GPIOD lock(bit11)</description>
              <bitRange>[11:11]</bitRange>
            </field>
            <field>
              <name>LCK12</name>
              <description>GPIOD lock(bit12)</description>
              <bitRange>[12:12]</bitRange>
            </field>
            <field>
              <name>LCK13</name>
              <description>GPIOD lock(bit13)</description>
              <bitRange>[13:13]</bitRange>
            </field>
            <field>
              <name>LCK14</name>
              <description>GPIOD lock(bit14)</description>
              <bitRange>[14:14]</bitRange>
            </field>
            <field>
              <name>LCK15</name>
              <description>GPIOD lock(bit15)</description>
              <bitRange>[15:15]</bitRange>
            </field>
            <field>
              <name>LCKK</name>
              <description>GPIOD lock key</description>
              <bitRange>[16:16]</bitRange>
            </field>
          </fields>
        </register>
        <register>
          <name>AFRL</name>
          <addressOffset>0x20</addressOffset>
          <fields>
            <field>
              <name>AFSEL0</name>
              <description>GPIOD0 AF select</description>
              <bitRange>[3:0]</bitRange>
              <enumeratedValues>
                <enumeratedValue>
                  <name>0</name>
                  <value>1</value>
                </enumeratedValue>
                <enumeratedValue>
                  <name>1</name>
                  <value>2</value>
                </enumeratedValue>
                <enumeratedValue>
                  <name>2</name>
                  <value>4</value>
                </enumeratedValue>
                <enumeratedValue>
                  <name>3</name>
                  <value>8</value>
                </enumeratedValue>
              </enumeratedValues>
            </field>
            <field>
              <name>AFSEL1</name>
              <description>GPIOD1 AF select</description>
              <bitRange>[7:4]</bitRange>
              <enumeratedValues>
                <enumeratedValue>
                  <name>0</name>
                  <value>1</value>
                </enumeratedValue>
                <enumeratedValue>
                  <name>1</name>
                  <value>2</value>
                </enumeratedValue>
                <enumeratedValue>
                  <name>2</name>
                  <value>4</value>
                </enumeratedValue>
                <enumeratedValue>
                  <name>3</name>
                  <value>8</value>
                </enumeratedValue>
              </enumeratedValues>
            </field>
            <field>
              <name>AFSEL2</name>
              <description>GPIOD2 AF select</description>
              <bitRange>[11:8]</bitRange>
              <enumeratedValues>
                <enumeratedValue>
                  <name>0</name>
                  <value>1</value>
                </enumeratedValue>
                <enumeratedValue>
                  <name>1</name>
                  <value>2</value>
                </enumeratedValue>
                <enumeratedValue>
                  <name>2</name>
                  <value>4</value>
                </enumeratedValue>
                <enumeratedValue>
                  <name>3</name>
                  <value>8</value>
                </enumeratedValue>
              </enumeratedValues>
            </field>
            <field>
              <name>AFSEL3</name>
              <description>GPIOD3 AF select</description>
              <bitRange>[15:12]</bitRange>
              <enumeratedValues>
                <enumeratedValue>
                  <name>0</name>
                  <value>1</value>
                </enumeratedValue>
                <enumeratedValue>
                  <name>1</name>
                  <value>2</value>
                </enumeratedValue>
                <enumeratedValue>
                  <name>2</name>
                  <value>4</value>
                </enumeratedValue>
                <enumeratedValue>
                  <name>3</name>
                  <value>8</value>
                </enumeratedValue>
              </enumeratedValues>
            </field>
            <field>
              <name>AFSEL4</name>
              <description>GPIOD4 AF select</description>
              <bitRange>[19:16]</bitRange>
              <enumeratedValues>
                <enumeratedValue>
                  <name>0</name>
                  <value>1</value>
                </enumeratedValue>
                <enumeratedValue>
                  <name>1</name>
                  <value>2</value>
                </enumeratedValue>
                <enumeratedValue>
                  <name>2</name>
                  <value>4</value>
                </enumeratedValue>
                <enumeratedValue>
                  <name>3</name>
                  <value>8</value>
                </enumeratedValue>
              </enumeratedValues>
            </field>
            <field>
              <name>AFSEL5</name>
              <description>GPIOD5 AF select</description>
              <bitRange>[23:20]</bitRange>
              <enumeratedValues>
                <enumeratedValue>
                  <name>0</name>
                  <value>1</value>
                </enumeratedValue>
                <enumeratedValue>
                  <name>1</name>
                  <value>2</value>
                </enumeratedValue>
                <enumeratedValue>
                  <name>2</name>
                  <value>4</value>
                </enumeratedValue>
                <enumeratedValue>
                  <name>3</name>
                  <value>8</value>
                </enumeratedValue>
              </enumeratedValues>
            </field>
            <field>
              <name>AFSEL6</name>
              <description>GPIOD6 AF select</description>
              <bitRange>[27:24]</bitRange>
              <enumeratedValues>
                <enumeratedValue>
                  <name>0</name>
                  <value>1</value>
                </enumeratedValue>
                <enumeratedValue>
                  <name>1</name>
                  <value>2</value>
                </enumeratedValue>
                <enumeratedValue>
                  <name>2</name>
                  <value>4</value>
                </enumeratedValue>
                <enumeratedValue>
                  <name>3</name>
                  <value>8</value>
                </enumeratedValue>
              </enumeratedValues>
            </field>
            <field>
              <name>AFSEL7</name>
              <description>GPIOD7 AF select</description>
              <bitRange>[31:28]</bitRange>
              <enumeratedValues>
                <enumeratedValue>
                  <name>0</name>
                  <value>1</value>
                </enumeratedValue>
                <enumeratedValue>
                  <name>1</name>
                  <value>2</value>
                </enumeratedValue>
                <enumeratedValue>
                  <name>2</name>
                  <value>4</value>
                </enumeratedValue>
                <enumeratedValue>
                  <name>3</name>
                  <value>8</value>
                </enumeratedValue>
              </enumeratedValues>
            </field>
          </fields>
        </register>
        <register>
          <name>AFRH</name>
          <addressOffset>0x24</addressOffset>
          <fields>
            <field>
              <name>AFSEL8</name>
              <description>GPIOD8 AF select</description>
              <bitRange>[3:0]</bitRange>
              <enumeratedValues>
                <enumeratedValue>
                  <name>0</name>
                  <value>1</value>
                </enumeratedValue>
                <enumeratedValue>
                  <name>1</name>
                  <value>2</value>
                </enumeratedValue>
                <enumeratedValue>
                  <name>2</name>
                  <value>4</value>
                </enumeratedValue>
                <enumeratedValue>
                  <name>3</name>
                  <value>8</value>
                </enumeratedValue>
              </enumeratedValues>
            </field>
            <field>
              <name>AFSEL9</name>
              <description>GPIOD9 AF select</description>
              <bitRange>[7:4]</bitRange>
              <enumeratedValues>
                <enumeratedValue>
                  <name>0</name>
                  <value>1</value>
                </enumeratedValue>
                <enumeratedValue>
                  <name>1</name>
                  <value>2</value>
                </enumeratedValue>
                <enumeratedValue>
                  <name>2</name>
                  <value>4</value>
                </enumeratedValue>
                <enumeratedValue>
                  <name>3</name>
                  <value>8</value>
                </enumeratedValue>
              </enumeratedValues>
            </field>
            <field>
              <name>AFSEL10</name>
              <description>GPIOD10 AF select</description>
              <bitRange>[11:8]</bitRange>
              <enumeratedValues>
                <enumeratedValue>
                  <name>0</name>
                  <value>1</value>
                </enumeratedValue>
                <enumeratedValue>
                  <name>1</name>
                  <value>2</value>
                </enumeratedValue>
                <enumeratedValue>
                  <name>2</name>
                  <value>4</value>
                </enumeratedValue>
                <enumeratedValue>
                  <name>3</name>
                  <value>8</value>
                </enumeratedValue>
              </enumeratedValues>
            </field>
            <field>
              <name>AFSEL11</name>
              <description>GPIOD11 AF select</description>
              <bitRange>[15:12]</bitRange>
              <enumeratedValues>
                <enumeratedValue>
                  <name>0</name>
                  <value>1</value>
                </enumeratedValue>
                <enumeratedValue>
                  <name>1</name>
                  <value>2</value>
                </enumeratedValue>
                <enumeratedValue>
                  <name>2</name>
                  <value>4</value>
                </enumeratedValue>
                <enumeratedValue>
                  <name>3</name>
                  <value>8</value>
                </enumeratedValue>
              </enumeratedValues>
            </field>
            <field>
              <name>AFSEL12</name>
              <description>GPIOD12 AF select</description>
              <bitRange>[19:16]</bitRange>
              <enumeratedValues>
                <enumeratedValue>
                  <name>0</name>
                  <value>1</value>
                </enumeratedValue>
                <enumeratedValue>
                  <name>1</name>
                  <value>2</value>
                </enumeratedValue>
                <enumeratedValue>
                  <name>2</name>
                  <value>4</value>
                </enumeratedValue>
                <enumeratedValue>
                  <name>3</name>
                  <value>8</value>
                </enumeratedValue>
              </enumeratedValues>
            </field>
            <field>
              <name>AFSEL13</name>
              <description>GPIOD13 AF select</description>
              <bitRange>[23:20]</bitRange>
              <enumeratedValues>
                <enumeratedValue>
                  <name>0</name>
                  <value>1</value>
                </enumeratedValue>
                <enumeratedValue>
                  <name>1</name>
                  <value>2</value>
                </enumeratedValue>
                <enumeratedValue>
                  <name>2</name>
                  <value>4</value>
                </enumeratedValue>
                <enumeratedValue>
                  <name>3</name>
                  <value>8</value>
                </enumeratedValue>
              </enumeratedValues>
            </field>
            <field>
              <name>AFSEL14</name>
              <description>GPIOD14 AF select</description>
              <bitRange>[27:24]</bitRange>
              <enumeratedValues>
                <enumeratedValue>
                  <name>0</name>
                  <value>1</value>
                </enumeratedValue>
                <enumeratedValue>
                  <name>1</name>
                  <value>2</value>
                </enumeratedValue>
                <enumeratedValue>
                  <name>2</name>
                  <value>4</value>
                </enumeratedValue>
                <enumeratedValue>
                  <name>3</name>
                  <value>8</value>
                </enumeratedValue>
              </enumeratedValues>
            </field>
            <field>
              <name>AFSEL15</name>
              <description>GPIOD15 AF select</description>
              <bitRange>[31:28]</bitRange>
              <enumeratedValues>
                <enumeratedValue>
                  <name>0</name>
                  <value>1</value>
                </enumeratedValue>
                <enumeratedValue>
                  <name>1</name>
                  <value>2</value>
                </enumeratedValue>
                <enumeratedValue>
                  <name>2</name>
                  <value>4</value>
                </enumeratedValue>
                <enumeratedValue>
                  <name>3</name>
                  <value>8</value>
                </enumeratedValue>
              </enumeratedValues>
            </field>
          </fields>
        </register>
        <register>
          <name>BRR</name>
          <addressOffset>0x28</addressOffset>
          <fields>
            <field>
              <name>BR0</name>
              <description>GPIOD 0 output pin reset</description>
              <bitRange>[0:0]</bitRange>
              <access>write-only</access>
            </field>
            <field>
              <name>BR1</name>
              <description>GPIOD 1 output pin reset</description>
              <bitRange>[1:1]</bitRange>
              <access>write-only</access>
            </field>
            <field>
              <name>BR2</name>
              <description>GPIOD 2 output pin reset</description>
              <bitRange>[2:2]</bitRange>
              <access>write-only</access>
            </field>
            <field>
              <name>BR3</name>
              <description>GPIOD 3 output pin reset</description>
              <bitRange>[3:3]</bitRange>
              <access>write-only</access>
            </field>
            <field>
              <name>BR4</name>
              <description>GPIOD 4 output pin reset</description>
              <bitRange>[4:4]</bitRange>
              <access>write-only</access>
            </field>
            <field>
              <name>BR5</name>
              <description>GPIOD 5 output pin reset</description>
              <bitRange>[5:5]</bitRange>
              <access>write-only</access>
            </field>
            <field>
              <name>BR6</name>
              <description>GPIOD 6 output pin reset</description>
              <bitRange>[6:6]</bitRange>
              <access>write-only</access>
            </field>
            <field>
              <name>BR7</name>
              <description>GPIOD 7 output pin reset</description>
              <bitRange>[7:7]</bitRange>
              <access>write-only</access>
            </field>
            <field>
              <name>BR8</name>
              <description>GPIOD 8 output pin reset</description>
              <bitRange>[8:8]</bitRange>
              <access>write-only</access>
            </field>
            <field>
              <name>BR9</name>
              <description>GPIOD 9 output pin reset</description>
              <bitRange>[9:9]</bitRange>
              <access>write-only</access>
            </field>
            <field>
              <name>BR10</name>
              <description>GPIOD 10 output pin reset</description>
              <bitRange>[10:10]</bitRange>
              <access>write-only</access>
            </field>
            <field>
              <name>BR11</name>
              <description>GPIOD 11 output pin reset</description>
              <bitRange>[11:11]</bitRange>
              <access>write-only</access>
            </field>
            <field>
              <name>BR12</name>
              <description>GPIOD 12 output pin reset</description>
              <bitRange>[12:12]</bitRange>
              <access>write-only</access>
            </field>
            <field>
              <name>BR13</name>
              <description>GPIOD 13 output pin reset</description>
              <bitRange>[13:13]</bitRange>
              <access>write-only</access>
            </field>
            <field>
              <name>BR14</name>
              <description>GPIOD 14 output pin reset</description>
              <bitRange>[14:14]</bitRange>
              <access>write-only</access>
            </field>
            <field>
              <name>BR15</name>
              <description>GPIOD 15 output pin reset</description>
              <bitRange>[15:15]</bitRange>
              <access>write-only</access>
            </field>
          </fields>
        </register>
      </registers>
    </peripheral>
    <peripheral>
      <name>I2C1</name>
      <description>Inter integrated circuit</description>
      <groupName>I2C</groupName>
      <baseAddress>0x40005400</baseAddress>
      <addressBlock>
        <offset>0x0</offset>
        <size>0x400</size>
        <usage>registers</usage>
      </addressBlock>
      <interrupt>
        <name>I2C1</name>
        <description>I2C1 global Interrupt</description>
        <value>23</value>
      </interrupt>
      <registers>
        <register>
          <name>CR1</name>
          <description>desc CR1</description>
          <addressOffset>0x0</addressOffset>
          <fields>
            <field>
              <name>PE</name>
              <description>Peripheral enable</description>
              <bitRange>[0:0]</bitRange>
            </field>
            <field>
              <name>SMBUS</name>
              <description>SMBus mode</description>
              <bitRange>[1:1]</bitRange>
            </field>
            <field>
              <name>WUPEN</name>
              <description>Wakeup from Stop mode enable</description>
              <bitRange>[2:2]</bitRange>
            </field>
            <field>
              <name>SMBTYPE</name>
              <description>SMBus type</description>
              <bitRange>[3:3]</bitRange>
            </field>
            <field>
              <name>ENARP</name>
              <description>ARP enable</description>
              <bitRange>[4:4]</bitRange>
            </field>
            <field>
              <name>ENPEC</name>
              <description>PEC enable</description>
              <bitRange>[5:5]</bitRange>
            </field>
            <field>
              <name>ENGC</name>
              <description>General call enable</description>
              <bitRange>[6:6]</bitRange>
            </field>
            <field>
              <name>NOSTRETCH</name>
              <description>Clock stretching disable (Slave mode)</description>
              <bitRange>[7:7]</bitRange>
            </field>
            <field>
              <name>START</name>
              <description>Start generation</description>
              <bitRange>[8:8]</bitRange>
            </field>
            <field>
              <name>STOP</name>
              <description>Stop generation</description>
              <bitRange>[9:9]</bitRange>
            </field>
            <field>
              <name>ACK</name>
              <description>Acknowledge enable</description>
              <bitRange>[10:10]</bitRange>
            </field>
            <field>
              <name>POS</name>
              <description>Acknowledge(for data reception)</description>
              <bitRange>[11:11]</bitRange>
            </field>
            <field>
              <name>PEC</name>
              <description>Packet error checking</description>
              <bitRange>[12:12]</bitRange>
            </field>
            <field>
              <name>ALERT</name>
              <description>SMBus alert</description>
              <bitRange>[13:13]</bitRange>
            </field>
            <field>
              <name>SWRST</name>
              <description>Software reset</description>
              <bitRange>[15:15]</bitRange>
            </field>
            <field>
              <name>WKUP_DIV</name>
              <description>PCLK division</description>
              <bitRange>[17:16]</bitRange>
              <enumeratedValues>
                <enumeratedValue>
                  <name>0</name>
                  <value>1</value>
                </enumeratedValue>
                <enumeratedValue>
                  <name>1</name>
                  <value>2</value>
                </enumeratedValue>
              </enumeratedValues>
            </field>
            <field>
              <name>WKUP_CNT</name>
              <description>Timeout count number</description>
              <bitRange>[19:18]</bitRange>
              <enumeratedValues>
                <enumeratedValue>
                  <name>0</name>
                  <value>1</value>
                </enumeratedValue>
                <enumeratedValue>
                  <name>1</name>
                  <value>2</value>
                </enumeratedValue>
              </enumeratedValues>
            </field>
          </fields>
        </register>
        <register>
          <name>CR2</name>
          <description>desc CR2</description>
          <addressOffset>0x4</addressOffset>
          <fields>
            <field>
              <name>FREQ</name>
              <description>Peripheral clock frequency</description>
              <bitRange>[6:0]</bitRange>
            </field>
            <field>
              <name>ITERREN</name>
              <description>Error interrupt enable</description>
              <bitRange>[8:8]</bitRange>
            </field>
            <field>
              <name>ITEVTEN</name>
              <description>Event interrupt enable</description>
              <bitRange>[9:9]</bitRange>
            </field>
            <field>
              <name>ITBUFEN</name>
              <description>Buffer interrupt enable</description>
              <bitRange>[10:10]</bitRange>
            </field>
            <field>
              <name>DMAEN</name>
              <description>DMA requests enable</description>
              <bitRange>[11:11]</bitRange>
            </field>
            <field>
              <name>LAST</name>
              <description>DMA last transfer</description>
              <bitRange>[12:12]</bitRange>
            </field>
          </fields>
        </register>
        <register>
          <name>OAR1</name>
          <description>desc OAR1</description>
          <addressOffset>0x8</addressOffset>
          <fields>
            <field>
              <name>ADD</name>
              <description>Interface address</description>
              <bitRange>[9:0]</bitRange>
            </field>
            <field>
              <name>ADDMODE</name>
              <description>Addressing mode (slave mode)</description>
              <bitRange>[15:15]</bitRange>
            </field>
          </fields>
        </register>
        <register>
          <name>OAR2</name>
          <description>desc OAR2</description>
          <addressOffset>0xC</addressOffset>
          <fields>
            <field>
              <name>ENDUAL</name>
              <description>Dual addressing mode enable</description>
              <bitRange>[0:0]</bitRange>
            </field>
            <field>
              <name>ADD2</name>
              <description>Interface address</description>
              <bitRange>[7:1]</bitRange>
            </field>
            <field>
              <name>OA2MSK</name>
              <description>Own Address 2 masks</description>
              <bitRange>[10:8]</bitRange>
              <enumeratedValues>
                <enumeratedValue>
                  <name>0</name>
                  <value>1</value>
                </enumeratedValue>
                <enumeratedValue>
                  <name>1</name>
                  <value>2</value>
                </enumeratedValue>
                <enumeratedValue>
                  <name>2</name>
                  <value>4</value>
                </enumeratedValue>
              </enumeratedValues>
            </field>
          </fields>
        </register>
        <register>
          <name>DR</name>
          <description>desc DR</description>
          <addressOffset>0x10</addressOffset>
          <fields>
            <field>
              <name>DR</name>
              <description>8-bit data register</description>
              <bitRange>[7:0]</bitRange>
            </field>
          </fields>
        </register>
        <register>
          <name>SR1</name>
          <description>desc SR1</description>
          <addressOffset>0x14</addressOffset>
          <fields>
            <field>
              <name>SB</name>
              <description>Start bit (Master mode)</description>
              <bitRange>[0:0]</bitRange>
              <access>read-only</access>
            </field>
            <field>
              <name>ADDR</name>
              <description>Address sent (master mode)/matched (slave mode)</description>
              <bitRange>[1:1]</bitRange>
              <access>read-only</access>
            </field>
            <field>
              <name>BTF</name>
              <description>Byte transfer finished</description>
              <bitRange>[2:2]</bitRange>
              <access>read-only</access>
            </field>
            <field>
              <name>ADD10</name>
              <description>10-bit header sent (Master mode)</description>
              <bitRange>[3:3]</bitRange>
              <access>read-only</access>
            </field>
            <field>
              <name>STOPF</name>
              <description>Stop detection (slave mode)</description>
              <bitRange>[4:4]</bitRange>
              <access>read-only</access>
            </field>
            <field>
              <name>RXNE</name>
              <description>Data register not empty (receivers)</description>
              <bitRange>[6:6]</bitRange>
              <access>read-only</access>
            </field>
            <field>
              <name>TXE</name>
              <description>Data register empty (transmitters)</description>
              <bitRange>[7:7]</bitRange>
              <access>read-only</access>
            </field>
            <field>
              <name>BERR</name>
              <description>Bus error</description>
              <bitRange>[8:8]</bitRange>
            </field>
            <field>
              <name>ARLO</name>
              <description>Arbitration lost (master mode)</description>
              <bitRange>[9:9]</bitRange>
            </field>
            <field>
              <name>AF</name>
              <description>Acknowledge failure</description>
              <bitRange>[10:10]</bitRange>
            </field>
            <field>
              <name>OVR</name>
              <description>Overrun/Underrun</description>
              <bitRange>[11:11]</bitRange>
            </field>
            <field>
              <name>PECERR</name>
              <description>PEC Error in reception</description>
              <bitRange>[12:12]</bitRange>
            </field>
            <field>
              <name>TIMEOUT</name>
              <description>Timeout or Tlow error</description>
              <bitRange>[14:14]</bitRange>
            </field>
            <field>
              <name>SMBALERT</name>
              <description>SMBus alert</description>
              <bitRange>[15:15]</bitRange>
            </field>
          </fields>
        </register>
        <register>
          <name>SR2</name>
          <description>desc SR2</description>
          <addressOffset>0x18</addressOffset>
          <fields>
            <field>
              <name>MSL</name>
              <description>Master/slave</description>
              <bitRange>[0:0]</bitRange>
              <access>read-only</access>
            </field>
            <field>
              <name>BUSY</name>
              <description>Bus busy</description>
              <bitRange>[1:1]</bitRange>
              <access>read-only</access>
            </field>
            <field>
              <name>TRA</name>
              <description>Transmitter/receiver</description>
              <bitRange>[2:2]</bitRange>
              <access>read-only</access>
            </field>
            <field>
              <name>GENCALL</name>
              <description>General call address (Slave mode)</description>
              <bitRange>[4:4]</bitRange>
              <access>read-only</access>
            </field>
            <field>
              <name>SMBDEFAULT</name>
              <description>SMBus device default address (Slave mode)</description>
              <bitRange>[5:5]</bitRange>
              <access>read-only</access>              
            </field>
            <field>
              <name>SMBHOST</name>
              <description>SMBus host header (Slave mode)</description>
              <bitRange>[6:6]</bitRange>
              <access>read-only</access>              
            </field>
            <field>
              <name>DUALF</name>
              <description>Dual flag (Slave mode)</description>
              <bitRange>[7:7]</bitRange>
              <access>read-only</access>              
            </field>
            <field>
              <name>PEC</name>
              <description>Packet error checking register</description>
              <bitRange>[15:8]</bitRange>
              <access>read-only</access>
            </field>
          </fields>
        </register>
        <register>
          <name>CCR</name>
          <description>desc CCR</description>
          <addressOffset>0x1C</addressOffset>
          <fields>
            <field>
              <name>CCR</name>
              <description>Clock control register in Fm/Sm mode (Master mode)</description>
              <bitRange>[11:0]</bitRange>
            </field>
            <field>
              <name>FP</name>
              <description>I2C master mode selection</description>
              <bitRange>[13:13]</bitRange>
            </field>
            <field>
              <name>DUTY</name>
              <description>Fm mode duty cycle</description>
              <bitRange>[14:14]</bitRange>
            </field>
            <field>
              <name>FS</name>
              <description>I2C master mode selection</description>
              <bitRange>[15:15]</bitRange>
            </field>
          </fields>
        </register>
        <register>
          <name>TRISE</name>
          <description>desc TRISE</description>
          <addressOffset>0x20</addressOffset>
          <fields>
            <field>
              <name>TRISE</name>
              <description>Maximum rise time in Fm+/Fm/Sm mode (Master mode)</description>
              <bitRange>[6:0]</bitRange>
            </field>
            <field>
              <name>THOLDDATA</name>
              <description>Data hold time</description>
              <bitRange>[11:7]</bitRange>
              <enumeratedValues>
                <enumeratedValue>
                  <name>0</name>
                  <value>1</value>
                </enumeratedValue>
                <enumeratedValue>
                  <name>1</name>
                  <value>2</value>
                </enumeratedValue>
                <enumeratedValue>
                  <name>2</name>
                  <value>4</value>
                </enumeratedValue>
                <enumeratedValue>
                  <name>3</name>
                  <value>8</value>
                </enumeratedValue>
                <enumeratedValue>
                  <name>4</name>
                  <value>16</value>
                </enumeratedValue>
              </enumeratedValues>
            </field>
            <field>
              <name>THOLDDATA_SEL</name>
              <description>Data hold time select</description>
              <bitRange>[12:12]</bitRange>
            </field>
          </fields>
        </register>
        <register>
          <name>TIMEOUTR</name>
          <addressOffset>0x24</addressOffset>
          <fields>
            <field>
              <name>TIMEOUTA</name>
              <description>Bus Timeout A</description>
              <bitRange>[11:0]</bitRange>
            </field>
            <field>
              <name>TIDLE</name>
              <description>Idle clock timeout detection</description>
              <bitRange>[12:12]</bitRange>
            </field>
            <field>
              <name>TIMEOUTEN</name>
              <description>Clock timeout enable</description>
              <bitRange>[15:15]</bitRange>
            </field>
            <field>
              <name>TIMEOUTB</name>
              <description>Bus timeout B</description>
              <bitRange>[27:16]</bitRange>
            </field>
            <field>
              <name>TEXTEN</name>
              <description>Extended clock timeout enable</description>
              <bitRange>[31:31]</bitRange>
            </field>
          </fields>
        </register>
      </registers>
    </peripheral>
    <peripheral derivedFrom="I2C1">
      <name>I2C2</name>
      <description>desc I2C</description>
      <baseAddress>0x40005800</baseAddress>
      <interrupt>
        <name>I2C2</name>
        <description>I2C2 Event Interrupt</description>
        <value>24</value>
      </interrupt>
    </peripheral>
    <peripheral>
      <name>IWDG</name>
      <description>Independent watchdog</description>
      <baseAddress>0x40003000</baseAddress>
      <addressBlock>
        <offset>0x0</offset>
        <size>0x400</size>
        <usage>registers</usage>
      </addressBlock>
      <registers>
        <register>
          <name>KR</name>
          <description>Key register (IWDG_KR)</description>
          <addressOffset>0x0</addressOffset>
          <fields>
            <field>
              <name>KEY</name>
              <description>IWDG KEY</description>
              <bitRange>[15:0]</bitRange>
              <access>write-only</access>
            </field>
          </fields>
        </register>
        <register>
          <name>PR</name>
          <description>Prescaler register (IWDG_PR)</description>
          <addressOffset>0x4</addressOffset>
          <fields>
            <field>
              <name>PR</name>
              <description>IWDG preload</description>
              <bitRange>[2:0]</bitRange>
              <enumeratedValues>
                <enumeratedValue>
                  <name>0</name>
                  <value>1</value>
                </enumeratedValue>
                <enumeratedValue>
                  <name>1</name>
                  <value>2</value>
                </enumeratedValue>
                <enumeratedValue>
                  <name>2</name>
                  <value>4</value>
                </enumeratedValue>
              </enumeratedValues>
            </field>
          </fields>
        </register>
        <register>
          <name>RLR</name>
          <description>Reload register (IWDG_RLR)</description>
          <addressOffset>0x8</addressOffset>
          <fields>
            <field>
              <name>RL</name>
              <description>IWDG reload</description>
              <bitRange>[11:0]</bitRange>
            </field>
          </fields>
        </register>
        <register>
          <name>SR</name>
          <description>Status register (IWDG_SR)</description>
          <addressOffset>0xC</addressOffset>
          <fields>
            <field>
              <name>PVU</name>
              <description>Watchdog prescaler value update</description>
              <bitRange>[0:0]</bitRange>
              <access>read-only</access>
            </field>
            <field>
              <name>RVU</name>
              <description>Watchdog counter reload value update</description>
              <bitRange>[1:1]</bitRange>
              <access>read-only</access>
            </field>
            <field>
              <name>IVU</name>
              <description>Watchdog Interrupt value update</description>
              <bitRange>[3:3]</bitRange>
              <access>read-only</access>
            </field>
            <field>
              <name>IF</name>
              <description>Watchdog interrupt status</description>
              <bitRange>[4:4]</bitRange>
              <access>read-only</access>
            </field>
          </fields>
        </register>
        <register>
          <name>ICNTR</name>
          <addressOffset>0x10</addressOffset>
          <fields>
            <field>
              <name>ICNTR</name>
              <description>Watchdog prescaler value update</description>
              <bitRange>[11:0]</bitRange>
            </field>
          </fields>
        </register>
        <register>
          <name>ICR</name>
          <addressOffset>0x14</addressOffset>
          <fields>
            <field>
              <name>IER</name>
              <description>Watchdog Interrupt enable</description>
              <bitRange>[0:0]</bitRange>
            </field>
            <field>
              <name>ICR</name>
              <description>Watchdog interrupt status clear</description>
              <bitRange>[1:1]</bitRange>
              <access>write-only</access>
            </field>
          </fields>
        </register>
      </registers>
    </peripheral>
    <peripheral>
      <name>LCD</name>
      <description>LCD CONTROLLER</description>
      <baseAddress>0x40002400</baseAddress>
      <addressBlock>
        <offset>0x0</offset>
        <size>0x400</size>
        <usage>registers</usage>
      </addressBlock>
      <interrupt>
        <name>LCD</name>
        <description>LCD global Interrupt</description>
        <value>8</value>
      </interrupt>
      <registers>
        <register>
          <name>CR</name>
          <addressOffset>0x0</addressOffset>
          <fields>
            <field>
              <name>EN</name>
              <bitRange>[0:0]</bitRange>
            </field>
            <field>
              <name>LCDCLK</name>
              <bitRange>[2:1]</bitRange>
              <enumeratedValues>
                <enumeratedValue>
                  <name>0</name>
                  <value>1</value>
                </enumeratedValue>
                <enumeratedValue>
                  <name>1</name>
                  <value>2</value>
                </enumeratedValue>
              </enumeratedValues>
            </field>
            <field>
              <name>BIAS</name>
              <bitRange>[5:4]</bitRange>
              <enumeratedValues>
                <enumeratedValue>
                  <name>0</name>
                  <value>1</value>
                </enumeratedValue>
                <enumeratedValue>
                  <name>1</name>
                  <value>2</value>
                </enumeratedValue>
              </enumeratedValues>
            </field>
            <field>
              <name>DUTY</name>
              <bitRange>[8:6]</bitRange>
              <enumeratedValues>
                <enumeratedValue>
                  <name>0</name>
                  <value>1</value>
                </enumeratedValue>
                <enumeratedValue>
                  <name>1</name>
                  <value>2</value>
                </enumeratedValue>
                <enumeratedValue>
                  <name>2</name>
                  <value>4</value>
                </enumeratedValue>
              </enumeratedValues>
            </field>
            <field>
              <name>BSEL</name>
              <bitRange>[10:9]</bitRange>
              <enumeratedValues>
                <enumeratedValue>
                  <name>0</name>
                  <value>1</value>
                </enumeratedValue>
                <enumeratedValue>
                  <name>1</name>
                  <value>2</value>
                </enumeratedValue>
              </enumeratedValues>
            </field>
            <field>
              <name>CONTRAST</name>
              <bitRange>[15:12]</bitRange>
              <enumeratedValues>
                <enumeratedValue>
                  <name>0</name>
                  <value>1</value>
                </enumeratedValue>
                <enumeratedValue>
                  <name>1</name>
                  <value>2</value>
                </enumeratedValue>
                <enumeratedValue>
                  <name>2</name>
                  <value>4</value>
                </enumeratedValue>
                <enumeratedValue>
                  <name>3</name>
                  <value>8</value>
                </enumeratedValue>
              </enumeratedValues>
            </field>
            <field>
              <name>VSEL</name>
              <bitRange>[16:16]</bitRange>
            </field>
            <field>
              <name>VCP_SEL</name>
              <bitRange>[19:17]</bitRange>
              <enumeratedValues>
                <enumeratedValue>
                  <name>0</name>
                  <value>1</value>
                </enumeratedValue>
                <enumeratedValue>
                  <name>1</name>
                  <value>2</value>
                </enumeratedValue>
                <enumeratedValue>
                  <name>2</name>
                  <value>4</value>
                </enumeratedValue>
              </enumeratedValues>
            </field>
            <field>
              <name>FCCTL</name>
              <bitRange>[23:21]</bitRange>
              <enumeratedValues>
                <enumeratedValue>
                  <name>0</name>
                  <value>1</value>
                </enumeratedValue>
                <enumeratedValue>
                  <name>1</name>
                  <value>2</value>
                </enumeratedValue>
                <enumeratedValue>
                  <name>2</name>
                  <value>4</value>
                </enumeratedValue>
              </enumeratedValues>
            </field>
            <field>
              <name>DEAD</name>
              <bitRange>[26:24]</bitRange>
              <enumeratedValues>
                <enumeratedValue>
                  <name>0</name>
                  <value>1</value>
                </enumeratedValue>
                <enumeratedValue>
                  <name>1</name>
                  <value>2</value>
                </enumeratedValue>
                <enumeratedValue>
                  <name>2</name>
                  <value>4</value>
                </enumeratedValue>
              </enumeratedValues>
            </field>
            <field>
              <name>CP_FRQ</name>
              <bitRange>[29:27]</bitRange>
              <enumeratedValues>
                <enumeratedValue>
                  <name>0</name>
                  <value>1</value>
                </enumeratedValue>
                <enumeratedValue>
                  <name>1</name>
                  <value>2</value>
                </enumeratedValue>
                <enumeratedValue>
                  <name>2</name>
                  <value>4</value>
                </enumeratedValue>
              </enumeratedValues>
            </field>
            <field>
              <name>CP_ST</name>
              <bitRange>[31:30]</bitRange>
              <enumeratedValues>
                <enumeratedValue>
                  <name>0</name>
                  <value>1</value>
                </enumeratedValue>
                <enumeratedValue>
                  <name>1</name>
                  <value>2</value>
                </enumeratedValue>
              </enumeratedValues>
            </field>
          </fields>
        </register>
        <register>
          <name>CSR</name>
          <addressOffset>0x4</addressOffset>
          <fields>
            <field>
              <name>BLINKCNT</name>
              <bitRange>[5:0]</bitRange>
              <enumeratedValues>
                <enumeratedValue>
                  <name>0</name>
                  <value>1</value>
                </enumeratedValue>
                <enumeratedValue>
                  <name>1</name>
                  <value>2</value>
                </enumeratedValue>
                <enumeratedValue>
                  <name>2</name>
                  <value>4</value>
                </enumeratedValue>
                <enumeratedValue>
                  <name>3</name>
                  <value>8</value>
                </enumeratedValue>
                <enumeratedValue>
                  <name>4</name>
                  <value>16</value>
                </enumeratedValue>
                <enumeratedValue>
                  <name>5</name>
                  <value>32</value>
                </enumeratedValue>
              </enumeratedValues>
            </field>
            <field>
              <name>BLINKEN</name>
              <bitRange>[6:6]</bitRange>
            </field>
            <field>
              <name>SWCAP_DRV_NUM</name>
              <bitRange>[9:7]</bitRange>
              <enumeratedValues>
                <enumeratedValue>
                  <name>0</name>
                  <value>1</value>
                </enumeratedValue>
                <enumeratedValue>
                  <name>1</name>
                  <value>2</value>
                </enumeratedValue>
                <enumeratedValue>
                  <name>2</name>
                  <value>4</value>
                </enumeratedValue>
              </enumeratedValues>
            </field>
            <field>
              <name>MODE</name>
              <bitRange>[10:10]</bitRange>
            </field>
            <field>
              <name>DMAEN</name>
              <bitRange>[11:11]</bitRange>
            </field>
            <field>
              <name>BKFIE</name>
              <bitRange>[12:12]</bitRange>
            </field>
            <field>
              <name>UDDIE</name>
              <bitRange>[14:14]</bitRange>
            </field>
            <field>
              <name>UDR</name>
              <bitRange>[15:15]</bitRange>
            </field>
            <field>
              <name>BKF</name>
              <bitRange>[16:16]</bitRange>
              <access>read-only</access>
            </field>
            <field>
              <name>SOF</name>
              <bitRange>[17:17]</bitRange>
              <access>read-only</access>
            </field>
            <field>
              <name>UDD</name>
              <bitRange>[18:18]</bitRange>
              <access>read-only</access>
            </field>
            <field>
              <name>ENS</name>
              <bitRange>[19:19]</bitRange>
              <access>read-only</access>
            </field>
          </fields>
        </register>
        <register>
          <name>INTCLR</name>
          <description>INTCLR</description>
          <addressOffset>0x8</addressOffset>
          <fields>
            <field>
              <name>BKFC</name>
              <bitRange>[16:16]</bitRange>
              <access>write-only</access>
            </field>
            <field>
              <name>SOFC</name>
              <bitRange>[17:17]</bitRange>
              <access>write-only</access>
            </field>
            <field>
              <name>UDDC</name>
              <bitRange>[18:18]</bitRange>
              <access>write-only</access>
            </field>
          </fields>
        </register>
        <register>
          <name>POEN0</name>
          <description>POEN0</description>
          <addressOffset>0xC</addressOffset>
          <fields>
            <field>
              <name>SX</name>
              <bitRange>[31:0]</bitRange>
            </field>
          </fields>
        </register>
        <register>
          <name>POEN1</name>
          <description>POEN1</description>
          <addressOffset>0x10</addressOffset>
          <fields>
            <field>
              <name>SX</name>
              <bitRange>[3:0]</bitRange>
              <enumeratedValues>
                <enumeratedValue>
                  <name>0</name>
                  <value>1</value>
                </enumeratedValue>
                <enumeratedValue>
                  <name>1</name>
                  <value>2</value>
                </enumeratedValue>
                <enumeratedValue>
                  <name>2</name>
                  <value>4</value>
                </enumeratedValue>
                <enumeratedValue>
                  <name>3</name>
                  <value>8</value>
                </enumeratedValue>
              </enumeratedValues>
            </field>
            <field>
              <name>SXCY</name>
              <bitRange>[7:4]</bitRange>
              <enumeratedValues>
                <enumeratedValue>
                  <name>0</name>
                  <value>1</value>
                </enumeratedValue>
                <enumeratedValue>
                  <name>1</name>
                  <value>2</value>
                </enumeratedValue>
                <enumeratedValue>
                  <name>2</name>
                  <value>4</value>
                </enumeratedValue>
                <enumeratedValue>
                  <name>3</name>
                  <value>8</value>
                </enumeratedValue>
              </enumeratedValues>
            </field>
            <field>
              <name>CX</name>
              <bitRange>[11:8]</bitRange>
              <enumeratedValues>
                <enumeratedValue>
                  <name>0</name>
                  <value>1</value>
                </enumeratedValue>
                <enumeratedValue>
                  <name>1</name>
                  <value>2</value>
                </enumeratedValue>
                <enumeratedValue>
                  <name>2</name>
                  <value>4</value>
                </enumeratedValue>
                <enumeratedValue>
                  <name>3</name>
                  <value>8</value>
                </enumeratedValue>
              </enumeratedValues>
            </field>
          </fields>
        </register>
        <register>
          <name>RAM0</name>
          <description>des RAM0</description>
          <addressOffset>0x14</addressOffset>
          <fields>
            <field>
              <name>DX</name>
              <bitRange>[31:0]</bitRange>
            </field>
          </fields>
        </register>
        <register>
          <name>RAM1</name>
          <description>des RAM1</description>
          <addressOffset>0x18</addressOffset>
          <fields>
            <field>
              <name>DX</name>
              <bitRange>[31:0]</bitRange>
            </field>
          </fields>
        </register>
        <register>
          <name>RAM2</name>
          <description>des RAM2</description>
          <addressOffset>0x1C</addressOffset>
          <fields>
            <field>
              <name>DX</name>
              <bitRange>[31:0]</bitRange>
            </field>
          </fields>
        </register>
        <register>
          <name>RAM3</name>
          <description>des RAM3</description>
          <addressOffset>0x20</addressOffset>
          <fields>
            <field>
              <name>DX</name>
              <bitRange>[31:0]</bitRange>
            </field>
          </fields>
        </register>
        <register>
          <name>RAM4</name>
          <description>des RAM4</description>
          <addressOffset>0x24</addressOffset>
          <fields>
            <field>
              <name>DX</name>
              <bitRange>[31:0]</bitRange>
            </field>
          </fields>
        </register>
        <register>
          <name>RAM5</name>
          <description>des RAM5</description>
          <addressOffset>0x28</addressOffset>
          <fields>
            <field>
              <name>DX</name>
              <bitRange>[31:0]</bitRange>
            </field>
          </fields>
        </register>
        <register>
          <name>RAM6</name>
          <description>des RAM6</description>
          <addressOffset>0x2C</addressOffset>
          <fields>
            <field>
              <name>DX</name>
              <bitRange>[31:0]</bitRange>
            </field>
          </fields>
        </register>
        <register>
          <name>RAM7</name>
          <description>des RAM7</description>
          <addressOffset>0x30</addressOffset>
          <fields>
            <field>
              <name>DX</name>
              <bitRange>[31:0]</bitRange>
            </field>
          </fields>
        </register>
        <register>
          <name>RAM8</name>
          <description>des RAM8</description>
          <addressOffset>0x34</addressOffset>
          <fields>
            <field>
              <name>DX</name>
              <bitRange>[7:0]</bitRange>
            </field>
          </fields>
        </register>
        <register>
          <name>RAM9</name>
          <description>des RAM9</description>
          <addressOffset>0x38</addressOffset>
          <fields>
            <field>
              <name>DX</name>
              <bitRange>[7:1]</bitRange>
            </field>
          </fields>
        </register>
        <register>
          <name>RAM10</name>
          <description>des RAM10</description>
          <addressOffset>0x3C</addressOffset>
          <fields>
            <field>
              <name>DX</name>
              <bitRange>[7:2]</bitRange>
            </field>
          </fields>
        </register>
        <register>
          <name>RAM11</name>
          <description>des RAM11</description>
          <addressOffset>0x40</addressOffset>
          <fields>
            <field>
              <name>DX</name>
              <bitRange>[7:3]</bitRange>
            </field>
          </fields>
        </register>
        <register>
          <name>RAM12</name>
          <description>des RAM12</description>
          <addressOffset>0x44</addressOffset>
          <fields>
            <field>
              <name>DX</name>
              <bitRange>[7:4]</bitRange>
            </field>
          </fields>
        </register>
        <register>
          <name>RAM13</name>
          <description>des RAM13</description>
          <addressOffset>0x48</addressOffset>
          <fields>
            <field>
              <name>DX</name>
              <bitRange>[7:5]</bitRange>
            </field>
          </fields>
        </register>
        <register>
          <name>RAM14</name>
          <description>des RAM14</description>
          <addressOffset>0x4C</addressOffset>
          <fields>
            <field>
              <name>DX</name>
              <bitRange>[7:6]</bitRange>
            </field>
          </fields>
        </register>
        <register>
          <name>RAM15</name>
          <description>des RAM15</description>
          <addressOffset>0x50</addressOffset>
          <fields>
            <field>
              <name>DX</name>
              <bitRange>[7:7]</bitRange>
            </field>
          </fields>
        </register>
      </registers>
    </peripheral>
    <peripheral>
      <name>LPTIM1</name>
      <description>Low power timer</description>
      <groupName>LPTIM</groupName>
      <baseAddress>0x40007C00</baseAddress>
      <addressBlock>
        <offset>0x0</offset>
        <size>0x400</size>
        <usage>registers</usage>
      </addressBlock>
      <interrupt>
        <name>TIM6_LPTIM1_DAC</name>
        <description>TIM6, LPTIM1, DAC global Interrupts</description>
        <value>17</value>
      </interrupt>
      <registers>
        <register>
          <name>ISR</name>
          <description>Interrupt and Status Register</description>
          <addressOffset>0x0</addressOffset>
          <fields>
            <field>
              <name>CMPM</name>
              <description>Compare match</description>
              <bitRange>[0:0]</bitRange>
              <access>read-only</access>
            </field>
            <field>
              <name>ARRM</name>
              <description>Autoreload match</description>
              <bitRange>[1:1]</bitRange>
              <access>read-only</access>
            </field>
            <field>
              <name>EXTTRIG</name>
              <description>External trigger edge event</description>
              <bitRange>[2:2]</bitRange>
              <access>read-only</access>
            </field>
            <field>
              <name>CMPOK</name>
              <description>Compare register update OK</description>
              <bitRange>[3:3]</bitRange>
              <access>read-only</access>
            </field>
            <field>
              <name>ARROK</name>
              <description>Autoreload register update OK</description>
              <bitRange>[4:4]</bitRange>
              <access>read-only</access>
            </field>
            <field>
              <name>UP</name>
              <description>Counter direction change down to up</description>
              <bitRange>[5:5]</bitRange>
              <access>read-only</access>
            </field>
            <field>
              <name>DOWN</name>
              <description>Counter direction change up to down</description>
              <bitRange>[6:6]</bitRange>
              <access>read-only</access>
            </field>
          </fields>
        </register>
        <register>
          <name>ICR</name>
          <description>Interrupt Clear Register</description>
          <addressOffset>0x4</addressOffset>
          <fields>
            <field>
              <name>CMPMCF</name>
              <description>Compare match clear flag</description>
              <bitRange>[0:0]</bitRange>
              <access>write-only</access>
            </field>
            <field>
              <name>ARRMCF</name>
              <description>Autoreload match clear flag</description>
              <bitRange>[1:1]</bitRange>
              <access>write-only</access>
            </field>
            <field>
              <name>EXTTRIGCF</name>
              <description>External trigger valid edge clear flag</description>
              <bitRange>[2:2]</bitRange>
              <access>write-only</access>
            </field>
            <field>
              <name>CMPOKCF</name>
              <description>Compare register update OK clear flag</description>
              <bitRange>[3:3]</bitRange>
              <access>write-only</access>
            </field>
            <field>
              <name>ARROKCF</name>
              <description>Autoreload register update OK clear flag</description>
              <bitRange>[4:4]</bitRange>
              <access>write-only</access>
            </field>
            <field>
              <name>UPCF</name>
              <description>Direction change to UP clear flag</description>
              <bitRange>[5:5]</bitRange>
              <access>write-only</access>
            </field>
            <field>
              <name>DOWNCF</name>
              <description>Direction change to down clear flag</description>
              <bitRange>[6:6]</bitRange>
              <access>write-only</access>
            </field>
          </fields>
        </register>
        <register>
          <name>IER</name>
          <description>Interrupt Enable Register</description>
          <addressOffset>0x8</addressOffset>
          <fields>
            <field>
              <name>CMPMIE</name>
              <description>Compare match Interrupt Enable</description>
              <bitRange>[0:0]</bitRange>
            </field>
            <field>
              <name>ARRMIE</name>
              <description>Autoreload match Interrupt Enable</description>
              <bitRange>[1:1]</bitRange>
            </field>
            <field>
              <name>EXTTRIGIE</name>
              <description>External trigger valid edge Interrupt Enable</description>
              <bitRange>[2:2]</bitRange>
            </field>
            <field>
              <name>CMPOKIE</name>
              <description>Compare register update OK Interrupt Enable</description>
              <bitRange>[3:3]</bitRange>
            </field>
            <field>
              <name>ARROKIE</name>
              <description>Autoreload register update OK Interrupt Enable</description>
              <bitRange>[4:4]</bitRange>
            </field>
            <field>
              <name>UPIE</name>
              <description>Direction change to UP Interrupt Enable</description>
              <bitRange>[5:5]</bitRange>
            </field>
            <field>
              <name>DOWNIE</name>
              <description>Direction change to down Interrupt Enable</description>
              <bitRange>[6:6]</bitRange>
            </field>
          </fields>
        </register>
        <register>
          <name>CFGR</name>
          <description>Configuration Register</description>
          <addressOffset>0xC</addressOffset>
          <fields>
            <field>
              <name>CKSEL</name>
              <description>Clock selector</description>
              <bitRange>[0:0]</bitRange>
            </field>
            <field>
              <name>CKPOL</name>
              <description>Clock Polarity</description>
              <bitRange>[2:1]</bitRange>
              <enumeratedValues>
                <enumeratedValue>
                  <name>0</name>
                  <value>1</value>
                </enumeratedValue>
                <enumeratedValue>
                  <name>1</name>
                  <value>2</value>
                </enumeratedValue>
              </enumeratedValues>
            </field>
            <field>
              <name>CKFLT</name>
              <description>Configurable digital filter for external clock</description>
              <bitRange>[4:3]</bitRange>
              <enumeratedValues>
                <enumeratedValue>
                  <name>0</name>
                  <value>1</value>
                </enumeratedValue>
                <enumeratedValue>
                  <name>1</name>
                  <value>2</value>
                </enumeratedValue>
              </enumeratedValues>
            </field>
            <field>
              <name>TRGFLT</name>
              <description>Configurable digital filter for trigger</description>
              <bitRange>[7:6]</bitRange>
              <enumeratedValues>
                <enumeratedValue>
                  <name>0</name>
                  <value>1</value>
                </enumeratedValue>
                <enumeratedValue>
                  <name>1</name>
                  <value>2</value>
                </enumeratedValue>
              </enumeratedValues>
            </field>
            <field>
              <name>PRESC</name>
              <description>Clock prescaler</description>
              <bitRange>[11:9]</bitRange>
              <enumeratedValues>
                <enumeratedValue>
                  <name>0</name>
                  <value>1</value>
                </enumeratedValue>
                <enumeratedValue>
                  <name>1</name>
                  <value>2</value>
                </enumeratedValue>
                <enumeratedValue>
                  <name>2</name>
                  <value>4</value>
                </enumeratedValue>
              </enumeratedValues>
            </field>
            <field>
              <name>TRIGSEL</name>
              <description>Trigger selector</description>
              <bitRange>[15:13]</bitRange>
              <enumeratedValues>
                <enumeratedValue>
                  <name>0</name>
                  <value>1</value>
                </enumeratedValue>
                <enumeratedValue>
                  <name>1</name>
                  <value>2</value>
                </enumeratedValue>
                <enumeratedValue>
                  <name>2</name>
                  <value>4</value>
                </enumeratedValue>
              </enumeratedValues>
            </field>
            <field>
              <name>TRIGEN</name>
              <description>Trigger enable and polarity</description>
              <bitRange>[18:17]</bitRange>
              <enumeratedValues>
                <enumeratedValue>
                  <name>0</name>
                  <value>1</value>
                </enumeratedValue>
                <enumeratedValue>
                  <name>1</name>
                  <value>2</value>
                </enumeratedValue>
              </enumeratedValues>
            </field>
            <field>
              <name>TIMOUT</name>
              <description>Timeout enable</description>
              <bitRange>[19:19]</bitRange>
            </field>
            <field>
              <name>WAVE</name>
              <description>Waveform shape</description>
              <bitRange>[20:20]</bitRange>
            </field>
            <field>
              <name>WAVPOL</name>
              <description>Waveform shape polarity</description>
              <bitRange>[21:21]</bitRange>
            </field>
            <field>
              <name>PRELOAD</name>
              <description>Registers update mode</description>
              <bitRange>[22:22]</bitRange>
            </field>
            <field>
              <name>ENC</name>
              <description>Encoder mode enable</description>
              <bitRange>[24:24]</bitRange>
            </field>
          </fields>
        </register>
        <register>
          <name>CR</name>
          <description>Control Register</description>
          <addressOffset>0x10</addressOffset>
          <fields>
            <field>
              <name>ENABLE</name>
              <description>LPTIM enable</description>
              <bitRange>[0:0]</bitRange>
            </field>
            <field>
              <name>SNGSTRT</name>
              <description>LPTIM start in Single mode</description>
              <bitRange>[1:1]</bitRange>
            </field>
            <field>
              <name>CNTSTRT</name>
              <description>Timer start in Continuous mode</description>
              <bitRange>[2:2]</bitRange>
            </field>
            <field>
              <name>COUNTRST</name>
              <description>Counter reset</description>
              <bitRange>[3:3]</bitRange>
            </field>
            <field>
              <name>RSTARE</name>
              <description>Reset after read enable</description>
              <bitRange>[4:4]</bitRange>
            </field>
          </fields>
        </register>
        <register>
          <name>CMP</name>
          <addressOffset>0x14</addressOffset>
          <fields>
            <field>
              <name>CMP</name>
              <description>Compare value</description>
              <bitRange>[31:0]</bitRange>
            </field>
          </fields>
        </register>
        <register>
          <name>ARR</name>
          <description>Autoreload Register</description>
          <addressOffset>0x18</addressOffset>
          <fields>
            <field>
              <name>ARR</name>
              <description>Auto reload value</description>
              <bitRange>[31:0]</bitRange>
            </field>
          </fields>
        </register>
        <register>
          <name>CNT</name>
          <description>Counter Register</description>
          <addressOffset>0x1C</addressOffset>
          <fields>
            <field>
              <name>CNT</name>
              <description>Counter value</description>
              <bitRange>[31:0]</bitRange>
              <access>read-only</access>
            </field>
          </fields>
        </register>
        <register>
          <name>OR</name>
          <addressOffset>0x20</addressOffset>
          <fields>
            <field>
              <name>IN1_L</name>
              <description>LPTimer input 1 remap extension</description>
              <bitRange>[0:0]</bitRange>
            </field>
            <field>
              <name>IN2L</name>
              <description>LPTimer input 1 remap extension</description>
              <bitRange>[1:1]</bitRange>
            </field>
            <field>
              <name>IN1_H</name>
              <description>LPTimer input 3 remap extension</description>
              <bitRange>[3:2]</bitRange>
            </field>
            <field>
              <name>IN2_H</name>
              <description>LPTimer input 2 remap extension</description>
              <bitRange>[5:4]</bitRange>
            </field>
          </fields>
        </register>
      </registers>
    </peripheral>
    <peripheral derivedFrom="LPTIM1">
      <name>LPTIM2</name>
      <baseAddress>0x40009400</baseAddress>
    </peripheral>
    <peripheral>
      <name>LPUART1</name>
      <groupName>LPUART</groupName>
      <baseAddress>0x40008000</baseAddress>
      <addressBlock>
        <offset>0x0</offset>
        <size>0x40</size>
        <usage>registers</usage>
      </addressBlock>
      <registers>
        <register>
          <name>CR1</name>
          <addressOffset>0x0</addressOffset>
          <fields>
            <field>
              <name>UE</name>
              <description>LPUART enabled</description>
              <bitRange>[0:0]</bitRange>
            </field>
            <field>
              <name>UESM</name>
              <description>LPUART enabled in Stop mode</description>
              <bitRange>[1:1]</bitRange>
            </field>
            <field>
              <name>RE</name>
              <description>Receive enable</description>
              <bitRange>[2:2]</bitRange>
            </field>
            <field>
              <name>TE</name>
              <description>Transfer enable</description>
              <bitRange>[3:3]</bitRange>
            </field>
            <field>
              <name>IDLEIE</name>
              <description>IDLE interrupt enable</description>
              <bitRange>[4:4]</bitRange>
            </field>
            <field>
              <name>EXNEIE</name>
              <description>Receive register untempered enable</description>
              <bitRange>[5:5]</bitRange>
            </field>
            <field>
              <name>TCIE</name>
              <description>End of Transfer interrupt enabled</description>
              <bitRange>[6:6]</bitRange>
            </field>
            <field>
              <name>TXEIE</name>
              <description>Transmit Register Empty Break Enable</description>
              <bitRange>[7:7]</bitRange>
            </field>
            <field>
              <name>PEIE</name>
              <description>PE interrupt enable</description>
              <bitRange>[8:8]</bitRange>
            </field>
            <field>
              <name>PS</name>
              <description>Parity selection</description>
              <bitRange>[9:9]</bitRange>
            </field>
            <field>
              <name>PCE</name>
              <description>Parity control</description>
              <bitRange>[10:10]</bitRange>
            </field>
            <field>
              <name>WAKE</name>
              <description>Receive wake-up mode</description>
              <bitRange>[11:11]</bitRange>
            </field>
            <field>
              <name>M0</name>
              <description>Configure the word length in combination with M1</description>
              <bitRange>[12:12]</bitRange>
            </field>
            <field>
              <name>MME</name>
              <description>Silent mode enabled</description>
              <bitRange>[13:13]</bitRange>
            </field>
            <field>
              <name>CMIE</name>
              <description>Character match interrupt enabled</description>
              <bitRange>[14:14]</bitRange>
            </field>
            <field>
              <name>DEDT</name>
              <description>The time between the transmit frame stop bit and the invalid DE (driver enable) signal</description>
              <bitRange>[20:16]</bitRange>
              <enumeratedValues>
                <enumeratedValue>
                  <name>0</name>
                  <value>1</value>
                </enumeratedValue>
                <enumeratedValue>
                  <name>1</name>
                  <value>2</value>
                </enumeratedValue>
                <enumeratedValue>
                  <name>2</name>
                  <value>4</value>
                </enumeratedValue>
                <enumeratedValue>
                  <name>3</name>
                  <value>8</value>
                </enumeratedValue>
                <enumeratedValue>
                  <name>4</name>
                  <value>16</value>
                </enumeratedValue>
              </enumeratedValues>
            </field>
            <field>
              <name>DEAT</name>
              <description>The time between the DE (driver enable) signal validity and the start bit</description>
              <bitRange>[25:21]</bitRange>
              <enumeratedValues>
                <enumeratedValue>
                  <name>0</name>
                  <value>1</value>
                </enumeratedValue>
                <enumeratedValue>
                  <name>1</name>
                  <value>2</value>
                </enumeratedValue>
                <enumeratedValue>
                  <name>2</name>
                  <value>4</value>
                </enumeratedValue>
                <enumeratedValue>
                  <name>3</name>
                  <value>8</value>
                </enumeratedValue>
                <enumeratedValue>
                  <name>4</name>
                  <value>16</value>
                </enumeratedValue>
              </enumeratedValues>
            </field>
            <field>
              <name>M1</name>
              <description>The value of {M1,M0} the configurate length</description>
              <bitRange>[28:28]</bitRange>
            </field>
          </fields>
        </register>
        <register>
          <name>CR2</name>
          <addressOffset>0x4</addressOffset>
          <fields>
            <field>
              <name>ADDM7</name>
              <description>7bit/4bit address detection configuration</description>
              <bitRange>[4:4]</bitRange>
            </field>
            <field>
              <name>STOP</name>
              <description>Stop bit configuration</description>
              <bitRange>[13:12]</bitRange>
              <enumeratedValues>
                <enumeratedValue>
                  <name>0</name>
                  <value>1</value>
                </enumeratedValue>
                <enumeratedValue>
                  <name>1</name>
                  <value>2</value>
                </enumeratedValue>
              </enumeratedValues>
            </field>
            <field>
              <name>SWAP</name>
              <description>TX/RX pin interchangeable</description>
              <bitRange>[15:15]</bitRange>
            </field>
            <field>
              <name>RXINV</name>
              <description>The RX pin is active level inverting</description>
              <bitRange>[16:16]</bitRange>
            </field>
            <field>
              <name>TXINV</name>
              <description>TX pin active level inverted</description>
              <bitRange>[17:17]</bitRange>
            </field>
            <field>
              <name>DATAINV</name>
              <description>Inverse binary data processing</description>
              <bitRange>[18:18]</bitRange>
            </field>
            <field>
              <name>MSBFIRST</name>
              <description>MSB first</description>
              <bitRange>[19:19]</bitRange>
            </field>
            <field>
              <name>TXOE_ALWAYS_ON</name>
              <bitRange>[20:20]</bitRange>
            </field>
            <field>
              <name>ADD</name>
              <description>LPUART address</description>
              <bitRange>[31:24]</bitRange>
            </field>
          </fields>
        </register>
        <register>
          <name>CR3</name>
          <addressOffset>0x8</addressOffset>
          <fields>
            <field>
              <name>EIE</name>
              <description>Error interrupts are enabled</description>
              <bitRange>[0:0]</bitRange>
            </field>
            <field>
              <name>HDSEL</name>
              <description>Half-duplex selection</description>
              <bitRange>[3:3]</bitRange>
            </field>
            <field>
              <name>DMAR</name>
              <description>Enable DMA on reception</description>
              <bitRange>[6:6]</bitRange>
            </field>
            <field>
              <name>DMAT</name>
              <description>Enable DMA while transmitting</description>
              <bitRange>[7:7]</bitRange>
            </field>
            <field>
              <name>RTSE</name>
              <description>RTS enabled</description>
              <bitRange>[8:8]</bitRange>
            </field>
            <field>
              <name>CTSE</name>
              <description>CTS enabled</description>
              <bitRange>[9:9]</bitRange>
            </field>
            <field>
              <name>CTSIE</name>
              <description>CTS interrupt enable</description>
              <bitRange>[10:10]</bitRange>
            </field>
            <field>
              <name>OVRDIS</name>
              <description>Overrun is prohibited</description>
              <bitRange>[12:12]</bitRange>
            </field>
            <field>
              <name>DDRE</name>
              <description>Whether DMA is disabled when receiving an error</description>
              <bitRange>[13:13]</bitRange>
            </field>
            <field>
              <name>DEM</name>
              <description>DE mode enabled</description>
              <bitRange>[14:14]</bitRange>
            </field>
            <field>
              <name>DEP</name>
              <description>DE polarity selection</description>
              <bitRange>[15:15]</bitRange>
            </field>
            <field>
              <name>WUS</name>
              <description>Low-power wake-up options</description>
              <bitRange>[21:20]</bitRange>
              <enumeratedValues>
                <enumeratedValue>
                  <name>0</name>
                  <value>1</value>
                </enumeratedValue>
                <enumeratedValue>
                  <name>1</name>
                  <value>2</value>
                </enumeratedValue>
              </enumeratedValues>
            </field>
            <field>
              <name>WUFIE</name>
              <description>Low-power wake-up interrupt enable</description>
              <bitRange>[22:22]</bitRange>
            </field>
          </fields>
        </register>
        <register>
          <name>BRR</name>
          <addressOffset>0xC</addressOffset>
          <fields>
            <field>
              <name>BBR</name>
              <description>LPUART baud rate</description>
              <bitRange>[19:0]</bitRange>
            </field>
          </fields>
        </register>
        <register>
          <name>LPWKUP_BRR</name>
          <addressOffset>0x10</addressOffset>
          <fields>
            <field>
              <name>LPWKUP_BBR</name>
              <description>LPUART lpwkup baud rate</description>
              <bitRange>[19:0]</bitRange>
            </field>
            <field>
              <name>HW_BRR_UPEN</name>
              <description>LPUART wkup brr update enable</description>
              <bitRange>[20:20]</bitRange>
            </field>
          </fields>
        </register>
        <register>
          <name>RQR</name>
          <addressOffset>0x18</addressOffset>
          <fields>
            <field>
              <name>SBKRQ</name>
              <description>Send an abort request</description>
              <bitRange>[1:1]</bitRange>
              <access>write-only</access>
            </field>
            <field>
              <name>MMRQ</name>
              <description>Silent mode request</description>
              <bitRange>[2:2]</bitRange>
              <access>write-only</access>
            </field>
          </fields>
        </register>
        <register>
          <name>ISR</name>
          <addressOffset>0x1C</addressOffset>
          <fields>
            <field>
              <name>PE</name>
              <description>Parity error</description>
              <bitRange>[0:0]</bitRange>
              <access>read-only</access>
            </field>
            <field>
              <name>FE</name>
              <description>Frame error flag</description>
              <bitRange>[1:1]</bitRange>
              <access>read-only</access>
            </field>
            <field>
              <name>NE</name>
              <description>START bit noise flag</description>
              <bitRange>[2:2]</bitRange>
              <access>read-only</access>
            </field>
            <field>
              <name>ORE</name>
              <description>Overrun error flag</description>
              <bitRange>[3:3]</bitRange>
              <access>read-only</access>
            </field>
            <field>
              <name>IDLE</name>
              <description>idle flag</description>
              <bitRange>[4:4]</bitRange>
              <access>read-only</access>
            </field>
            <field>
              <name>RXNE</name>
              <description>RX register not empty</description>
              <bitRange>[5:5]</bitRange>
              <access>read-only</access>
            </field>
            <field>
              <name>TC</name>
              <description>Transmission completion flag</description>
              <bitRange>[6:6]</bitRange>
              <access>read-only</access>
            </field>
            <field>
              <name>TXE</name>
              <description>TX register empty</description>
              <bitRange>[7:7]</bitRange>
              <access>read-only</access>
            </field>
            <field>
              <name>CTSIF</name>
              <description>CTS interrupt flag</description>
              <bitRange>[9:9]</bitRange>
              <access>read-only</access>
            </field>
            <field>
              <name>CTS</name>
              <description>CTS flag</description>
              <bitRange>[10:10]</bitRange>
              <access>read-only</access>
            </field>
            <field>
              <name>BUSY</name>
              <description>Busy flag</description>
              <bitRange>[16:16]</bitRange>
              <access>read-only</access>
            </field>
            <field>
              <name>CMF</name>
              <description>Address match flag</description>
              <bitRange>[17:17]</bitRange>
              <access>read-only</access>
            </field>
            <field>
              <name>SBKF</name>
              <description>Send abort flag</description>
              <bitRange>[18:18]</bitRange>
              <access>read-only</access>
            </field>
            <field>
              <name>RWU</name>
              <description>Receive Mute mode wake-up flag</description>
              <bitRange>[19:19]</bitRange>
              <access>read-only</access>
            </field>
            <field>
              <name>WUF</name>
              <description>Wake flag from low-power mode</description>
              <bitRange>[20:20]</bitRange>
              <access>read-only</access>
            </field>
            <field>
              <name>TEACK</name>
              <description>Transport enable acknowledgement flag</description>
              <bitRange>[21:21]</bitRange>
              <access>read-only</access>
            </field>
            <field>
              <name>REACK</name>
              <description>Receive the enable acknowledgment flag</description>
              <bitRange>[22:22]</bitRange>
              <access>read-only</access>
            </field>
          </fields>
        </register>
        <register>
          <name>ICR</name>
          <addressOffset>0x20</addressOffset>
          <fields>
            <field>
              <name>PECF</name>
              <description>Check value error flag reset</description>
              <bitRange>[0:0]</bitRange>
              <access>write-only</access>
            </field>
            <field>
              <name>FECF</name>
              <description>Frame error flag reset</description>
              <bitRange>[1:1]</bitRange>
              <access>write-only</access>
            </field>
            <field>
              <name>NECF</name>
              <description>Clear the START bit noise flag</description>
              <bitRange>[2:2]</bitRange>
              <access>write-only</access>
            </field>
            <field>
              <name>ORECF</name>
              <description>Overrun error flag reset</description>
              <bitRange>[3:3]</bitRange>
              <access>write-only</access>
            </field>
            <field>
              <name>IDLECF</name>
              <description>Clear idle flag</description>
              <bitRange>[4:4]</bitRange>
              <access>write-only</access>
            </field>
            <field>
              <name>TCCF</name>
              <description>Transfer completion flag reset</description>
              <bitRange>[6:6]</bitRange>
              <access>write-only</access>
            </field>
            <field>
              <name>CTSCF</name>
              <description>CTS flag reset</description>
              <bitRange>[9:9]</bitRange>
              <access>write-only</access>
            </field>
            <field>
              <name>CMCF</name>
              <description>Address matching flag reset</description>
              <bitRange>[17:17]</bitRange>
              <access>write-only</access>
            </field>
            <field>
              <name>WUCF</name>
              <description>Low power wake-up flag reset</description>
              <bitRange>[20:20]</bitRange>
              <access>write-only</access>
            </field>
          </fields>
        </register>
        <register>
          <name>RDR</name>
          <addressOffset>0x24</addressOffset>
          <fields>
            <field>
              <name>RDR</name>
              <description>Receive Data Register</description>
              <bitRange>[8:0]</bitRange>
              <access>read-only</access>
            </field>
          </fields>
        </register>
        <register>
          <name>TDR</name>
          <addressOffset>0x28</addressOffset>
          <fields>
            <field>
              <name>TDR</name>
              <description>Transmit Data Register</description>
              <bitRange>[8:0]</bitRange>
            </field>
          </fields>
        </register>
        <register>
          <name>PRESC</name>
          <addressOffset>0x2C</addressOffset>
          <fields>
            <field>
              <name>PRESCALER</name>
              <description>Input clock prescaler register</description>
              <bitRange>[3:0]</bitRange>
              <enumeratedValues>
                <enumeratedValue>
                  <name>0</name>
                  <value>1</value>
                </enumeratedValue>
                <enumeratedValue>
                  <name>1</name>
                  <value>2</value>
                </enumeratedValue>
                <enumeratedValue>
                  <name>2</name>
                  <value>4</value>
                </enumeratedValue>
                <enumeratedValue>
                  <name>3</name>
                  <value>8</value>
                </enumeratedValue>
              </enumeratedValues>
            </field>
          </fields>
        </register>
        <register>
          <name>DBG</name>
          <addressOffset>0x30</addressOffset>
          <fields>
            <field>
              <name>DBGSEL</name>
              <description>debug select</description>
              <bitRange>[1:0]</bitRange>
              <enumeratedValues>
                <enumeratedValue>
                  <name>0</name>
                  <value>1</value>
                </enumeratedValue>
                <enumeratedValue>
                  <name>1</name>
                  <value>2</value>
                </enumeratedValue>
              </enumeratedValues>
            </field>
            <field>
              <name>OFFSET_ADD</name>
              <description>offset add</description>
              <bitRange>[31:24]</bitRange>
            </field>
          </fields>
        </register>
      </registers>
    </peripheral>
    <peripheral derivedFrom="LPUART1">
      <name>LPUART2</name>
      <baseAddress>0x40009800</baseAddress>
    </peripheral>
    <peripheral>
      <name>OPA</name>
      <description>des OPA</description>
      <baseAddress>0x40010300</baseAddress>
      <addressBlock>
        <offset>0x0</offset>
        <size>0x100</size>
        <usage>registers</usage>
      </addressBlock>
      <registers>
        <register>
          <name>OCR</name>
          <addressOffset>0x30</addressOffset>
          <fields>
            <field>
              <name>OPA_EXTOEN</name>
              <bitRange>[0:0]</bitRange>
            </field>
            <field>
              <name>OPA_EXTOSEL</name>
              <bitRange>[2:1]</bitRange>
              <enumeratedValues>
                <enumeratedValue>
                  <name>0</name>
                  <value>1</value>
                </enumeratedValue>
                <enumeratedValue>
                  <name>1</name>
                  <value>2</value>
                </enumeratedValue>
              </enumeratedValues>
            </field>
          </fields>
        </register>
        <register>
          <name>CR</name>
          <addressOffset>0x34</addressOffset>
          <fields>
            <field>
              <name>OPA_VINPSEL</name>
              <bitRange>[0:0]</bitRange>
            </field>
            <field>
              <name>OPA_VINMSEL</name>
              <bitRange>[2:2]</bitRange>
            </field>
            <field>
              <name>OPAEN</name>
              <bitRange>[5:5]</bitRange>
            </field>
          </fields>
        </register>
        <register>
          <name>TMR</name>
          <addressOffset>0x40</addressOffset>
          <fields>
            <field>
              <name>OPA_TM</name>
              <bitRange>[0:0]</bitRange>
            </field>
          </fields>
        </register>
      </registers>
    </peripheral>
    <peripheral>
      <name>PWM</name>
      <baseAddress>0x40014C00</baseAddress>
      <addressBlock>
        <offset>0x0</offset>
        <size>0x50</size>
        <usage>registers</usage>
      </addressBlock>
      <registers>
        <register>
          <name>CR1</name>
          <addressOffset>0x0</addressOffset>
          <fields>
            <field>
              <name>CEN</name>
              <bitRange>[0:0]</bitRange>
            </field>
            <field>
              <name>UDIS</name>
              <bitRange>[1:1]</bitRange>
            </field>
            <field>
              <name>URS</name>
              <bitRange>[2:2]</bitRange>
            </field>
            <field>
              <name>DIR</name>
              <bitRange>[4:4]</bitRange>
            </field>
            <field>
              <name>CMS</name>
              <bitRange>[6:5]</bitRange>
              <enumeratedValues>
                <enumeratedValue>
                  <name>0</name>
                  <value>1</value>
                </enumeratedValue>
                <enumeratedValue>
                  <name>1</name>
                  <value>2</value>
                </enumeratedValue>
              </enumeratedValues>
            </field>
            <field>
              <name>ARPE</name>
              <bitRange>[7:7]</bitRange>
            </field>
            <field>
              <name>CKD</name>
              <bitRange>[9:8]</bitRange>
              <enumeratedValues>
                <enumeratedValue>
                  <name>0</name>
                  <value>1</value>
                </enumeratedValue>
                <enumeratedValue>
                  <name>1</name>
                  <value>2</value>
                </enumeratedValue>
              </enumeratedValues>
            </field>
          </fields>
        </register>
        <register>
          <name>CR2</name>
          <addressOffset>0x4</addressOffset>
          <fields>
            <field>
              <name>BKINE</name>
              <bitRange>[0:0]</bitRange>
            </field>
            <field>
              <name>BKCMP1E</name>
              <bitRange>[1:1]</bitRange>
            </field>
            <field>
              <name>BKCMP2E</name>
              <bitRange>[2:2]</bitRange>
            </field>
            <field>
              <name>BKINP</name>
              <bitRange>[9:9]</bitRange>
            </field>
            <field>
              <name>BKCMP1P</name>
              <bitRange>[10:10]</bitRange>
            </field>
            <field>
              <name>BKCMP2P</name>
              <bitRange>[11:11]</bitRange>
            </field>
            <field>
              <name>ETRSEL</name>
              <bitRange>[15:13]</bitRange>
              <enumeratedValues>
                <enumeratedValue>
                  <name>0</name>
                  <value>1</value>
                </enumeratedValue>
                <enumeratedValue>
                  <name>1</name>
                  <value>2</value>
                </enumeratedValue>
                <enumeratedValue>
                  <name>2</name>
                  <value>4</value>
                </enumeratedValue>
              </enumeratedValues>
            </field>
          </fields>
        </register>
        <register>
          <name>SMCR</name>
          <addressOffset>0x8</addressOffset>
          <fields>
            <field>
              <name>ETF</name>
              <bitRange>[11:8]</bitRange>
              <enumeratedValues>
                <enumeratedValue>
                  <name>0</name>
                  <value>1</value>
                </enumeratedValue>
                <enumeratedValue>
                  <name>1</name>
                  <value>2</value>
                </enumeratedValue>
                <enumeratedValue>
                  <name>2</name>
                  <value>4</value>
                </enumeratedValue>
                <enumeratedValue>
                  <name>3</name>
                  <value>8</value>
                </enumeratedValue>
              </enumeratedValues>
            </field>
            <field>
              <name>ETPS</name>
              <bitRange>[13:12]</bitRange>
              <enumeratedValues>
                <enumeratedValue>
                  <name>0</name>
                  <value>1</value>
                </enumeratedValue>
                <enumeratedValue>
                  <name>1</name>
                  <value>2</value>
                </enumeratedValue>
              </enumeratedValues>
            </field>
            <field>
              <name>ECE</name>
              <bitRange>[14:14]</bitRange>
            </field>
            <field>
              <name>ETP</name>
              <bitRange>[15:15]</bitRange>
            </field>
          </fields>
        </register>
        <register>
          <name>DIER</name>
          <addressOffset>0xC</addressOffset>
          <fields>
            <field>
              <name>UIE</name>
              <bitRange>[0:0]</bitRange>
            </field>
            <field>
              <name>OC1IE</name>
              <bitRange>[1:1]</bitRange>
            </field>
            <field>
              <name>OC2IE</name>
              <bitRange>[2:2]</bitRange>
            </field>
            <field>
              <name>OC3IE</name>
              <bitRange>[3:3]</bitRange>
            </field>
            <field>
              <name>OC4IE</name>
              <bitRange>[4:4]</bitRange>
            </field>
            <field>
              <name>BIE</name>
              <bitRange>[7:7]</bitRange>
            </field>
            <field>
              <name>UDE</name>
              <bitRange>[8:8]</bitRange>
            </field>
            <field>
              <name>OC1DE</name>
              <bitRange>[9:9]</bitRange>
            </field>
            <field>
              <name>OC2DE</name>
              <bitRange>[10:10]</bitRange>
            </field>
            <field>
              <name>OC3DE</name>
              <bitRange>[11:11]</bitRange>
            </field>
            <field>
              <name>OC4DE</name>
              <bitRange>[12:12]</bitRange>
            </field>
          </fields>
        </register>
        <register>
          <name>SR</name>
          <addressOffset>0x10</addressOffset>
          <fields>
            <field>
              <name>UIF</name>
              <bitRange>[0:0]</bitRange>
            </field>
            <field>
              <name>OC1IF</name>
              <bitRange>[1:1]</bitRange>
            </field>
            <field>
              <name>OC2IF</name>
              <bitRange>[2:2]</bitRange>
            </field>
            <field>
              <name>OC3IF</name>
              <bitRange>[3:3]</bitRange>
            </field>
            <field>
              <name>OC4IF</name>
              <bitRange>[4:4]</bitRange>
            </field>
            <field>
              <name>BIF</name>
              <bitRange>[7:7]</bitRange>
            </field>
            <field>
              <name>CCR1OK</name>
              <bitRange>[9:9]</bitRange>
            </field>
            <field>
              <name>CCR2OK</name>
              <bitRange>[10:10]</bitRange>
            </field>
            <field>
              <name>CCR3OK</name>
              <bitRange>[11:11]</bitRange>
            </field>
            <field>
              <name>CCR4OK</name>
              <bitRange>[12:12]</bitRange>
            </field>
            <field>
              <name>CNTOK</name>
              <bitRange>[13:13]</bitRange>
            </field>
            <field>
              <name>PSCOK</name>
              <bitRange>[14:14]</bitRange>
            </field>
            <field>
              <name>ARROK</name>
              <bitRange>[15:15]</bitRange>
            </field>
          </fields>
        </register>
        <register>
          <name>EGR</name>
          <addressOffset>0x14</addressOffset>
          <fields>
            <field>
              <name>UG</name>
              <bitRange>[0:0]</bitRange>
              <access>write-only</access>
            </field>
          </fields>
        </register>
        <register>
          <name>CMR</name>
          <addressOffset>0x18</addressOffset>
          <fields>
            <field>
              <name>OC1M</name>
              <bitRange>[1:0]</bitRange>
              <enumeratedValues>
                <enumeratedValue>
                  <name>0</name>
                  <value>1</value>
                </enumeratedValue>
                <enumeratedValue>
                  <name>1</name>
                  <value>2</value>
                </enumeratedValue>
              </enumeratedValues>
            </field>
            <field>
              <name>OC2M</name>
              <bitRange>[3:2]</bitRange>
              <enumeratedValues>
                <enumeratedValue>
                  <name>0</name>
                  <value>1</value>
                </enumeratedValue>
                <enumeratedValue>
                  <name>1</name>
                  <value>2</value>
                </enumeratedValue>
              </enumeratedValues>
            </field>
            <field>
              <name>OC3M</name>
              <bitRange>[5:4]</bitRange>
              <enumeratedValues>
                <enumeratedValue>
                  <name>0</name>
                  <value>1</value>
                </enumeratedValue>
                <enumeratedValue>
                  <name>1</name>
                  <value>2</value>
                </enumeratedValue>
              </enumeratedValues>
            </field>
            <field>
              <name>OC4M</name>
              <bitRange>[7:6]</bitRange>
              <enumeratedValues>
                <enumeratedValue>
                  <name>0</name>
                  <value>1</value>
                </enumeratedValue>
                <enumeratedValue>
                  <name>1</name>
                  <value>2</value>
                </enumeratedValue>
              </enumeratedValues>
            </field>
            <field>
              <name>OC1PE</name>
              <bitRange>[8:8]</bitRange>
            </field>
            <field>
              <name>OC2PE</name>
              <bitRange>[9:9]</bitRange>
            </field>
            <field>
              <name>OC3PE</name>
              <bitRange>[10:10]</bitRange>
            </field>
            <field>
              <name>OC4PE</name>
              <bitRange>[11:11]</bitRange>
            </field>
          </fields>
        </register>
        <register>
          <name>CER</name>
          <addressOffset>0x20</addressOffset>
          <fields>
            <field>
              <name>C1E</name>
              <bitRange>[0:0]</bitRange>
            </field>
            <field>
              <name>C1P</name>
              <bitRange>[1:1]</bitRange>
            </field>
            <field>
              <name>C1NE</name>
              <bitRange>[2:2]</bitRange>
            </field>
            <field>
              <name>C1NP</name>
              <bitRange>[3:3]</bitRange>
            </field>
            <field>
              <name>C2E</name>
              <bitRange>[4:4]</bitRange>
            </field>
            <field>
              <name>C2P</name>
              <bitRange>[5:5]</bitRange>
            </field>
            <field>
              <name>C2NE</name>
              <bitRange>[6:6]</bitRange>
            </field>
            <field>
              <name>C2NP</name>
              <bitRange>[7:7]</bitRange>
            </field>
            <field>
              <name>C3E</name>
              <bitRange>[8:8]</bitRange>
            </field>
            <field>
              <name>C3P</name>
              <bitRange>[9:9]</bitRange>
            </field>
            <field>
              <name>C4E</name>
              <bitRange>[12:12]</bitRange>
            </field>
            <field>
              <name>C4P</name>
              <bitRange>[13:13]</bitRange>
            </field>
          </fields>
        </register>
        <register>
          <name>CNT</name>
          <addressOffset>0x24</addressOffset>
          <fields>
            <field>
              <name>CNT</name>
              <bitRange>[15:0]</bitRange>
            </field>
          </fields>
        </register>
        <register>
          <name>PSC</name>
          <addressOffset>0x28</addressOffset>
          <fields>
            <field>
              <name>PSC</name>
              <bitRange>[15:0]</bitRange>
            </field>
          </fields>
        </register>
        <register>
          <name>ARR</name>
          <addressOffset>0x2C</addressOffset>
          <fields>
            <field>
              <name>ARR</name>
              <bitRange>[15:0]</bitRange>
            </field>
          </fields>
        </register>
        <register>
          <name>CCR1</name>
          <addressOffset>0x34</addressOffset>
          <fields>
            <field>
              <name>CCR1</name>
              <bitRange>[15:0]</bitRange>
            </field>
          </fields>
        </register>
        <register>
          <name>CCR2</name>
          <addressOffset>0x38</addressOffset>
          <fields>
            <field>
              <name>CCR2</name>
              <bitRange>[15:0]</bitRange>
            </field>
          </fields>
        </register>
        <register>
          <name>CCR3</name>
          <addressOffset>0x3C</addressOffset>
          <fields>
            <field>
              <name>CCR3</name>
              <bitRange>[15:0]</bitRange>
            </field>
          </fields>
        </register>
        <register>
          <name>CCR4</name>
          <addressOffset>0x40</addressOffset>
          <fields>
            <field>
              <name>CCR4</name>
              <bitRange>[15:0]</bitRange>
            </field>
          </fields>
        </register>
        <register>
          <name>BDTR</name>
          <addressOffset>0x44</addressOffset>
          <fields>
            <field>
              <name>DTG</name>
              <bitRange>[7:0]</bitRange>
            </field>
            <field>
              <name>LOCK</name>
              <bitRange>[9:8]</bitRange>
              <enumeratedValues>
                <enumeratedValue>
                  <name>0</name>
                  <value>1</value>
                </enumeratedValue>
                <enumeratedValue>
                  <name>1</name>
                  <value>2</value>
                </enumeratedValue>
              </enumeratedValues>
            </field>
            <field>
              <name>BKE</name>
              <bitRange>[12:12]</bitRange>
            </field>
            <field>
              <name>BKP</name>
              <bitRange>[13:13]</bitRange>
            </field>
            <field>
              <name>AOE</name>
              <bitRange>[14:14]</bitRange>
            </field>
            <field>
              <name>MOE</name>
              <bitRange>[15:15]</bitRange>
            </field>
          </fields>
        </register>
        <register>
          <name>DCR</name>
          <addressOffset>0x48</addressOffset>
          <fields>
            <field>
              <name>DBA</name>
              <bitRange>[4:0]</bitRange>
              <enumeratedValues>
                <enumeratedValue>
                  <name>0</name>
                  <value>1</value>
                </enumeratedValue>
                <enumeratedValue>
                  <name>1</name>
                  <value>2</value>
                </enumeratedValue>
                <enumeratedValue>
                  <name>2</name>
                  <value>4</value>
                </enumeratedValue>
                <enumeratedValue>
                  <name>3</name>
                  <value>8</value>
                </enumeratedValue>
                <enumeratedValue>
                  <name>4</name>
                  <value>16</value>
                </enumeratedValue>
              </enumeratedValues>
            </field>
            <field>
              <name>DBL</name>
              <bitRange>[12:8]</bitRange>
              <enumeratedValues>
                <enumeratedValue>
                  <name>0</name>
                  <value>1</value>
                </enumeratedValue>
                <enumeratedValue>
                  <name>1</name>
                  <value>2</value>
                </enumeratedValue>
                <enumeratedValue>
                  <name>2</name>
                  <value>4</value>
                </enumeratedValue>
                <enumeratedValue>
                  <name>3</name>
                  <value>8</value>
                </enumeratedValue>
                <enumeratedValue>
                  <name>4</name>
                  <value>16</value>
                </enumeratedValue>
              </enumeratedValues>
            </field>
          </fields>
        </register>
        <register>
          <name>DMAR</name>
          <addressOffset>0x4C</addressOffset>
          <fields>
            <field>
              <name>DMAB</name>
              <bitRange>[31:0]</bitRange>
            </field>
          </fields>
        </register>
      </registers>
    </peripheral>
    <peripheral>
      <name>PWR</name>
      <description>Power control</description>
      <baseAddress>0x40007000</baseAddress>
      <addressBlock>
        <offset>0x0</offset>
        <size>0x400</size>
        <usage>registers</usage>
      </addressBlock>
      <registers>
        <register>
          <name>CR1</name>
          <description>Power control register 1</description>
          <addressOffset>0x0</addressOffset>
          <fields>
            <field>
              <name>LPMS</name>
              <bitRange>[2:0]</bitRange>
              <enumeratedValues>
                <enumeratedValue>
                  <name>0</name>
                  <value>1</value>
                </enumeratedValue>
                <enumeratedValue>
                  <name>1</name>
                  <value>2</value>
                </enumeratedValue>
                <enumeratedValue>
                  <name>2</name>
                  <value>4</value>
                </enumeratedValue>
              </enumeratedValues>
            </field>
            <field>
              <name>DBP</name>
              <bitRange>[8:8]</bitRange>
            </field>
            <field>
              <name>VR_MODE</name>
              <bitRange>[10:9]</bitRange>
              <enumeratedValues>
                <enumeratedValue>
                  <name>0</name>
                  <value>1</value>
                </enumeratedValue>
                <enumeratedValue>
                  <name>1</name>
                  <value>2</value>
                </enumeratedValue>
              </enumeratedValues>
            </field>
            <field>
              <name>FLS_SLPTIME</name>
              <bitRange>[13:12]</bitRange>
              <enumeratedValues>
                <enumeratedValue>
                  <name>0</name>
                  <value>1</value>
                </enumeratedValue>
                <enumeratedValue>
                  <name>1</name>
                  <value>2</value>
                </enumeratedValue>
              </enumeratedValues>
            </field>
            <field>
              <name>MR_VSEL</name>
              <bitRange>[17:16]</bitRange>
              <enumeratedValues>
                <enumeratedValue>
                  <name>0</name>
                  <value>1</value>
                </enumeratedValue>
                <enumeratedValue>
                  <name>1</name>
                  <value>2</value>
                </enumeratedValue>
              </enumeratedValues>
            </field>
            <field>
              <name>LPR_VSEL</name>
              <bitRange>[19:18]</bitRange>
              <enumeratedValues>
                <enumeratedValue>
                  <name>0</name>
                  <value>1</value>
                </enumeratedValue>
                <enumeratedValue>
                  <name>1</name>
                  <value>2</value>
                </enumeratedValue>
              </enumeratedValues>
            </field>
            <field>
              <name>DLPR_VSEL</name>
              <bitRange>[21:20]</bitRange>
              <enumeratedValues>
                <enumeratedValue>
                  <name>0</name>
                  <value>1</value>
                </enumeratedValue>
                <enumeratedValue>
                  <name>1</name>
                  <value>2</value>
                </enumeratedValue>
              </enumeratedValues>
            </field>
            <field>
              <name>FLSSLP_CTRL</name>
              <bitRange>[24:24]</bitRange>
            </field>
            <field>
              <name>HSION_CTRL</name>
              <bitRange>[25:25]</bitRange>
            </field>
            <field>
              <name>STDBY_MRRDY_WAIT</name>
              <bitRange>[27:26]</bitRange>
              <enumeratedValues>
                <enumeratedValue>
                  <name>0</name>
                  <value>1</value>
                </enumeratedValue>
                <enumeratedValue>
                  <name>1</name>
                  <value>2</value>
                </enumeratedValue>
              </enumeratedValues>
            </field>
          </fields>
        </register>
        <register>
          <name>CR2</name>
          <description>Power control register 2</description>
          <addressOffset>0x4</addressOffset>
          <fields>
            <field>
              <name>PVDE</name>
              <bitRange>[0:0]</bitRange>
            </field>
            <field>
              <name>PVDT</name>
              <bitRange>[6:4]</bitRange>
              <enumeratedValues>
                <enumeratedValue>
                  <name>1V8</name>
                  <value>0</value>
                </enumeratedValue>
                <enumeratedValue>
                  <name>0</name>
                  <value>1</value>
                </enumeratedValue>
                <enumeratedValue>
                  <name>2V0</name>
                  <value>1</value>
                </enumeratedValue>
                <enumeratedValue>
                  <name>1</name>
                  <value>2</value>
                </enumeratedValue>
                <enumeratedValue>
                  <name>2V2</name>
                  <value>2</value>
                </enumeratedValue>
                <enumeratedValue>
                  <name>2V4</name>
                  <value>3</value>
                </enumeratedValue>
                <enumeratedValue>
                  <name>2</name>
                  <value>4</value>
                </enumeratedValue>
                <enumeratedValue>
                  <name>2V8</name>
                  <value>4</value>
                </enumeratedValue>
                <enumeratedValue>
                  <name>3V1</name>
                  <value>5</value>
                </enumeratedValue>
                <enumeratedValue>
                  <name>3V7</name>
                  <value>6</value>
                </enumeratedValue>
                <enumeratedValue>
                  <name>4V2</name>
                  <value>7</value>
                </enumeratedValue>
              </enumeratedValues>
            </field>
            <field>
              <name>PVD_OUT_SEL</name>
              <bitRange>[7:7]</bitRange>
            </field>
            <field>
              <name>FLTEN</name>
              <bitRange>[8:8]</bitRange>
            </field>
            <field>
              <name>FLT_TIME</name>
              <bitRange>[11:9]</bitRange>
              <enumeratedValues>
                <enumeratedValue>
                  <name>0</name>
                  <value>1</value>
                </enumeratedValue>
                <enumeratedValue>
                  <name>1</name>
                  <value>2</value>
                </enumeratedValue>
                <enumeratedValue>
                  <name>2</name>
                  <value>4</value>
                </enumeratedValue>
              </enumeratedValues>
            </field>
          </fields>
        </register>
        <register>
          <name>CR3</name>
          <addressOffset>0x8</addressOffset>
          <fields>
            <field>
              <name>EWUP0</name>
              <bitRange>[0:0]</bitRange>
            </field>
            <field>
              <name>EWUP1</name>
              <bitRange>[1:1]</bitRange>
            </field>
            <field>
              <name>EWUP2</name>
              <bitRange>[2:2]</bitRange>
            </field>
            <field>
              <name>EWUP3</name>
              <bitRange>[3:3]</bitRange>
            </field>
            <field>
              <name>EWUP4</name>
              <bitRange>[4:4]</bitRange>
            </field>
            <field>
              <name>EWUP5</name>
              <bitRange>[5:5]</bitRange>
            </field>
            <field>
              <name>EWUP6</name>
              <bitRange>[6:6]</bitRange>
            </field>
            <field>
              <name>EWUP7</name>
              <bitRange>[7:7]</bitRange>
            </field>
            <field>
              <name>LD_EN</name>
              <bitRange>[8:8]</bitRange>
            </field>
            <field>
              <name>APC</name>
              <bitRange>[9:9]</bitRange>
            </field>
            <field>
              <name>SRAM1PDSTD</name>
              <bitRange>[10:10]</bitRange>
            </field>
          </fields>
        </register>
        <register>
          <name>CR4</name>
          <addressOffset>0xC</addressOffset>
          <fields>
            <field>
              <name>WP0</name>
              <bitRange>[1:0]</bitRange>
              <enumeratedValues>
                <enumeratedValue>
                  <name>0</name>
                  <value>1</value>
                </enumeratedValue>
                <enumeratedValue>
                  <name>1</name>
                  <value>2</value>
                </enumeratedValue>
              </enumeratedValues>
            </field>
            <field>
              <name>WP1</name>
              <bitRange>[3:2]</bitRange>
              <enumeratedValues>
                <enumeratedValue>
                  <name>0</name>
                  <value>1</value>
                </enumeratedValue>
                <enumeratedValue>
                  <name>1</name>
                  <value>2</value>
                </enumeratedValue>
              </enumeratedValues>
            </field>
            <field>
              <name>WP2</name>
              <bitRange>[5:4]</bitRange>
              <enumeratedValues>
                <enumeratedValue>
                  <name>0</name>
                  <value>1</value>
                </enumeratedValue>
                <enumeratedValue>
                  <name>1</name>
                  <value>2</value>
                </enumeratedValue>
              </enumeratedValues>
            </field>
            <field>
              <name>WP3</name>
              <bitRange>[7:6]</bitRange>
              <enumeratedValues>
                <enumeratedValue>
                  <name>0</name>
                  <value>1</value>
                </enumeratedValue>
                <enumeratedValue>
                  <name>1</name>
                  <value>2</value>
                </enumeratedValue>
              </enumeratedValues>
            </field>
            <field>
              <name>WP4</name>
              <bitRange>[9:8]</bitRange>
              <enumeratedValues>
                <enumeratedValue>
                  <name>0</name>
                  <value>1</value>
                </enumeratedValue>
                <enumeratedValue>
                  <name>1</name>
                  <value>2</value>
                </enumeratedValue>
              </enumeratedValues>
            </field>
            <field>
              <name>WP5</name>
              <bitRange>[11:10]</bitRange>
              <enumeratedValues>
                <enumeratedValue>
                  <name>0</name>
                  <value>1</value>
                </enumeratedValue>
                <enumeratedValue>
                  <name>1</name>
                  <value>2</value>
                </enumeratedValue>
              </enumeratedValues>
            </field>
            <field>
              <name>WP6</name>
              <bitRange>[13:12]</bitRange>
              <enumeratedValues>
                <enumeratedValue>
                  <name>0</name>
                  <value>1</value>
                </enumeratedValue>
                <enumeratedValue>
                  <name>1</name>
                  <value>2</value>
                </enumeratedValue>
              </enumeratedValues>
            </field>
            <field>
              <name>WP7</name>
              <bitRange>[15:14]</bitRange>
              <enumeratedValues>
                <enumeratedValue>
                  <name>0</name>
                  <value>1</value>
                </enumeratedValue>
                <enumeratedValue>
                  <name>1</name>
                  <value>2</value>
                </enumeratedValue>
              </enumeratedValues>
            </field>
          </fields>
        </register>
        <register>
          <name>SR</name>
          <description>Power status register</description>
          <addressOffset>0x10</addressOffset>
          <fields>
            <field>
              <name>WUF0</name>
              <bitRange>[0:0]</bitRange>
              <access>read-only</access>
            </field>
            <field>
              <name>WUF1</name>
              <bitRange>[1:1]</bitRange>
              <access>read-only</access>
            </field>
            <field>
              <name>WUF2</name>
              <bitRange>[2:2]</bitRange>
              <access>read-only</access>
            </field>
            <field>
              <name>WUF3</name>
              <bitRange>[3:3]</bitRange>
              <access>read-only</access>
            </field>
            <field>
              <name>WUF4</name>
              <bitRange>[4:4]</bitRange>
              <access>read-only</access>
            </field>
            <field>
              <name>WUF5</name>
              <bitRange>[5:5]</bitRange>
              <access>read-only</access>
            </field>
            <field>
              <name>WUF6</name>
              <bitRange>[6:6]</bitRange>
              <access>read-only</access>
            </field>
            <field>
              <name>WUF7</name>
              <bitRange>[7:7]</bitRange>
              <access>read-only</access>
            </field>
            <field>
              <name>SBF</name>
              <bitRange>[8:8]</bitRange>
              <access>read-only</access>
            </field>
            <field>
              <name>MR_RDY</name>
              <bitRange>[9:9]</bitRange>
              <access>read-only</access>
            </field>
            <field>
              <name>MR_VOS_RDY</name>
              <bitRange>[10:10]</bitRange>
              <access>read-only</access>
            </field>
            <field>
              <name>LPRUN_RUN_SWF</name>
              <bitRange>[11:11]</bitRange>
              <access>read-only</access>
            </field>
            <field>
              <name>IWDGRST_WUF</name>
              <bitRange>[12:12]</bitRange>
              <access>read-only</access>
            </field>
            <field>
              <name>PINRST_WUF</name>
              <bitRange>[13:13]</bitRange>
              <access>read-only</access>
            </field>
            <field>
              <name>VCC_PORF</name>
              <bitRange>[14:14]</bitRange>
              <access>read-only</access>
            </field>
            <field>
              <name>PVDO</name>
              <bitRange>[16:16]</bitRange>
              <access>read-only</access>
            </field>
          </fields>
        </register>
        <register>
          <name>SCR</name>
          <addressOffset>0x14</addressOffset>
          <fields>
            <field>
              <name>CWUF0</name>
              <bitRange>[0:0]</bitRange>
              <access>write-only</access>
            </field>
            <field>
              <name>CWUF1</name>
              <bitRange>[1:1]</bitRange>
              <access>write-only</access>
            </field>
            <field>
              <name>CWUF2</name>
              <bitRange>[2:2]</bitRange>
              <access>write-only</access>
            </field>
            <field>
              <name>CWUF3</name>
              <bitRange>[3:3]</bitRange>
              <access>write-only</access>
            </field>
            <field>
              <name>CWUF4</name>
              <bitRange>[4:4]</bitRange>
              <access>write-only</access>
            </field>
            <field>
              <name>CWUF5</name>
              <bitRange>[5:5]</bitRange>
              <access>write-only</access>
            </field>
            <field>
              <name>CWUF6</name>
              <bitRange>[6:6]</bitRange>
              <access>write-only</access>
            </field>
            <field>
              <name>CWUF7</name>
              <bitRange>[7:7]</bitRange>
              <access>write-only</access>
            </field>
            <field>
              <name>CSBF</name>
              <bitRange>[8:8]</bitRange>
              <access>write-only</access>
            </field>
            <field>
              <name>CIWDGRSTWUF</name>
              <bitRange>[12:12]</bitRange>
              <access>write-only</access>
            </field>
            <field>
              <name>CPINRSTWUF</name>
              <bitRange>[13:13]</bitRange>
              <access>write-only</access>
            </field>
            <field>
              <name>CVCCPORF</name>
              <bitRange>[14:14]</bitRange>
              <access>write-only</access>
            </field>
          </fields>
        </register>
        <register>
          <name>PUCRA</name>
          <addressOffset>0x20</addressOffset>
          <fields>
            <field>
              <name>PU0</name>
              <bitRange>[0:0]</bitRange>
            </field>
            <field>
              <name>PU1</name>
              <bitRange>[1:1]</bitRange>
            </field>
            <field>
              <name>PU2</name>
              <bitRange>[2:2]</bitRange>
            </field>
            <field>
              <name>PU3</name>
              <bitRange>[3:3]</bitRange>
            </field>
            <field>
              <name>PU4</name>
              <bitRange>[4:4]</bitRange>
            </field>
            <field>
              <name>PU5</name>
              <bitRange>[5:5]</bitRange>
            </field>
            <field>
              <name>PU6</name>
              <bitRange>[6:6]</bitRange>
            </field>
            <field>
              <name>PU7</name>
              <bitRange>[7:7]</bitRange>
            </field>
            <field>
              <name>PU8</name>
              <bitRange>[8:8]</bitRange>
            </field>
            <field>
              <name>PU9</name>
              <bitRange>[9:9]</bitRange>
            </field>
            <field>
              <name>PU10</name>
              <bitRange>[10:10]</bitRange>
            </field>
            <field>
              <name>PU11</name>
              <bitRange>[11:11]</bitRange>
            </field>
            <field>
              <name>PU12</name>
              <bitRange>[12:12]</bitRange>
            </field>
            <field>
              <name>PU13</name>
              <bitRange>[13:13]</bitRange>
            </field>
            <field>
              <name>PU14</name>
              <bitRange>[14:14]</bitRange>
            </field>
            <field>
              <name>PU15</name>
              <bitRange>[15:15]</bitRange>
            </field>
          </fields>
        </register>
        <register>
          <name>PDCRA</name>
          <addressOffset>0x24</addressOffset>
          <fields>
            <field>
              <name>PD0</name>
              <bitRange>[0:0]</bitRange>
            </field>
            <field>
              <name>PD1</name>
              <bitRange>[1:1]</bitRange>
            </field>
            <field>
              <name>PD2</name>
              <bitRange>[2:2]</bitRange>
            </field>
            <field>
              <name>PD3</name>
              <bitRange>[3:3]</bitRange>
            </field>
            <field>
              <name>PD4</name>
              <bitRange>[4:4]</bitRange>
            </field>
            <field>
              <name>PD5</name>
              <bitRange>[5:5]</bitRange>
            </field>
            <field>
              <name>PD6</name>
              <bitRange>[6:6]</bitRange>
            </field>
            <field>
              <name>PD7</name>
              <bitRange>[7:7]</bitRange>
            </field>
            <field>
              <name>PD8</name>
              <bitRange>[8:8]</bitRange>
            </field>
            <field>
              <name>PD9</name>
              <bitRange>[9:9]</bitRange>
            </field>
            <field>
              <name>PD10</name>
              <bitRange>[10:10]</bitRange>
            </field>
            <field>
              <name>PD11</name>
              <bitRange>[11:11]</bitRange>
            </field>
            <field>
              <name>PD12</name>
              <bitRange>[12:12]</bitRange>
            </field>
            <field>
              <name>PD13</name>
              <bitRange>[13:13]</bitRange>
            </field>
            <field>
              <name>PD14</name>
              <bitRange>[14:14]</bitRange>
            </field>
            <field>
              <name>PD15</name>
              <bitRange>[15:15]</bitRange>
            </field>
          </fields>
        </register>
        <register>
          <name>PUCRB</name>
          <addressOffset>0x28</addressOffset>
          <fields>
            <field>
              <name>PU0</name>
              <bitRange>[0:0]</bitRange>
            </field>
            <field>
              <name>PU1</name>
              <bitRange>[1:1]</bitRange>
            </field>
            <field>
              <name>PU2</name>
              <bitRange>[2:2]</bitRange>
            </field>
            <field>
              <name>PU3</name>
              <bitRange>[3:3]</bitRange>
            </field>
            <field>
              <name>PU4</name>
              <bitRange>[4:4]</bitRange>
            </field>
            <field>
              <name>PU5</name>
              <bitRange>[5:5]</bitRange>
            </field>
            <field>
              <name>PU6</name>
              <bitRange>[6:6]</bitRange>
            </field>
            <field>
              <name>PU7</name>
              <bitRange>[7:7]</bitRange>
            </field>
            <field>
              <name>PU8</name>
              <bitRange>[8:8]</bitRange>
            </field>
            <field>
              <name>PU9</name>
              <bitRange>[9:9]</bitRange>
            </field>
            <field>
              <name>PU10</name>
              <bitRange>[10:10]</bitRange>
            </field>
            <field>
              <name>PU11</name>
              <bitRange>[11:11]</bitRange>
            </field>
            <field>
              <name>PU12</name>
              <bitRange>[12:12]</bitRange>
            </field>
            <field>
              <name>PU13</name>
              <bitRange>[13:13]</bitRange>
            </field>
            <field>
              <name>PU14</name>
              <bitRange>[14:14]</bitRange>
            </field>
            <field>
              <name>PU15</name>
              <bitRange>[15:15]</bitRange>
            </field>
          </fields>
        </register>
        <register>
          <name>PDCRB</name>
          <addressOffset>0x2C</addressOffset>
          <fields>
            <field>
              <name>PD0</name>
              <bitRange>[0:0]</bitRange>
            </field>
            <field>
              <name>PD1</name>
              <bitRange>[1:1]</bitRange>
            </field>
            <field>
              <name>PD2</name>
              <bitRange>[2:2]</bitRange>
            </field>
            <field>
              <name>PD3</name>
              <bitRange>[3:3]</bitRange>
            </field>
            <field>
              <name>PD4</name>
              <bitRange>[4:4]</bitRange>
            </field>
            <field>
              <name>PD5</name>
              <bitRange>[5:5]</bitRange>
            </field>
            <field>
              <name>PD6</name>
              <bitRange>[6:6]</bitRange>
            </field>
            <field>
              <name>PD7</name>
              <bitRange>[7:7]</bitRange>
            </field>
            <field>
              <name>PD8</name>
              <bitRange>[8:8]</bitRange>
            </field>
            <field>
              <name>PD9</name>
              <bitRange>[9:9]</bitRange>
            </field>
            <field>
              <name>PD10</name>
              <bitRange>[10:10]</bitRange>
            </field>
            <field>
              <name>PD11</name>
              <bitRange>[11:11]</bitRange>
            </field>
            <field>
              <name>PD12</name>
              <bitRange>[12:12]</bitRange>
            </field>
            <field>
              <name>PD13</name>
              <bitRange>[13:13]</bitRange>
            </field>
            <field>
              <name>PD14</name>
              <bitRange>[14:14]</bitRange>
            </field>
            <field>
              <name>PD15</name>
              <bitRange>[15:15]</bitRange>
            </field>
          </fields>
        </register>
        <register>
          <name>PUCRC</name>
          <addressOffset>0x30</addressOffset>
          <fields>
            <field>
              <name>PU0</name>
              <bitRange>[0:0]</bitRange>
            </field>
            <field>
              <name>PU1</name>
              <bitRange>[1:1]</bitRange>
            </field>
            <field>
              <name>PU2</name>
              <bitRange>[2:2]</bitRange>
            </field>
            <field>
              <name>PU3</name>
              <bitRange>[3:3]</bitRange>
            </field>
            <field>
              <name>PU4</name>
              <bitRange>[4:4]</bitRange>
            </field>
            <field>
              <name>PU5</name>
              <bitRange>[5:5]</bitRange>
            </field>
            <field>
              <name>PU6</name>
              <bitRange>[6:6]</bitRange>
            </field>
            <field>
              <name>PU7</name>
              <bitRange>[7:7]</bitRange>
            </field>
            <field>
              <name>PU8</name>
              <bitRange>[8:8]</bitRange>
            </field>
            <field>
              <name>PU9</name>
              <bitRange>[9:9]</bitRange>
            </field>
            <field>
              <name>PU10</name>
              <bitRange>[10:10]</bitRange>
            </field>
            <field>
              <name>PU11</name>
              <bitRange>[11:11]</bitRange>
            </field>
            <field>
              <name>PU12</name>
              <bitRange>[12:12]</bitRange>
            </field>
            <field>
              <name>PU13</name>
              <bitRange>[13:13]</bitRange>
            </field>
            <field>
              <name>PU14</name>
              <bitRange>[14:14]</bitRange>
            </field>
            <field>
              <name>PU15</name>
              <bitRange>[15:15]</bitRange>
            </field>
          </fields>
        </register>
        <register>
          <name>PDCRC</name>
          <addressOffset>0x34</addressOffset>
          <fields>
            <field>
              <name>PD0</name>
              <bitRange>[0:0]</bitRange>
            </field>
            <field>
              <name>PD1</name>
              <bitRange>[1:1]</bitRange>
            </field>
            <field>
              <name>PD2</name>
              <bitRange>[2:2]</bitRange>
            </field>
            <field>
              <name>PD3</name>
              <bitRange>[3:3]</bitRange>
            </field>
            <field>
              <name>PD4</name>
              <bitRange>[4:4]</bitRange>
            </field>
            <field>
              <name>PD5</name>
              <bitRange>[5:5]</bitRange>
            </field>
            <field>
              <name>PD6</name>
              <bitRange>[6:6]</bitRange>
            </field>
            <field>
              <name>PD7</name>
              <bitRange>[7:7]</bitRange>
            </field>
            <field>
              <name>PD8</name>
              <bitRange>[8:8]</bitRange>
            </field>
            <field>
              <name>PD9</name>
              <bitRange>[9:9]</bitRange>
            </field>
            <field>
              <name>PD10</name>
              <bitRange>[10:10]</bitRange>
            </field>
            <field>
              <name>PD11</name>
              <bitRange>[11:11]</bitRange>
            </field>
            <field>
              <name>PD12</name>
              <bitRange>[12:12]</bitRange>
            </field>
            <field>
              <name>PD13</name>
              <bitRange>[13:13]</bitRange>
            </field>
            <field>
              <name>PD14</name>
              <bitRange>[14:14]</bitRange>
            </field>
            <field>
              <name>PD15</name>
              <bitRange>[15:15]</bitRange>
            </field>
          </fields>
        </register>
        <register>
          <name>PUCRD</name>
          <addressOffset>0x38</addressOffset>
          <fields>
            <field>
              <name>PU0</name>
              <bitRange>[0:0]</bitRange>
            </field>
            <field>
              <name>PU1</name>
              <bitRange>[1:1]</bitRange>
            </field>
            <field>
              <name>PU2</name>
              <bitRange>[2:2]</bitRange>
            </field>
            <field>
              <name>PU3</name>
              <bitRange>[3:3]</bitRange>
            </field>
            <field>
              <name>PU4</name>
              <bitRange>[4:4]</bitRange>
            </field>
            <field>
              <name>PU5</name>
              <bitRange>[5:5]</bitRange>
            </field>
            <field>
              <name>PU6</name>
              <bitRange>[6:6]</bitRange>
            </field>
            <field>
              <name>PU7</name>
              <bitRange>[7:7]</bitRange>
            </field>
            <field>
              <name>PU8</name>
              <bitRange>[8:8]</bitRange>
            </field>
            <field>
              <name>PU9</name>
              <bitRange>[9:9]</bitRange>
            </field>
            <field>
              <name>PU10</name>
              <bitRange>[10:10]</bitRange>
            </field>
            <field>
              <name>PU11</name>
              <bitRange>[11:11]</bitRange>
            </field>
            <field>
              <name>PU12</name>
              <bitRange>[12:12]</bitRange>
            </field>
            <field>
              <name>PU13</name>
              <bitRange>[13:13]</bitRange>
            </field>
            <field>
              <name>PU14</name>
              <bitRange>[14:14]</bitRange>
            </field>
            <field>
              <name>PU15</name>
              <bitRange>[15:15]</bitRange>
            </field>
          </fields>
        </register>
        <register>
          <name>PDCRD</name>
          <addressOffset>0x3C</addressOffset>
          <fields>
            <field>
              <name>PD0</name>
              <bitRange>[0:0]</bitRange>
            </field>
            <field>
              <name>PD1</name>
              <bitRange>[1:1]</bitRange>
            </field>
            <field>
              <name>PD2</name>
              <bitRange>[2:2]</bitRange>
            </field>
            <field>
              <name>PD3</name>
              <bitRange>[3:3]</bitRange>
            </field>
            <field>
              <name>PD4</name>
              <bitRange>[4:4]</bitRange>
            </field>
            <field>
              <name>PD5</name>
              <bitRange>[5:5]</bitRange>
            </field>
            <field>
              <name>PD6</name>
              <bitRange>[6:6]</bitRange>
            </field>
            <field>
              <name>PD7</name>
              <bitRange>[7:7]</bitRange>
            </field>
            <field>
              <name>PD8</name>
              <bitRange>[8:8]</bitRange>
            </field>
            <field>
              <name>PD9</name>
              <bitRange>[9:9]</bitRange>
            </field>
            <field>
              <name>PD10</name>
              <bitRange>[10:10]</bitRange>
            </field>
            <field>
              <name>PD11</name>
              <bitRange>[11:11]</bitRange>
            </field>
            <field>
              <name>PD12</name>
              <bitRange>[12:12]</bitRange>
            </field>
            <field>
              <name>PD13</name>
              <bitRange>[13:13]</bitRange>
            </field>
            <field>
              <name>PD14</name>
              <bitRange>[14:14]</bitRange>
            </field>
            <field>
              <name>PD15</name>
              <bitRange>[15:15]</bitRange>
            </field>
          </fields>
        </register>
      </registers>
    </peripheral>
    <peripheral>
      <name>RCC</name>
      <description>Reset and clock control</description>
      <baseAddress>0x40021000</baseAddress>
      <addressBlock>
        <offset>0x0</offset>
        <size>0x400</size>
        <usage>registers</usage>
      </addressBlock>
      <interrupt>
        <name>RCC_CTC</name>
        <description>RCC and CTC global Interrupts</description>
        <value>4</value>
      </interrupt>
      <registers>
        <register>
          <name>CR</name>
          <description>Clock control register</description>
          <addressOffset>0x0</addressOffset>
          <fields>
            <field>
              <name>MSIDIV</name>
              <bitRange>[2:0]</bitRange>
              <enumeratedValues>
                <enumeratedValue>
                  <name>0</name>
                  <value>1</value>
                </enumeratedValue>
                <enumeratedValue>
                  <name>1</name>
                  <value>2</value>
                </enumeratedValue>
                <enumeratedValue>
                  <name>2</name>
                  <value>4</value>
                </enumeratedValue>
              </enumeratedValues>
            </field>
            <field>
              <name>HSIKERON</name>
              <bitRange>[6:6]</bitRange>
            </field>
            <field>
              <name>MSION</name>
              <bitRange>[7:7]</bitRange>
            </field>
            <field>
              <name>HSION</name>
              <bitRange>[8:8]</bitRange>
            </field>
            <field>
              <name>MSIRDY</name>
              <bitRange>[9:9]</bitRange>
              <access>read-only</access>
            </field>
            <field>
              <name>HSIRDY</name>
              <bitRange>[10:10]</bitRange>
              <access>read-only</access>
            </field>
            <field>
              <name>HSIDIV</name>
              <bitRange>[13:11]</bitRange>
              <enumeratedValues>
                <enumeratedValue>
                  <name>0</name>
                  <value>1</value>
                </enumeratedValue>
                <enumeratedValue>
                  <name>1</name>
                  <value>2</value>
                </enumeratedValue>
                <enumeratedValue>
                  <name>2</name>
                  <value>4</value>
                </enumeratedValue>
              </enumeratedValues>
            </field>
            <field>
              <name>HSEON</name>
              <bitRange>[16:16]</bitRange>
            </field>
            <field>
              <name>HSERDY</name>
              <bitRange>[17:17]</bitRange>
              <access>read-only</access>
            </field>
            <field>
              <name>HSEBYP</name>
              <bitRange>[18:18]</bitRange>
            </field>
            <field>
              <name>HSE_CSSON</name>
              <bitRange>[19:19]</bitRange>
            </field>
            <field>
              <name>PLLON</name>
              <bitRange>[24:24]</bitRange>
            </field>
            <field>
              <name>PLLRDY</name>
              <bitRange>[25:25]</bitRange>
              <access>read-only</access>
            </field>
          </fields>
        </register>
        <register>
          <name>ICSCR</name>
          <description>Internal clock sources calibration register</description>
          <addressOffset>0x4</addressOffset>
          <fields>
            <field>
              <name>HSI_TRIMCR</name>
              <bitRange>[12:0]</bitRange>
            </field>
            <field>
              <name>HSI_FS_OP</name>
              <bitRange>[15:13]</bitRange>
            </field>
          </fields>
        </register>
        <register>
          <name>CFGR</name>
          <description>Clock configuration register</description>
          <addressOffset>0x8</addressOffset>
          <fields>
            <field>
              <name>SW</name>
              <bitRange>[2:0]</bitRange>
              <enumeratedValues>
                <enumeratedValue>
                  <name>HSISYS</name>
                  <description>HSI selected as system clock</description>
                  <value>0</value>
                </enumeratedValue>
                <enumeratedValue>
                  <name>0</name>
                  <value>1</value>
                </enumeratedValue>
                <enumeratedValue>
                  <name>HSE</name>
                  <description>HSE selected as system clock</description>
                  <value>1</value>
                </enumeratedValue>
                <enumeratedValue>
                  <name>1</name>
                  <value>2</value>
                </enumeratedValue>
                <enumeratedValue>
                  <name>PLL</name>
                  <value>2</value>
                </enumeratedValue>
                <enumeratedValue>
                  <name>LSI</name>
                  <value>3</value>
                </enumeratedValue>
                <enumeratedValue>
                  <name>2</name>
                  <value>4</value>
                </enumeratedValue>
                <enumeratedValue>
                  <name>LSE</name>
                  <value>4</value>
                </enumeratedValue>
                <enumeratedValue>
                  <name>MSISYS</name>
                  <value>5</value>
                </enumeratedValue>
              </enumeratedValues>
            </field>
            <field>
              <name>SWS</name>
              <bitRange>[5:3]</bitRange>
              <enumeratedValues>
                <enumeratedValue>
                  <name>HSISYS</name>
                  <description>HSISYS used as system clock</description>
                  <value>0</value>
                </enumeratedValue>
                <enumeratedValue>
                  <name>0</name>
                  <value>1</value>
                </enumeratedValue>
                <enumeratedValue>
                  <name>HSE</name>
                  <description>HSE used as system clock</description>
                  <value>1</value>
                </enumeratedValue>
                <enumeratedValue>
                  <name>1</name>
                  <value>2</value>
                </enumeratedValue>
                <enumeratedValue>
                  <name>PLL</name>
                  <description>PLL used as system clock</description>
                  <value>2</value>
                </enumeratedValue>
                <enumeratedValue>
                  <name>LSI</name>
                  <description>LSI used as system clock</description>
                  <value>3</value>
                </enumeratedValue>
                <enumeratedValue>
                  <name>2</name>
                  <value>4</value>
                </enumeratedValue>
                <enumeratedValue>
                  <name>LSE</name>
                  <description>LSE used as system clock</description>
                  <value>4</value>
                </enumeratedValue>
                <enumeratedValue>
                  <name>MSISYS</name>
                  <description>MSISYS used as system clock</description>
                  <value>5</value>
                </enumeratedValue>
              </enumeratedValues>
            </field>
            <field>
              <name>HPRE</name>
              <bitRange>[11:8]</bitRange>
              <enumeratedValues>
                <enumeratedValue>
                  <name>0</name>
                  <value>1</value>
                </enumeratedValue>
                <enumeratedValue>
                  <name>1</name>
                  <value>2</value>
                </enumeratedValue>
                <enumeratedValue>
                  <name>2</name>
                  <value>4</value>
                </enumeratedValue>
                <enumeratedValue>
                  <name>3</name>
                  <value>8</value>
                </enumeratedValue>
              </enumeratedValues>
            </field>
            <field>
              <name>PPRE</name>
              <bitRange>[14:12]</bitRange>
              <enumeratedValues>
                <enumeratedValue>
                  <name>0</name>
                  <value>1</value>
                </enumeratedValue>
                <enumeratedValue>
                  <name>1</name>
                  <value>2</value>
                </enumeratedValue>
                <enumeratedValue>
                  <name>2</name>
                  <value>4</value>
                </enumeratedValue>
              </enumeratedValues>
            </field>
            <field>
              <name>MCOSEL</name>
              <bitRange>[27:24]</bitRange>
              <enumeratedValues>
                <enumeratedValue>
                  <name>0</name>
                  <value>1</value>
                </enumeratedValue>
                <enumeratedValue>
                  <name>1</name>
                  <value>2</value>
                </enumeratedValue>
                <enumeratedValue>
                  <name>2</name>
                  <value>4</value>
                </enumeratedValue>
                <enumeratedValue>
                  <name>3</name>
                  <value>8</value>
                </enumeratedValue>
              </enumeratedValues>
            </field>
            <field>
              <name>MCOPRE</name>
              <bitRange>[31:28]</bitRange>
              <enumeratedValues>
                <enumeratedValue>
                  <name>0</name>
                  <value>1</value>
                </enumeratedValue>
                <enumeratedValue>
                  <name>1</name>
                  <value>2</value>
                </enumeratedValue>
                <enumeratedValue>
                  <name>2</name>
                  <value>4</value>
                </enumeratedValue>
                <enumeratedValue>
                  <name>3</name>
                  <value>8</value>
                </enumeratedValue>
              </enumeratedValues>
            </field>
          </fields>
        </register>
        <register>
          <name>PLLCFGR</name>
          <description>PLL configuration register</description>
          <addressOffset>0xC</addressOffset>
          <fields>
            <field>
              <name>PLLSRC</name>
              <bitRange>[0:0]</bitRange>
            </field>
            <field>
              <name>PLLMUL</name>
              <bitRange>[6:2]</bitRange>
              <enumeratedValues>
                <enumeratedValue>
                  <name>0</name>
                  <value>1</value>
                </enumeratedValue>
                <enumeratedValue>
                  <name>1</name>
                  <value>2</value>
                </enumeratedValue>
                <enumeratedValue>
                  <name>2</name>
                  <value>4</value>
                </enumeratedValue>
                <enumeratedValue>
                  <name>3</name>
                  <value>8</value>
                </enumeratedValue>
                <enumeratedValue>
                  <name>4</name>
                  <value>16</value>
                </enumeratedValue>
              </enumeratedValues>
            </field>
          </fields>
        </register>
        <register>
          <name>ECSCR</name>
          <description>External clock source control register</description>
          <addressOffset>0x10</addressOffset>
          <fields>
            <field>
              <name>HSE_DRV</name>
              <bitRange>[1:0]</bitRange>
              <enumeratedValues>
                <enumeratedValue>
                  <name>0</name>
                  <value>1</value>
                </enumeratedValue>
                <enumeratedValue>
                  <name>1</name>
                  <value>2</value>
                </enumeratedValue>
              </enumeratedValues>
            </field>
            <field>
              <name>HSE_RDYSEL</name>
              <bitRange>[3:2]</bitRange>
              <enumeratedValues>
                <enumeratedValue>
                  <name>0</name>
                  <value>1</value>
                </enumeratedValue>
                <enumeratedValue>
                  <name>1</name>
                  <value>2</value>
                </enumeratedValue>
              </enumeratedValues>
            </field>
            <field>
              <name>HSE_FILT_EN</name>
              <bitRange>[4:4]</bitRange>
            </field>
          </fields>
        </register>
        <register>
          <name>CIER</name>
          <description>Clock interrupt enable register</description>
          <addressOffset>0x18</addressOffset>
          <fields>
            <field>
              <name>LSIRDYIE</name>
              <bitRange>[0:0]</bitRange>
            </field>
            <field>
              <name>LSERDYIE</name>
              <bitRange>[1:1]</bitRange>
            </field>
            <field>
              <name>MSIRDYIE</name>
              <bitRange>[2:2]</bitRange>
            </field>
            <field>
              <name>HSIRDYIE</name>
              <bitRange>[3:3]</bitRange>
            </field>
            <field>
              <name>HSERDYIE</name>
              <bitRange>[4:4]</bitRange>
            </field>
            <field>
              <name>PLLRDYIE</name>
              <bitRange>[5:5]</bitRange>
            </field>
          </fields>
        </register>
        <register>
          <name>CIFR</name>
          <description>Clock interrupt flag register</description>
          <addressOffset>0x1C</addressOffset>
          <fields>
            <field>
              <name>LSIRDYF</name>
              <bitRange>[0:0]</bitRange>
              <access>read-only</access>
            </field>
            <field>
              <name>LSERDYF</name>
              <bitRange>[1:1]</bitRange>
              <access>read-only</access>
            </field>
            <field>
              <name>HSIRDYF</name>
              <bitRange>[3:3]</bitRange>
              <access>read-only</access>
            </field>
            <field>
              <name>HSERDYF</name>
              <bitRange>[4:4]</bitRange>
              <access>read-only</access>
            </field>
            <field>
              <name>PLLRDYF</name>
              <bitRange>[5:5]</bitRange>
              <access>read-only</access>
            </field>
            <field>
              <name>CSSF</name>
              <bitRange>[8:8]</bitRange>
              <access>read-only</access>
            </field>
            <field>
              <name>LSECSSF</name>
              <bitRange>[9:9]</bitRange>
              <access>read-only</access>
            </field>
          </fields>
        </register>
        <register>
          <name>CICR</name>
          <description>Clock interrupt clear register</description>
          <addressOffset>0x20</addressOffset>
          <fields>
            <field>
              <name>LSIRDYC</name>
              <bitRange>[0:0]</bitRange>
              <access>write-only</access>
            </field>
            <field>
              <name>LSERDYC</name>
              <bitRange>[1:1]</bitRange>
              <access>write-only</access>
            </field>
            <field>
              <name>HSIRDYC</name>
              <bitRange>[3:3]</bitRange>
              <access>write-only</access>
            </field>
            <field>
              <name>HSERDYC</name>
              <bitRange>[4:4]</bitRange>
              <access>write-only</access>
            </field>
            <field>
              <name>PLLRDYC</name>
              <bitRange>[5:5]</bitRange>
              <access>write-only</access>
            </field>
            <field>
              <name>CSSC</name>
              <bitRange>[8:8]</bitRange>
              <access>write-only</access>
            </field>
            <field>
              <name>LSECSSC</name>
              <bitRange>[9:9]</bitRange>
              <access>write-only</access>
            </field>
          </fields>
        </register>
        <register>
          <name>IOPRSTR</name>
          <description>GPIO reset register</description>
          <addressOffset>0x24</addressOffset>
          <fields>
            <field>
              <name>GPIOARST</name>
              <bitRange>[0:0]</bitRange>
            </field>
            <field>
              <name>GPIOBRST</name>
              <bitRange>[1:1]</bitRange>
            </field>
            <field>
              <name>GPIOCRST</name>
              <bitRange>[2:2]</bitRange>
            </field>
            <field>
              <name>GPIODRST</name>
              <bitRange>[3:3]</bitRange>
            </field>
          </fields>
        </register>
        <register>
          <name>AHBRSTR</name>
          <description>AHB peripheral reset register</description>
          <addressOffset>0x28</addressOffset>
          <fields>
            <field>
              <name>DMARST</name>
              <bitRange>[0:0]</bitRange>
            </field>
            <field>
              <name>CRCRST</name>
              <bitRange>[12:12]</bitRange>
            </field>
          </fields>
        </register>
        <register>
          <name>APBRSTR1</name>
          <description>APB peripheral reset register 1</description>
          <addressOffset>0x2C</addressOffset>
          <fields>
            <field>
              <name>TIM2RST</name>
              <bitRange>[0:0]</bitRange>
            </field>
            <field>
              <name>TIM3RST</name>
              <bitRange>[1:1]</bitRange>
            </field>
            <field>
              <name>TIM6RST</name>
              <bitRange>[4:4]</bitRange>
            </field>
            <field>
              <name>TIM7RST</name>
              <bitRange>[5:5]</bitRange>
            </field>
            <field>
              <name>PWMRST</name>
              <bitRange>[6:6]</bitRange>
            </field>
            <field>
              <name>WWDGRST</name>
              <bitRange>[11:11]</bitRange>
            </field>
            <field>
              <name>SPI2RST</name>
              <bitRange>[14:14]</bitRange>
            </field>
            <field>
              <name>LPUART2RST</name>
              <bitRange>[16:16]</bitRange>
            </field>
            <field>
              <name>USART2RST</name>
              <bitRange>[17:17]</bitRange>
            </field>
            <field>
              <name>UART1RST</name>
              <bitRange>[18:18]</bitRange>
            </field>
            <field>
              <name>UART2RST</name>
              <bitRange>[19:19]</bitRange>
            </field>
            <field>
              <name>LPUART1RST</name>
              <bitRange>[20:20]</bitRange>
            </field>
            <field>
              <name>I2C1RST</name>
              <bitRange>[21:21]</bitRange>
            </field>
            <field>
              <name>I2C2RST</name>
              <bitRange>[22:22]</bitRange>
            </field>
            <field>
              <name>OPARST</name>
              <bitRange>[23:23]</bitRange>
            </field>
            <field>
              <name>DBGRST</name>
              <bitRange>[27:27]</bitRange>
            </field>
            <field>
              <name>PWRRST</name>
              <bitRange>[28:28]</bitRange>
            </field>
            <field>
              <name>DACRST</name>
              <bitRange>[29:29]</bitRange>
            </field>
            <field>
              <name>LPTIM2RST</name>
              <bitRange>[30:30]</bitRange>
            </field>
            <field>
              <name>LPTIM1RST</name>
              <bitRange>[31:31]</bitRange>
            </field>
          </fields>
        </register>
        <register>
          <name>APBRSTR2</name>
          <description>APB peripheral reset register 2</description>
          <addressOffset>0x30</addressOffset>
          <fields>
            <field>
              <name>SYSCFGRST</name>
              <bitRange>[0:0]</bitRange>
            </field>
            <field>
              <name>TIM1RST</name>
              <bitRange>[11:11]</bitRange>
            </field>
            <field>
              <name>SPI1RST</name>
              <bitRange>[12:12]</bitRange>
            </field>
            <field>
              <name>USART1RST</name>
              <bitRange>[14:14]</bitRange>
            </field>
            <field>
              <name>TIM15RST</name>
              <bitRange>[16:16]</bitRange>
            </field>
            <field>
              <name>TIM16RST</name>
              <bitRange>[17:17]</bitRange>
            </field>
            <field>
              <name>TIM17RST</name>
              <bitRange>[18:18]</bitRange>
            </field>
            <field>
              <name>ADCRST</name>
              <bitRange>[20:20]</bitRange>
            </field>
            <field>
              <name>COMP1RST</name>
              <bitRange>[21:21]</bitRange>
            </field>
            <field>
              <name>COMP2RST</name>
              <bitRange>[22:22]</bitRange>
            </field>
            <field>
              <name>LCDRST</name>
              <bitRange>[24:24]</bitRange>
            </field>
            <field>
              <name>TKRST</name>
              <bitRange>[25:25]</bitRange>
            </field>
            <field>
              <name>VREFBUFRST</name>
              <bitRange>[26:26]</bitRange>
            </field>
          </fields>
        </register>
        <register>
          <name>IOPENR</name>
          <description>GPIO clock enable register</description>
          <addressOffset>0x34</addressOffset>
          <fields>
            <field>
              <name>GPIOAEN</name>
              <bitRange>[0:0]</bitRange>
            </field>
            <field>
              <name>GPIOBEN</name>
              <bitRange>[1:1]</bitRange>
            </field>
            <field>
              <name>GPIOCEN</name>
              <bitRange>[2:2]</bitRange>
            </field>
            <field>
              <name>GPIODEN</name>
              <bitRange>[3:3]</bitRange>
            </field>
          </fields>
        </register>
        <register>
          <name>AHBENR</name>
          <description>AHB peripheral clock enable register</description>
          <addressOffset>0x38</addressOffset>
          <fields>
            <field>
              <name>DMAEN</name>
              <bitRange>[0:0]</bitRange>
            </field>
            <field>
              <name>FLASHEN</name>
              <bitRange>[8:8]</bitRange>
            </field>
            <field>
              <name>SRAMEN</name>
              <bitRange>[9:9]</bitRange>
            </field>
            <field>
              <name>CRCEN</name>
              <bitRange>[12:12]</bitRange>
            </field>
          </fields>
        </register>
        <register>
          <name>APBENR1</name>
          <description>APB peripheral clock enable register 1</description>
          <addressOffset>0x3C</addressOffset>
          <fields>
            <field>
              <name>TIM2EN</name>
              <bitRange>[0:0]</bitRange>
            </field>
            <field>
              <name>TIM3EN</name>
              <bitRange>[1:1]</bitRange>
            </field>
            <field>
              <name>TIM6EN</name>
              <bitRange>[4:4]</bitRange>
            </field>
            <field>
              <name>TIM7EN</name>
              <bitRange>[5:5]</bitRange>
            </field>
            <field>
              <name>PWMEN</name>
              <bitRange>[6:6]</bitRange>
            </field>
            <field>
              <name>WWDGEN</name>
              <bitRange>[11:11]</bitRange>
            </field>
            <field>
              <name>SPI2EN</name>
              <bitRange>[14:14]</bitRange>
            </field>
            <field>
              <name>LPUART2EN</name>
              <bitRange>[16:16]</bitRange>
            </field>
            <field>
              <name>USART2EN</name>
              <bitRange>[17:17]</bitRange>
            </field>
            <field>
              <name>UART1EN</name>
              <bitRange>[18:18]</bitRange>
            </field>
            <field>
              <name>UART2EN</name>
              <bitRange>[19:19]</bitRange>
            </field>
            <field>
              <name>LPUART1EN</name>
              <bitRange>[20:20]</bitRange>
            </field>
            <field>
              <name>I2C1EN</name>
              <bitRange>[21:21]</bitRange>
            </field>
            <field>
              <name>I2C2EN</name>
              <bitRange>[22:22]</bitRange>
            </field>
            <field>
              <name>OPAEN</name>
              <bitRange>[23:23]</bitRange>
            </field>
            <field>
              <name>DBGEN</name>
              <bitRange>[27:27]</bitRange>
            </field>
            <field>
              <name>PWREN</name>
              <bitRange>[28:28]</bitRange>
            </field>
            <field>
              <name>DACEN</name>
              <bitRange>[29:29]</bitRange>
            </field>
            <field>
              <name>LPTIM2EN</name>
              <bitRange>[30:30]</bitRange>
            </field>
            <field>
              <name>LPTIM1EN</name>
              <bitRange>[31:31]</bitRange>
            </field>
          </fields>
        </register>
        <register>
          <name>APBENR2</name>
          <description>APB peripheral clock enable register 2</description>
          <addressOffset>0x40</addressOffset>
          <fields>
            <field>
              <name>SYSCFGEN</name>
              <bitRange>[0:0]</bitRange>
            </field>
            <field>
              <name>TIM1EN</name>
              <bitRange>[11:11]</bitRange>
            </field>
            <field>
              <name>SPI1EN</name>
              <bitRange>[12:12]</bitRange>
            </field>
            <field>
              <name>USART1EN</name>
              <bitRange>[14:14]</bitRange>
            </field>
            <field>
              <name>TIM15EN</name>
              <bitRange>[16:16]</bitRange>
            </field>
            <field>
              <name>TIM16EN</name>
              <bitRange>[17:17]</bitRange>
            </field>
            <field>
              <name>TIM17EN</name>
              <bitRange>[18:18]</bitRange>
            </field>
            <field>
              <name>ADCEN</name>
              <bitRange>[20:20]</bitRange>
            </field>
            <field>
              <name>COMP1EN</name>
              <bitRange>[21:21]</bitRange>
            </field>
            <field>
              <name>COMP2EN</name>
              <bitRange>[22:22]</bitRange>
            </field>
            <field>
              <name>COMP3EN</name>
              <bitRange>[23:23]</bitRange>
            </field>
            <field>
              <name>LCDEN</name>
              <bitRange>[24:24]</bitRange>
            </field>
            <field>
              <name>TKEN</name>
              <bitRange>[25:25]</bitRange>
            </field>
            <field>
              <name>VREFBUFEN</name>
              <bitRange>[26:26]</bitRange>
            </field>
          </fields>
        </register>
        <register>
          <name>CCIPR</name>
          <description>Peripherals independent clock configuration register</description>
          <addressOffset>0x54</addressOffset>
          <fields>
            <field>
              <name>TIMCLKCTRL</name>
              <bitRange>[0:0]</bitRange>
            </field>
            <field>
              <name>PVDSEL</name>
              <bitRange>[7:7]</bitRange>
            </field>
            <field>
              <name>COMP1SEL</name>
              <bitRange>[8:8]</bitRange>
            </field>
            <field>
              <name>COMP2SEL</name>
              <bitRange>[9:9]</bitRange>
            </field>
            <field>
              <name>COMP3SEL</name>
              <bitRange>[10:10]</bitRange>
            </field>
            <field>
              <name>LPUART1SEL</name>
              <bitRange>[12:11]</bitRange>
              <enumeratedValues>
                <enumeratedValue>
                  <name>0</name>
                  <value>1</value>
                </enumeratedValue>
                <enumeratedValue>
                  <name>1</name>
                  <value>2</value>
                </enumeratedValue>
              </enumeratedValues>
            </field>
            <field>
              <name>LPUART2SEL</name>
              <bitRange>[14:13]</bitRange>
              <enumeratedValues>
                <enumeratedValue>
                  <name>0</name>
                  <value>1</value>
                </enumeratedValue>
                <enumeratedValue>
                  <name>1</name>
                  <value>2</value>
                </enumeratedValue>
              </enumeratedValues>
            </field>
            <field>
              <name>LPTIM1SEL</name>
              <bitRange>[17:16]</bitRange>
              <enumeratedValues>
                <enumeratedValue>
                  <name>0</name>
                  <value>1</value>
                </enumeratedValue>
                <enumeratedValue>
                  <name>1</name>
                  <value>2</value>
                </enumeratedValue>
              </enumeratedValues>
            </field>
            <field>
              <name>LPTIM2SEL</name>
              <bitRange>[19:18]</bitRange>
              <enumeratedValues>
                <enumeratedValue>
                  <name>0</name>
                  <value>1</value>
                </enumeratedValue>
                <enumeratedValue>
                  <name>1</name>
                  <value>2</value>
                </enumeratedValue>
              </enumeratedValues>
            </field>
            <field>
              <name>PWMSEL</name>
              <bitRange>[21:21]</bitRange>
            </field>
            <field>
              <name>ADCSEL</name>
              <bitRange>[31:30]</bitRange>
              <enumeratedValues>
                <enumeratedValue>
                  <name>0</name>
                  <value>1</value>
                </enumeratedValue>
                <enumeratedValue>
                  <name>1</name>
                  <value>2</value>
                </enumeratedValue>
              </enumeratedValues>
            </field>
          </fields>
        </register>
        <register>
          <name>BDCR</name>
          <description>RTC domain control register</description>
          <addressOffset>0x5C</addressOffset>
          <fields>
            <field>
              <name>LSERDY</name>
              <bitRange>[1:1]</bitRange>
              <access>read-only</access>
            </field>
            <field>
              <name>LSEBYP</name>
              <bitRange>[2:2]</bitRange>
            </field>
            <field>
              <name>LSEDRV</name>
              <bitRange>[4:3]</bitRange>
              <enumeratedValues>
                <enumeratedValue>
                  <name>0</name>
                  <value>1</value>
                </enumeratedValue>
                <enumeratedValue>
                  <name>1</name>
                  <value>2</value>
                </enumeratedValue>
              </enumeratedValues>
            </field>
            <field>
              <name>LSECSSON</name>
              <bitRange>[5:5]</bitRange>
            </field>
            <field>
              <name>LSECSSD</name>
              <bitRange>[6:6]</bitRange>
              <access>read-only</access>
            </field>
            <field>
              <name>RTCSEL</name>
              <bitRange>[9:8]</bitRange>
              <enumeratedValues>
                <enumeratedValue>
                  <name>0</name>
                  <value>1</value>
                </enumeratedValue>
                <enumeratedValue>
                  <name>1</name>
                  <value>2</value>
                </enumeratedValue>
              </enumeratedValues>
            </field>
            <field>
              <name>LSEEN</name>
              <bitRange>[13:10]</bitRange>
              <enumeratedValues>
                <enumeratedValue>
                  <name>0</name>
                  <value>1</value>
                </enumeratedValue>
                <enumeratedValue>
                  <name>1</name>
                  <value>2</value>
                </enumeratedValue>
                <enumeratedValue>
                  <name>2</name>
                  <value>4</value>
                </enumeratedValue>
                <enumeratedValue>
                  <name>3</name>
                  <value>8</value>
                </enumeratedValue>
              </enumeratedValues>
            </field>
            <field>
              <name>LSCSEL</name>
              <bitRange>[14:14]</bitRange>
            </field>
            <field>
              <name>RTCEN</name>
              <bitRange>[15:15]</bitRange>
            </field>
            <field>
              <name>BDRST</name>
              <bitRange>[16:16]</bitRange>
            </field>
            <field>
              <name>LSI_TRIMCR</name>
              <bitRange>[25:17]</bitRange>
            </field>
            <field>
              <name>LSION</name>
              <bitRange>[26:26]</bitRange>
            </field>
            <field>
              <name>LSIRDY</name>
              <bitRange>[27:27]</bitRange>
              <access>read-only</access>
            </field>
            <field>
              <name>LSE_RDYSEL</name>
              <bitRange>[29:28]</bitRange>
              <enumeratedValues>
                <enumeratedValue>
                  <name>0</name>
                  <value>1</value>
                </enumeratedValue>
                <enumeratedValue>
                  <name>1</name>
                  <value>2</value>
                </enumeratedValue>
              </enumeratedValues>
            </field>
            <field>
              <name>IWDGSEL</name>
              <bitRange>[30:30]</bitRange>
            </field>
          </fields>
        </register>
        <register>
          <name>CSR</name>
          <description>Control/status register</description>
          <addressOffset>0x60</addressOffset>
          <fields>
            <field>
              <name>NRST_FLTDIS</name>
              <bitRange>[8:8]</bitRange>
            </field>
            <field>
              <name>RMVF</name>
              <bitRange>[23:23]</bitRange>
            </field>
            <field>
              <name>OBLRSTF</name>
              <bitRange>[25:25]</bitRange>
              <access>read-only</access>
            </field>
            <field>
              <name>PINRSTF</name>
              <bitRange>[26:26]</bitRange>
              <access>read-only</access>
            </field>
            <field>
              <name>PWRRSTF</name>
              <bitRange>[27:27]</bitRange>
              <access>read-only</access>
            </field>
            <field>
              <name>SFTRSTF</name>
              <bitRange>[28:28]</bitRange>
              <access>read-only</access>
            </field>
            <field>
              <name>IWDGRSTF</name>
              <bitRange>[29:29]</bitRange>
              <access>read-only</access>
            </field>
            <field>
              <name>WWDGRSTF</name>
              <bitRange>[30:30]</bitRange>
              <access>read-only</access>
            </field>
            <field>
              <name>LPWRRSTF</name>
              <bitRange>[31:31]</bitRange>
              <access>read-only</access>
            </field>
          </fields>
        </register>
      </registers>
    </peripheral>
    <peripheral>
      <name>RTC</name>
      <description>desc RTC</description>
      <baseAddress>0x40002800</baseAddress>
      <addressBlock>
        <offset>0x0</offset>
        <size>0x400</size>
        <usage>registers</usage>
      </addressBlock>
      <interrupt>
        <name>RTC</name>
        <description>RTC Interrupt through EXTI Lines 19</description>
        <value>2</value>
      </interrupt>
      <registers>
        <register>
          <name>TR</name>
          <addressOffset>0x0</addressOffset>
          <fields>
            <field>
              <name>SU</name>
              <bitRange>[3:0]</bitRange>
              <enumeratedValues>
                <enumeratedValue>
                  <name>0</name>
                  <value>1</value>
                </enumeratedValue>
                <enumeratedValue>
                  <name>1</name>
                  <value>2</value>
                </enumeratedValue>
                <enumeratedValue>
                  <name>2</name>
                  <value>4</value>
                </enumeratedValue>
                <enumeratedValue>
                  <name>3</name>
                  <value>8</value>
                </enumeratedValue>
              </enumeratedValues>
            </field>
            <field>
              <name>ST</name>
              <bitRange>[6:4]</bitRange>
              <enumeratedValues>
                <enumeratedValue>
                  <name>0</name>
                  <value>1</value>
                </enumeratedValue>
                <enumeratedValue>
                  <name>1</name>
                  <value>2</value>
                </enumeratedValue>
                <enumeratedValue>
                  <name>2</name>
                  <value>4</value>
                </enumeratedValue>
              </enumeratedValues>
            </field>
            <field>
              <name>MNU</name>
              <bitRange>[11:8]</bitRange>
              <enumeratedValues>
                <enumeratedValue>
                  <name>0</name>
                  <value>1</value>
                </enumeratedValue>
                <enumeratedValue>
                  <name>1</name>
                  <value>2</value>
                </enumeratedValue>
                <enumeratedValue>
                  <name>2</name>
                  <value>4</value>
                </enumeratedValue>
                <enumeratedValue>
                  <name>3</name>
                  <value>8</value>
                </enumeratedValue>
              </enumeratedValues>
            </field>
            <field>
              <name>MNT</name>
              <bitRange>[14:12]</bitRange>
              <enumeratedValues>
                <enumeratedValue>
                  <name>0</name>
                  <value>1</value>
                </enumeratedValue>
                <enumeratedValue>
                  <name>1</name>
                  <value>2</value>
                </enumeratedValue>
                <enumeratedValue>
                  <name>2</name>
                  <value>4</value>
                </enumeratedValue>
              </enumeratedValues>
            </field>
            <field>
              <name>HU</name>
              <bitRange>[19:16]</bitRange>
              <enumeratedValues>
                <enumeratedValue>
                  <name>0</name>
                  <value>1</value>
                </enumeratedValue>
                <enumeratedValue>
                  <name>1</name>
                  <value>2</value>
                </enumeratedValue>
                <enumeratedValue>
                  <name>2</name>
                  <value>4</value>
                </enumeratedValue>
                <enumeratedValue>
                  <name>3</name>
                  <value>8</value>
                </enumeratedValue>
              </enumeratedValues>
            </field>
            <field>
              <name>HT</name>
              <bitRange>[21:20]</bitRange>
              <enumeratedValues>
                <enumeratedValue>
                  <name>0</name>
                  <value>1</value>
                </enumeratedValue>
                <enumeratedValue>
                  <name>1</name>
                  <value>2</value>
                </enumeratedValue>
              </enumeratedValues>
            </field>
            <field>
              <name>PM</name>
              <bitRange>[22:22]</bitRange>
            </field>
          </fields>
        </register>
        <register>
          <name>DR</name>
          <addressOffset>0x4</addressOffset>
          <fields>
            <field>
              <name>DU</name>
              <bitRange>[3:0]</bitRange>
              <enumeratedValues>
                <enumeratedValue>
                  <name>0</name>
                  <value>1</value>
                </enumeratedValue>
                <enumeratedValue>
                  <name>1</name>
                  <value>2</value>
                </enumeratedValue>
                <enumeratedValue>
                  <name>2</name>
                  <value>4</value>
                </enumeratedValue>
                <enumeratedValue>
                  <name>3</name>
                  <value>8</value>
                </enumeratedValue>
              </enumeratedValues>
            </field>
            <field>
              <name>DT</name>
              <bitRange>[5:4]</bitRange>
              <enumeratedValues>
                <enumeratedValue>
                  <name>0</name>
                  <value>1</value>
                </enumeratedValue>
                <enumeratedValue>
                  <name>1</name>
                  <value>2</value>
                </enumeratedValue>
              </enumeratedValues>
            </field>
            <field>
              <name>MU</name>
              <bitRange>[11:8]</bitRange>
              <enumeratedValues>
                <enumeratedValue>
                  <name>0</name>
                  <value>1</value>
                </enumeratedValue>
                <enumeratedValue>
                  <name>1</name>
                  <value>2</value>
                </enumeratedValue>
                <enumeratedValue>
                  <name>2</name>
                  <value>4</value>
                </enumeratedValue>
                <enumeratedValue>
                  <name>3</name>
                  <value>8</value>
                </enumeratedValue>
              </enumeratedValues>
            </field>
            <field>
              <name>MT</name>
              <bitRange>[12:12]</bitRange>
            </field>
            <field>
              <name>WDU</name>
              <bitRange>[15:13]</bitRange>
              <enumeratedValues>
                <enumeratedValue>
                  <name>0</name>
                  <value>1</value>
                </enumeratedValue>
                <enumeratedValue>
                  <name>1</name>
                  <value>2</value>
                </enumeratedValue>
                <enumeratedValue>
                  <name>2</name>
                  <value>4</value>
                </enumeratedValue>
              </enumeratedValues>
            </field>
            <field>
              <name>YU</name>
              <bitRange>[19:16]</bitRange>
              <enumeratedValues>
                <enumeratedValue>
                  <name>0</name>
                  <value>1</value>
                </enumeratedValue>
                <enumeratedValue>
                  <name>1</name>
                  <value>2</value>
                </enumeratedValue>
                <enumeratedValue>
                  <name>2</name>
                  <value>4</value>
                </enumeratedValue>
                <enumeratedValue>
                  <name>3</name>
                  <value>8</value>
                </enumeratedValue>
              </enumeratedValues>
            </field>
            <field>
              <name>YT</name>
              <bitRange>[23:20]</bitRange>
              <enumeratedValues>
                <enumeratedValue>
                  <name>0</name>
                  <value>1</value>
                </enumeratedValue>
                <enumeratedValue>
                  <name>1</name>
                  <value>2</value>
                </enumeratedValue>
                <enumeratedValue>
                  <name>2</name>
                  <value>4</value>
                </enumeratedValue>
                <enumeratedValue>
                  <name>3</name>
                  <value>8</value>
                </enumeratedValue>
              </enumeratedValues>
            </field>
          </fields>
        </register>
        <register>
          <name>SSR</name>
          <addressOffset>0x8</addressOffset>
          <fields>
            <field>
              <name>SS</name>
              <bitRange>[15:0]</bitRange>
              <access>read-only</access>
            </field>
          </fields>
        </register>
        <register>
          <name>ICSR</name>
          <addressOffset>0xC</addressOffset>
          <fields>
            <field>
              <name>ALRAWF</name>
              <bitRange>[0:0]</bitRange>
              <access>read-only</access>
            </field>
            <field>
              <name>ALRBWF</name>
              <bitRange>[1:1]</bitRange>
              <access>read-only</access>
            </field>
            <field>
              <name>WUTWF</name>
              <bitRange>[2:2]</bitRange>
              <access>read-only</access>
            </field>
            <field>
              <name>SHPF</name>
              <bitRange>[3:3]</bitRange>
              <access>read-only</access>
            </field>
            <field>
              <name>INITS</name>
              <bitRange>[4:4]</bitRange>
              <access>read-only</access>
            </field>
            <field>
              <name>RSF</name>
              <bitRange>[5:5]</bitRange>
            </field>
            <field>
              <name>INITF</name>
              <bitRange>[6:6]</bitRange>
              <access>read-only</access>
            </field>
            <field>
              <name>INIT</name>
              <bitRange>[7:7]</bitRange>
            </field>
            <field>
              <name>RECALPF</name>
              <bitRange>[16:16]</bitRange>
              <access>read-only</access>
            </field>
          </fields>
        </register>
        <register>
          <name>PRER</name>
          <addressOffset>0x10</addressOffset>
          <fields>
            <field>
              <name>PREDIV_S</name>
              <bitRange>[14:0]</bitRange>
            </field>
            <field>
              <name>PREDIV_A</name>
              <bitRange>[22:16]</bitRange>
            </field>
          </fields>
        </register>
        <register>
          <name>WUTR</name>
          <addressOffset>0x14</addressOffset>
          <fields>
            <field>
              <name>WUT</name>
              <bitRange>[15:0]</bitRange>
            </field>
          </fields>
        </register>
        <register>
          <name>CR</name>
          <addressOffset>0x18</addressOffset>
          <fields>
            <field>
              <name>WUCKSEL</name>
              <bitRange>[2:0]</bitRange>
              <enumeratedValues>
                <enumeratedValue>
                  <name>0</name>
                  <value>1</value>
                </enumeratedValue>
                <enumeratedValue>
                  <name>1</name>
                  <value>2</value>
                </enumeratedValue>
                <enumeratedValue>
                  <name>2</name>
                  <value>4</value>
                </enumeratedValue>
              </enumeratedValues>
            </field>
            <field>
              <name>TSEDGE</name>
              <bitRange>[3:3]</bitRange>
            </field>
            <field>
              <name>REFCKON</name>
              <bitRange>[4:4]</bitRange>
            </field>
            <field>
              <name>BYPSHAD</name>
              <bitRange>[5:5]</bitRange>
            </field>
            <field>
              <name>FMT</name>
              <bitRange>[6:6]</bitRange>
            </field>
            <field>
              <name>ALRAE</name>
              <bitRange>[8:8]</bitRange>
            </field>
            <field>
              <name>ALRBE</name>
              <bitRange>[9:9]</bitRange>
            </field>
            <field>
              <name>WUTE</name>
              <bitRange>[10:10]</bitRange>
            </field>
            <field>
              <name>TSE</name>
              <bitRange>[11:11]</bitRange>
            </field>
            <field>
              <name>ALRAIE</name>
              <bitRange>[12:12]</bitRange>
            </field>
            <field>
              <name>ALRBIE</name>
              <bitRange>[13:13]</bitRange>
            </field>
            <field>
              <name>WUTIE</name>
              <bitRange>[14:14]</bitRange>
            </field>
            <field>
              <name>TSIE</name>
              <bitRange>[15:15]</bitRange>
            </field>
            <field>
              <name>ADD1H</name>
              <bitRange>[16:16]</bitRange>
              <access>write-only</access>
            </field>
            <field>
              <name>SUB1H</name>
              <bitRange>[17:17]</bitRange>
              <access>write-only</access>
            </field>
            <field>
              <name>BKP</name>
              <bitRange>[18:18]</bitRange>
            </field>
            <field>
              <name>COSEL</name>
              <bitRange>[19:19]</bitRange>
            </field>
            <field>
              <name>POL</name>
              <bitRange>[20:20]</bitRange>
            </field>
            <field>
              <name>OSEL</name>
              <bitRange>[22:21]</bitRange>
              <enumeratedValues>
                <enumeratedValue>
                  <name>0</name>
                  <value>1</value>
                </enumeratedValue>
                <enumeratedValue>
                  <name>1</name>
                  <value>2</value>
                </enumeratedValue>
              </enumeratedValues>
            </field>
            <field>
              <name>COE</name>
              <bitRange>[23:23]</bitRange>
            </field>
            <field>
              <name>ITSE</name>
              <bitRange>[24:24]</bitRange>
            </field>
            <field>
              <name>TAMPTS</name>
              <bitRange>[25:25]</bitRange>
            </field>
            <field>
              <name>TAMPOE</name>
              <bitRange>[26:26]</bitRange>
            </field>
            <field>
              <name>TAMPALRM_PU</name>
              <bitRange>[29:29]</bitRange>
            </field>
            <field>
              <name>TAMPALRM_TYPE</name>
              <bitRange>[30:30]</bitRange>
            </field>
          </fields>
        </register>
        <register>
          <name>WPR</name>
          <addressOffset>0x24</addressOffset>
          <fields>
            <field>
              <name>KEY</name>
              <bitRange>[7:0]</bitRange>
            </field>
          </fields>
        </register>
        <register>
          <name>CALR</name>
          <addressOffset>0x28</addressOffset>
          <fields>
            <field>
              <name>CALM</name>
              <bitRange>[8:0]</bitRange>
            </field>
            <field>
              <name>CALW16</name>
              <bitRange>[13:13]</bitRange>
            </field>
            <field>
              <name>CALW8</name>
              <bitRange>[14:14]</bitRange>
            </field>
            <field>
              <name>CALP</name>
              <bitRange>[15:15]</bitRange>
            </field>
          </fields>
        </register>
        <register>
          <name>SHIFTR</name>
          <addressOffset>0x2C</addressOffset>
          <fields>
            <field>
              <name>SUBFS</name>
              <bitRange>[14:0]</bitRange>
              <access>write-only</access>
            </field>
            <field>
              <name>ADD1S</name>
              <bitRange>[31:31]</bitRange>
              <access>write-only</access>
            </field>
          </fields>
        </register>
        <register>
          <name>TSTR</name>
          <addressOffset>0x30</addressOffset>
          <fields>
            <field>
              <name>SU</name>
              <bitRange>[3:0]</bitRange>
              <access>read-only</access>
              <enumeratedValues>
                <enumeratedValue>
                  <name>0</name>
                  <value>1</value>
                </enumeratedValue>
                <enumeratedValue>
                  <name>1</name>
                  <value>2</value>
                </enumeratedValue>
                <enumeratedValue>
                  <name>2</name>
                  <value>4</value>
                </enumeratedValue>
                <enumeratedValue>
                  <name>3</name>
                  <value>8</value>
                </enumeratedValue>
              </enumeratedValues>
            </field>
            <field>
              <name>ST</name>
              <bitRange>[6:4]</bitRange>
              <access>read-only</access>
              <enumeratedValues>
                <enumeratedValue>
                  <name>0</name>
                  <value>1</value>
                </enumeratedValue>
                <enumeratedValue>
                  <name>1</name>
                  <value>2</value>
                </enumeratedValue>
                <enumeratedValue>
                  <name>2</name>
                  <value>4</value>
                </enumeratedValue>
              </enumeratedValues>
            </field>
            <field>
              <name>MNU</name>
              <bitRange>[11:8]</bitRange>
              <access>read-only</access>
              <enumeratedValues>
                <enumeratedValue>
                  <name>0</name>
                  <value>1</value>
                </enumeratedValue>
                <enumeratedValue>
                  <name>1</name>
                  <value>2</value>
                </enumeratedValue>
                <enumeratedValue>
                  <name>2</name>
                  <value>4</value>
                </enumeratedValue>
                <enumeratedValue>
                  <name>3</name>
                  <value>8</value>
                </enumeratedValue>
              </enumeratedValues>
            </field>
            <field>
              <name>MNT</name>
              <bitRange>[14:12]</bitRange>
              <access>read-only</access>
              <enumeratedValues>
                <enumeratedValue>
                  <name>0</name>
                  <value>1</value>
                </enumeratedValue>
                <enumeratedValue>
                  <name>1</name>
                  <value>2</value>
                </enumeratedValue>
                <enumeratedValue>
                  <name>2</name>
                  <value>4</value>
                </enumeratedValue>
              </enumeratedValues>
            </field>
            <field>
              <name>HU</name>
              <bitRange>[19:16]</bitRange>
              <access>read-only</access>
              <enumeratedValues>
                <enumeratedValue>
                  <name>0</name>
                  <value>1</value>
                </enumeratedValue>
                <enumeratedValue>
                  <name>1</name>
                  <value>2</value>
                </enumeratedValue>
                <enumeratedValue>
                  <name>2</name>
                  <value>4</value>
                </enumeratedValue>
                <enumeratedValue>
                  <name>3</name>
                  <value>8</value>
                </enumeratedValue>
              </enumeratedValues>
            </field>
            <field>
              <name>HT</name>
              <bitRange>[21:20]</bitRange>
              <access>read-only</access>
              <enumeratedValues>
                <enumeratedValue>
                  <name>0</name>
                  <value>1</value>
                </enumeratedValue>
                <enumeratedValue>
                  <name>1</name>
                  <value>2</value>
                </enumeratedValue>
              </enumeratedValues>
            </field>
            <field>
              <name>PM</name>
              <bitRange>[22:22]</bitRange>
              <access>read-only</access>
            </field>
          </fields>
        </register>
        <register>
          <name>TSDR</name>
          <addressOffset>0x34</addressOffset>
          <fields>
            <field>
              <name>DU</name>
              <bitRange>[3:0]</bitRange>
              <access>read-only</access>
              <enumeratedValues>
                <enumeratedValue>
                  <name>0</name>
                  <value>1</value>
                </enumeratedValue>
                <enumeratedValue>
                  <name>1</name>
                  <value>2</value>
                </enumeratedValue>
                <enumeratedValue>
                  <name>2</name>
                  <value>4</value>
                </enumeratedValue>
                <enumeratedValue>
                  <name>3</name>
                  <value>8</value>
                </enumeratedValue>
              </enumeratedValues>
            </field>
            <field>
              <name>DT</name>
              <bitRange>[5:4]</bitRange>
              <access>read-only</access>
              <enumeratedValues>
                <enumeratedValue>
                  <name>0</name>
                  <value>1</value>
                </enumeratedValue>
                <enumeratedValue>
                  <name>1</name>
                  <value>2</value>
                </enumeratedValue>
              </enumeratedValues>
            </field>
            <field>
              <name>MU</name>
              <bitRange>[11:8]</bitRange>
              <access>read-only</access>
              <enumeratedValues>
                <enumeratedValue>
                  <name>0</name>
                  <value>1</value>
                </enumeratedValue>
                <enumeratedValue>
                  <name>1</name>
                  <value>2</value>
                </enumeratedValue>
                <enumeratedValue>
                  <name>2</name>
                  <value>4</value>
                </enumeratedValue>
                <enumeratedValue>
                  <name>3</name>
                  <value>8</value>
                </enumeratedValue>
              </enumeratedValues>
            </field>
            <field>
              <name>MT</name>
              <bitRange>[12:12]</bitRange>
              <access>read-only</access>
            </field>
            <field>
              <name>WDU</name>
              <bitRange>[15:13]</bitRange>
              <access>read-only</access>
              <enumeratedValues>
                <enumeratedValue>
                  <name>0</name>
                  <value>1</value>
                </enumeratedValue>
                <enumeratedValue>
                  <name>1</name>
                  <value>2</value>
                </enumeratedValue>
                <enumeratedValue>
                  <name>2</name>
                  <value>4</value>
                </enumeratedValue>
              </enumeratedValues>
            </field>
          </fields>
        </register>
        <register>
          <name>TSSSR</name>
          <addressOffset>0x38</addressOffset>
          <fields>
            <field>
              <name>SS</name>
              <bitRange>[15:0]</bitRange>
              <access>read-only</access>
            </field>
          </fields>
        </register>
        <register>
          <name>ALRMAR</name>
          <addressOffset>0x40</addressOffset>
          <fields>
            <field>
              <name>SU</name>
              <bitRange>[3:0]</bitRange>
              <enumeratedValues>
                <enumeratedValue>
                  <name>0</name>
                  <value>1</value>
                </enumeratedValue>
                <enumeratedValue>
                  <name>1</name>
                  <value>2</value>
                </enumeratedValue>
                <enumeratedValue>
                  <name>2</name>
                  <value>4</value>
                </enumeratedValue>
                <enumeratedValue>
                  <name>3</name>
                  <value>8</value>
                </enumeratedValue>
              </enumeratedValues>
            </field>
            <field>
              <name>ST</name>
              <bitRange>[6:4]</bitRange>
              <enumeratedValues>
                <enumeratedValue>
                  <name>0</name>
                  <value>1</value>
                </enumeratedValue>
                <enumeratedValue>
                  <name>1</name>
                  <value>2</value>
                </enumeratedValue>
                <enumeratedValue>
                  <name>2</name>
                  <value>4</value>
                </enumeratedValue>
              </enumeratedValues>
            </field>
            <field>
              <name>MSK1</name>
              <bitRange>[7:7]</bitRange>
            </field>
            <field>
              <name>MNU</name>
              <bitRange>[11:8]</bitRange>
              <enumeratedValues>
                <enumeratedValue>
                  <name>0</name>
                  <value>1</value>
                </enumeratedValue>
                <enumeratedValue>
                  <name>1</name>
                  <value>2</value>
                </enumeratedValue>
                <enumeratedValue>
                  <name>2</name>
                  <value>4</value>
                </enumeratedValue>
                <enumeratedValue>
                  <name>3</name>
                  <value>8</value>
                </enumeratedValue>
              </enumeratedValues>
            </field>
            <field>
              <name>MNT</name>
              <bitRange>[14:12]</bitRange>
              <enumeratedValues>
                <enumeratedValue>
                  <name>0</name>
                  <value>1</value>
                </enumeratedValue>
                <enumeratedValue>
                  <name>1</name>
                  <value>2</value>
                </enumeratedValue>
                <enumeratedValue>
                  <name>2</name>
                  <value>4</value>
                </enumeratedValue>
              </enumeratedValues>
            </field>
            <field>
              <name>MSK2</name>
              <bitRange>[15:15]</bitRange>
            </field>
            <field>
              <name>HU</name>
              <bitRange>[19:16]</bitRange>
              <enumeratedValues>
                <enumeratedValue>
                  <name>0</name>
                  <value>1</value>
                </enumeratedValue>
                <enumeratedValue>
                  <name>1</name>
                  <value>2</value>
                </enumeratedValue>
                <enumeratedValue>
                  <name>2</name>
                  <value>4</value>
                </enumeratedValue>
                <enumeratedValue>
                  <name>3</name>
                  <value>8</value>
                </enumeratedValue>
              </enumeratedValues>
            </field>
            <field>
              <name>HT</name>
              <bitRange>[21:20]</bitRange>
              <enumeratedValues>
                <enumeratedValue>
                  <name>0</name>
                  <value>1</value>
                </enumeratedValue>
                <enumeratedValue>
                  <name>1</name>
                  <value>2</value>
                </enumeratedValue>
              </enumeratedValues>
            </field>
            <field>
              <name>PM</name>
              <bitRange>[22:22]</bitRange>
            </field>
            <field>
              <name>MSK3</name>
              <bitRange>[23:23]</bitRange>
            </field>
            <field>
              <name>DU</name>
              <bitRange>[27:24]</bitRange>
              <enumeratedValues>
                <enumeratedValue>
                  <name>0</name>
                  <value>1</value>
                </enumeratedValue>
                <enumeratedValue>
                  <name>1</name>
                  <value>2</value>
                </enumeratedValue>
                <enumeratedValue>
                  <name>2</name>
                  <value>4</value>
                </enumeratedValue>
                <enumeratedValue>
                  <name>3</name>
                  <value>8</value>
                </enumeratedValue>
              </enumeratedValues>
            </field>
            <field>
              <name>DT</name>
              <bitRange>[29:28]</bitRange>
              <enumeratedValues>
                <enumeratedValue>
                  <name>0</name>
                  <value>1</value>
                </enumeratedValue>
                <enumeratedValue>
                  <name>1</name>
                  <value>2</value>
                </enumeratedValue>
              </enumeratedValues>
            </field>
            <field>
              <name>WDSEL</name>
              <bitRange>[30:30]</bitRange>
            </field>
            <field>
              <name>MSK4</name>
              <bitRange>[31:31]</bitRange>
            </field>
          </fields>
        </register>
        <register>
          <name>ALRMASSR</name>
          <addressOffset>0x44</addressOffset>
          <fields>
            <field>
              <name>SS</name>
              <bitRange>[14:0]</bitRange>
            </field>
            <field>
              <name>MASKSS</name>
              <bitRange>[27:24]</bitRange>
              <enumeratedValues>
                <enumeratedValue>
                  <name>0</name>
                  <value>1</value>
                </enumeratedValue>
                <enumeratedValue>
                  <name>1</name>
                  <value>2</value>
                </enumeratedValue>
                <enumeratedValue>
                  <name>2</name>
                  <value>4</value>
                </enumeratedValue>
                <enumeratedValue>
                  <name>3</name>
                  <value>8</value>
                </enumeratedValue>
              </enumeratedValues>
            </field>
          </fields>
        </register>
        <register>
          <name>ALRMBR</name>
          <addressOffset>0x48</addressOffset>
          <fields>
            <field>
              <name>SU</name>
              <bitRange>[3:0]</bitRange>
              <enumeratedValues>
                <enumeratedValue>
                  <name>0</name>
                  <value>1</value>
                </enumeratedValue>
                <enumeratedValue>
                  <name>1</name>
                  <value>2</value>
                </enumeratedValue>
                <enumeratedValue>
                  <name>2</name>
                  <value>4</value>
                </enumeratedValue>
                <enumeratedValue>
                  <name>3</name>
                  <value>8</value>
                </enumeratedValue>
              </enumeratedValues>
            </field>
            <field>
              <name>ST</name>
              <bitRange>[6:4]</bitRange>
              <enumeratedValues>
                <enumeratedValue>
                  <name>0</name>
                  <value>1</value>
                </enumeratedValue>
                <enumeratedValue>
                  <name>1</name>
                  <value>2</value>
                </enumeratedValue>
                <enumeratedValue>
                  <name>2</name>
                  <value>4</value>
                </enumeratedValue>
              </enumeratedValues>
            </field>
            <field>
              <name>MSK1</name>
              <bitRange>[7:7]</bitRange>
            </field>
            <field>
              <name>MNU</name>
              <bitRange>[11:8]</bitRange>
              <enumeratedValues>
                <enumeratedValue>
                  <name>0</name>
                  <value>1</value>
                </enumeratedValue>
                <enumeratedValue>
                  <name>1</name>
                  <value>2</value>
                </enumeratedValue>
                <enumeratedValue>
                  <name>2</name>
                  <value>4</value>
                </enumeratedValue>
                <enumeratedValue>
                  <name>3</name>
                  <value>8</value>
                </enumeratedValue>
              </enumeratedValues>
            </field>
            <field>
              <name>MNT</name>
              <bitRange>[14:12]</bitRange>
              <enumeratedValues>
                <enumeratedValue>
                  <name>0</name>
                  <value>1</value>
                </enumeratedValue>
                <enumeratedValue>
                  <name>1</name>
                  <value>2</value>
                </enumeratedValue>
                <enumeratedValue>
                  <name>2</name>
                  <value>4</value>
                </enumeratedValue>
              </enumeratedValues>
            </field>
            <field>
              <name>MSK2</name>
              <bitRange>[15:15]</bitRange>
            </field>
            <field>
              <name>HU</name>
              <bitRange>[19:16]</bitRange>
              <enumeratedValues>
                <enumeratedValue>
                  <name>0</name>
                  <value>1</value>
                </enumeratedValue>
                <enumeratedValue>
                  <name>1</name>
                  <value>2</value>
                </enumeratedValue>
                <enumeratedValue>
                  <name>2</name>
                  <value>4</value>
                </enumeratedValue>
                <enumeratedValue>
                  <name>3</name>
                  <value>8</value>
                </enumeratedValue>
              </enumeratedValues>
            </field>
            <field>
              <name>HT</name>
              <bitRange>[21:20]</bitRange>
              <enumeratedValues>
                <enumeratedValue>
                  <name>0</name>
                  <value>1</value>
                </enumeratedValue>
                <enumeratedValue>
                  <name>1</name>
                  <value>2</value>
                </enumeratedValue>
              </enumeratedValues>
            </field>
            <field>
              <name>PM</name>
              <bitRange>[22:22]</bitRange>
            </field>
            <field>
              <name>MSK3</name>
              <bitRange>[23:23]</bitRange>
            </field>
            <field>
              <name>DU</name>
              <bitRange>[27:24]</bitRange>
              <enumeratedValues>
                <enumeratedValue>
                  <name>0</name>
                  <value>1</value>
                </enumeratedValue>
                <enumeratedValue>
                  <name>1</name>
                  <value>2</value>
                </enumeratedValue>
                <enumeratedValue>
                  <name>2</name>
                  <value>4</value>
                </enumeratedValue>
                <enumeratedValue>
                  <name>3</name>
                  <value>8</value>
                </enumeratedValue>
              </enumeratedValues>
            </field>
            <field>
              <name>DT</name>
              <bitRange>[29:28]</bitRange>
              <enumeratedValues>
                <enumeratedValue>
                  <name>0</name>
                  <value>1</value>
                </enumeratedValue>
                <enumeratedValue>
                  <name>1</name>
                  <value>2</value>
                </enumeratedValue>
              </enumeratedValues>
            </field>
            <field>
              <name>WDSEL</name>
              <bitRange>[30:30]</bitRange>
            </field>
            <field>
              <name>MSK4</name>
              <bitRange>[31:31]</bitRange>
            </field>
          </fields>
        </register>
        <register>
          <name>ALRMBSSR</name>
          <addressOffset>0x4C</addressOffset>
          <fields>
            <field>
              <name>SS</name>
              <bitRange>[14:0]</bitRange>
            </field>
            <field>
              <name>MASKSS</name>
              <bitRange>[27:24]</bitRange>
              <enumeratedValues>
                <enumeratedValue>
                  <name>0</name>
                  <value>1</value>
                </enumeratedValue>
                <enumeratedValue>
                  <name>1</name>
                  <value>2</value>
                </enumeratedValue>
                <enumeratedValue>
                  <name>2</name>
                  <value>4</value>
                </enumeratedValue>
                <enumeratedValue>
                  <name>3</name>
                  <value>8</value>
                </enumeratedValue>
              </enumeratedValues>
            </field>
          </fields>
        </register>
        <register>
          <name>SR</name>
          <addressOffset>0x50</addressOffset>
          <fields>
            <field>
              <name>ALRAF</name>
              <bitRange>[0:0]</bitRange>
              <access>read-only</access>
            </field>
            <field>
              <name>ALRBF</name>
              <bitRange>[1:1]</bitRange>
              <access>read-only</access>
            </field>
            <field>
              <name>WUTF</name>
              <bitRange>[2:2]</bitRange>
              <access>read-only</access>
            </field>
            <field>
              <name>TSF</name>
              <bitRange>[3:3]</bitRange>
              <access>read-only</access>
            </field>
            <field>
              <name>TSOVF</name>
              <bitRange>[4:4]</bitRange>
              <access>read-only</access>
            </field>
            <field>
              <name>ITSF</name>
              <bitRange>[5:5]</bitRange>
              <access>read-only</access>
            </field>
          </fields>
        </register>
        <register>
          <name>MISR</name>
          <addressOffset>0x54</addressOffset>
          <fields>
            <field>
              <name>ALRAMF</name>
              <bitRange>[0:0]</bitRange>
              <access>read-only</access>
            </field>
            <field>
              <name>ALRBMF</name>
              <bitRange>[1:1]</bitRange>
              <access>read-only</access>
            </field>
            <field>
              <name>WUTMF</name>
              <bitRange>[2:2]</bitRange>
              <access>read-only</access>
            </field>
            <field>
              <name>TSMF</name>
              <bitRange>[3:3]</bitRange>
              <access>read-only</access>
            </field>
            <field>
              <name>TSOVMF</name>
              <bitRange>[4:4]</bitRange>
              <access>read-only</access>
            </field>
            <field>
              <name>ITSMF</name>
              <bitRange>[5:5]</bitRange>
              <access>read-only</access>
            </field>
          </fields>
        </register>
        <register>
          <name>SCR</name>
          <addressOffset>0x5C</addressOffset>
          <fields>
            <field>
              <name>CALRAF</name>
              <bitRange>[0:0]</bitRange>
              <access>write-only</access>
            </field>
            <field>
              <name>CALRBF</name>
              <bitRange>[1:1]</bitRange>
              <access>write-only</access>
            </field>
            <field>
              <name>CWUTF</name>
              <bitRange>[2:2]</bitRange>
              <access>write-only</access>
            </field>
            <field>
              <name>CTSF</name>
              <bitRange>[3:3]</bitRange>
              <access>write-only</access>
            </field>
            <field>
              <name>CTSOVF</name>
              <bitRange>[4:4]</bitRange>
              <access>write-only</access>
            </field>
            <field>
              <name>CITSF</name>
              <bitRange>[5:5]</bitRange>
              <access>write-only</access>
            </field>
          </fields>
        </register>
      </registers>
    </peripheral>
    <peripheral>
      <name>SPI1</name>
      <description>Serial peripheral interface</description>
      <groupName>SPI</groupName>
      <baseAddress>0x40013000</baseAddress>
      <addressBlock>
        <offset>0x0</offset>
        <size>0x400</size>
        <usage>registers</usage>
      </addressBlock>
      <interrupt>
        <name>SPI1</name>
        <description>SPI1 global Interrupt</description>
        <value>25</value>
      </interrupt>
      <registers>
        <register>
          <name>CR1</name>
          <description>desc CR1</description>
          <addressOffset>0x0</addressOffset>
          <fields>
            <field>
              <name>CPHA</name>
              <description>Clock Phase</description>
              <bitRange>[0:0]</bitRange>
            </field>
            <field>
              <name>CPOL</name>
              <description>Clock Polarity</description>
              <bitRange>[1:1]</bitRange>
            </field>
            <field>
              <name>MSTR</name>
              <description>Master Selection</description>
              <bitRange>[2:2]</bitRange>
            </field>
            <field>
              <name>BR</name>
              <description>Baud Rate Control</description>
              <bitRange>[5:3]</bitRange>
              <enumeratedValues>
                <enumeratedValue>
                  <name>0</name>
                  <value>1</value>
                </enumeratedValue>
                <enumeratedValue>
                  <name>1</name>
                  <value>2</value>
                </enumeratedValue>
                <enumeratedValue>
                  <name>2</name>
                  <value>4</value>
                </enumeratedValue>
              </enumeratedValues>
            </field>
            <field>
              <name>SPE</name>
              <description>SPI Enable</description>
              <bitRange>[6:6]</bitRange>
            </field>
            <field>
              <name>LSBFIRST</name>
              <description>Frame Format</description>
              <bitRange>[7:7]</bitRange>
            </field>
            <field>
              <name>SSI</name>
              <description>Internal slave select</description>
              <bitRange>[8:8]</bitRange>
            </field>
            <field>
              <name>SSM</name>
              <description>Software slave management</description>
              <bitRange>[9:9]</bitRange>
            </field>
            <field>
              <name>RXONLY</name>
              <description>Receive only</description>
              <bitRange>[10:10]</bitRange>
            </field>
            <field>
              <name>DFF</name>
              <description>Data frame format</description>
              <bitRange>[11:11]</bitRange>
            </field>
            <field>
              <name>CRCEN</name>
              <description>Hardware CRC calculation enable</description>
              <bitRange>[13:13]</bitRange>
            </field>
            <field>
              <name>BIDIOE</name>
              <description>Output enable in bidirectional mode</description>
              <bitRange>[14:14]</bitRange>
            </field>
            <field>
              <name>BIDIMODE</name>
              <description>Bidirectional data mode enable</description>
              <bitRange>[15:15]</bitRange>
            </field>
          </fields>
        </register>
        <register>
          <name>CR2</name>
          <description>desc CR2</description>
          <addressOffset>0x4</addressOffset>
          <fields>
            <field>
              <name>RXDMAEN</name>
              <description>Rx buffer DMA enable</description>
              <bitRange>[0:0]</bitRange>
            </field>
            <field>
              <name>TXDMAEN</name>
              <description>Tx buffer DMA enable</description>
              <bitRange>[1:1]</bitRange>
            </field>
            <field>
              <name>SSOE</name>
              <description>SS Output Enable</description>
              <bitRange>[2:2]</bitRange>
            </field>
            <field>
              <name>CLRTXFIFO</name>
              <description>Clear FIFO</description>
              <bitRange>[4:4]</bitRange>
            </field>
            <field>
              <name>ERRIE</name>
              <description>Error Interrupt Enable</description>
              <bitRange>[5:5]</bitRange>
            </field>
            <field>
              <name>RXNEIE</name>
              <description>RX buffer Not Empty Interrupt Enable</description>
              <bitRange>[6:6]</bitRange>
            </field>
            <field>
              <name>TXEIE</name>
              <description>Tx buffer Empty Interrupt Enable</description>
              <bitRange>[7:7]</bitRange>
            </field>
            <field>
              <name>FRXTH</name>
              <bitRange>[12:12]</bitRange>
            </field>
            <field>
              <name>FRF</name>
              <bitRange>[15:15]</bitRange>
            </field>
          </fields>
        </register>
        <register>
          <name>SR</name>
          <description>desc SR</description>
          <addressOffset>0x8</addressOffset>
          <fields>
            <field>
              <name>RXNE</name>
              <description>Receive buffer Not Empty</description>
              <bitRange>[0:0]</bitRange>
              <access>read-only</access>
            </field>
            <field>
              <name>TXE</name>
              <description>Transmit buffer Empty</description>
              <bitRange>[1:1]</bitRange>
              <access>read-only</access>
            </field>
            <field>
              <name>CHSIDE</name>
              <description>Channel side</description>
              <bitRange>[2:2]</bitRange>
              <access>read-only</access>
            </field>
            <field>
              <name>UDR</name>
              <description>Underrun flag</description>
              <bitRange>[3:3]</bitRange>
              <access>read-only</access>
            </field>
            <field>
              <name>CRCERR</name>
              <description>CRC error flag</description>
              <bitRange>[4:4]</bitRange>
            </field>
            <field>
              <name>MODF</name>
              <description>Mode fault</description>
              <bitRange>[5:5]</bitRange>
            </field>
            <field>
              <name>OVR</name>
              <description>Overrun flag</description>
              <bitRange>[6:6]</bitRange>
              <access>read-only</access>
            </field>
            <field>
              <name>BSY</name>
              <description>Busy flag</description>
              <bitRange>[7:7]</bitRange>
              <access>read-only</access>
            </field>
            <field>
              <name>FRE</name>
              <bitRange>[8:8]</bitRange>
              <access>read-only</access>
            </field>
            <field>
              <name>FRLVL</name>
              <description>FIFO Reception Level</description>
              <bitRange>[10:9]</bitRange>
              <access>read-only</access>
              <enumeratedValues>
                <enumeratedValue>
                  <name>0</name>
                  <value>1</value>
                </enumeratedValue>
                <enumeratedValue>
                  <name>1</name>
                  <value>2</value>
                </enumeratedValue>
              </enumeratedValues>
            </field>
            <field>
              <name>FTLVL</name>
              <description>FIFO Transmission Level</description>
              <bitRange>[12:11]</bitRange>
              <access>read-only</access>
              <enumeratedValues>
                <enumeratedValue>
                  <name>0</name>
                  <value>1</value>
                </enumeratedValue>
                <enumeratedValue>
                  <name>1</name>
                  <value>2</value>
                </enumeratedValue>
              </enumeratedValues>
            </field>
          </fields>
        </register>
        <register>
          <name>DR</name>
          <description>desc DR</description>
          <addressOffset>0xC</addressOffset>
          <fields>
            <field>
              <name>DR</name>
              <description>Data Register</description>
              <bitRange>[15:0]</bitRange>
            </field>
          </fields>
        </register>
        <register>
          <name>CRCPR</name>
          <description>desc CRCPR</description>
          <addressOffset>0x10</addressOffset>
          <fields>
            <field>
              <name>CRCPOLY</name>
              <description>CRC polynomial register</description>
              <bitRange>[15:0]</bitRange>
            </field>
          </fields>
        </register>
        <register>
          <name>RXCRCR</name>
          <description>desc RXCRCR</description>
          <addressOffset>0x14</addressOffset>
          <fields>
            <field>
              <name>RXCRC</name>
              <description>rcv crc reg</description>
              <bitRange>[15:0]</bitRange>
              <access>read-only</access>
            </field>
          </fields>
        </register>
        <register>
          <name>TXCRCR</name>
          <description>desc TXCRCR</description>
          <addressOffset>0x18</addressOffset>
          <fields>
            <field>
              <name>TXCRC</name>
              <description>tx crc reg</description>
              <bitRange>[15:0]</bitRange>
              <access>read-only</access>
            </field>
          </fields>
        </register>
        <register>
          <name>I2S_CFGR</name>
          <addressOffset>0x1C</addressOffset>
          <fields>
            <field>
              <name>CHLEN</name>
              <description>Channel length (number of bits per audio channel</description>
              <bitRange>[0:0]</bitRange>
            </field>
            <field>
              <name>DATLEN</name>
              <description>Data length to be transferred</description>
              <bitRange>[2:1]</bitRange>
              <enumeratedValues>
                <enumeratedValue>
                  <name>0</name>
                  <value>1</value>
                </enumeratedValue>
                <enumeratedValue>
                  <name>1</name>
                  <value>2</value>
                </enumeratedValue>
              </enumeratedValues>
            </field>
            <field>
              <name>CKPOL</name>
              <description>Steady state clock polarity</description>
              <bitRange>[3:3]</bitRange>
            </field>
            <field>
              <name>I2SSTD</name>
              <description>I2S standard selection</description>
              <bitRange>[5:4]</bitRange>
              <enumeratedValues>
                <enumeratedValue>
                  <name>0</name>
                  <value>1</value>
                </enumeratedValue>
                <enumeratedValue>
                  <name>1</name>
                  <value>2</value>
                </enumeratedValue>
              </enumeratedValues>
            </field>
            <field>
              <name>PCMSYNC</name>
              <description>PCM frame synchronization</description>
              <bitRange>[7:7]</bitRange>
            </field>
            <field>
              <name>I2SCFG</name>
              <description>I2S configuration mode</description>
              <bitRange>[9:8]</bitRange>
              <enumeratedValues>
                <enumeratedValue>
                  <name>0</name>
                  <value>1</value>
                </enumeratedValue>
                <enumeratedValue>
                  <name>1</name>
                  <value>2</value>
                </enumeratedValue>
              </enumeratedValues>
            </field>
            <field>
              <name>I2SE</name>
              <description>I2S enable</description>
              <bitRange>[10:10]</bitRange>
            </field>
            <field>
              <name>I2SMOD</name>
              <description>I2S mode selection</description>
              <bitRange>[11:11]</bitRange>
            </field>
          </fields>
        </register>
        <register>
          <name>I2SPR</name>
          <description>desc I2SPR</description>
          <addressOffset>0x20</addressOffset>
          <fields>
            <field>
              <name>I2SDIV</name>
              <description>I2S linear prescaler</description>
              <bitRange>[7:0]</bitRange>
            </field>
            <field>
              <name>ODD</name>
              <description>Odd factor for the prescaler</description>
              <bitRange>[8:8]</bitRange>
            </field>
            <field>
              <name>MCKOE</name>
              <description>Master clock output enable</description>
              <bitRange>[9:9]</bitRange>
            </field>
          </fields>
        </register>
      </registers>
    </peripheral>
    <peripheral derivedFrom="SPI1">
      <name>SPI2</name>
      <baseAddress>0x40003800</baseAddress>
      <interrupt>
        <name>SPI2</name>
        <description>SPI2 global Interrupt</description>
        <value>26</value>
      </interrupt>
    </peripheral>
    <peripheral>
      <name>SYSCFG</name>
      <description>desc SYSCFG</description>
      <baseAddress>0x40010000</baseAddress>
      <addressBlock>
        <offset>0x0</offset>
        <size>0x200</size>
        <usage>registers</usage>
      </addressBlock>
      <registers>
        <register>
          <name>CFGR1</name>
          <description>desc CFGR1</description>
          <addressOffset>0x0</addressOffset>
          <fields>
            <field>
              <name>MEM_MODE</name>
              <bitRange>[1:0]</bitRange>
              <enumeratedValues>
                <enumeratedValue>
                  <name>0</name>
                  <value>1</value>
                </enumeratedValue>
                <enumeratedValue>
                  <name>1</name>
                  <value>2</value>
                </enumeratedValue>
              </enumeratedValues>
            </field>
            <field>
              <name>TK_LP_TRIG</name>
              <bitRange>[9:8]</bitRange>
              <enumeratedValues>
                <enumeratedValue>
                  <name>0</name>
                  <value>1</value>
                </enumeratedValue>
                <enumeratedValue>
                  <name>1</name>
                  <value>2</value>
                </enumeratedValue>
              </enumeratedValues>
            </field>
            <field>
              <name>RTC_TRIG_TKSEL</name>
              <bitRange>[11:10]</bitRange>
              <enumeratedValues>
                <enumeratedValue>
                  <name>0</name>
                  <value>1</value>
                </enumeratedValue>
                <enumeratedValue>
                  <name>1</name>
                  <value>2</value>
                </enumeratedValue>
              </enumeratedValues>
            </field>
            <field>
              <name>LPTIM1_TRIG_TKEN</name>
              <bitRange>[12:12]</bitRange>
            </field>
            <field>
              <name>LPTIM2_TRIG_TKEN</name>
              <bitRange>[13:13]</bitRange>
            </field>
            <field>
              <name>GPIO_AHB_SEL</name>
              <bitRange>[24:24]</bitRange>
            </field>
          </fields>
        </register>
        <register>
          <name>CFGR2</name>
          <description>desc CFGR2</description>
          <addressOffset>0x4</addressOffset>
          <fields>
            <field>
              <name>CLL</name>
              <bitRange>[0:0]</bitRange>
            </field>
            <field>
              <name>SPL</name>
              <bitRange>[1:1]</bitRange>
            </field>
            <field>
              <name>PVDL</name>
              <bitRange>[2:2]</bitRange>
            </field>
            <field>
              <name>ECCL</name>
              <bitRange>[3:3]</bitRange>
            </field>
          </fields>
        </register>
        <register>
          <name>CFGR3</name>
          <description>desc CFGR3</description>
          <addressOffset>0x8</addressOffset>
          <fields>
            <field>
              <name>DMA1_MAP</name>
              <bitRange>[5:0]</bitRange>
              <enumeratedValues>
                <enumeratedValue>
                  <name>0</name>
                  <value>1</value>
                </enumeratedValue>
                <enumeratedValue>
                  <name>1</name>
                  <value>2</value>
                </enumeratedValue>
                <enumeratedValue>
                  <name>2</name>
                  <value>4</value>
                </enumeratedValue>
                <enumeratedValue>
                  <name>3</name>
                  <value>8</value>
                </enumeratedValue>
                <enumeratedValue>
                  <name>4</name>
                  <value>16</value>
                </enumeratedValue>
                <enumeratedValue>
                  <name>5</name>
                  <value>32</value>
                </enumeratedValue>
              </enumeratedValues>
            </field>
            <field>
              <name>DMA2_MAP</name>
              <bitRange>[13:8]</bitRange>
              <enumeratedValues>
                <enumeratedValue>
                  <name>0</name>
                  <value>1</value>
                </enumeratedValue>
                <enumeratedValue>
                  <name>1</name>
                  <value>2</value>
                </enumeratedValue>
                <enumeratedValue>
                  <name>2</name>
                  <value>4</value>
                </enumeratedValue>
                <enumeratedValue>
                  <name>3</name>
                  <value>8</value>
                </enumeratedValue>
                <enumeratedValue>
                  <name>4</name>
                  <value>16</value>
                </enumeratedValue>
                <enumeratedValue>
                  <name>5</name>
                  <value>32</value>
                </enumeratedValue>
              </enumeratedValues>
            </field>
            <field>
              <name>DMA3_MAP</name>
              <bitRange>[21:16]</bitRange>
              <enumeratedValues>
                <enumeratedValue>
                  <name>0</name>
                  <value>1</value>
                </enumeratedValue>
                <enumeratedValue>
                  <name>1</name>
                  <value>2</value>
                </enumeratedValue>
                <enumeratedValue>
                  <name>2</name>
                  <value>4</value>
                </enumeratedValue>
                <enumeratedValue>
                  <name>3</name>
                  <value>8</value>
                </enumeratedValue>
                <enumeratedValue>
                  <name>4</name>
                  <value>16</value>
                </enumeratedValue>
                <enumeratedValue>
                  <name>5</name>
                  <value>32</value>
                </enumeratedValue>
              </enumeratedValues>
            </field>
            <field>
              <name>DMA4_MAP</name>
              <bitRange>[29:24]</bitRange>
              <enumeratedValues>
                <enumeratedValue>
                  <name>0</name>
                  <value>1</value>
                </enumeratedValue>
                <enumeratedValue>
                  <name>1</name>
                  <value>2</value>
                </enumeratedValue>
                <enumeratedValue>
                  <name>2</name>
                  <value>4</value>
                </enumeratedValue>
                <enumeratedValue>
                  <name>3</name>
                  <value>8</value>
                </enumeratedValue>
                <enumeratedValue>
                  <name>4</name>
                  <value>16</value>
                </enumeratedValue>
                <enumeratedValue>
                  <name>5</name>
                  <value>32</value>
                </enumeratedValue>
              </enumeratedValues>
            </field>
          </fields>
        </register>
        <register>
          <name>PA_ENS_REG</name>
          <addressOffset>0x20</addressOffset>
          <fields>
            <field>
              <name>PA_ENS</name>
              <bitRange>[15:0]</bitRange>
            </field>
          </fields>
        </register>
        <register>
          <name>PB_ENS_REG</name>
          <addressOffset>0x24</addressOffset>
          <fields>
            <field>
              <name>PB_ENS</name>
              <bitRange>[15:0]</bitRange>
            </field>
          </fields>
        </register>
        <register>
          <name>PC_ENS_REG</name>
          <addressOffset>0x28</addressOffset>
          <fields>
            <field>
              <name>PC_ENS</name>
              <bitRange>[15:0]</bitRange>
            </field>
          </fields>
        </register>
        <register>
          <name>PD_ENS_REG</name>
          <addressOffset>0x2C</addressOffset>
          <fields>
            <field>
              <name>PD_ENS</name>
              <bitRange>[13:0]</bitRange>
            </field>
          </fields>
        </register>
        <register>
          <name>IOCFG</name>
          <addressOffset>0x38</addressOffset>
          <fields>
            <field>
              <name>PA_EIIC</name>
              <bitRange>[3:0]</bitRange>
              <enumeratedValues>
                <enumeratedValue>
                  <name>0</name>
                  <value>1</value>
                </enumeratedValue>
                <enumeratedValue>
                  <name>1</name>
                  <value>2</value>
                </enumeratedValue>
                <enumeratedValue>
                  <name>2</name>
                  <value>4</value>
                </enumeratedValue>
                <enumeratedValue>
                  <name>3</name>
                  <value>8</value>
                </enumeratedValue>
              </enumeratedValues>
            </field>
            <field>
              <name>PB_EIIC</name>
              <bitRange>[13:8]</bitRange>
              <enumeratedValues>
                <enumeratedValue>
                  <name>0</name>
                  <value>1</value>
                </enumeratedValue>
                <enumeratedValue>
                  <name>1</name>
                  <value>2</value>
                </enumeratedValue>
                <enumeratedValue>
                  <name>2</name>
                  <value>4</value>
                </enumeratedValue>
                <enumeratedValue>
                  <name>3</name>
                  <value>8</value>
                </enumeratedValue>
                <enumeratedValue>
                  <name>4</name>
                  <value>16</value>
                </enumeratedValue>
                <enumeratedValue>
                  <name>5</name>
                  <value>32</value>
                </enumeratedValue>
              </enumeratedValues>
            </field>
            <field>
              <name>PD_EIIC_10</name>
              <bitRange>[14:14]</bitRange>
            </field>
            <field>
              <name>PD_EIIC_11</name>
              <bitRange>[15:15]</bitRange>
            </field>
            <field>
              <name>PC_EIIC</name>
              <bitRange>[24:16]</bitRange>
              <enumeratedValues>
                <enumeratedValue>
                  <name>0</name>
                  <value>1</value>
                </enumeratedValue>
                <enumeratedValue>
                  <name>1</name>
                  <value>2</value>
                </enumeratedValue>
                <enumeratedValue>
                  <name>2</name>
                  <value>4</value>
                </enumeratedValue>
                <enumeratedValue>
                  <name>3</name>
                  <value>8</value>
                </enumeratedValue>
                <enumeratedValue>
                  <name>4</name>
                  <value>16</value>
                </enumeratedValue>
                <enumeratedValue>
                  <name>5</name>
                  <value>32</value>
                </enumeratedValue>
                <enumeratedValue>
                  <name>6</name>
                  <value>64</value>
                </enumeratedValue>
                <enumeratedValue>
                  <name>7</name>
                  <value>128</value>
                </enumeratedValue>
                <enumeratedValue>
                  <name>8</name>
                  <value>256</value>
                </enumeratedValue>
              </enumeratedValues>
            </field>
            <field>
              <name>PD_EIIC</name>
              <bitRange>[29:26]</bitRange>
              <enumeratedValues>
                <enumeratedValue>
                  <name>0</name>
                  <value>1</value>
                </enumeratedValue>
                <enumeratedValue>
                  <name>1</name>
                  <value>2</value>
                </enumeratedValue>
                <enumeratedValue>
                  <name>2</name>
                  <value>4</value>
                </enumeratedValue>
                <enumeratedValue>
                  <name>3</name>
                  <value>8</value>
                </enumeratedValue>
              </enumeratedValues>
            </field>
            <field>
              <name>PD_PU_IIC</name>
              <bitRange>[31:30]</bitRange>
              <enumeratedValues>
                <enumeratedValue>
                  <name>0</name>
                  <value>1</value>
                </enumeratedValue>
                <enumeratedValue>
                  <name>1</name>
                  <value>2</value>
                </enumeratedValue>
              </enumeratedValues>
            </field>
          </fields>
        </register>
        <register>
          <name>LEDCFG</name>
          <addressOffset>0x3C</addressOffset>
          <fields>
            <field>
              <name>SEGIS_EN</name>
              <bitRange>[3:0]</bitRange>
              <enumeratedValues>
                <enumeratedValue>
                  <name>0</name>
                  <value>1</value>
                </enumeratedValue>
                <enumeratedValue>
                  <name>1</name>
                  <value>2</value>
                </enumeratedValue>
                <enumeratedValue>
                  <name>2</name>
                  <value>4</value>
                </enumeratedValue>
                <enumeratedValue>
                  <name>3</name>
                  <value>8</value>
                </enumeratedValue>
              </enumeratedValues>
            </field>
            <field>
              <name>PB_EHS</name>
              <bitRange>[15:8]</bitRange>
              <enumeratedValues>
                <enumeratedValue>
                  <name>0</name>
                  <value>1</value>
                </enumeratedValue>
                <enumeratedValue>
                  <name>1</name>
                  <value>2</value>
                </enumeratedValue>
                <enumeratedValue>
                  <name>2</name>
                  <value>4</value>
                </enumeratedValue>
                <enumeratedValue>
                  <name>3</name>
                  <value>8</value>
                </enumeratedValue>
                <enumeratedValue>
                  <name>4</name>
                  <value>16</value>
                </enumeratedValue>
                <enumeratedValue>
                  <name>5</name>
                  <value>32</value>
                </enumeratedValue>
                <enumeratedValue>
                  <name>6</name>
                  <value>64</value>
                </enumeratedValue>
                <enumeratedValue>
                  <name>7</name>
                  <value>128</value>
                </enumeratedValue>
              </enumeratedValues>
            </field>
            <field>
              <name>PB_ENSEG</name>
              <bitRange>[29:16]</bitRange>
              <enumeratedValues>
                <enumeratedValue>
                  <name>0</name>
                  <value>1</value>
                </enumeratedValue>
                <enumeratedValue>
                  <name>1</name>
                  <value>2</value>
                </enumeratedValue>
                <enumeratedValue>
                  <name>2</name>
                  <value>4</value>
                </enumeratedValue>
                <enumeratedValue>
                  <name>3</name>
                  <value>8</value>
                </enumeratedValue>
                <enumeratedValue>
                  <name>4</name>
                  <value>16</value>
                </enumeratedValue>
                <enumeratedValue>
                  <name>5</name>
                  <value>32</value>
                </enumeratedValue>
                <enumeratedValue>
                  <name>6</name>
                  <value>64</value>
                </enumeratedValue>
                <enumeratedValue>
                  <name>7</name>
                  <value>128</value>
                </enumeratedValue>
                <enumeratedValue>
                  <name>8</name>
                  <value>256</value>
                </enumeratedValue>
                <enumeratedValue>
                  <name>9</name>
                  <value>512</value>
                </enumeratedValue>
                <enumeratedValue>
                  <name>10</name>
                  <value>1024</value>
                </enumeratedValue>
                <enumeratedValue>
                  <name>11</name>
                  <value>2048</value>
                </enumeratedValue>
                <enumeratedValue>
                  <name>12</name>
                  <value>4096</value>
                </enumeratedValue>
                <enumeratedValue>
                  <name>13</name>
                  <value>8192</value>
                </enumeratedValue>
              </enumeratedValues>
            </field>
            <field>
              <name>PC_ENSEG</name>
              <bitRange>[31:30]</bitRange>
              <enumeratedValues>
                <enumeratedValue>
                  <name>0</name>
                  <value>1</value>
                </enumeratedValue>
                <enumeratedValue>
                  <name>1</name>
                  <value>2</value>
                </enumeratedValue>
              </enumeratedValues>
            </field>
          </fields>
        </register>
        <register>
          <name>PA_ANA2EN</name>
          <addressOffset>0x40</addressOffset>
          <fields>
            <field>
              <name>PA_ANA2EN</name>
              <bitRange>[15:0]</bitRange>
            </field>
          </fields>
        </register>
        <register>
          <name>PB_ANA2EN</name>
          <addressOffset>0x44</addressOffset>
          <fields>
            <field>
              <name>PB_ANA2EN</name>
              <bitRange>[15:0]</bitRange>
            </field>
          </fields>
        </register>
        <register>
          <name>PC_ANA2EN</name>
          <addressOffset>0x48</addressOffset>
          <fields>
            <field>
              <name>PC_ANA2EN</name>
              <bitRange>[15:0]</bitRange>
            </field>
          </fields>
        </register>
        <register>
          <name>PD_ANA2EN</name>
          <addressOffset>0x4C</addressOffset>
          <fields>
            <field>
              <name>PD_ANA2EN</name>
              <bitRange>[13:0]</bitRange>
            </field>
          </fields>
        </register>
        <register>
          <name>SCSR</name>
          <addressOffset>0x70</addressOffset>
          <fields>
            <field>
              <name>PERR_RSTEN</name>
              <bitRange>[0:0]</bitRange>
            </field>
            <field>
              <name>SPF</name>
              <bitRange>[8:8]</bitRange>
            </field>
          </fields>
        </register>
        <register>
          <name>SWPR</name>
          <addressOffset>0x74</addressOffset>
          <fields>
            <field>
              <name>SRAM_P0WP</name>
              <bitRange>[0:0]</bitRange>
            </field>
            <field>
              <name>SRAM_P1WP</name>
              <bitRange>[1:1]</bitRange>
            </field>
            <field>
              <name>SRAM_P2WP</name>
              <bitRange>[2:2]</bitRange>
            </field>
            <field>
              <name>SRAM_P3WP</name>
              <bitRange>[3:3]</bitRange>
            </field>
            <field>
              <name>SRAM_P4WP</name>
              <bitRange>[4:4]</bitRange>
            </field>
            <field>
              <name>SRAM_P5WP</name>
              <bitRange>[5:5]</bitRange>
            </field> 
            <field>
              <name>SRAM_P6WP</name>
              <bitRange>[6:6]</bitRange>
            </field>
            <field>
              <name>SRAM_P7WP</name>
              <bitRange>[7:7]</bitRange>
            </field>
            <field>
              <name>SRAM_P8WP</name>
              <bitRange>[8:8]</bitRange>
            </field>
            <field>
              <name>SRAM_P9WP</name>
              <bitRange>[9:9]</bitRange>
            </field>
            <field>
              <name>SRAM_P10WP</name>
              <bitRange>[10:10]</bitRange>
            </field>
            <field>
              <name>SRAM_P11WP</name>
              <bitRange>[11:11]</bitRange>
            </field> 
            <field>
              <name>SRAM_P12WP</name>
              <bitRange>[12:12]</bitRange>
            </field>
            <field>
              <name>SRAM_P13WP</name>
              <bitRange>[13:13]</bitRange>
            </field>   
            <field>
              <name>SRAM_P14WP</name>
              <bitRange>[14:14]</bitRange>
            </field>
            <field>
              <name>SRAM_P15WP</name>
              <bitRange>[15:15]</bitRange>
            </field>  
            <field>
              <name>SRAM_P16WP</name>
              <bitRange>[16:16]</bitRange>
            </field>
            <field>
              <name>SRAM_P17WP</name>
              <bitRange>[17:17]</bitRange>
            </field>  
            <field>
              <name>SRAM_P18WP</name>
              <bitRange>[18:18]</bitRange>
            </field>
            <field>
              <name>SRAM_P19WP</name>
              <bitRange>[19:19]</bitRange>
            </field>  
            <field>
              <name>SRAM_P20WP</name>
              <bitRange>[20:20]</bitRange>
            </field>
            <field>
              <name>SRAM_P21WP</name>
              <bitRange>[21:21]</bitRange>
            </field>  
            <field>
              <name>SRAM_P22WP</name>
              <bitRange>[22:22]</bitRange>
            </field>
            <field>
              <name>SRAM_P23WP</name>
              <bitRange>[23:23]</bitRange>
            </field>  
            <field>
              <name>SRAM_P24WP</name>
              <bitRange>[24:24]</bitRange>
            </field>
            <field>
              <name>SRAM_P25WP</name>
              <bitRange>[25:25]</bitRange>
            </field>
            <field>
              <name>SRAM_P26WP</name>
              <bitRange>[26:26]</bitRange>
            </field>
            <field>
              <name>SRAM_P27WP</name>
              <bitRange>[27:27]</bitRange>
            </field>  
            <field>
              <name>SRAM_P28WP</name>
              <bitRange>[28:28]</bitRange>
            </field>
            <field>
              <name>SRAM_P29WP</name>
              <bitRange>[29:29]</bitRange>
            </field>  
            <field>
              <name>SRAM_P30WP</name>
              <bitRange>[30:30]</bitRange>
            </field>
            <field>
              <name>SRAM_P31WP</name>
              <bitRange>[31:31]</bitRange>
            </field>  
          </fields>
        </register>
      </registers>
    </peripheral>
    <peripheral>
      <name>TIM1</name>
      <description>Advanced timer</description>
      <groupName>TIM</groupName>
      <baseAddress>0x40012C00</baseAddress>
      <addressBlock>
        <offset>0x0</offset>
        <size>0x400</size>
        <usage>registers</usage>
      </addressBlock>
      <interrupt>
        <name>TIM1_BRK_UP_TRG_COM</name>
        <description>TIM1 Break, Update, Trigger and Commutation Interrupt</description>
        <value>13</value>
      </interrupt>
      <interrupt>
        <name>TIM1_CC</name>
        <description>TIM1 Capture Compare Interrupt</description>
        <value>14</value>
      </interrupt>
      <registers>
        <register>
          <name>CR1</name>
          <description>desc CR1</description>
          <addressOffset>0x0</addressOffset>
          <fields>
            <field>
              <name>CEN</name>
              <bitRange>[0:0]</bitRange>
            </field>
            <field>
              <name>UDIS</name>
              <bitRange>[1:1]</bitRange>
            </field>
            <field>
              <name>URS</name>
              <bitRange>[2:2]</bitRange>
            </field>
            <field>
              <name>OPM</name>
              <bitRange>[3:3]</bitRange>
            </field>
            <field>
              <name>DIR</name>
              <bitRange>[4:4]</bitRange>
            </field>
            <field>
              <name>CMS</name>
              <bitRange>[6:5]</bitRange>
              <enumeratedValues>
                <enumeratedValue>
                  <name>0</name>
                  <value>1</value>
                </enumeratedValue>
                <enumeratedValue>
                  <name>1</name>
                  <value>2</value>
                </enumeratedValue>
              </enumeratedValues>
            </field>
            <field>
              <name>ARPE</name>
              <bitRange>[7:7]</bitRange>
            </field>
            <field>
              <name>CKD</name>
              <bitRange>[9:8]</bitRange>
              <enumeratedValues>
                <enumeratedValue>
                  <name>0</name>
                  <value>1</value>
                </enumeratedValue>
                <enumeratedValue>
                  <name>1</name>
                  <value>2</value>
                </enumeratedValue>
              </enumeratedValues>
            </field>
          </fields>
        </register>
        <register>
          <name>CR2</name>
          <description>desc CR2</description>
          <addressOffset>0x4</addressOffset>
          <fields>
            <field>
              <name>CCPC</name>
              <bitRange>[0:0]</bitRange>
            </field>
            <field>
              <name>CCUS</name>
              <bitRange>[2:2]</bitRange>
            </field>
            <field>
              <name>CCDS</name>
              <bitRange>[3:3]</bitRange>
            </field>
            <field>
              <name>MMS_L</name>
              <bitRange>[6:4]</bitRange>
            </field>
            <field>
              <name>TI1S</name>
              <bitRange>[7:7]</bitRange>
            </field>
            <field>
              <name>OIS1</name>
              <bitRange>[8:8]</bitRange>
            </field>
            <field>
              <name>OIS1N</name>
              <bitRange>[9:9]</bitRange>
            </field>
            <field>
              <name>OIS2</name>
              <bitRange>[10:10]</bitRange>
            </field>
            <field>
              <name>OIS2N</name>
              <bitRange>[11:11]</bitRange>
            </field>
            <field>
              <name>OIS3</name>
              <bitRange>[12:12]</bitRange>
            </field>
            <field>
              <name>OIS3N</name>
              <bitRange>[13:13]</bitRange>
            </field>
            <field>
              <name>OIS4</name>
              <bitRange>[14:14]</bitRange>
            </field>
            <field>
              <name>MMS_H</name>
              <bitRange>[25:25]</bitRange>
            </field>
          </fields>
        </register>
        <register>
          <name>SMCR</name>
          <description>desc SMCR</description>
          <addressOffset>0x8</addressOffset>
          <fields>
            <field>
              <name>SMS_L</name>
              <bitRange>[2:0]</bitRange>
            </field>
            <field>
              <name>OCCS</name>
              <bitRange>[3:3]</bitRange>
            </field>
            <field>
              <name>TS_L</name>
              <bitRange>[6:4]</bitRange>
            </field>
            <field>
              <name>MSM</name>
              <bitRange>[7:7]</bitRange>
            </field>
            <field>
              <name>ETF</name>
              <bitRange>[11:8]</bitRange>
              <enumeratedValues>
                <enumeratedValue>
                  <name>0</name>
                  <value>1</value>
                </enumeratedValue>
                <enumeratedValue>
                  <name>1</name>
                  <value>2</value>
                </enumeratedValue>
                <enumeratedValue>
                  <name>2</name>
                  <value>4</value>
                </enumeratedValue>
                <enumeratedValue>
                  <name>3</name>
                  <value>8</value>
                </enumeratedValue>
              </enumeratedValues>
            </field>
            <field>
              <name>ETPS</name>
              <bitRange>[13:12]</bitRange>
              <enumeratedValues>
                <enumeratedValue>
                  <name>0</name>
                  <value>1</value>
                </enumeratedValue>
                <enumeratedValue>
                  <name>1</name>
                  <value>2</value>
                </enumeratedValue>
              </enumeratedValues>
            </field>
            <field>
              <name>ECE</name>
              <bitRange>[14:14]</bitRange>
            </field>
            <field>
              <name>ETP</name>
              <bitRange>[15:15]</bitRange>
            </field>
            <field>
              <name>SMS_H</name>
              <bitRange>[16:16]</bitRange>
            </field>
            <field>
              <name>TS_H</name>
              <bitRange>[21:20]</bitRange>
            </field>
          </fields>
        </register>
        <register>
          <name>DIER</name>
          <description>desc DIER</description>
          <addressOffset>0xC</addressOffset>
          <fields>
            <field>
              <name>UIE</name>
              <bitRange>[0:0]</bitRange>
            </field>
            <field>
              <name>CC1IE</name>
              <bitRange>[1:1]</bitRange>
            </field>
            <field>
              <name>CC2IE</name>
              <bitRange>[2:2]</bitRange>
            </field>
            <field>
              <name>CC3IE</name>
              <bitRange>[3:3]</bitRange>
            </field>
            <field>
              <name>CC4IE</name>
              <bitRange>[4:4]</bitRange>
            </field>
            <field>
              <name>COMIE</name>
              <bitRange>[5:5]</bitRange>
            </field>
            <field>
              <name>TIE</name>
              <bitRange>[6:6]</bitRange>
            </field>
            <field>
              <name>BIE</name>
              <bitRange>[7:7]</bitRange>
            </field>
            <field>
              <name>UDE</name>
              <bitRange>[8:8]</bitRange>
            </field>
            <field>
              <name>CC1DE</name>
              <bitRange>[9:9]</bitRange>
            </field>
            <field>
              <name>CC2DE</name>
              <bitRange>[10:10]</bitRange>
            </field>
            <field>
              <name>CC3DE</name>
              <bitRange>[11:11]</bitRange>
            </field>
            <field>
              <name>CC4DE</name>
              <bitRange>[12:12]</bitRange>
            </field>
            <field>
              <name>COMDE</name>
              <bitRange>[13:13]</bitRange>
            </field>
            <field>
              <name>TDE</name>
              <bitRange>[14:14]</bitRange>
            </field>
          </fields>
        </register>
        <register>
          <name>SR</name>
          <description>desc SR</description>
          <addressOffset>0x10</addressOffset>
          <fields>
            <field>
              <name>UIF</name>
              <bitRange>[0:0]</bitRange>
            </field>
            <field>
              <name>CC1IF</name>
              <bitRange>[1:1]</bitRange>
            </field>
            <field>
              <name>CC2IF</name>
              <bitRange>[2:2]</bitRange>
            </field>
            <field>
              <name>CC3IF</name>
              <bitRange>[3:3]</bitRange>
            </field>
            <field>
              <name>CC4IF</name>
              <bitRange>[4:4]</bitRange>
            </field>
            <field>
              <name>COMIF</name>
              <bitRange>[5:5]</bitRange>
            </field>
            <field>
              <name>TIF</name>
              <bitRange>[6:6]</bitRange>
            </field>
            <field>
              <name>BIF</name>
              <bitRange>[7:7]</bitRange>
            </field>
            <field>
              <name>B2IF</name>
              <bitRange>[8:8]</bitRange>
            </field>
            <field>
              <name>CC1OF</name>
              <bitRange>[9:9]</bitRange>
            </field>
            <field>
              <name>CC2OF</name>
              <bitRange>[10:10]</bitRange>
            </field>
            <field>
              <name>CC3OF</name>
              <bitRange>[11:11]</bitRange>
            </field>
            <field>
              <name>CC4OF</name>
              <bitRange>[12:12]</bitRange>
            </field>
            <field>
              <name>SBIF</name>
              <bitRange>[13:13]</bitRange>
            </field>
            <field>
              <name>IC1IR</name>
              <bitRange>[18:18]</bitRange>
            </field>
            <field>
              <name>IC2IR</name>
              <bitRange>[19:19]</bitRange>
            </field>
            <field>
              <name>IC3IR</name>
              <bitRange>[24:24]</bitRange>
            </field>
            <field>
              <name>IC4IR</name>
              <bitRange>[25:25]</bitRange>
            </field>
            <field>
              <name>IC1IF</name>
              <bitRange>[26:26]</bitRange>
            </field>
            <field>
              <name>IC2IF</name>
              <bitRange>[27:27]</bitRange>
            </field>
            <field>
              <name>IC3IF</name>
              <bitRange>[28:28]</bitRange>
            </field>
            <field>
              <name>IC4IF</name>
              <bitRange>[29:29]</bitRange>
            </field>
          </fields>
        </register>
        <register>
          <name>EGR</name>
          <description>desc EGR</description>
          <addressOffset>0x14</addressOffset>
          <fields>
            <field>
              <name>UG</name>
              <bitRange>[0:0]</bitRange>
              <access>read-only</access>
            </field>
            <field>
              <name>CC1G</name>
              <bitRange>[1:1]</bitRange>
              <access>read-only</access>
            </field>
            <field>
              <name>CC2G</name>
              <bitRange>[2:2]</bitRange>
              <access>read-only</access>
            </field>
            <field>
              <name>CC3G</name>
              <bitRange>[3:3]</bitRange>
              <access>read-only</access>
            </field>
            <field>
              <name>CC4G</name>
              <bitRange>[4:4]</bitRange>
              <access>read-only</access>
            </field>
            <field>
              <name>COMG</name>
              <bitRange>[5:5]</bitRange>
              <access>read-only</access>
            </field>
            <field>
              <name>TG</name>
              <bitRange>[6:6]</bitRange>
              <access>read-only</access>
            </field>
            <field>
              <name>BG</name>
              <bitRange>[7:7]</bitRange>
              <access>read-only</access>
            </field>
          </fields>
        </register>
        <register>
          <name>CCMR1_OUTPUT</name>
          <description>desc CCMR1:OUTPUT</description>
          <addressOffset>0x18</addressOffset>
          <fields>
            <field>
              <name>CC1S</name>
              <bitRange>[1:0]</bitRange>
            </field>
            <field>
              <name>OC1FE</name>
              <bitRange>[2:2]</bitRange>
            </field>
            <field>
              <name>OC1PE</name>
              <bitRange>[3:3]</bitRange>
            </field>
            <field>
              <name>OC1M_L</name>
              <bitRange>[6:4]</bitRange>
            </field>
            <field>
              <name>OC1CE</name>
              <bitRange>[7:7]</bitRange>
            </field>
            <field>
              <name>CC2S</name>
              <bitRange>[9:8]</bitRange>
            </field>
            <field>
              <name>OC2FE</name>
              <bitRange>[10:10]</bitRange>
            </field>
            <field>
              <name>OC2PE</name>
              <bitRange>[11:11]</bitRange>
            </field>
            <field>
              <name>OC2M_L</name>
              <bitRange>[14:12]</bitRange>
            </field>
            <field>
              <name>OC2CE</name>
              <bitRange>[15:15]</bitRange>
            </field>
            <field>
              <name>OC1M_H</name>
              <bitRange>[16:16]</bitRange>
            </field>
            <field>
              <name>OC2M_H</name>
              <bitRange>[24:24]</bitRange>
            </field>
          </fields>
        </register>
        <register>
          <name>CCMR1_INPUT</name>
          <description>desc CCMR1:INPUT</description>
          <alternateRegister>CCMR1_OUTPUT</alternateRegister>
          <addressOffset>0x18</addressOffset>
          <fields>
            <field>
              <name>CC1S</name>
              <bitRange>[1:0]</bitRange>
            </field>
            <field>
              <name>IC1PSC</name>
              <bitRange>[3:2]</bitRange>
            </field>
            <field>
              <name>IC1F</name>
              <bitRange>[7:4]</bitRange>
            </field>
            <field>
              <name>CC2S</name>
              <bitRange>[9:8]</bitRange>
            </field>
            <field>
              <name>IC2PSC</name>
              <bitRange>[11:10]</bitRange>
            </field>
            <field>
              <name>IC2F</name>
              <bitRange>[15:12]</bitRange>
            </field>
          </fields>
        </register>
        <register>
          <name>CCMR2_OUTPUT</name>
          <description>desc CCMR2:OUTPUT</description>
          <addressOffset>0x1C</addressOffset>
          <fields>
            <field>
              <name>CC3S</name>
              <bitRange>[1:0]</bitRange>
            </field>
            <field>
              <name>OC3FE</name>
              <bitRange>[2:2]</bitRange>
            </field>
            <field>
              <name>OC3PE</name>
              <bitRange>[3:3]</bitRange>
            </field>
            <field>
              <name>OC3M_L</name>
              <bitRange>[6:4]</bitRange>
            </field>
            <field>
              <name>OC3CE</name>
              <bitRange>[7:7]</bitRange>
            </field>
            <field>
              <name>CC4S</name>
              <bitRange>[9:8]</bitRange>
            </field>
            <field>
              <name>OC4FE</name>
              <bitRange>[10:10]</bitRange>
            </field>
            <field>
              <name>OC4PE</name>
              <bitRange>[11:11]</bitRange>
            </field>
            <field>
              <name>OC4M_L</name>
              <bitRange>[14:12]</bitRange>
            </field>
            <field>
              <name>OC4CE</name>
              <bitRange>[15:15]</bitRange>
            </field>
            <field>
              <name>OC3M_H</name>
              <bitRange>[16:16]</bitRange>
            </field>
            <field>
              <name>OC4M_H</name>
              <bitRange>[24:24]</bitRange>
            </field>
          </fields>
        </register>
        <register>
          <name>CCMR2_INPUT</name>
          <description>desc CCMR2:INPUT</description>
          <alternateRegister>CCMR2_OUTPUT</alternateRegister>
          <addressOffset>0x1C</addressOffset>
          <fields>
            <field>
              <name>CC3S</name>
              <bitRange>[1:0]</bitRange>
            </field>
            <field>
              <name>IC3PSC</name>
              <bitRange>[3:2]</bitRange>
            </field>
            <field>
              <name>IC3F</name>
              <bitRange>[7:4]</bitRange>
            </field>
            <field>
              <name>CC4S</name>
              <bitRange>[9:8]</bitRange>
            </field>
            <field>
              <name>IC4PSC</name>
              <bitRange>[11:10]</bitRange>
            </field>
            <field>
              <name>IC4F</name>
              <bitRange>[15:12]</bitRange>
            </field>
          </fields>
        </register>
        <register>
          <name>TIMXCCER</name>
          <addressOffset>0x20</addressOffset>
          <fields>
            <field>
              <name>CC1E</name>
              <bitRange>[0:0]</bitRange>
            </field>
            <field>
              <name>CC1P</name>
              <bitRange>[1:1]</bitRange>
            </field>
            <field>
              <name>CC1NE</name>
              <bitRange>[2:2]</bitRange>
            </field>
            <field>
              <name>CC1NP</name>
              <bitRange>[3:3]</bitRange>
            </field>
            <field>
              <name>CC2E</name>
              <bitRange>[4:4]</bitRange>
            </field>
            <field>
              <name>CC2P</name>
              <bitRange>[5:5]</bitRange>
            </field>
            <field>
              <name>CC2NE</name>
              <bitRange>[6:6]</bitRange>
            </field>
            <field>
              <name>CC2NP</name>
              <bitRange>[7:7]</bitRange>
            </field>
            <field>
              <name>CC3E</name>
              <bitRange>[8:8]</bitRange>
            </field>
            <field>
              <name>CC3P</name>
              <bitRange>[9:9]</bitRange>
            </field>
            <field>
              <name>CC3NE</name>
              <bitRange>[10:10]</bitRange>
            </field>
            <field>
              <name>CC3NP</name>
              <bitRange>[11:11]</bitRange>
            </field>
            <field>
              <name>CC4E</name>
              <bitRange>[12:12]</bitRange>
            </field>
            <field>
              <name>CC4P</name>
              <bitRange>[13:13]</bitRange>
            </field>
          </fields>
        </register>
        <register>
          <name>CNT</name>
          <description>desc CNT</description>
          <addressOffset>0x24</addressOffset>
          <fields>
            <field>
              <name>CNT</name>
              <bitRange>[15:0]</bitRange>
            </field>
          </fields>
        </register>
        <register>
          <name>PSC</name>
          <description>desc PSC</description>
          <addressOffset>0x28</addressOffset>
          <fields>
            <field>
              <name>PSC</name>
              <bitRange>[15:0]</bitRange>
            </field>
          </fields>
        </register>
        <register>
          <name>ARR</name>
          <description>desc ARR</description>
          <addressOffset>0x2C</addressOffset>
          <fields>
            <field>
              <name>ARR</name>
              <bitRange>[15:0]</bitRange>
            </field>
          </fields>
        </register>
        <register>
          <name>RCR</name>
          <description>desc RCR</description>
          <addressOffset>0x30</addressOffset>
          <fields>
            <field>
              <name>REP</name>
              <bitRange>[7:0]</bitRange>
            </field>
          </fields>
        </register>
        <register>
          <name>CCR1</name>
          <description>desc CCR1</description>
          <addressOffset>0x34</addressOffset>
          <fields>
            <field>
              <name>CCR1</name>
              <bitRange>[15:0]</bitRange>
            </field>
          </fields>
        </register>
        <register>
          <name>CCR2</name>
          <description>desc CCR2</description>
          <addressOffset>0x38</addressOffset>
          <fields>
            <field>
              <name>CCR2</name>
              <bitRange>[15:0]</bitRange>
            </field>
          </fields>
        </register>
        <register>
          <name>CCR3</name>
          <description>desc CCR3</description>
          <addressOffset>0x3C</addressOffset>
          <fields>
            <field>
              <name>CCR3</name>
              <bitRange>[15:0]</bitRange>
            </field>
          </fields>
        </register>
        <register>
          <name>CCR4</name>
          <description>desc CCR4</description>
          <addressOffset>0x40</addressOffset>
          <fields>
            <field>
              <name>CCR4</name>
              <bitRange>[15:0]</bitRange>
            </field>
          </fields>
        </register>
        <register>
          <name>BDTR</name>
          <description>desc BDTR</description>
          <addressOffset>0x44</addressOffset>
          <fields>
            <field>
              <name>DTG</name>
              <bitRange>[7:0]</bitRange>
            </field>
            <field>
              <name>LOCK</name>
              <bitRange>[9:8]</bitRange>
              <enumeratedValues>
                <enumeratedValue>
                  <name>0</name>
                  <value>1</value>
                </enumeratedValue>
                <enumeratedValue>
                  <name>1</name>
                  <value>2</value>
                </enumeratedValue>
              </enumeratedValues>
            </field>
            <field>
              <name>OSSI</name>
              <bitRange>[10:10]</bitRange>
            </field>
            <field>
              <name>OSSR</name>
              <bitRange>[11:11]</bitRange>
            </field>
            <field>
              <name>BKE</name>
              <bitRange>[12:12]</bitRange>
            </field>
            <field>
              <name>BKP</name>
              <bitRange>[13:13]</bitRange>
            </field>
            <field>
              <name>AOE</name>
              <bitRange>[14:14]</bitRange>
            </field>
            <field>
              <name>MOE</name>
              <bitRange>[15:15]</bitRange>
            </field>
          </fields>
        </register>
        <register>
          <name>TISEL</name>
          <addressOffset>0x5C</addressOffset>
          <fields>
            <field>
              <name>TI1SEL</name>
              <bitRange>[3:0]</bitRange>
              <enumeratedValues>
                <enumeratedValue>
                  <name>0</name>
                  <value>1</value>
                </enumeratedValue>
                <enumeratedValue>
                  <name>1</name>
                  <value>2</value>
                </enumeratedValue>
                <enumeratedValue>
                  <name>2</name>
                  <value>4</value>
                </enumeratedValue>
                <enumeratedValue>
                  <name>3</name>
                  <value>8</value>
                </enumeratedValue>
              </enumeratedValues>
            </field>
            <field>
              <name>TI2SEL</name>
              <bitRange>[11:8]</bitRange>
              <enumeratedValues>
                <enumeratedValue>
                  <name>0</name>
                  <value>1</value>
                </enumeratedValue>
                <enumeratedValue>
                  <name>1</name>
                  <value>2</value>
                </enumeratedValue>
                <enumeratedValue>
                  <name>2</name>
                  <value>4</value>
                </enumeratedValue>
                <enumeratedValue>
                  <name>3</name>
                  <value>8</value>
                </enumeratedValue>
              </enumeratedValues>
            </field>
            <field>
              <name>TI3SEL</name>
              <bitRange>[19:16]</bitRange>
              <enumeratedValues>
                <enumeratedValue>
                  <name>0</name>
                  <value>1</value>
                </enumeratedValue>
                <enumeratedValue>
                  <name>1</name>
                  <value>2</value>
                </enumeratedValue>
                <enumeratedValue>
                  <name>2</name>
                  <value>4</value>
                </enumeratedValue>
                <enumeratedValue>
                  <name>3</name>
                  <value>8</value>
                </enumeratedValue>
              </enumeratedValues>
            </field>
            <field>
              <name>TI4SEL</name>
              <bitRange>[27:24]</bitRange>
              <enumeratedValues>
                <enumeratedValue>
                  <name>0</name>
                  <value>1</value>
                </enumeratedValue>
                <enumeratedValue>
                  <name>1</name>
                  <value>2</value>
                </enumeratedValue>
                <enumeratedValue>
                  <name>2</name>
                  <value>4</value>
                </enumeratedValue>
                <enumeratedValue>
                  <name>3</name>
                  <value>8</value>
                </enumeratedValue>
              </enumeratedValues>
            </field>
          </fields>
        </register>
        <register>
          <name>AF1</name>
          <addressOffset>0x60</addressOffset>
          <fields>
            <field>
              <name>BKINE</name>
              <bitRange>[0:0]</bitRange>
            </field>
            <field>
              <name>BKCMP1E</name>
              <bitRange>[1:1]</bitRange>
            </field>
            <field>
              <name>BKCMP2E</name>
              <bitRange>[2:2]</bitRange>
            </field>
            <field>
              <name>BKINP</name>
              <bitRange>[9:9]</bitRange>
            </field>
            <field>
              <name>BKCMP1P</name>
              <bitRange>[10:10]</bitRange>
            </field>
            <field>
              <name>BKCMP2P</name>
              <bitRange>[11:11]</bitRange>
            </field>
            <field>
              <name>ETRSEL</name>
              <bitRange>[17:14]</bitRange>
              <enumeratedValues>
                <enumeratedValue>
                  <name>0</name>
                  <value>1</value>
                </enumeratedValue>
                <enumeratedValue>
                  <name>1</name>
                  <value>2</value>
                </enumeratedValue>
                <enumeratedValue>
                  <name>2</name>
                  <value>4</value>
                </enumeratedValue>
                <enumeratedValue>
                  <name>3</name>
                  <value>8</value>
                </enumeratedValue>
              </enumeratedValues>
            </field>
          </fields>
        </register>
        <register>
          <name>AF2</name>
          <addressOffset>0x64</addressOffset>
          <fields>
            <field>
              <name>OCRSEL</name>
              <bitRange>[18:16]</bitRange>
              <enumeratedValues>
                <enumeratedValue>
                  <name>0</name>
                  <value>1</value>
                </enumeratedValue>
                <enumeratedValue>
                  <name>1</name>
                  <value>2</value>
                </enumeratedValue>
                <enumeratedValue>
                  <name>2</name>
                  <value>4</value>
                </enumeratedValue>
              </enumeratedValues>
            </field>
          </fields>
        </register>
        <register>
          <name>DCR</name>
          <description>desc DCR</description>
          <addressOffset>0x3DC</addressOffset>
          <fields>
            <field>
              <name>DBA</name>
              <bitRange>[4:0]</bitRange>
              <enumeratedValues>
                <enumeratedValue>
                  <name>0</name>
                  <value>1</value>
                </enumeratedValue>
                <enumeratedValue>
                  <name>1</name>
                  <value>2</value>
                </enumeratedValue>
                <enumeratedValue>
                  <name>2</name>
                  <value>4</value>
                </enumeratedValue>
                <enumeratedValue>
                  <name>3</name>
                  <value>8</value>
                </enumeratedValue>
                <enumeratedValue>
                  <name>4</name>
                  <value>16</value>
                </enumeratedValue>
              </enumeratedValues>
            </field>
            <field>
              <name>DBL</name>
              <bitRange>[12:8]</bitRange>
              <enumeratedValues>
                <enumeratedValue>
                  <name>0</name>
                  <value>1</value>
                </enumeratedValue>
                <enumeratedValue>
                  <name>1</name>
                  <value>2</value>
                </enumeratedValue>
                <enumeratedValue>
                  <name>2</name>
                  <value>4</value>
                </enumeratedValue>
                <enumeratedValue>
                  <name>3</name>
                  <value>8</value>
                </enumeratedValue>
                <enumeratedValue>
                  <name>4</name>
                  <value>16</value>
                </enumeratedValue>
              </enumeratedValues>
            </field>
          </fields>
        </register>
        <register>
          <name>DMAR</name>
          <description>desc DMAR</description>
          <addressOffset>0x3E0</addressOffset>
          <fields>
            <field>
              <name>DMAB</name>
              <bitRange>[31:0]</bitRange>
            </field>
          </fields>
        </register>
      </registers>
    </peripheral>
    <peripheral>
      <name>TIM2</name>
      <description>desc TIM</description>
      <groupName>TIM</groupName>
      <baseAddress>0x40000000</baseAddress>
      <addressBlock>
        <offset>0x0</offset>
        <size>0x400</size>
        <usage>registers</usage>
      </addressBlock>
      <interrupt>
        <name>TIM2</name>
        <description>TIM2 global Interrupt</description>
        <value>15</value>
      </interrupt>
      <registers>
        <register>
          <name>CR1</name>
          <description>desc CR1</description>
          <addressOffset>0x0</addressOffset>
          <fields>
            <field>
              <name>CEN</name>
              <bitRange>[0:0]</bitRange>
            </field>
            <field>
              <name>UDIS</name>
              <bitRange>[1:1]</bitRange>
            </field>
            <field>
              <name>URS</name>
              <bitRange>[2:2]</bitRange>
            </field>
            <field>
              <name>OPM</name>
              <bitRange>[3:3]</bitRange>
            </field>
            <field>
              <name>DIR</name>
              <bitRange>[4:4]</bitRange>
            </field>
            <field>
              <name>CMS</name>
              <bitRange>[6:5]</bitRange>
              <enumeratedValues>
                <enumeratedValue>
                  <name>0</name>
                  <value>1</value>
                </enumeratedValue>
                <enumeratedValue>
                  <name>1</name>
                  <value>2</value>
                </enumeratedValue>
              </enumeratedValues>
            </field>
            <field>
              <name>ARPE</name>
              <bitRange>[7:7]</bitRange>
            </field>
            <field>
              <name>CKD</name>
              <bitRange>[9:8]</bitRange>
              <enumeratedValues>
                <enumeratedValue>
                  <name>0</name>
                  <value>1</value>
                </enumeratedValue>
                <enumeratedValue>
                  <name>1</name>
                  <value>2</value>
                </enumeratedValue>
              </enumeratedValues>
            </field>
          </fields>
        </register>
        <register>
          <name>CR2</name>
          <description>desc CR2</description>
          <addressOffset>0x4</addressOffset>
          <fields>
            <field>
              <name>CCDS</name>
              <bitRange>[3:3]</bitRange>
            </field>
            <field>
              <name>MMS_L</name>
              <bitRange>[6:4]</bitRange>
            </field>
            <field>
              <name>TI1S</name>
              <bitRange>[7:7]</bitRange>
            </field>
            <field>
              <name>MMS_H</name>
              <bitRange>[25:25]</bitRange>
            </field>
          </fields>
        </register>
        <register>
          <name>SMCR</name>
          <description>desc SMCR</description>
          <addressOffset>0x8</addressOffset>
          <fields>
            <field>
              <name>SMS</name>
              <bitRange>[2:0]</bitRange>
            </field>
            <field>
              <name>OCCS</name>
              <bitRange>[3:3]</bitRange>
            </field>
            <field>
              <name>TS_L</name>
              <bitRange>[6:4]</bitRange>
            </field>
            <field>
              <name>MSM</name>
              <bitRange>[7:7]</bitRange>
            </field>
            <field>
              <name>ETF</name>
              <bitRange>[11:8]</bitRange>
              <enumeratedValues>
                <enumeratedValue>
                  <name>0</name>
                  <value>1</value>
                </enumeratedValue>
                <enumeratedValue>
                  <name>1</name>
                  <value>2</value>
                </enumeratedValue>
                <enumeratedValue>
                  <name>2</name>
                  <value>4</value>
                </enumeratedValue>
                <enumeratedValue>
                  <name>3</name>
                  <value>8</value>
                </enumeratedValue>
              </enumeratedValues>
            </field>
            <field>
              <name>ETPS</name>
              <bitRange>[13:12]</bitRange>
              <enumeratedValues>
                <enumeratedValue>
                  <name>0</name>
                  <value>1</value>
                </enumeratedValue>
                <enumeratedValue>
                  <name>1</name>
                  <value>2</value>
                </enumeratedValue>
              </enumeratedValues>
            </field>
            <field>
              <name>ECE</name>
              <bitRange>[14:14]</bitRange>
            </field>
            <field>
              <name>ETP</name>
              <bitRange>[15:15]</bitRange>
            </field>
            <field>
              <name>TS_H</name>
              <bitRange>[21:20]</bitRange>
            </field>
          </fields>
        </register>
        <register>
          <name>DIER</name>
          <description>desc DIER</description>
          <addressOffset>0xC</addressOffset>
          <fields>
            <field>
              <name>UIE</name>
              <bitRange>[0:0]</bitRange>
            </field>
            <field>
              <name>CC1IE</name>
              <bitRange>[1:1]</bitRange>
            </field>
            <field>
              <name>CC2IE</name>
              <bitRange>[2:2]</bitRange>
            </field>
            <field>
              <name>CC3IE</name>
              <bitRange>[3:3]</bitRange>
            </field>
            <field>
              <name>CC4IE</name>
              <bitRange>[4:4]</bitRange>
            </field>
            <field>
              <name>TIE</name>
              <bitRange>[6:6]</bitRange>
            </field>
            <field>
              <name>UDE</name>
              <bitRange>[8:8]</bitRange>
            </field>
            <field>
              <name>CC1DE</name>
              <bitRange>[9:9]</bitRange>
            </field>
            <field>
              <name>CC2DE</name>
              <bitRange>[10:10]</bitRange>
            </field>
            <field>
              <name>CC3DE</name>
              <bitRange>[11:11]</bitRange>
            </field>
            <field>
              <name>CC4DE</name>
              <bitRange>[12:12]</bitRange>
            </field>
            <field>
              <name>TDE</name>
              <bitRange>[14:14]</bitRange>
            </field>
          </fields>
        </register>
        <register>
          <name>SR</name>
          <description>desc SR</description>
          <addressOffset>0x10</addressOffset>
          <fields>
            <field>
              <name>UIF</name>
              <bitRange>[0:0]</bitRange>
            </field>
            <field>
              <name>CC1IF</name>
              <bitRange>[1:1]</bitRange>
            </field>
            <field>
              <name>CC2IF</name>
              <bitRange>[2:2]</bitRange>
            </field>
            <field>
              <name>CC3IF</name>
              <bitRange>[3:3]</bitRange>
            </field>
            <field>
              <name>CC4IF</name>
              <bitRange>[4:4]</bitRange>
            </field>
            <field>
              <name>TIF</name>
              <bitRange>[6:6]</bitRange>
            </field>
            <field>
              <name>CC1OF</name>
              <bitRange>[9:9]</bitRange>
            </field>
            <field>
              <name>CC2OF</name>
              <bitRange>[10:10]</bitRange>
            </field>
            <field>
              <name>CC3OF</name>
              <bitRange>[11:11]</bitRange>
            </field>
            <field>
              <name>CC4OF</name>
              <bitRange>[12:12]</bitRange>
            </field>
            <field>
              <name>IC1IR</name>
              <bitRange>[18:18]</bitRange>
            </field>
            <field>
              <name>IC2IR</name>
              <bitRange>[19:19]</bitRange>
            </field>
            <field>
              <name>IC3IR</name>
              <bitRange>[24:24]</bitRange>
            </field>
            <field>
              <name>IC4IR</name>
              <bitRange>[25:25]</bitRange>
            </field>
            <field>
              <name>IC1IF</name>
              <bitRange>[26:26]</bitRange>
            </field>
            <field>
              <name>IC2IF</name>
              <bitRange>[27:27]</bitRange>
            </field>
            <field>
              <name>IC3IF</name>
              <bitRange>[28:28]</bitRange>
            </field>
            <field>
              <name>IC4IF</name>
              <bitRange>[29:29]</bitRange>
            </field>
          </fields>
        </register>
        <register>
          <name>EGR</name>
          <description>desc EGR</description>
          <addressOffset>0x14</addressOffset>
          <fields>
            <field>
              <name>UG</name>
              <bitRange>[0:0]</bitRange>
              <access>read-only</access>
            </field>
            <field>
              <name>CC1G</name>
              <bitRange>[1:1]</bitRange>
              <access>read-only</access>
            </field>
            <field>
              <name>CC2G</name>
              <bitRange>[2:2]</bitRange>
              <access>read-only</access>
            </field>
            <field>
              <name>CC3G</name>
              <bitRange>[3:3]</bitRange>
              <access>read-only</access>
            </field>
            <field>
              <name>CC4G</name>
              <bitRange>[4:4]</bitRange>
              <access>read-only</access>
            </field>
            <field>
              <name>TG</name>
              <bitRange>[6:6]</bitRange>
              <access>read-only</access>
            </field>
          </fields>
        </register>
        <register>
          <name>CCMR1_OUTPUT</name>
          <description>desc CCMR1:OUTPUT</description>
          <addressOffset>0x18</addressOffset>
          <fields>
            <field>
              <name>CC1S</name>
              <bitRange>[1:0]</bitRange>
            </field>
            <field>
              <name>OC1FE</name>
              <bitRange>[2:2]</bitRange>
            </field>
            <field>
              <name>OC1PE</name>
              <bitRange>[3:3]</bitRange>
            </field>
            <field>
              <name>OC1M</name>
              <bitRange>[6:4]</bitRange>
            </field>
            <field>
              <name>OC1CE</name>
              <bitRange>[7:7]</bitRange>
            </field>
            <field>
              <name>CC2S</name>
              <bitRange>[9:8]</bitRange>
            </field>
            <field>
              <name>OC2FE</name>
              <bitRange>[10:10]</bitRange>
            </field>
            <field>
              <name>OC2PE</name>
              <bitRange>[11:11]</bitRange>
            </field>
            <field>
              <name>OC2M</name>
              <bitRange>[14:12]</bitRange>
            </field>
            <field>
              <name>OC2CE</name>
              <bitRange>[15:15]</bitRange>
            </field>
          </fields>
        </register>
        <register>
          <name>CCMR1_INPUT</name>
          <description>desc CCMR1:INPUT</description>
          <alternateRegister>CCMR1_OUTPUT</alternateRegister>
          <addressOffset>0x18</addressOffset>
          <fields>
            <field>
              <name>CC1S</name>
              <bitRange>[1:0]</bitRange>
            </field>
            <field>
              <name>IC1PSC</name>
              <bitRange>[3:2]</bitRange>
            </field>
            <field>
              <name>IC1F</name>
              <bitRange>[7:4]</bitRange>
            </field>
            <field>
              <name>CC2S</name>
              <bitRange>[9:8]</bitRange>
            </field>
            <field>
              <name>IC2PSC</name>
              <bitRange>[11:10]</bitRange>
            </field>
            <field>
              <name>IC2F</name>
              <bitRange>[15:12]</bitRange>
            </field>
          </fields>
        </register>
        <register>
          <name>CCMR2_OUTPUT</name>
          <description>desc CCMR2:OUTPUT</description>
          <addressOffset>0x1C</addressOffset>
          <fields>
            <field>
              <name>CC3S</name>
              <bitRange>[1:0]</bitRange>
            </field>
            <field>
              <name>OC3FE</name>
              <bitRange>[2:2]</bitRange>
            </field>
            <field>
              <name>OC3PE</name>
              <bitRange>[3:3]</bitRange>
            </field>
            <field>
              <name>OC3M</name>
              <bitRange>[6:4]</bitRange>
            </field>
            <field>
              <name>OC3CE</name>
              <bitRange>[7:7]</bitRange>
            </field>
            <field>
              <name>CC4S</name>
              <bitRange>[9:8]</bitRange>
            </field>
            <field>
              <name>OC4FE</name>
              <bitRange>[10:10]</bitRange>
            </field>
            <field>
              <name>OC4PE</name>
              <bitRange>[11:11]</bitRange>
            </field>
            <field>
              <name>OC4M</name>
              <bitRange>[14:12]</bitRange>
            </field>
            <field>
              <name>OC4CE</name>
              <bitRange>[15:15]</bitRange>
            </field>
          </fields>
        </register>
        <register>
          <name>CCMR2_INPUT</name>
          <description>desc CCMR2:INPUT</description>
          <alternateRegister>CCMR2_OUTPUT</alternateRegister>
          <addressOffset>0x1C</addressOffset>
          <fields>
            <field>
              <name>CC3S</name>
              <bitRange>[1:0]</bitRange>
            </field>
            <field>
              <name>IC3PSC</name>
              <bitRange>[3:2]</bitRange>
            </field>
            <field>
              <name>IC3F</name>
              <bitRange>[7:4]</bitRange>
            </field>
            <field>
              <name>CC4S</name>
              <bitRange>[9:8]</bitRange>
            </field>
            <field>
              <name>IC4PSC</name>
              <bitRange>[11:10]</bitRange>
            </field>
            <field>
              <name>IC4F</name>
              <bitRange>[15:12]</bitRange>
            </field>
          </fields>
        </register>
        <register>
          <name>CCER</name>
          <description>desc CCER</description>
          <addressOffset>0x20</addressOffset>
          <fields>
            <field>
              <name>CC1E</name>
              <bitRange>[0:0]</bitRange>
            </field>
            <field>
              <name>CC1P</name>
              <bitRange>[1:1]</bitRange>
            </field>
            <field>
              <name>CC1NP</name>
              <bitRange>[3:3]</bitRange>
            </field>
            <field>
              <name>CC2E</name>
              <bitRange>[4:4]</bitRange>
            </field>
            <field>
              <name>CC2P</name>
              <bitRange>[5:5]</bitRange>
            </field>
            <field>
              <name>CC2NP</name>
              <bitRange>[7:7]</bitRange>
            </field>
            <field>
              <name>CC3E</name>
              <bitRange>[8:8]</bitRange>
            </field>
            <field>
              <name>CC3P</name>
              <bitRange>[9:9]</bitRange>
            </field>
            <field>
              <name>CC3NP</name>
              <bitRange>[11:11]</bitRange>
            </field>
            <field>
              <name>CC4E</name>
              <bitRange>[12:12]</bitRange>
            </field>
            <field>
              <name>CC4P</name>
              <bitRange>[13:13]</bitRange>
            </field>
            <field>
              <name>CC4NP</name>
              <bitRange>[15:15]</bitRange>
            </field>
          </fields>
        </register>
        <register>
          <name>CNT</name>
          <description>desc CNT</description>
          <addressOffset>0x24</addressOffset>
          <fields>
            <field>
              <name>CNT</name>
              <bitRange>[31:0]</bitRange>
            </field>
          </fields>
        </register>
        <register>
          <name>PSC</name>
          <description>desc PSC</description>
          <addressOffset>0x28</addressOffset>
          <fields>
            <field>
              <name>PSC</name>
              <bitRange>[15:0]</bitRange>
            </field>
          </fields>
        </register>
        <register>
          <name>ARR</name>
          <description>desc ARR</description>
          <addressOffset>0x2C</addressOffset>
          <fields>
            <field>
              <name>ARR</name>
              <bitRange>[31:0]</bitRange>
            </field>
          </fields>
        </register>
        <register>
          <name>CCR1</name>
          <description>desc CCR1</description>
          <addressOffset>0x34</addressOffset>
          <fields>
            <field>
              <name>CCR1</name>
              <bitRange>[31:0]</bitRange>
            </field>
          </fields>
        </register>
        <register>
          <name>CCR2</name>
          <description>desc CCR2</description>
          <addressOffset>0x38</addressOffset>
          <fields>
            <field>
              <name>CCR2</name>
              <bitRange>[31:0]</bitRange>
            </field>
          </fields>
        </register>
        <register>
          <name>CCR3</name>
          <description>desc CCR3</description>
          <addressOffset>0x3C</addressOffset>
          <fields>
            <field>
              <name>CCR3</name>
              <bitRange>[31:0]</bitRange>
            </field>
          </fields>
        </register>
        <register>
          <name>CCR4</name>
          <description>desc CCR4</description>
          <addressOffset>0x40</addressOffset>
          <fields>
            <field>
              <name>CCR4</name>
              <bitRange>[31:0]</bitRange>
            </field>
          </fields>
        </register>
        <register>
          <name>TISEL</name>
          <addressOffset>0x5C</addressOffset>
          <fields>
            <field>
              <name>TI1SEL</name>
              <bitRange>[3:0]</bitRange>
              <enumeratedValues>
                <enumeratedValue>
                  <name>0</name>
                  <value>1</value>
                </enumeratedValue>
                <enumeratedValue>
                  <name>1</name>
                  <value>2</value>
                </enumeratedValue>
                <enumeratedValue>
                  <name>2</name>
                  <value>4</value>
                </enumeratedValue>
                <enumeratedValue>
                  <name>3</name>
                  <value>8</value>
                </enumeratedValue>
              </enumeratedValues>
            </field>
            <field>
              <name>TI2SEL</name>
              <bitRange>[11:8]</bitRange>
              <enumeratedValues>
                <enumeratedValue>
                  <name>0</name>
                  <value>1</value>
                </enumeratedValue>
                <enumeratedValue>
                  <name>1</name>
                  <value>2</value>
                </enumeratedValue>
                <enumeratedValue>
                  <name>2</name>
                  <value>4</value>
                </enumeratedValue>
                <enumeratedValue>
                  <name>3</name>
                  <value>8</value>
                </enumeratedValue>
              </enumeratedValues>
            </field>
            <field>
              <name>TI3SEL</name>
              <bitRange>[19:16]</bitRange>
              <enumeratedValues>
                <enumeratedValue>
                  <name>0</name>
                  <value>1</value>
                </enumeratedValue>
                <enumeratedValue>
                  <name>1</name>
                  <value>2</value>
                </enumeratedValue>
                <enumeratedValue>
                  <name>2</name>
                  <value>4</value>
                </enumeratedValue>
                <enumeratedValue>
                  <name>3</name>
                  <value>8</value>
                </enumeratedValue>
              </enumeratedValues>
            </field>
            <field>
              <name>TI4SEL</name>
              <bitRange>[27:24]</bitRange>
              <enumeratedValues>
                <enumeratedValue>
                  <name>0</name>
                  <value>1</value>
                </enumeratedValue>
                <enumeratedValue>
                  <name>1</name>
                  <value>2</value>
                </enumeratedValue>
                <enumeratedValue>
                  <name>2</name>
                  <value>4</value>
                </enumeratedValue>
                <enumeratedValue>
                  <name>3</name>
                  <value>8</value>
                </enumeratedValue>
              </enumeratedValues>
            </field>
          </fields>
        </register>
        <register>
          <name>AF1</name>
          <addressOffset>0x60</addressOffset>
          <fields>
            <field>
              <name>ETRSEL</name>
              <bitRange>[17:14]</bitRange>
              <enumeratedValues>
                <enumeratedValue>
                  <name>0</name>
                  <value>1</value>
                </enumeratedValue>
                <enumeratedValue>
                  <name>1</name>
                  <value>2</value>
                </enumeratedValue>
                <enumeratedValue>
                  <name>2</name>
                  <value>4</value>
                </enumeratedValue>
                <enumeratedValue>
                  <name>3</name>
                  <value>8</value>
                </enumeratedValue>
              </enumeratedValues>
            </field>
          </fields>
        </register>
        <register>
          <name>AF2</name>
          <addressOffset>0x64</addressOffset>
          <fields>
            <field>
              <name>OCRSEL</name>
              <bitRange>[18:16]</bitRange>
              <enumeratedValues>
                <enumeratedValue>
                  <name>0</name>
                  <value>1</value>
                </enumeratedValue>
                <enumeratedValue>
                  <name>1</name>
                  <value>2</value>
                </enumeratedValue>
                <enumeratedValue>
                  <name>2</name>
                  <value>4</value>
                </enumeratedValue>
              </enumeratedValues>
            </field>
          </fields>
        </register>
        <register>
          <name>TIMXDCR</name>
          <addressOffset>0x3DC</addressOffset>
          <fields>
            <field>
              <name>DBA</name>
              <bitRange>[4:0]</bitRange>
            </field>
            <field>
              <name>DBL</name>
              <bitRange>[12:8]</bitRange>
            </field>
          </fields>
        </register>
        <register>
          <name>DMAR</name>
          <description>desc DMAR</description>
          <addressOffset>0x3E0</addressOffset>
          <fields>
            <field>
              <name>DMAB</name>
              <bitRange>[31:0]</bitRange>
            </field>
          </fields>
        </register>
      </registers>
    </peripheral>
    <peripheral derivedFrom="TIM2">
      <name>TIM3</name>
      <description>General purpose timer</description>
      <baseAddress>0x40000400</baseAddress>
      <interrupt>
        <name>TIM3</name>
        <description>TIM3 global Interrupt</description>
        <value>16</value>
      </interrupt>
    </peripheral>
    <peripheral>
      <name>TIM6</name>
      <description>desc TIM</description>
      <groupName>TIM</groupName>
      <baseAddress>0x40001000</baseAddress>
      <addressBlock>
        <offset>0x0</offset>
        <size>0x400</size>
        <usage>registers</usage>
      </addressBlock>
      <interrupt>
        <name>TIM6_LPTIM1_DAC</name>
        <description>TIM6, LPTIM1, DAC global Interrupts</description>
        <value>17</value>
      </interrupt>
      <registers>
        <register>
          <name>CR1</name>
          <description>desc CR1</description>
          <addressOffset>0x0</addressOffset>
          <fields>
            <field>
              <name>CEN</name>
              <bitRange>[0:0]</bitRange>
            </field>
            <field>
              <name>UDIS</name>
              <bitRange>[1:1]</bitRange>
            </field>
            <field>
              <name>URS</name>
              <bitRange>[2:2]</bitRange>
            </field>
            <field>
              <name>OPM</name>
              <bitRange>[3:3]</bitRange>
            </field>
            <field>
              <name>ARPE</name>
              <bitRange>[7:7]</bitRange>
            </field>
          </fields>
        </register>
        <register>
          <name>DIER</name>
          <description>desc DIER</description>
          <addressOffset>0xC</addressOffset>
          <fields>
            <field>
              <name>UIE</name>
              <bitRange>[0:0]</bitRange>
            </field>
            <field>
              <name>UDE</name>
              <bitRange>[8:8]</bitRange>
            </field>
          </fields>
        </register>
        <register>
          <name>SR</name>
          <description>desc SR</description>
          <addressOffset>0x10</addressOffset>
          <fields>
            <field>
              <name>UIF</name>
              <bitRange>[0:0]</bitRange>
            </field>
          </fields>
        </register>
        <register>
          <name>EGR</name>
          <description>desc EGR</description>
          <addressOffset>0x14</addressOffset>
          <fields>
            <field>
              <name>UG</name>
              <bitRange>[0:0]</bitRange>
              <access>read-only</access>
            </field>
          </fields>
        </register>
        <register>
          <name>CNT</name>
          <description>desc CNT</description>
          <addressOffset>0x24</addressOffset>
          <fields>
            <field>
              <name>CNT</name>
              <bitRange>[31:0]</bitRange>
            </field>
          </fields>
        </register>
        <register>
          <name>PSC</name>
          <description>desc PSC</description>
          <addressOffset>0x28</addressOffset>
          <fields>
            <field>
              <name>PSC</name>
              <bitRange>[15:0]</bitRange>
            </field>
          </fields>
        </register>
        <register>
          <name>ARR</name>
          <description>desc ARR</description>
          <addressOffset>0x2C</addressOffset>
          <fields>
            <field>
              <name>ARR</name>
              <bitRange>[31:0]</bitRange>
              <access>read-only</access>
            </field>
          </fields>
        </register>
      </registers>
    </peripheral>
    <peripheral derivedFrom="TIM6">
      <name>TIM7</name>
      <description>desc TIM</description>
      <baseAddress>0x40001400</baseAddress>
      <interrupt>
        <name>TIM7</name>
        <description>TIM7 global Interrupt</description>
        <value>18</value>
      </interrupt>
    </peripheral>
    <peripheral>
      <name>TIM14</name>
      <description>General purpose timer</description>
      <groupName>TIM</groupName>
      <baseAddress>0x40002000</baseAddress>
      <addressBlock>
        <offset>0x0</offset>
        <size>0x400</size>
        <usage>registers</usage>
      </addressBlock>
      <interrupt>
        <name>TIM14</name>
        <description>TIM14 global Interrupt</description>
        <value>19</value>
      </interrupt>
      <registers>
        <register>
          <name>CR1</name>
          <description>desc CR1</description>
          <addressOffset>0x0</addressOffset>
          <resetMask>0x3FF</resetMask>
          <fields>
            <field>
              <name>CEN</name>
              <description>desc CEN</description>
              <bitRange>[0:0]</bitRange>
            </field>
            <field>
              <name>UDIS</name>
              <description>desc UDIS</description>
              <bitRange>[1:1]</bitRange>
            </field>
            <field>
              <name>URS</name>
              <description>desc URS</description>
              <bitRange>[2:2]</bitRange>
            </field>
            <field>
              <name>OPM</name>
              <description>desc OPM</description>
              <bitRange>[3:3]</bitRange>
            </field>
            <field>
              <name>DIR</name>
              <description>desc DIR</description>
              <bitRange>[4:4]</bitRange>
            </field>
            <field>
              <name>CMS</name>
              <description>desc CMS</description>
              <bitRange>[6:5]</bitRange>
              <enumeratedValues>
                <enumeratedValue>
                  <name>0</name>
                  <value>1</value>
                </enumeratedValue>
                <enumeratedValue>
                  <name>1</name>
                  <value>2</value>
                </enumeratedValue>
              </enumeratedValues>
            </field>
            <field>
              <name>ARPE</name>
              <description>desc ARPE</description>
              <bitRange>[7:7]</bitRange>
            </field>
            <field>
              <name>CKD</name>
              <description>desc CKD</description>
              <bitRange>[9:8]</bitRange>
              <enumeratedValues>
                <enumeratedValue>
                  <name>0</name>
                  <value>1</value>
                </enumeratedValue>
                <enumeratedValue>
                  <name>1</name>
                  <value>2</value>
                </enumeratedValue>
              </enumeratedValues>
            </field>
          </fields>
        </register>
        <register>
          <name>DIER</name>
          <description>desc DIER</description>
          <addressOffset>0xC</addressOffset>
          <resetMask>0x5F5F</resetMask>
          <fields>
            <field>
              <name>UIE</name>
              <description>desc UIE</description>
              <bitRange>[0:0]</bitRange>
            </field>
            <field>
              <name>CC1IE</name>
              <description>desc CC1IE</description>
              <bitRange>[1:1]</bitRange>
            </field>
            <field>
              <name>CC2IE</name>
              <description>desc CC2IE</description>
              <bitRange>[2:2]</bitRange>
            </field>
            <field>
              <name>CC3IE</name>
              <description>desc CC3IE</description>
              <bitRange>[3:3]</bitRange>
            </field>
            <field>
              <name>CC4IE</name>
              <description>desc CC4IE</description>
              <bitRange>[4:4]</bitRange>
            </field>
            <field>
              <name>TIE</name>
              <description>desc TIE</description>
              <bitRange>[6:6]</bitRange>
            </field>
            <field>
              <name>UDE</name>
              <description>desc UDE</description>
              <bitRange>[8:8]</bitRange>
            </field>
            <field>
              <name>CC1DE</name>
              <description>desc CC1DE</description>
              <bitRange>[9:9]</bitRange>
            </field>
            <field>
              <name>CC2DE</name>
              <description>desc CC2DE</description>
              <bitRange>[10:10]</bitRange>
            </field>
            <field>
              <name>CC3DE</name>
              <description>desc CC3DE</description>
              <bitRange>[11:11]</bitRange>
            </field>
            <field>
              <name>CC4DE</name>
              <description>desc CC4DE</description>
              <bitRange>[12:12]</bitRange>
            </field>
            <field>
              <name>TDE</name>
              <description>desc TDE</description>
              <bitRange>[14:14]</bitRange>
            </field>
          </fields>
        </register>
        <register>
          <name>SR</name>
          <description>desc SR</description>
          <addressOffset>0x10</addressOffset>
          <resetMask>0x1E5F</resetMask>
          <fields>
            <field>
              <name>UIF</name>
              <description>desc UIF</description>
              <bitRange>[0:0]</bitRange>
            </field>
            <field>
              <name>CC1IF</name>
              <description>desc CC1IF</description>
              <bitRange>[1:1]</bitRange>
            </field>
            <field>
              <name>CC2IF</name>
              <description>desc CC2IF</description>
              <bitRange>[2:2]</bitRange>
            </field>
            <field>
              <name>CC3IF</name>
              <description>desc CC3IF</description>
              <bitRange>[3:3]</bitRange>
            </field>
            <field>
              <name>CC4IF</name>
              <description>desc CC4IF</description>
              <bitRange>[4:4]</bitRange>
            </field>
            <field>
              <name>TIF</name>
              <description>desc TIF</description>
              <bitRange>[6:6]</bitRange>
            </field>
            <field>
              <name>CC1OF</name>
              <description>desc CC1OF</description>
              <bitRange>[9:9]</bitRange>
            </field>
            <field>
              <name>CC2OF</name>
              <description>desc CC2OF</description>
              <bitRange>[10:10]</bitRange>
            </field>
            <field>
              <name>CC3OF</name>
              <description>desc CC3OF</description>
              <bitRange>[11:11]</bitRange>
            </field>
            <field>
              <name>CC4OF</name>
              <description>desc CC4OF</description>
              <bitRange>[12:12]</bitRange>
            </field>
          </fields>
        </register>
        <register>
          <name>EGR</name>
          <description>desc EGR</description>
          <addressOffset>0x14</addressOffset>
          <access>write-only</access>
          <resetMask>0x5F</resetMask>
          <fields>
            <field>
              <name>UG</name>
              <description>desc UG</description>
              <bitRange>[0:0]</bitRange>
              <access>write-only</access>
            </field>
            <field>
              <name>CC1G</name>
              <description>Capture/Compare 1 Generation</description>
              <bitRange>[1:1]</bitRange>
              <access>write-only</access>
            </field>
            <field>
              <name>CC2G</name>
              <description>desc CC2G</description>
              <bitRange>[2:2]</bitRange>
              <access>write-only</access>
            </field>
            <field>
              <name>CC3G</name>
              <description>desc CC3G</description>
              <bitRange>[3:3]</bitRange>
              <access>write-only</access>
            </field>
            <field>
              <name>CC4G</name>
              <description>desc CC4G</description>
              <bitRange>[4:4]</bitRange>
              <access>write-only</access>
            </field>
            <field>
              <name>TG</name>
              <description>desc TG</description>
              <bitRange>[6:6]</bitRange>
              <access>write-only</access>
            </field>
          </fields>
        </register>
        <register>
          <name>CCMR1_OUTPUT</name>
          <description>desc CCMR1:OUTPUT</description>
          <addressOffset>0x18</addressOffset>
          <resetMask>0xFFFF</resetMask>
          <fields>
            <field>
              <name>CC1S</name>
              <description>desc CC1S</description>
              <bitRange>[1:0]</bitRange>
            </field>
            <field>
              <name>OC1FE</name>
              <description>desc OC1FE</description>
              <bitRange>[2:2]</bitRange>
            </field>
            <field>
              <name>OC1PE</name>
              <description>desc OC1PE</description>
              <bitRange>[3:3]</bitRange>
            </field>
            <field>
              <name>OC1M</name>
              <description>desc OC1M</description>
              <bitRange>[6:4]</bitRange>
            </field>
            <field>
              <name>OC1CE</name>
              <description>desc OC1CE</description>
              <bitRange>[7:7]</bitRange>
            </field>
            <field>
              <name>CC2S</name>
              <description>desc CC2S</description>
              <bitRange>[9:8]</bitRange>
            </field>
            <field>
              <name>OC2FE</name>
              <description>desc OC2FE</description>
              <bitRange>[10:10]</bitRange>
            </field>
            <field>
              <name>OC2PE</name>
              <description>desc OC2PE</description>
              <bitRange>[11:11]</bitRange>
            </field>
            <field>
              <name>OC2M</name>
              <description>desc OC2M</description>
              <bitRange>[14:12]</bitRange>
            </field>
            <field>
              <name>OC2CE</name>
              <description>desc OC2CE</description>
              <bitRange>[15:15]</bitRange>
            </field>
          </fields>
        </register>
        <register>
          <name>CCMR1_INPUT</name>
          <description>desc CCMR1:INPUT</description>
          <alternateRegister>CCMR1_OUTPUT</alternateRegister>
          <addressOffset>0x18</addressOffset>
          <resetMask>0xFFFF</resetMask>
          <fields>
            <field>
              <name>CC1S</name>
              <description>desc CC1S</description>
              <bitRange>[1:0]</bitRange>
            </field>
            <field>
              <name>IC1PSC</name>
              <description>desc IC1PSC</description>
              <bitRange>[3:2]</bitRange>
            </field>
            <field>
              <name>IC1F</name>
              <description>desc IC1F</description>
              <bitRange>[7:4]</bitRange>
            </field>
            <field>
              <name>CC2S</name>
              <description>desc CC2S</description>
              <bitRange>[9:8]</bitRange>
            </field>
            <field>
              <name>IC2PSC</name>
              <description>desc IC2PSC</description>
              <bitRange>[11:10]</bitRange>
            </field>
            <field>
              <name>IC2F</name>
              <description>desc IC2F</description>
              <bitRange>[15:12]</bitRange>
            </field>
          </fields>
        </register>
        <register>
          <name>CCER</name>
          <description>desc CCER</description>
          <addressOffset>0x20</addressOffset>
          <resetMask>0x3333</resetMask>
          <fields>
            <field>
              <name>CC1E</name>
              <description>desc CC1E</description>
              <bitRange>[0:0]</bitRange>
            </field>
            <field>
              <name>CC1P</name>
              <description>desc CC1P</description>
              <bitRange>[1:1]</bitRange>
            </field>
            <field>
              <name>CC2E</name>
              <description>desc CC2E</description>
              <bitRange>[4:4]</bitRange>
            </field>
            <field>
              <name>CC2P</name>
              <description>desc CC2P</description>
              <bitRange>[5:5]</bitRange>
            </field>
            <field>
              <name>CC3E</name>
              <description>desc CC3E</description>
              <bitRange>[8:8]</bitRange>
            </field>
            <field>
              <name>CC3P</name>
              <description>desc CC3P</description>
              <bitRange>[9:9]</bitRange>
            </field>
            <field>
              <name>CC4E</name>
              <description>desc CC4E</description>
              <bitRange>[12:12]</bitRange>
            </field>
            <field>
              <name>CC4P</name>
              <description>desc CC4P</description>
              <bitRange>[13:13]</bitRange>
            </field>
          </fields>
        </register>
        <register>
          <name>CNT</name>
          <description>desc CNT</description>
          <addressOffset>0x24</addressOffset>
          <resetMask>0xFFFF</resetMask>
          <fields>
            <field>
              <name>CNT</name>
              <description>desc CNT</description>
              <bitRange>[15:0]</bitRange>
            </field>
          </fields>
        </register>
        <register>
          <name>PSC</name>
          <description>desc PSC</description>
          <addressOffset>0x28</addressOffset>
          <resetMask>0xFFFF</resetMask>
          <fields>
            <field>
              <name>PSC</name>
              <description>desc PSC</description>
              <bitRange>[15:0]</bitRange>
            </field>
          </fields>
        </register>
        <register>
          <name>ARR</name>
          <description>desc ARR</description>
          <addressOffset>0x2C</addressOffset>
          <resetValue>0xFFFF</resetValue>
          <resetMask>0xFFFF</resetMask>
          <fields>
            <field>
              <name>ARR</name>
              <description>desc ARR</description>
              <bitRange>[15:0]</bitRange>
            </field>
          </fields>
        </register>
        <register>
          <name>CCR1</name>
          <description>desc CCR1</description>
          <addressOffset>0x34</addressOffset>
          <resetMask>0xFFFF</resetMask>
          <fields>
            <field>
              <name>CCR1</name>
              <description>desc CCR1</description>
              <bitRange>[15:0]</bitRange>
            </field>
          </fields>
        </register>
        <register>
          <name>OR</name>
          <description>desc OR</description>
          <addressOffset>0x50</addressOffset>
          <fields>
            <field>
              <name>TI1_RMP</name>
              <description>desc TI1_RMP</description>
              <bitRange>[1:0]</bitRange>
            </field>
          </fields>
        </register>
      </registers>
    </peripheral>
    <peripheral>
      <name>TIM15</name>
      <baseAddress>0x40014000</baseAddress>
      <addressBlock>
        <offset>0x0</offset>
        <size>0x400</size>
        <usage>registers</usage>
      </addressBlock>
      <interrupt>
        <name>TIM15</name>
        <description>TIM15 global Interrupt</description>
        <value>20</value>
      </interrupt>
      <registers>
        <register>
          <name>CR1</name>
          <description>desc CR1</description>
          <addressOffset>0x0</addressOffset>
          <resetMask>0x3FF</resetMask>
          <fields>
            <field>
              <name>CEN</name>
              <description>desc CEN</description>
              <bitRange>[0:0]</bitRange>
            </field>
            <field>
              <name>UDIS</name>
              <description>desc UDIS</description>
              <bitRange>[1:1]</bitRange>
            </field>
            <field>
              <name>URS</name>
              <description>desc URS</description>
              <bitRange>[2:2]</bitRange>
            </field>
            <field>
              <name>OPM</name>
              <description>desc OPM</description>
              <bitRange>[3:3]</bitRange>
            </field>
            <field>
              <name>DIR</name>
              <description>desc DIR</description>
              <bitRange>[4:4]</bitRange>
            </field>
            <field>
              <name>CMS</name>
              <description>desc CMS</description>
              <bitRange>[6:5]</bitRange>
            </field>
            <field>
              <name>ARPE</name>
              <description>desc ARPE</description>
              <bitRange>[7:7]</bitRange>
            </field>
            <field>
              <name>CKD</name>
              <description>desc CKD</description>
              <bitRange>[9:8]</bitRange>
            </field>
          </fields>
        </register>
        <register>
          <name>CR2</name>
          <description>desc CR2</description>
          <addressOffset>0x4</addressOffset>
          <resetMask>0xF8</resetMask>
          <fields>
            <field>
              <name>CCDS</name>
              <description>desc CCDS</description>
              <bitRange>[3:3]</bitRange>
            </field>
            <field>
              <name>MMS</name>
              <description>desc MMS</description>
              <bitRange>[6:4]</bitRange>
            </field>
            <field>
              <name>TI1S</name>
              <description>desc TI1S</description>
              <bitRange>[7:7]</bitRange>
            </field>
          </fields>
        </register>
        <register>
          <name>SMCR</name>
          <description>desc SMCR</description>
          <addressOffset>0x8</addressOffset>
          <resetMask>0xFFF7</resetMask>
          <fields>
            <field>
              <name>SMS</name>
              <description>desc SMS</description>
              <bitRange>[2:0]</bitRange>
            </field>
            <field>
              <name>TS</name>
              <description>desc TS</description>
              <bitRange>[6:4]</bitRange>
            </field>
            <field>
              <name>MSM</name>
              <description>desc MSM</description>
              <bitRange>[7:7]</bitRange>
            </field>
            <field>
              <name>ETF</name>
              <description>desc ETF</description>
              <bitRange>[11:8]</bitRange>
            </field>
            <field>
              <name>ETPS</name>
              <description>desc ETPS</description>
              <bitRange>[13:12]</bitRange>
            </field>
            <field>
              <name>ECE</name>
              <description>desc ECE</description>
              <bitRange>[14:14]</bitRange>
            </field>
            <field>
              <name>ETP</name>
              <description>desc ETP</description>
              <bitRange>[15:15]</bitRange>
            </field>
          </fields>
        </register>
        <register>
          <name>DIER</name>
          <description>desc DIER</description>
          <addressOffset>0xC</addressOffset>
          <resetMask>0x5F5F</resetMask>
          <fields>
            <field>
              <name>UIE</name>
              <description>desc UIE</description>
              <bitRange>[0:0]</bitRange>
            </field>
            <field>
              <name>CC1IE</name>
              <description>desc CC1IE</description>
              <bitRange>[1:1]</bitRange>
            </field>
            <field>
              <name>CC2IE</name>
              <description>desc CC2IE</description>
              <bitRange>[2:2]</bitRange>
            </field>
            <field>
              <name>CC3IE</name>
              <description>desc CC3IE</description>
              <bitRange>[3:3]</bitRange>
            </field>
            <field>
              <name>CC4IE</name>
              <description>desc CC4IE</description>
              <bitRange>[4:4]</bitRange>
            </field>
            <field>
              <name>TIE</name>
              <description>desc TIE</description>
              <bitRange>[6:6]</bitRange>
            </field>
            <field>
              <name>UDE</name>
              <description>desc UDE</description>
              <bitRange>[8:8]</bitRange>
            </field>
            <field>
              <name>CC1DE</name>
              <description>desc CC1DE</description>
              <bitRange>[9:9]</bitRange>
            </field>
            <field>
              <name>CC2DE</name>
              <description>desc CC2DE</description>
              <bitRange>[10:10]</bitRange>
            </field>
            <field>
              <name>CC3DE</name>
              <description>desc CC3DE</description>
              <bitRange>[11:11]</bitRange>
            </field>
            <field>
              <name>CC4DE</name>
              <description>desc CC4DE</description>
              <bitRange>[12:12]</bitRange>
            </field>
            <field>
              <name>TDE</name>
              <description>desc TDE</description>
              <bitRange>[14:14]</bitRange>
            </field>
          </fields>
        </register>
        <register>
          <name>SR</name>
          <description>desc SR</description>
          <addressOffset>0x10</addressOffset>
          <resetMask>0x1E5F</resetMask>
          <fields>
            <field>
              <name>UIF</name>
              <description>desc UIF</description>
              <bitRange>[0:0]</bitRange>
            </field>
            <field>
              <name>CC1IF</name>
              <description>desc CC1IF</description>
              <bitRange>[1:1]</bitRange>
            </field>
            <field>
              <name>CC2IF</name>
              <description>desc CC2IF</description>
              <bitRange>[2:2]</bitRange>
            </field>
            <field>
              <name>CC3IF</name>
              <description>desc CC3IF</description>
              <bitRange>[3:3]</bitRange>
            </field>
            <field>
              <name>CC4IF</name>
              <description>desc CC4IF</description>
              <bitRange>[4:4]</bitRange>
            </field>
            <field>
              <name>COMIF</name>
              <description>desc COMIF</description>
              <bitRange>[5:5]</bitRange>
            </field>
            <field>
              <name>TIF</name>
              <description>desc TIF</description>
              <bitRange>[6:6]</bitRange>
            </field>
            <field>
              <name>BIF</name>
              <description>desc BIF</description>
              <bitRange>[7:7]</bitRange>
            </field>
            <field>
              <name>CC1OF</name>
              <description>desc CC1OF</description>
              <bitRange>[9:9]</bitRange>
            </field>
            <field>
              <name>CC2OF</name>
              <description>desc CC2OF</description>
              <bitRange>[10:10]</bitRange>
            </field>
            <field>
              <name>CC3OF</name>
              <description>desc CC3OF</description>
              <bitRange>[11:11]</bitRange>
            </field>
            <field>
              <name>CC4OF</name>
              <description>desc CC4OF</description>
              <bitRange>[12:12]</bitRange>
            </field>
            <field>
              <name>IC1IR</name>
              <description>desc IC1IR</description>
              <bitRange>[16:16]</bitRange>
            </field>
            <field>
              <name>IC2IR</name>
              <description>desc IC2IR</description>
              <bitRange>[17:17]</bitRange>
            </field>
            <field>
              <name>IC3IR</name>
              <description>desc IC3IR</description>
              <bitRange>[18:18]</bitRange>
            </field>
            <field>
              <name>IC4IR</name>
              <description>desc IC3IR</description>
              <bitRange>[19:19]</bitRange>
            </field>
            <field>
              <name>IC1IF</name>
              <description>desc IC1IF</description>
              <bitRange>[20:20]</bitRange>
            </field>
            <field>
              <name>IC2IF</name>
              <description>desc IC2IF</description>
              <bitRange>[21:21]</bitRange>
            </field>
            <field>
              <name>IC3IF</name>
              <description>desc IC3IF</description>
              <bitRange>[22:22]</bitRange>
            </field>
            <field>
              <name>IC4IF</name>
              <description>desc IC3IF</description>
              <bitRange>[23:23]</bitRange>
            </field>
          </fields>
        </register>
        <register>
          <name>EGR</name>
          <description>desc EGR</description>
          <addressOffset>0x14</addressOffset>
          <access>write-only</access>
          <resetMask>0x5F</resetMask>
          <fields>
            <field>
              <name>UG</name>
              <description>desc UG</description>
              <bitRange>[0:0]</bitRange>
              <access>write-only</access>
            </field>
            <field>
              <name>CC1G</name>
              <description>Capture/Compare 1 Generation</description>
              <bitRange>[1:1]</bitRange>
              <access>write-only</access>
            </field>
            <field>
              <name>CC2G</name>
              <description>desc CC2G</description>
              <bitRange>[2:2]</bitRange>
              <access>write-only</access>
            </field>
            <field>
              <name>CC3G</name>
              <description>desc CC3G</description>
              <bitRange>[3:3]</bitRange>
              <access>write-only</access>
            </field>
            <field>
              <name>CC4G</name>
              <description>desc CC4G</description>
              <bitRange>[4:4]</bitRange>
              <access>write-only</access>
            </field>
            <field>
              <name>TG</name>
              <description>desc TG</description>
              <bitRange>[6:6]</bitRange>
              <access>write-only</access>
            </field>
          </fields>
        </register>
        <register>
          <name>CCMR1_OUTPUT</name>
          <description>desc CCMR1:OUTPUT</description>
          <addressOffset>0x18</addressOffset>
          <resetMask>0xFFFF</resetMask>
          <fields>
            <field>
              <name>CC1S</name>
              <description>desc CC1S</description>
              <bitRange>[1:0]</bitRange>
            </field>
            <field>
              <name>OC1FE</name>
              <description>desc OC1FE</description>
              <bitRange>[2:2]</bitRange>
            </field>
            <field>
              <name>OC1PE</name>
              <description>desc OC1PE</description>
              <bitRange>[3:3]</bitRange>
            </field>
            <field>
              <name>OC1M</name>
              <description>desc OC1M</description>
              <bitRange>[6:4]</bitRange>
            </field>
            <field>
              <name>OC1CE</name>
              <description>desc OC1CE</description>
              <bitRange>[7:7]</bitRange>
            </field>
            <field>
              <name>CC2S</name>
              <description>desc CC2S</description>
              <bitRange>[9:8]</bitRange>
            </field>
            <field>
              <name>OC2FE</name>
              <description>desc OC2FE</description>
              <bitRange>[10:10]</bitRange>
            </field>
            <field>
              <name>OC2PE</name>
              <description>desc OC2PE</description>
              <bitRange>[11:11]</bitRange>
            </field>
            <field>
              <name>OC2M</name>
              <description>desc OC2M</description>
              <bitRange>[14:12]</bitRange>
            </field>
            <field>
              <name>OC2CE</name>
              <description>desc OC2CE</description>
              <bitRange>[15:15]</bitRange>
            </field>
          </fields>
        </register>
        <register>
          <name>CCMR1_INPUT</name>
          <description>desc CCMR1:INPUT</description>
          <alternateRegister>CCMR1_OUTPUT</alternateRegister>
          <addressOffset>0x18</addressOffset>
          <resetMask>0xFFFF</resetMask>
          <fields>
            <field>
              <name>CC1S</name>
              <description>desc CC1S</description>
              <bitRange>[1:0]</bitRange>
            </field>
            <field>
              <name>IC1PSC</name>
              <description>desc IC1PSC</description>
              <bitRange>[3:2]</bitRange>
            </field>
            <field>
              <name>IC1F</name>
              <description>desc IC1F</description>
              <bitRange>[7:4]</bitRange>
            </field>
            <field>
              <name>CC2S</name>
              <description>desc CC2S</description>
              <bitRange>[9:8]</bitRange>
            </field>
            <field>
              <name>IC2PSC</name>
              <description>desc IC2PSC</description>
              <bitRange>[11:10]</bitRange>
            </field>
            <field>
              <name>IC2F</name>
              <description>desc IC2F</description>
              <bitRange>[15:12]</bitRange>
            </field>
          </fields>
        </register>
        <register>
          <name>CCER</name>
          <description>desc CCER</description>
          <addressOffset>0x20</addressOffset>
          <resetMask>0x3333</resetMask>
          <fields>
            <field>
              <name>CC1E</name>
              <description>desc CC1E</description>
              <bitRange>[0:0]</bitRange>
            </field>
            <field>
              <name>CC1P</name>
              <description>desc CC1P</description>
              <bitRange>[1:1]</bitRange>
            </field>
            <field>
              <name>CC2E</name>
              <description>desc CC2E</description>
              <bitRange>[4:4]</bitRange>
            </field>
            <field>
              <name>CC2P</name>
              <description>desc CC2P</description>
              <bitRange>[5:5]</bitRange>
            </field>
            <field>
              <name>CC3E</name>
              <description>desc CC3E</description>
              <bitRange>[8:8]</bitRange>
            </field>
            <field>
              <name>CC3P</name>
              <description>desc CC3P</description>
              <bitRange>[9:9]</bitRange>
            </field>
            <field>
              <name>CC4E</name>
              <description>desc CC4E</description>
              <bitRange>[12:12]</bitRange>
            </field>
            <field>
              <name>CC4P</name>
              <description>desc CC4P</description>
              <bitRange>[13:13]</bitRange>
            </field>
          </fields>
        </register>
        <register>
          <name>CNT</name>
          <description>desc CNT</description>
          <addressOffset>0x24</addressOffset>
          <resetMask>0xFFFF</resetMask>
          <fields>
            <field>
              <name>CNT</name>
              <description>desc CNT</description>
              <bitRange>[15:0]</bitRange>
            </field>
          </fields>
        </register>
        <register>
          <name>PSC</name>
          <description>desc PSC</description>
          <addressOffset>0x28</addressOffset>
          <resetMask>0xFFFF</resetMask>
          <fields>
            <field>
              <name>PSC</name>
              <description>desc PSC</description>
              <bitRange>[15:0]</bitRange>
            </field>
          </fields>
        </register>
        <register>
          <name>ARR</name>
          <description>desc ARR</description>
          <addressOffset>0x2C</addressOffset>
          <resetValue>0xFFFF</resetValue>
          <resetMask>0xFFFF</resetMask>
          <fields>
            <field>
              <name>ARR</name>
              <description>desc ARR</description>
              <bitRange>[15:0]</bitRange>
            </field>
          </fields>
        </register>
        <register>
          <name>RCR</name>
          <description>desc RCR</description>
          <addressOffset>0x30</addressOffset>
          <resetValue>0xFFFF</resetValue>
          <resetMask>0xFFFF</resetMask>
          <fields>
            <field>
              <name>REP</name>
              <description>desc REP</description>
              <bitRange>[7:0]</bitRange>
            </field>
          </fields>
        </register>
        <register>
          <name>CCR1</name>
          <description>desc CCR1</description>
          <addressOffset>0x34</addressOffset>
          <resetMask>0xFFFF</resetMask>
          <fields>
            <field>
              <name>CCR1</name>
              <description>desc CCR1</description>
              <bitRange>[15:0]</bitRange>
            </field>
          </fields>
        </register>
        <register>
          <name>CCR2</name>
          <description>desc CCR2</description>
          <addressOffset>0x38</addressOffset>
          <resetMask>0xFFFF</resetMask>
          <fields>
            <field>
              <name>CCR2</name>
              <description>desc CCR2</description>
              <bitRange>[15:0]</bitRange>
            </field>
          </fields>
        </register>
        <register>
          <name>BDTR</name>
          <description>desc BDTR</description>
          <addressOffset>0x44</addressOffset>
          <resetMask>0xFFFF</resetMask>
          <fields>
            <field>
              <name>DTG</name>
              <description>desc DTG</description>
              <bitRange>[7:0]</bitRange>
            </field>
            <field>
              <name>LOCK</name>
              <description>desc LOCK</description>
              <bitRange>[9:8]</bitRange>
            </field>
            <field>
              <name>OSSI</name>
              <description>desc OSSI</description>
              <bitRange>[10:10]</bitRange>
            </field>
            <field>
              <name>OSSR</name>
              <description>desc OSSR</description>
              <bitRange>[11:11]</bitRange>
            </field>
            <field>
              <name>BKE</name>
              <description>desc BKE</description>
              <bitRange>[12:12]</bitRange>
            </field>
            <field>
              <name>BKP</name>
              <description>desc BKP</description>
              <bitRange>[13:13]</bitRange>
            </field>
            <field>
              <name>AOE</name>
              <description>desc AOE</description>
              <bitRange>[14:14]</bitRange>
            </field>
            <field>
              <name>MOE</name>
              <description>desc MOE</description>
              <bitRange>[15:15]</bitRange>
            </field>
          </fields>
        </register>
        <register>
          <name>DCR</name>
          <description>desc DCR</description>
          <addressOffset>0x48</addressOffset>
          <resetMask>0x1F1F</resetMask>
          <fields>
            <field>
              <name>DBA</name>
              <description>desc DBA</description>
              <bitRange>[4:0]</bitRange>
            </field>
            <field>
              <name>DBL</name>
              <description>desc DBL</description>
              <bitRange>[12:8]</bitRange>
            </field>
          </fields>
        </register>
        <register>
          <name>DMAR</name>
          <description>desc DMAR</description>
          <addressOffset>0x4C</addressOffset>
          <resetMask>0xFFFF</resetMask>
          <fields>
            <field>
              <name>DMAB</name>
              <description>desc DMAB</description>
              <bitRange>[15:0]</bitRange>
            </field>
          </fields>
        </register>
      </registers>
    </peripheral>
    <peripheral>
      <name>TIM16</name>
      <description>General purpose timer</description>
      <groupName>TIM</groupName>
      <baseAddress>0x40014400</baseAddress>
      <addressBlock>
        <offset>0x0</offset>
        <size>0x400</size>
        <usage>registers</usage>
      </addressBlock>
      <interrupt>
        <name>TIM16</name>
        <description>TIM16 global Interrupt</description>
        <value>21</value>
      </interrupt>
      <registers>
        <register>
          <name>CR1</name>
          <description>desc CR1</description>
          <addressOffset>0x0</addressOffset>
          <fields>
            <field>
              <name>CEN</name>
              <bitRange>[0:0]</bitRange>
            </field>
            <field>
              <name>UDIS</name>
              <bitRange>[1:1]</bitRange>
            </field>
            <field>
              <name>URS</name>
              <bitRange>[2:2]</bitRange>
            </field>
            <field>
              <name>OPM</name>
              <bitRange>[3:3]</bitRange>
            </field>
            <field>
              <name>ARPE</name>
              <bitRange>[7:7]</bitRange>
            </field>
            <field>
              <name>CKD</name>
              <bitRange>[9:8]</bitRange>
              <enumeratedValues>
                <enumeratedValue>
                  <name>0</name>
                  <value>1</value>
                </enumeratedValue>
                <enumeratedValue>
                  <name>1</name>
                  <value>2</value>
                </enumeratedValue>
              </enumeratedValues>
            </field>
          </fields>
        </register>
        <register>
          <name>CR2</name>
          <description>desc CR2</description>
          <addressOffset>0x4</addressOffset>
          <fields>
            <field>
              <name>CCPC</name>
              <bitRange>[0:0]</bitRange>
            </field>
            <field>
              <name>CCDS</name>
              <bitRange>[3:3]</bitRange>
            </field>
            <field>
              <name>MMS</name>
              <bitRange>[6:4]</bitRange>
            </field>
            <field>
              <name>OIS1</name>
              <bitRange>[8:8]</bitRange>
            </field>
            <field>
              <name>OIS1N</name>
              <bitRange>[9:9]</bitRange>
            </field>
            <field>
              <name>OIS2</name>
              <bitRange>[10:10]</bitRange>
            </field>
          </fields>
        </register>
        <register>
          <name>DIER</name>
          <description>desc DIER</description>
          <addressOffset>0xC</addressOffset>
          <fields>
            <field>
              <name>UIE</name>
              <bitRange>[0:0]</bitRange>
            </field>
            <field>
              <name>CC1IE</name>
              <bitRange>[1:1]</bitRange>
            </field>
            <field>
              <name>COMIE</name>
              <bitRange>[5:5]</bitRange>
            </field>
            <field>
              <name>BIE</name>
              <bitRange>[7:7]</bitRange>
            </field>
            <field>
              <name>UDE</name>
              <bitRange>[8:8]</bitRange>
            </field>
            <field>
              <name>CC1DE</name>
              <bitRange>[9:9]</bitRange>
            </field>
          </fields>
        </register>
        <register>
          <name>SR</name>
          <description>desc SR</description>
          <addressOffset>0x10</addressOffset>
          <fields>
            <field>
              <name>UIF</name>
              <bitRange>[0:0]</bitRange>
            </field>
            <field>
              <name>CC1IF</name>
              <bitRange>[1:1]</bitRange>
            </field>
            <field>
              <name>COMIF</name>
              <bitRange>[5:5]</bitRange>
            </field>
            <field>
              <name>BIF</name>
              <bitRange>[7:7]</bitRange>
            </field>
            <field>
              <name>CC1OF</name>
              <bitRange>[9:9]</bitRange>
            </field>
            <field>
              <name>IC1IR</name>
              <bitRange>[16:16]</bitRange>
            </field>
            <field>
              <name>IC1IF</name>
              <bitRange>[20:20]</bitRange>
            </field>
          </fields>
        </register>
        <register>
          <name>EGR</name>
          <description>desc EGR</description>
          <addressOffset>0x14</addressOffset>
          <fields>
            <field>
              <name>UG</name>
              <bitRange>[0:0]</bitRange>
              <access>read-only</access>
            </field>
            <field>
              <name>CC1G</name>
              <bitRange>[1:1]</bitRange>
              <access>read-only</access>
            </field>
            <field>
              <name>COMG</name>
              <bitRange>[5:5]</bitRange>
              <access>read-only</access>
            </field>
            <field>
              <name>BG</name>
              <bitRange>[7:7]</bitRange>
              <access>read-only</access>
            </field>
          </fields>
        </register>
        <register>
          <name>CCMR1_OUTPUT</name>
          <description>desc CCMR1:OUTPUT</description>
          <addressOffset>0x18</addressOffset>
          <fields>
            <field>
              <name>CC1S</name>
              <bitRange>[1:0]</bitRange>
            </field>
            <field>
              <name>OC1FE</name>
              <bitRange>[2:2]</bitRange>
            </field>
            <field>
              <name>OC1PE</name>
              <bitRange>[3:3]</bitRange>
            </field>
            <field>
              <name>OC1M</name>
              <bitRange>[6:4]</bitRange>
            </field>
            <field>
              <name>OC1CE</name>
              <bitRange>[7:7]</bitRange>
            </field>
          </fields>
        </register>
        <register>
          <name>CCMR1_INPUT</name>
          <description>desc CCMR1:INPUT</description>
          <alternateRegister>CCMR1_OUTPUT</alternateRegister>
          <addressOffset>0x18</addressOffset>
          <fields>
            <field>
              <name>CC1S</name>
              <bitRange>[1:0]</bitRange>
            </field>
            <field>
              <name>IC1PSC</name>
              <bitRange>[3:2]</bitRange>
            </field>
            <field>
              <name>IC1F</name>
              <bitRange>[7:4]</bitRange>
            </field>
            <field>
              <name>CC2S</name>
              <bitRange>[9:8]</bitRange>
            </field>
            <field>
              <name>IC2PSC</name>
              <bitRange>[11:10]</bitRange>
            </field>
            <field>
              <name>IC2F</name>
              <bitRange>[15:12]</bitRange>
            </field>
          </fields>
        </register>
        <register>
          <name>CCER</name>
          <description>desc CCER</description>
          <addressOffset>0x20</addressOffset>
          <fields>
            <field>
              <name>CC1E</name>
              <bitRange>[0:0]</bitRange>
            </field>
            <field>
              <name>CC1P</name>
              <bitRange>[1:1]</bitRange>
            </field>
            <field>
              <name>CC1NE</name>
              <bitRange>[2:2]</bitRange>
            </field>
            <field>
              <name>CC1NP</name>
              <bitRange>[3:3]</bitRange>
            </field>
          </fields>
        </register>
        <register>
          <name>CNT</name>
          <description>desc CNT</description>
          <addressOffset>0x24</addressOffset>
          <fields>
            <field>
              <name>CNT</name>
              <bitRange>[15:0]</bitRange>
            </field>
          </fields>
        </register>
        <register>
          <name>PSC</name>
          <description>desc PSC</description>
          <addressOffset>0x28</addressOffset>
          <fields>
            <field>
              <name>PSC</name>
              <bitRange>[15:0]</bitRange>
            </field>
          </fields>
        </register>
        <register>
          <name>ARR</name>
          <description>desc ARR</description>
          <addressOffset>0x2C</addressOffset>
          <fields>
            <field>
              <name>ARR</name>
              <bitRange>[15:0]</bitRange>
            </field>
          </fields>
        </register>
        <register>
          <name>RCR</name>
          <description>desc RCR</description>
          <addressOffset>0x30</addressOffset>
          <fields>
            <field>
              <name>REP</name>
              <bitRange>[7:0]</bitRange>
            </field>
          </fields>
        </register>
        <register>
          <name>CCR1</name>
          <description>desc CCR1</description>
          <addressOffset>0x34</addressOffset>
          <fields>
            <field>
              <name>CCR1</name>
              <bitRange>[15:0]</bitRange>
            </field>
          </fields>
        </register>
        <register>
          <name>BDTR</name>
          <description>desc BDTR</description>
          <addressOffset>0x44</addressOffset>
          <fields>
            <field>
              <name>DTG</name>
              <bitRange>[7:0]</bitRange>
            </field>
            <field>
              <name>LOCK</name>
              <bitRange>[9:8]</bitRange>
              <enumeratedValues>
                <enumeratedValue>
                  <name>0</name>
                  <value>1</value>
                </enumeratedValue>
                <enumeratedValue>
                  <name>1</name>
                  <value>2</value>
                </enumeratedValue>
              </enumeratedValues>
            </field>
            <field>
              <name>OSSI</name>
              <bitRange>[10:10]</bitRange>
            </field>
            <field>
              <name>OSSR</name>
              <bitRange>[11:11]</bitRange>
            </field>
            <field>
              <name>BKE</name>
              <bitRange>[12:12]</bitRange>
            </field>
            <field>
              <name>BKP</name>
              <bitRange>[13:13]</bitRange>
            </field>
            <field>
              <name>AOE</name>
              <bitRange>[14:14]</bitRange>
            </field>
            <field>
              <name>MOE</name>
              <bitRange>[15:15]</bitRange>
            </field>
          </fields>
        </register>
        <register>
          <name>TISEL</name>
          <addressOffset>0x5C</addressOffset>
          <fields>
            <field>
              <name>TI1SEL</name>
              <bitRange>[3:0]</bitRange>
              <enumeratedValues>
                <enumeratedValue>
                  <name>0</name>
                  <value>1</value>
                </enumeratedValue>
                <enumeratedValue>
                  <name>1</name>
                  <value>2</value>
                </enumeratedValue>
                <enumeratedValue>
                  <name>2</name>
                  <value>4</value>
                </enumeratedValue>
                <enumeratedValue>
                  <name>3</name>
                  <value>8</value>
                </enumeratedValue>
              </enumeratedValues>
            </field>
          </fields>
        </register>
        <register>
          <name>AF1</name>
          <addressOffset>0x60</addressOffset>
          <fields>
            <field>
              <name>BKINE</name>
              <bitRange>[0:0]</bitRange>
            </field>
            <field>
              <name>BKCMP1E</name>
              <bitRange>[1:1]</bitRange>
            </field>
            <field>
              <name>BKCMP2E</name>
              <bitRange>[2:2]</bitRange>
            </field>
            <field>
              <name>BKINP</name>
              <bitRange>[9:9]</bitRange>
            </field>
            <field>
              <name>BKCMP1P</name>
              <bitRange>[10:10]</bitRange>
            </field>
            <field>
              <name>BKCMP2P</name>
              <bitRange>[11:11]</bitRange>
            </field>
          </fields>
        </register>
        <register>
          <name>TIMXDCR</name>
          <addressOffset>0x3DC</addressOffset>
          <fields>
            <field>
              <name>DBA</name>
              <bitRange>[4:0]</bitRange>
            </field>
            <field>
              <name>DBL</name>
              <bitRange>[12:8]</bitRange>
            </field>
          </fields>
        </register>
        <register>
          <name>DMAR</name>
          <description>desc DMAR</description>
          <addressOffset>0x3E0</addressOffset>
          <fields>
            <field>
              <name>DMAB</name>
              <bitRange>[31:0]</bitRange>
            </field>
          </fields>
        </register>
      </registers>
    </peripheral>
    <peripheral derivedFrom="TIM16">
      <name>TIM17</name>
      <baseAddress>0x40014800</baseAddress>
      <interrupt>
        <name>TIM17</name>
        <description>TIM17 global Interrupt</description>
        <value>22</value>
      </interrupt>
    </peripheral>
    <peripheral>
      <name>TK</name>
      <baseAddress>0x40012800</baseAddress>
      <addressBlock>
        <offset>0x0</offset>
        <size>0x110</size>
        <usage>registers</usage>
      </addressBlock>
      <registers>
        <register>
          <name>CR1</name>
          <addressOffset>0x0</addressOffset>
          <fields>
            <field>
              <name>EN</name>
              <bitRange>[0:0]</bitRange>
            </field>
            <field>
              <name>EXTCMODEN</name>
              <bitRange>[3:3]</bitRange>
            </field>
            <field>
              <name>ICOPA</name>
              <bitRange>[4:4]</bitRange>
            </field>
            <field>
              <name>COPAMODE</name>
              <bitRange>[5:5]</bitRange>
            </field>
            <field>
              <name>COPADATA</name>
              <bitRange>[7:6]</bitRange>
              <enumeratedValues>
                <enumeratedValue>
                  <name>0</name>
                  <value>1</value>
                </enumeratedValue>
                <enumeratedValue>
                  <name>1</name>
                  <value>2</value>
                </enumeratedValue>
              </enumeratedValues>
            </field>
            <field>
              <name>VCC1SEL</name>
              <bitRange>[13:11]</bitRange>
              <enumeratedValues>
                <enumeratedValue>
                  <name>0</name>
                  <value>1</value>
                </enumeratedValue>
                <enumeratedValue>
                  <name>1</name>
                  <value>2</value>
                </enumeratedValue>
                <enumeratedValue>
                  <name>2</name>
                  <value>4</value>
                </enumeratedValue>
              </enumeratedValues>
            </field>
            <field>
              <name>MIDACSTEP</name>
              <bitRange>[14:14]</bitRange>
            </field>
            <field>
              <name>SIDACSTEP</name>
              <bitRange>[15:15]</bitRange>
            </field>
            <field>
              <name>CFT</name>
              <bitRange>[18:16]</bitRange>
              <enumeratedValues>
                <enumeratedValue>
                  <name>0</name>
                  <value>1</value>
                </enumeratedValue>
                <enumeratedValue>
                  <name>1</name>
                  <value>2</value>
                </enumeratedValue>
                <enumeratedValue>
                  <name>2</name>
                  <value>4</value>
                </enumeratedValue>
              </enumeratedValues>
            </field>
            <field>
              <name>INTCMODEN</name>
              <bitRange>[20:20]</bitRange>
            </field>
            <field>
              <name>CMPHYSEN</name>
              <description>Comparetor Hysteresis Enable</description>
              <bitRange>[21:21]</bitRange>
            </field>
            <field>
              <name>BUFFEREN</name>
              <description>Buffer Enable</description>
              <bitRange>[22:22]</bitRange>
            </field>
            <field>
              <name>DIV</name>
              <description>TK_CLK Division</description>
              <bitRange>[26:24]</bitRange>
              <enumeratedValues>
                <enumeratedValue>
                  <name>0</name>
                  <value>1</value>
                </enumeratedValue>
                <enumeratedValue>
                  <name>1</name>
                  <value>2</value>
                </enumeratedValue>
                <enumeratedValue>
                  <name>2</name>
                  <value>4</value>
                </enumeratedValue>
              </enumeratedValues>
            </field>
            <field>
              <name>STDIV</name>
              <description>ST_CLK Division</description>
              <bitRange>[30:27]</bitRange>
              <enumeratedValues>
                <enumeratedValue>
                  <name>0</name>
                  <value>1</value>
                </enumeratedValue>
                <enumeratedValue>
                  <name>1</name>
                  <value>2</value>
                </enumeratedValue>
                <enumeratedValue>
                  <name>2</name>
                  <value>4</value>
                </enumeratedValue>
                <enumeratedValue>
                  <name>3</name>
                  <value>8</value>
                </enumeratedValue>
              </enumeratedValues>
            </field>
            <field>
              <name>INTEREN</name>
              <description>Internal Enable</description>
              <bitRange>[31:31]</bitRange>
            </field>
          </fields>
        </register>
        <register>
          <name>CR2</name>
          <addressOffset>0x4</addressOffset>
          <fields>
            <field>
              <name>START</name>
              <bitRange>[0:0]</bitRange>
            </field>
            <field>
              <name>RSTB</name>
              <bitRange>[1:1]</bitRange>
            </field>
            <field>
              <name>SWCTRL</name>
              <bitRange>[2:2]</bitRange>
            </field>
            <field>
              <name>CMODCHRG</name>
              <bitRange>[3:3]</bitRange>
            </field>
            <field>
              <name>CMODISCH</name>
              <bitRange>[4:4]</bitRange>
            </field>
            <field>
              <name>MIDACEN</name>
              <bitRange>[5:5]</bitRange>
            </field>
            <field>
              <name>SIDACEN</name>
              <bitRange>[6:6]</bitRange>
            </field>
            <field>
              <name>PWMM</name>
              <bitRange>[8:8]</bitRange>
            </field>
            <field>
              <name>CTRLSOURCE</name>
              <bitRange>[9:9]</bitRange>
            </field>
            <field>
              <name>LPABNORMAL</name>
              <bitRange>[10:10]</bitRange>
            </field>
            <field>
              <name>SHORTSW_NUM</name>
              <bitRange>[13:12]</bitRange>
              <enumeratedValues>
                <enumeratedValue>
                  <name>0</name>
                  <value>1</value>
                </enumeratedValue>
                <enumeratedValue>
                  <name>1</name>
                  <value>2</value>
                </enumeratedValue>
              </enumeratedValues>
            </field>
            <field>
              <name>LPEN</name>
              <bitRange>[14:14]</bitRange>
            </field>
            <field>
              <name>KVREF</name>
              <bitRange>[17:16]</bitRange>
              <enumeratedValues>
                <enumeratedValue>
                  <name>0</name>
                  <value>1</value>
                </enumeratedValue>
                <enumeratedValue>
                  <name>1</name>
                  <value>2</value>
                </enumeratedValue>
              </enumeratedValues>
            </field>
            <field>
              <name>LFSRW</name>
              <bitRange>[23:20]</bitRange>
              <enumeratedValues>
                <enumeratedValue>
                  <name>0</name>
                  <value>1</value>
                </enumeratedValue>
                <enumeratedValue>
                  <name>1</name>
                  <value>2</value>
                </enumeratedValue>
                <enumeratedValue>
                  <name>2</name>
                  <value>4</value>
                </enumeratedValue>
                <enumeratedValue>
                  <name>3</name>
                  <value>8</value>
                </enumeratedValue>
              </enumeratedValues>
            </field>
            <field>
              <name>CMODCOPA</name>
              <bitRange>[29:29]</bitRange>
            </field>
            <field>
              <name>CMODCS</name>
              <bitRange>[30:30]</bitRange>
            </field>
            <field>
              <name>CMODEN</name>
              <bitRange>[31:31]</bitRange>
            </field>
          </fields>
        </register>
        <register>
          <name>IDACR</name>
          <addressOffset>0x8</addressOffset>
          <fields>
            <field>
              <name>MIDAC</name>
              <bitRange>[7:0]</bitRange>
            </field>
            <field>
              <name>SIDAC</name>
              <bitRange>[23:16]</bitRange>
            </field>
          </fields>
        </register>
        <register>
          <name>KR</name>
          <addressOffset>0xC</addressOffset>
          <fields>
            <field>
              <name>KEN</name>
              <bitRange>[31:0]</bitRange>
            </field>
          </fields>
        </register>
        <register>
          <name>CSR</name>
          <addressOffset>0x10</addressOffset>
          <fields>
            <field>
              <name>CHS</name>
              <bitRange>[31:0]</bitRange>
            </field>
          </fields>
        </register>
        <register>
          <name>UCR</name>
          <addressOffset>0x14</addressOffset>
          <fields>
            <field>
              <name>COPAMODEIO</name>
              <bitRange>[31:0]</bitRange>
            </field>
          </fields>
        </register>
        <register>
          <name>STR</name>
          <addressOffset>0x18</addressOffset>
          <fields>
            <field>
              <name>SETTIME</name>
              <bitRange>[9:0]</bitRange>
            </field>
          </fields>
        </register>
        <register>
          <name>WR</name>
          <addressOffset>0x20</addressOffset>
          <fields>
            <field>
              <name>WIN</name>
              <bitRange>[15:0]</bitRange>
            </field>
          </fields>
        </register>
        <register>
          <name>SDR</name>
          <addressOffset>0x24</addressOffset>
          <fields>
            <field>
              <name>SWDIV</name>
              <bitRange>[8:0]</bitRange>
            </field>
          </fields>
        </register>
        <register>
          <name>PRSR</name>
          <addressOffset>0x28</addressOffset>
          <fields>
            <field>
              <name>LFSRP</name>
              <bitRange>[15:0]</bitRange>
            </field>
            <field>
              <name>SEED</name>
              <bitRange>[31:16]</bitRange>
            </field>
          </fields>
        </register>
        <register>
          <name>DR</name>
          <addressOffset>0x2C</addressOffset>
          <fields>
            <field>
              <name>DATA</name>
              <bitRange>[15:0]</bitRange>
              <access>read-only</access>
            </field>
          </fields>
        </register>
        <register>
          <name>SR</name>
          <addressOffset>0x30</addressOffset>
          <fields>
            <field>
              <name>SENSEDONE</name>
              <bitRange>[0:0]</bitRange>
              <access>read-only</access>
            </field>
            <field>
              <name>CMPOUT</name>
              <bitRange>[1:1]</bitRange>
              <access>read-only</access>
            </field>
            <field>
              <name>SHORTSWERR</name>
              <bitRange>[2:2]</bitRange>
              <access>read-only</access>
            </field>
          </fields>
        </register>
        <register>
          <name>IER</name>
          <addressOffset>0x34</addressOffset>
          <fields>
            <field>
              <name>EVTINTEN</name>
              <bitRange>[0:0]</bitRange>
            </field>
            <field>
              <name>ERRINTEN</name>
              <bitRange>[1:1]</bitRange>
            </field>
          </fields>
        </register>
        <register>
          <name>ICR</name>
          <addressOffset>0x38</addressOffset>
          <fields>
            <field>
              <name>EVTINTCLR</name>
              <bitRange>[0:0]</bitRange>
            </field>
            <field>
              <name>ERRINTCLR</name>
              <bitRange>[1:1]</bitRange>
            </field>
          </fields>
        </register>
        <register>
          <name>CDR</name>
          <addressOffset>0x3C</addressOffset>
          <fields>
            <field>
              <name>CDATA</name>
              <bitRange>[15:0]</bitRange>
            </field>
          </fields>
        </register>
        <register>
          <name>LPDR</name>
          <addressOffset>0x40</addressOffset>
          <fields>
            <field>
              <name>NORMALDELTA</name>
              <bitRange>[9:0]</bitRange>
            </field>
            <field>
              <name>ABNORMALDELTA</name>
              <bitRange>[25:16]</bitRange>
            </field>
          </fields>
        </register>
        <register>
          <name>LPTR</name>
          <addressOffset>0x44</addressOffset>
          <fields>
            <field>
              <name>LPWAIT</name>
              <bitRange>[6:0]</bitRange>
            </field>
          </fields>
        </register>
        <register>
          <name>OPR</name>
          <addressOffset>0x48</addressOffset>
          <fields>
            <field>
              <name>OP</name>
              <bitRange>[5:0]</bitRange>
              <enumeratedValues>
                <enumeratedValue>
                  <name>0</name>
                  <value>1</value>
                </enumeratedValue>
                <enumeratedValue>
                  <name>1</name>
                  <value>2</value>
                </enumeratedValue>
                <enumeratedValue>
                  <name>2</name>
                  <value>4</value>
                </enumeratedValue>
                <enumeratedValue>
                  <name>3</name>
                  <value>8</value>
                </enumeratedValue>
                <enumeratedValue>
                  <name>4</name>
                  <value>16</value>
                </enumeratedValue>
                <enumeratedValue>
                  <name>5</name>
                  <value>32</value>
                </enumeratedValue>
              </enumeratedValues>
            </field>
          </fields>
        </register>
        <register>
          <name>TR</name>
          <addressOffset>0x100</addressOffset>
          <fields>
            <field>
              <name>TMODE</name>
              <bitRange>[2:0]</bitRange>
              <enumeratedValues>
                <enumeratedValue>
                  <name>0</name>
                  <value>1</value>
                </enumeratedValue>
                <enumeratedValue>
                  <name>1</name>
                  <value>2</value>
                </enumeratedValue>
                <enumeratedValue>
                  <name>2</name>
                  <value>4</value>
                </enumeratedValue>
              </enumeratedValues>
            </field>
            <field>
              <name>DBGSEL</name>
              <bitRange>[19:16]</bitRange>
              <enumeratedValues>
                <enumeratedValue>
                  <name>0</name>
                  <value>1</value>
                </enumeratedValue>
                <enumeratedValue>
                  <name>1</name>
                  <value>2</value>
                </enumeratedValue>
                <enumeratedValue>
                  <name>2</name>
                  <value>4</value>
                </enumeratedValue>
                <enumeratedValue>
                  <name>3</name>
                  <value>8</value>
                </enumeratedValue>
              </enumeratedValues>
            </field>
          </fields>
        </register>
        <register>
          <name>DDR</name>
          <addressOffset>0x104</addressOffset>
          <fields>
            <field>
              <name>SHORTSW_DATA</name>
              <bitRange>[9:0]</bitRange>
              <access>read-only</access>
            </field>
          </fields>
        </register>
      </registers>
    </peripheral>
    <peripheral>
      <name>UART1</name>
      <groupName>UART</groupName>
      <baseAddress>0x40004800</baseAddress>
      <addressBlock>
        <offset>0x0</offset>
        <size>0x30</size>
        <usage>registers</usage>
      </addressBlock>
      <registers>
        <register>
          <name>DR</name>
          <addressOffset>0x0</addressOffset>
          <fields>
            <field>
              <name>DR</name>
              <description>Receive/send data register</description>
              <bitRange>[8:0]</bitRange>
            </field>
          </fields>
        </register>
        <register>
          <name>BRR</name>
          <addressOffset>0x4</addressOffset>
          <fields>
            <field>
              <name>BRR</name>
              <description>Baud rate register</description>
              <bitRange>[15:0]</bitRange>
            </field>
          </fields>
        </register>
        <register>
          <name>SR</name>
          <addressOffset>0x10</addressOffset>
          <fields>
            <field>
              <name>RXNE</name>
              <description>Receive register not empty</description>
              <bitRange>[0:0]</bitRange>
              <access>read-only</access>
            </field>
            <field>
              <name>ORE</name>
              <description>Overrun error bit</description>
              <bitRange>[1:1]</bitRange>
            </field>
            <field>
              <name>PE</name>
              <description>Parity Error bit</description>
              <bitRange>[2:2]</bitRange>
            </field>
            <field>
              <name>FE</name>
              <description>Framing Error bit</description>
              <bitRange>[3:3]</bitRange>
            </field>
            <field>
              <name>BRI</name>
              <description>Break Interrupt bit</description>
              <bitRange>[4:4]</bitRange>
            </field>
            <field>
              <name>TDRE</name>
              <description>Transmit Holding Register Empty bit</description>
              <bitRange>[5:5]</bitRange>
              <access>read-only</access>
            </field>
            <field>
              <name>TXE</name>
              <description>Transmitter Empty bit</description>
              <bitRange>[6:6]</bitRange>
              <access>read-only</access>
            </field>
            <field>
              <name>ADDR_RCVD</name>
              <description>Address Received Bit</description>
              <bitRange>[8:8]</bitRange>
            </field>
            <field>
              <name>BUSY</name>
              <description>UART Busy</description>
              <bitRange>[9:9]</bitRange>
              <access>read-only</access>
            </field>
            <field>
              <name>BUSY_ERR</name>
              <description>Busy Detect Error</description>
              <bitRange>[10:10]</bitRange>
            </field>
          </fields>
        </register>
        <register>
          <name>CR1</name>
          <addressOffset>0x14</addressOffset>
          <fields>
            <field>
              <name>M</name>
              <description>Data Length Select</description>
              <bitRange>[1:0]</bitRange>
              <enumeratedValues>
                <enumeratedValue>
                  <name>0</name>
                  <value>1</value>
                </enumeratedValue>
                <enumeratedValue>
                  <name>1</name>
                  <value>2</value>
                </enumeratedValue>
              </enumeratedValues>
            </field>
            <field>
              <name>STOP</name>
              <description>Number of stop bits</description>
              <bitRange>[2:2]</bitRange>
            </field>
            <field>
              <name>PCE</name>
              <description>Parity Enable</description>
              <bitRange>[3:3]</bitRange>
            </field>
            <field>
              <name>PS</name>
              <description>Even Parity Select</description>
              <bitRange>[4:4]</bitRange>
            </field>
            <field>
              <name>SP</name>
              <description>Stick Parity</description>
              <bitRange>[5:5]</bitRange>
            </field>
            <field>
              <name>SBK</name>
              <description>Send Break</description>
              <bitRange>[6:6]</bitRange>
            </field>
            <field>
              <name>SWAP</name>
              <description>TX/RX pin swap</description>
              <bitRange>[8:8]</bitRange>
            </field>
            <field>
              <name>MSBFIRST</name>
              <description>MSB first mode</description>
              <bitRange>[9:9]</bitRange>
            </field>
          </fields>
        </register>
        <register>
          <name>CR2</name>
          <addressOffset>0x18</addressOffset>
          <fields>
            <field>
              <name>RXNEIE</name>
              <description>Enable Received Data Available Interrupt</description>
              <bitRange>[0:0]</bitRange>
            </field>
            <field>
              <name>TDREIE</name>
              <description>Enable Transmit Holding Register Empty Interrupt</description>
              <bitRange>[1:1]</bitRange>
            </field>
            <field>
              <name>LSIE</name>
              <description>Enable Receiver Line Status Interrupt</description>
              <bitRange>[2:2]</bitRange>
            </field>
            <field>
              <name>BUSYERRIE</name>
              <description>Enable Busyerr state interruption</description>
              <bitRange>[3:3]</bitRange>
            </field>
            <field>
              <name>TXEIE</name>
              <description>Enable tx empty interruption</description>
              <bitRange>[4:4]</bitRange>
            </field>
          </fields>
        </register>
        <register>
          <name>CR3</name>
          <addressOffset>0x1C</addressOffset>
          <fields>
            <field>
              <name>M_E</name>
              <description>Extension for DLS</description>
              <bitRange>[0:0]</bitRange>
            </field>
            <field>
              <name>ADDR_MATCH</name>
              <description>Address Match Mode</description>
              <bitRange>[1:1]</bitRange>
            </field>
            <field>
              <name>SEND_ADDR</name>
              <description>Send address control bit</description>
              <bitRange>[2:2]</bitRange>
            </field>
            <field>
              <name>TX_MODE</name>
              <description>Transmit mode control bit</description>
              <bitRange>[3:3]</bitRange>
            </field>
            <field>
              <name>DMAR</name>
              <description>DMA receive enable</description>
              <bitRange>[4:4]</bitRange>
            </field>
            <field>
              <name>DMAT</name>
              <description>DMA transmit enable</description>
              <bitRange>[5:5]</bitRange>
            </field>
            <field>
              <name>DMA_SOFT_ACK</name>
              <description>DMA software ack</description>
              <bitRange>[6:6]</bitRange>
            </field>
          </fields>
        </register>
        <register>
          <name>RAR</name>
          <addressOffset>0x20</addressOffset>
          <fields>
            <field>
              <name>RAR</name>
              <description>Receive address matching register</description>
              <bitRange>[7:0]</bitRange>
            </field>
          </fields>
        </register>
        <register>
          <name>TAR</name>
          <addressOffset>0x24</addressOffset>
          <fields>
            <field>
              <name>TAR</name>
              <description>Transmit address matching register</description>
              <bitRange>[7:0]</bitRange>
            </field>
          </fields>
        </register>
        <register>
          <name>BRRF</name>
          <addressOffset>0x28</addressOffset>
          <fields>
            <field>
              <name>BRRF</name>
              <description>Baud rate fractional register</description>
              <bitRange>[3:0]</bitRange>
              <enumeratedValues>
                <enumeratedValue>
                  <name>0</name>
                  <value>1</value>
                </enumeratedValue>
                <enumeratedValue>
                  <name>1</name>
                  <value>2</value>
                </enumeratedValue>
                <enumeratedValue>
                  <name>2</name>
                  <value>4</value>
                </enumeratedValue>
                <enumeratedValue>
                  <name>3</name>
                  <value>8</value>
                </enumeratedValue>
              </enumeratedValues>
            </field>
          </fields>
        </register>
      </registers>
    </peripheral>
    <peripheral derivedFrom="UART1">
      <name>UART2</name>
      <baseAddress>0x40004C00</baseAddress>
    </peripheral>
    <peripheral>
      <name>USART1</name>
      <description>Universal synchronous asynchronous receiver transmitter</description>
      <groupName>USART</groupName>
      <baseAddress>0x40013800</baseAddress>
      <addressBlock>
        <offset>0x0</offset>
        <size>0x400</size>
        <usage>registers</usage>
      </addressBlock>
      <interrupt>
        <name>USART1</name>
        <description>USART1 global Interrupt</description>
        <value>27</value>
      </interrupt>
      <registers>
        <register>
          <name>SR</name>
          <description>desc SR</description>
          <addressOffset>0x0</addressOffset>
          <fields>
            <field>
              <name>PE</name>
              <description>Parity error</description>
              <bitRange>[0:0]</bitRange>
              <access>read-only</access>
            </field>
            <field>
              <name>FE</name>
              <description>Framing error</description>
              <bitRange>[1:1]</bitRange>
              <access>read-only</access>
            </field>
            <field>
              <name>NE</name>
              <description>Noise error flag</description>
              <bitRange>[2:2]</bitRange>
              <access>read-only</access>
            </field>
            <field>
              <name>ORE</name>
              <description>overrun error</description>
              <bitRange>[3:3]</bitRange>
              <access>read-only</access>
            </field>
            <field>
              <name>IDLE</name>
              <description>idle</description>
              <bitRange>[4:4]</bitRange>
              <access>read-only</access>
            </field>
            <field>
              <name>RXNE</name>
              <description>Read data register not empty</description>
              <bitRange>[5:5]</bitRange>
              <access>read-only</access>
            </field>
            <field>
              <name>TC</name>
              <description>Transmission complete</description>
              <bitRange>[6:6]</bitRange>
              <access>read-only</access>
            </field>
            <field>
              <name>TXE</name>
              <description>Transmit data register empty</description>
              <bitRange>[7:7]</bitRange>
              <access>read-only</access>
            </field>
            <field>
              <name>LBD</name>
              <description>LIN break detection flag</description>
              <bitRange>[8:8]</bitRange>
            </field>
            <field>
              <name>CTS</name>
              <description>cts flag</description>
              <bitRange>[9:9]</bitRange>
            </field>
            <field>
              <name>ABRF</name>
              <description>auto baud rate flag</description>
              <bitRange>[10:10]</bitRange>
              <access>read-only</access>
            </field>
            <field>
              <name>ABRE</name>
              <description>auto baud rateerror</description>
              <bitRange>[11:11]</bitRange>
              <access>read-only</access>
            </field>
            <field>
              <name>ABRQ</name>
              <description>auto baud rate req</description>
              <bitRange>[12:12]</bitRange>
              <access>read-only</access>
            </field>
            <field>
              <name>EOBF</name>
              <description>end of block flag</description>
              <bitRange>[18:18]</bitRange>
            </field>
            <field>
              <name>RTOF</name>
              <description>rto flag</description>
              <bitRange>[19:19]</bitRange>
            </field>
            <field>
              <name>TXPE</name>
              <bitRange>[20:20]</bitRange>
            </field>
            <field>
              <name>RXBUSY</name>
              <bitRange>[21:21]</bitRange>
              <access>read-only</access>
            </field>
            <field>
              <name>TXBUSY</name>
              <bitRange>[22:22]</bitRange>
              <access>read-only</access>
            </field>
            <field>
              <name>WAIT_RPT</name>
              <bitRange>[23:23]</bitRange>
              <access>read-only</access>
            </field>
            <field>
              <name>TXLSEF</name>
              <bitRange>[31:31]</bitRange>
              <access>read-only</access>
            </field>
          </fields>
        </register>
        <register>
          <name>DR</name>
          <description>desc DR</description>
          <addressOffset>0x4</addressOffset>
          <fields>
            <field>
              <name>DR</name>
              <description>dr</description>
              <bitRange>[8:0]</bitRange>
            </field>
          </fields>
        </register>
        <register>
          <name>BRR</name>
          <description>desc BRR</description>
          <addressOffset>0x8</addressOffset>
          <fields>
            <field>
              <name>DIV_FRACTION</name>
              <description>DIV_Fraction</description>
              <bitRange>[3:0]</bitRange>
              <enumeratedValues>
                <enumeratedValue>
                  <name>0</name>
                  <value>1</value>
                </enumeratedValue>
                <enumeratedValue>
                  <name>1</name>
                  <value>2</value>
                </enumeratedValue>
                <enumeratedValue>
                  <name>2</name>
                  <value>4</value>
                </enumeratedValue>
                <enumeratedValue>
                  <name>3</name>
                  <value>8</value>
                </enumeratedValue>
              </enumeratedValues>
            </field>
            <field>
              <name>DIV_MANTISSA</name>
              <description>DIV_Mantissa</description>
              <bitRange>[15:4]</bitRange>
            </field>
          </fields>
        </register>
        <register>
          <name>CR1</name>
          <description>desc CR1</description>
          <addressOffset>0xC</addressOffset>
          <fields>
            <field>
              <name>SBK</name>
              <description>Send break</description>
              <bitRange>[0:0]</bitRange>
            </field>
            <field>
              <name>RWU</name>
              <description>Receiver wakeup</description>
              <bitRange>[1:1]</bitRange>
            </field>
            <field>
              <name>RE</name>
              <description>Receiver enable</description>
              <bitRange>[2:2]</bitRange>
            </field>
            <field>
              <name>TE</name>
              <description>Transmitter enable</description>
              <bitRange>[3:3]</bitRange>
            </field>
            <field>
              <name>IDLEIE</name>
              <description>IDLE interrupt enable</description>
              <bitRange>[4:4]</bitRange>
            </field>
            <field>
              <name>RXNEIE</name>
              <description>RXNE interrupt enable</description>
              <bitRange>[5:5]</bitRange>
            </field>
            <field>
              <name>TCIE</name>
              <description>send complete int enable</description>
              <bitRange>[6:6]</bitRange>
            </field>
            <field>
              <name>TXEIE</name>
              <description>txe</description>
              <bitRange>[7:7]</bitRange>
            </field>
            <field>
              <name>PEIE</name>
              <description>PE interrupt enable</description>
              <bitRange>[8:8]</bitRange>
            </field>
            <field>
              <name>PS</name>
              <description>Parity selection</description>
              <bitRange>[9:9]</bitRange>
            </field>
            <field>
              <name>PCE</name>
              <description>Parity control enable</description>
              <bitRange>[10:10]</bitRange>
            </field>
            <field>
              <name>WAKE</name>
              <description>Wakeup method</description>
              <bitRange>[11:11]</bitRange>
            </field>
            <field>
              <name>M</name>
              <description>word length</description>
              <bitRange>[12:12]</bitRange>
            </field>
            <field>
              <name>UE</name>
              <description>uesart enable</description>
              <bitRange>[13:13]</bitRange>
            </field>
            <field>
              <name>MSBFIRST</name>
              <description>msbfirst</description>
              <bitRange>[15:15]</bitRange>
            </field>
            <field>
              <name>SWAP</name>
              <description>swap</description>
              <bitRange>[18:18]</bitRange>
            </field>
            <field>
              <name>DATAINV</name>
              <description>data inverse</description>
              <bitRange>[27:27]</bitRange>
            </field>
          </fields>
        </register>
        <register>
          <name>CR2</name>
          <description>desc CR2</description>
          <addressOffset>0x10</addressOffset>
          <fields>
            <field>
              <name>ADD</name>
              <description>mute addr</description>
              <bitRange>[3:0]</bitRange>
              <enumeratedValues>
                <enumeratedValue>
                  <name>0</name>
                  <value>1</value>
                </enumeratedValue>
                <enumeratedValue>
                  <name>1</name>
                  <value>2</value>
                </enumeratedValue>
                <enumeratedValue>
                  <name>2</name>
                  <value>4</value>
                </enumeratedValue>
                <enumeratedValue>
                  <name>3</name>
                  <value>8</value>
                </enumeratedValue>
              </enumeratedValues>
            </field>
            <field>
              <name>LBDL</name>
              <description>LIN break detection length</description>
              <bitRange>[5:5]</bitRange>
            </field>
            <field>
              <name>LBDIE</name>
              <description>lin break enable</description>
              <bitRange>[6:6]</bitRange>
            </field>
            <field>
              <name>LBCL</name>
              <description>lbcl</description>
              <bitRange>[8:8]</bitRange>
            </field>
            <field>
              <name>CPHA</name>
              <description>cpha</description>
              <bitRange>[9:9]</bitRange>
            </field>
            <field>
              <name>CPOL</name>
              <description>cpol</description>
              <bitRange>[10:10]</bitRange>
            </field>
            <field>
              <name>CLKEN</name>
              <description>clk en</description>
              <bitRange>[11:11]</bitRange>
            </field>
            <field>
              <name>STOP</name>
              <description>stop bit</description>
              <bitRange>[13:12]</bitRange>
              <enumeratedValues>
                <enumeratedValue>
                  <name>0</name>
                  <value>1</value>
                </enumeratedValue>
                <enumeratedValue>
                  <name>1</name>
                  <value>2</value>
                </enumeratedValue>
              </enumeratedValues>
            </field>
            <field>
              <name>LINEN</name>
              <description>lin enable</description>
              <bitRange>[14:14]</bitRange>
            </field>
            <field>
              <name>RTOEN</name>
              <description>Receiver timeout enable</description>
              <bitRange>[25:25]</bitRange>
            </field>
            <field>
              <name>ERSW</name>
              <description>error select width</description>
              <bitRange>[27:26]</bitRange>
              <enumeratedValues>
                <enumeratedValue>
                  <name>0</name>
                  <value>1</value>
                </enumeratedValue>
                <enumeratedValue>
                  <name>1</name>
                  <value>2</value>
                </enumeratedValue>
              </enumeratedValues>
            </field>
            <field>
              <name>REP_T</name>
              <description>repeat times</description>
              <bitRange>[28:28]</bitRange>
            </field>
            <field>
              <name>TREPEN</name>
              <description>tx repeat enable</description>
              <bitRange>[29:29]</bitRange>
            </field>
            <field>
              <name>RREPEN</name>
              <bitRange>[30:30]</bitRange>
            </field>
          </fields>
        </register>
        <register>
          <name>CR3</name>
          <description>desc CR3</description>
          <addressOffset>0x14</addressOffset>
          <fields>
            <field>
              <name>EIE</name>
              <description>error int enable</description>
              <bitRange>[0:0]</bitRange>
            </field>
            <field>
              <name>IREN</name>
              <description>iren enable</description>
              <bitRange>[1:1]</bitRange>
            </field>
            <field>
              <name>IRLP</name>
              <description>idra lowpower</description>
              <bitRange>[2:2]</bitRange>
            </field>
            <field>
              <name>HDSEL</name>
              <description>hdsel</description>
              <bitRange>[3:3]</bitRange>
            </field>
            <field>
              <name>NACK</name>
              <description>scen nack enable</description>
              <bitRange>[4:4]</bitRange>
            </field>
            <field>
              <name>SCEN</name>
              <description>scen enable</description>
              <bitRange>[5:5]</bitRange>
            </field>
            <field>
              <name>DMAR</name>
              <description>dma rx enable</description>
              <bitRange>[6:6]</bitRange>
            </field>
            <field>
              <name>DMAT</name>
              <description>dma tx enable</description>
              <bitRange>[7:7]</bitRange>
            </field>
            <field>
              <name>RTSE</name>
              <description>rts enable</description>
              <bitRange>[8:8]</bitRange>
            </field>
            <field>
              <name>CTSE</name>
              <description>cts enable</description>
              <bitRange>[9:9]</bitRange>
            </field>
            <field>
              <name>CTSIE</name>
              <description>cts int enable</description>
              <bitRange>[10:10]</bitRange>
            </field>
            <field>
              <name>OVER8</name>
              <description>oversampling</description>
              <bitRange>[11:11]</bitRange>
            </field>
            <field>
              <name>ABREN</name>
              <description>autobaud enable</description>
              <bitRange>[12:12]</bitRange>
            </field>
            <field>
              <name>ABRMOD</name>
              <description>auto baud mod</description>
              <bitRange>[14:13]</bitRange>
              <enumeratedValues>
                <enumeratedValue>
                  <name>0</name>
                  <value>1</value>
                </enumeratedValue>
                <enumeratedValue>
                  <name>1</name>
                  <value>2</value>
                </enumeratedValue>
              </enumeratedValues>
            </field>
            <field>
              <name>RTOIE</name>
              <description>rto int enable</description>
              <bitRange>[29:29]</bitRange>
            </field>
            <field>
              <name>EOBIE</name>
              <description>eob int enable</description>
              <bitRange>[30:30]</bitRange>
            </field>
            <field>
              <name>TXLSEIE</name>
              <description>tx register empty int enable</description>
              <bitRange>[31:31]</bitRange>
            </field>
          </fields>
        </register>
        <register>
          <name>GTPR</name>
          <description>desc GTPR</description>
          <addressOffset>0x18</addressOffset>
          <fields>
            <field>
              <name>PSC</name>
              <description>Prescaler value</description>
              <bitRange>[7:0]</bitRange>
            </field>
            <field>
              <name>GT</name>
              <description>Guard time value</description>
              <bitRange>[15:8]</bitRange>
            </field>
          </fields>
        </register>
        <register>
          <name>RTOR</name>
          <addressOffset>0x1C</addressOffset>
          <fields>
            <field>
              <name>RTO</name>
              <description>receive timeout</description>
              <bitRange>[23:0]</bitRange>
            </field>
            <field>
              <name>BLEN</name>
              <description>blocken length</description>
              <bitRange>[31:24]</bitRange>
            </field>
          </fields>
        </register>
      </registers>
    </peripheral>
    <peripheral derivedFrom="USART1">
      <name>USART2</name>
      <baseAddress>0x40004400</baseAddress>
      <interrupt>
        <name>USART2</name>
        <description>USART2 global Interrupt</description>
        <value>28</value>
      </interrupt>
    </peripheral>
    <peripheral>
      <name>VREFBUF</name>
      <baseAddress>0x40010800</baseAddress>
      <addressBlock>
        <offset>0x0</offset>
        <size>0x10</size>
        <usage>registers</usage>
      </addressBlock>
      <registers>
        <register>
          <name>CR</name>
          <addressOffset>0x0</addressOffset>
          <fields>
            <field>
              <name>VREFBUF_OUT_SEL</name>
              <bitRange>[2:0]</bitRange>
              <enumeratedValues>
                <enumeratedValue>
                  <name>0</name>
                  <value>1</value>
                </enumeratedValue>
                <enumeratedValue>
                  <name>1</name>
                  <value>2</value>
                </enumeratedValue>
                <enumeratedValue>
                  <name>2</name>
                  <value>4</value>
                </enumeratedValue>
              </enumeratedValues>
            </field>
            <field>
              <name>VREFBUF_EN</name>
              <bitRange>[3:3]</bitRange>
            </field>
          </fields>
        </register>
      </registers>
    </peripheral>
    <peripheral>
      <name>WWDG</name>
      <description>Window watchdog</description>
      <baseAddress>0x40002C00</baseAddress>
      <addressBlock>
        <offset>0x0</offset>
        <size>0x400</size>
        <usage>registers</usage>
      </addressBlock>
      <interrupt>
        <name>WWDG</name>
        <description>Window WatchDog Interrupt</description>
        <value>0</value>
      </interrupt>
      <registers>
        <register>
          <name>CR</name>
          <description>Control register (WWDG_CR)</description>
          <addressOffset>0x0</addressOffset>
          <fields>
            <field>
              <name>T</name>
              <description>WWDG counter</description>
              <bitRange>[6:0]</bitRange>
              <enumeratedValues>
                <enumeratedValue>
                  <name>0</name>
                  <value>1</value>
                </enumeratedValue>
                <enumeratedValue>
                  <name>1</name>
                  <value>2</value>
                </enumeratedValue>
                <enumeratedValue>
                  <name>2</name>
                  <value>4</value>
                </enumeratedValue>
                <enumeratedValue>
                  <name>3</name>
                  <value>8</value>
                </enumeratedValue>
                <enumeratedValue>
                  <name>4</name>
                  <value>16</value>
                </enumeratedValue>
                <enumeratedValue>
                  <name>5</name>
                  <value>32</value>
                </enumeratedValue>
                <enumeratedValue>
                  <name>6</name>
                  <value>64</value>
                </enumeratedValue>
              </enumeratedValues>
            </field>
            <field>
              <name>WDGA</name>
              <description>WWDG Activation</description>
              <bitRange>[7:7]</bitRange>
            </field>
          </fields>
        </register>
        <register>
          <name>CFR</name>
          <description>Configuration register (WWDG_CFR)</description>
          <addressOffset>0x4</addressOffset>
          <fields>
            <field>
              <name>W</name>
              <description>window value</description>
              <bitRange>[6:0]</bitRange>
              <enumeratedValues>
                <enumeratedValue>
                  <name>0</name>
                  <value>1</value>
                </enumeratedValue>
                <enumeratedValue>
                  <name>1</name>
                  <value>2</value>
                </enumeratedValue>
                <enumeratedValue>
                  <name>2</name>
                  <value>4</value>
                </enumeratedValue>
                <enumeratedValue>
                  <name>3</name>
                  <value>8</value>
                </enumeratedValue>
                <enumeratedValue>
                  <name>4</name>
                  <value>16</value>
                </enumeratedValue>
                <enumeratedValue>
                  <name>5</name>
                  <value>32</value>
                </enumeratedValue>
                <enumeratedValue>
                  <name>6</name>
                  <value>64</value>
                </enumeratedValue>
              </enumeratedValues>
            </field>
            <field>
              <name>WDGTB</name>
              <description>Time base</description>
              <bitRange>[8:7]</bitRange>
              <enumeratedValues>
                <enumeratedValue>
                  <name>0</name>
                  <value>1</value>
                </enumeratedValue>
                <enumeratedValue>
                  <name>1</name>
                  <value>2</value>
                </enumeratedValue>
              </enumeratedValues>
            </field>
            <field>
              <name>EWI</name>
              <description>Early wakeup interrupt</description>
              <bitRange>[9:9]</bitRange>
            </field>
          </fields>
        </register>
        <register>
          <name>SR</name>
          <description>Status register (WWDG_SR)</description>
          <addressOffset>0x8</addressOffset>
          <size>16</size>
          <fields>
            <field>
              <name>EWIF</name>
              <description>Early wakeup interrupt flag</description>
              <bitRange>[0:0]</bitRange>
            </field>
          </fields>
        </register>
      </registers>
    </peripheral>
  </peripherals>
</device>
